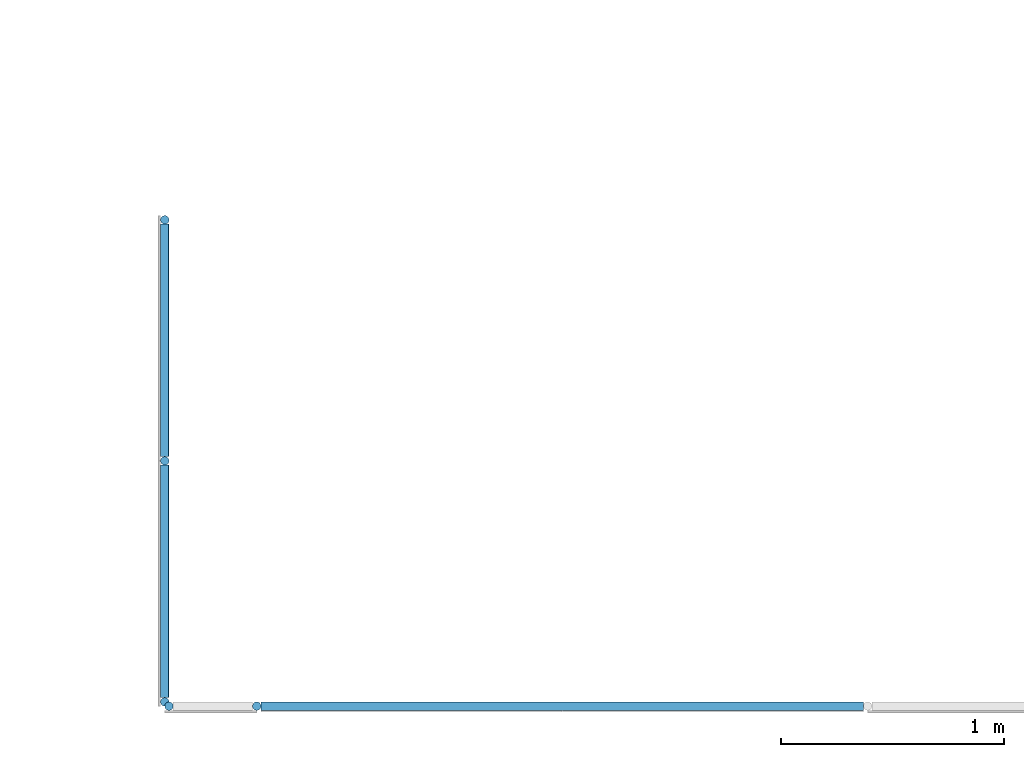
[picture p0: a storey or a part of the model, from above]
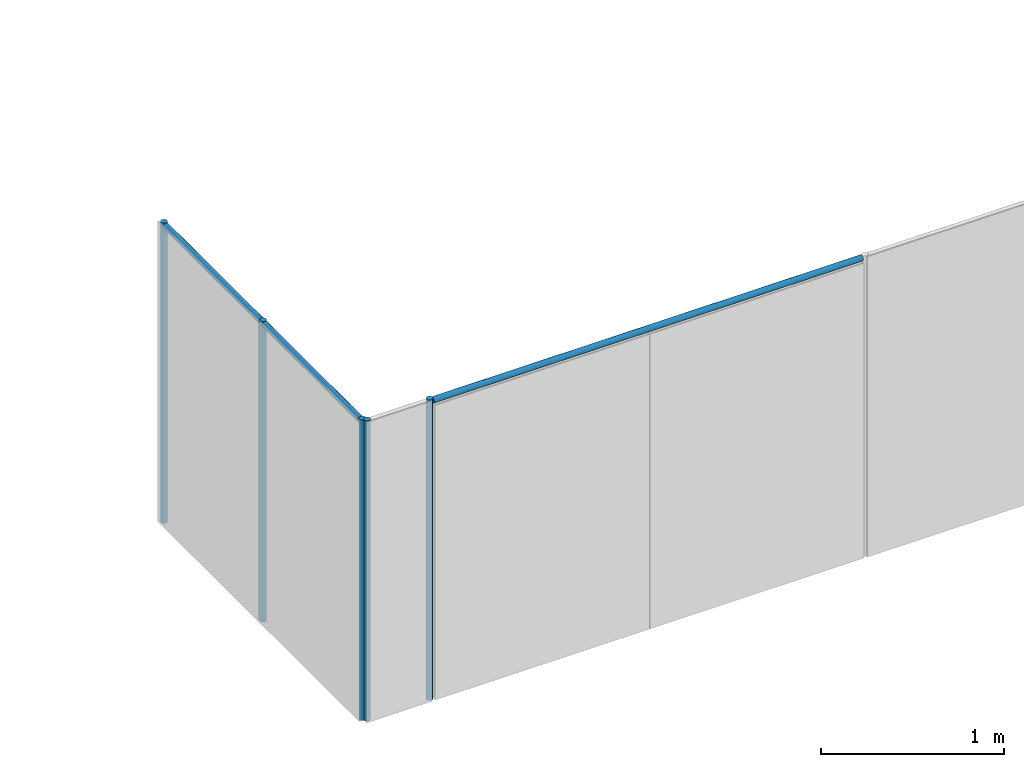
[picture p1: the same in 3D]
Properties of the parts of a building model (IFC2X3), part 1 of 11

# File
Description: ViewDefinition [CoordinationView]
File name: Project Number
Time: 2011-09-06T11:22:43
Written by: Autodesk Revit Architecture 2011 - 1.0
Made in: 20100326_1700 (Solibri IFC Optimizer)

# IfcProject, Project Number
Phase: Project Status

# IfcSite, Default
RefLatitude: 42, 21, 30, 344238; RefLongitude: -71, -3, -35, -194702; RefElevation: 0 m

# IfcBuilding
Pset_BuildingCommon - NumberOfStoreys: 4
PSet_Revit_Other - Project Issue Date: Issue Date; Project Status: Project Status; Client Name: Owner; Project Address: Enter address here; Project Name: Project Name; Project Number: Project Number; Category Description: OmniClass Table 11 Description; Category Code: OmniClass Table 11 Code

# IfcBuildingStorey (4)
PSet_Revit_Type_Dimensions - Automatic Room Computation Height: yes
PSet_Revit_Type_Graphics - Line Weight: 1; Color: 0; Line Pattern: Centre; Symbol: M_Level Head - Circle; Symbol at End 1 Default: no; Symbol at End 2 Default: yes
PSet_Revit_Type_Constraints - Elevation Base: 0
Name | Elevation (m) | Name | PSet_Revit_Constraints, Elevation (m) | Category Code
First Floor | -3.5315e-13 | First Floor | 0 | Floor
Second Floor | 4.57 | Second Floor | 4.57 | Floor
Roof - Main | 9.25 | Roof - Main | 9.25 | Roof
TOF Footing | -1 | TOF Footing | -1 | Site

# IfcSpace (269)
InteriorOrExteriorSpace: INTERNAL
PSet_Revit_Phasing - Phase: New Construction
PSet_Revit_Other - RoomTag: RoomTag
Name | In | LongName = Name | Level | Upper Limit | Limit Offset (m) | Base Offset (m) | GSA BIM Area (m2) = Area (m2) | Number | OmniClass Table 13 Category | Perimeter (m) | Unbounded Height (m) | Volume (m3) | Category Description | Category Code | CirculationZoneName | FireAlarmZoneName | HistoricPreservationZoneName | LightingZoneName | OccupancyZoneName | VentilationZoneName
1AC1 | First Floor | CENTRAL WAITING | First Floor | Second Floor | 0 | 0 | 139.755 | 1AC1 | 13-51 31 11: Waiting Room | 75.3209 | 4.57 | 625.159 | Waiting Room | 13-51 31 11 | Circulation Zone 1A | Fire Alarm Zone 1A | Historic Preservation Zone 1A | Lighting Zone 1A | Occupancy Zone 1A | Ventilation Zone 1A
1DC1 | First Floor | WAITING / ACTIVITY AREA | First Floor | Second Floor | 0 | 0 | 182.28 | 1DC1 | 13-51 31 11: Waiting Room | 80.656 | 4.57 | 814.452 | Waiting Room | 13-51 31 11 | Circulation Zone 1D | Fire Alarm Zone 1D | Historic Preservation Zone 1D | Lighting Zone 1D | Occupancy Zone 1D | Ventilation Zone 1D
2R02 | Second Floor | ROOF | Second Floor | Second Floor | 4 | 0 | 589.756 | 2R02 | 13-81 11 99: Other General Facility Service Spaces | 194.084 | 4 | 2314.97 | Other General Facility Service Spaces | 13-81 11 99 | Circulation Zone 2R | Fire Alarm Zone 2R | Historic Preservation Zone 2R | Lighting Zone 2R | Occupancy Zone 2R | Ventilation Zone 2R
3R01 | Roof - Main | ROOF | Roof - Main | Roof - Main | 4 | 0 | 1568.12 | 3R01 | 13-81 11 99: Other General Facility Service Spaces | 277.051 | 4 | 6257.34 | Other General Facility Service Spaces | 13-81 11 99 | Circulation Zone 3R | Fire Alarm Zone 3R | Historic Preservation Zone 3R | Lighting Zone 3R | Occupancy Zone 3R | Ventilation Zone 3R
1EC1 | First Floor | CORRIDOR | First Floor | First Floor | 2.8 | 0 | 54.6837 | 1EC1 | 13-85 11 11: Corridor | 63.909 | 2.8 | 142.662 | Corridor | 13-85 11 11 | Circulation Zone 1E | Fire Alarm Zone 1E | Historic Preservation Zone 1E | Lighting Zone 1E | Occupancy Zone 1E | Ventilation Zone 1E
2D05 | Second Floor | MAIN MECHANICAL ROOM | Second Floor | Second Floor | 2.8 | 0 | 231.114 | 2D05 | 13-81 21 17: Mechanical Room | 65.482 | 2.8 | 632.921 | Mechanical Room | 13-81 21 17 | Circulation Zone 2D | Fire Alarm Zone 2D | Historic Preservation Zone 2D | Lighting Zone 2D | Occupancy Zone 2D | Ventilation Zone 2D
2AC3 | Second Floor | CORRIDOR | Second Floor | Second Floor | 2.8 | 0 | 27.093 | 2AC3 | 13-85 11 11: Corridor | 33.5372 | 2.8 | 71.9794 | Corridor | 13-85 11 11 | Circulation Zone 2A | Fire Alarm Zone 2A | Historic Preservation Zone 2A | Lighting Zone 2A | Occupancy Zone 2A | Ventilation Zone 2A
2D18 | Second Floor | TECH. OFFICE | Second Floor | Second Floor | 2.8 | 0 | 84.8029 | 2D18 | 13-15 11 34 11: Office | 45.572 | 2.8 | 229.85 | Office | 13-15 11 34 11 | Circulation Zone 2D | Fire Alarm Zone 2D | Historic Preservation Zone 2D | Lighting Zone 2D | Occupancy Zone 2D | Ventilation Zone 2D
1BC2 | First Floor | CORRIDOR | First Floor | First Floor | 2.8 | 0 | 29.4368 | 1BC2 | 13-85 11 11: Corridor | 36.1589 | 2.8 | 76.4885 | Corridor | 13-85 11 11 | Circulation Zone 1B | Fire Alarm Zone 1B | Historic Preservation Zone 1B | Lighting Zone 1B | Occupancy Zone 1B | Ventilation Zone 1B
1CC1 | First Floor | CORRIDOR | First Floor | First Floor | 2.8 | 0 | 42.6545 | 1CC1 | 13-85 11 11: Corridor | 49.386 | 2.8 | 112.657 | Corridor | 13-85 11 11 | Circulation Zone 1C | Fire Alarm Zone 1C | Historic Preservation Zone 1C | Lighting Zone 1C | Occupancy Zone 1C | Ventilation Zone 1C
1A16 | First Floor | PHARM. DISP. | First Floor | First Floor | 2.8 | 0 | 67.5491 | 1A16 | 13-75 11 11: Storage Room | 42.597 | 2.8 | 182.629 | Storage Room | 13-75 11 11 | Circulation Zone 1A | Fire Alarm Zone 1A | Historic Preservation Zone 1A | Lighting Zone 1A | Occupancy Zone 1A | Ventilation Zone 1A
1B04 | First Floor | LAB | First Floor | First Floor | 2.8 | 0 | 53.5882 | 1B04 | 13-15 11 24 11: Laboratory | 36.948 | 2.8 | 143.346 | Laboratory | 13-15 11 24 11 | Circulation Zone 1B | Fire Alarm Zone 1B | Historic Preservation Zone 1B | Lighting Zone 1B | Occupancy Zone 1B | Ventilation Zone 1B
1DC3 | First Floor | CORRIDOR | First Floor | First Floor | 2.8 | 0 | 31.8109 | 1DC3 | 13-85 11 11: Corridor | 38.1194 | 2.8 | 83.0333 | Corridor | 13-85 11 11 | Circulation Zone 1D | Fire Alarm Zone 1D | Historic Preservation Zone 1D | Lighting Zone 1D | Occupancy Zone 1D | Ventilation Zone 1D
1C18 | First Floor | PHYSICAL EXAM | First Floor | First Floor | 2.8 | 0 | 58.0301 | 1C18 | 13-41 41 14: Physical Examination Room | 41.077 | 2.8 | 155.057 | Physical Examination Room | 13-41 41 14 | Circulation Zone 1C | Fire Alarm Zone 1C | Historic Preservation Zone 1C | Lighting Zone 1C | Occupancy Zone 1C | Ventilation Zone 1C
1BC4 | First Floor | CORRIDOR | First Floor | First Floor | 2.8 | 0 | 44.3648 | 1BC4 | 13-85 11 11: Corridor | 44.8858 | 2.8 | 116.82 | Corridor | 13-85 11 11 | Circulation Zone 1B | Fire Alarm Zone 1B | Historic Preservation Zone 1B | Lighting Zone 1B | Occupancy Zone 1B | Ventilation Zone 1B
2BC5 | Second Floor | CORRIDOR | Second Floor | Second Floor | 2.8 | 0 | 22.7376 | 2BC5 | 13-85 11 11: Corridor | 29.2148 | 2.8 | 58.6367 | Corridor | 13-85 11 11 | Circulation Zone 2B | Fire Alarm Zone 2B | Historic Preservation Zone 2B | Lighting Zone 2B | Occupancy Zone 2B | Ventilation Zone 2B
2BC3 | Second Floor | CORRIDOR | Second Floor | Second Floor | 2.8 | 0 | 26.8 | 2BC3 | 13-85 11 11: Corridor | 32.8839 | 2.8 | 69.7845 | Corridor | 13-85 11 11 | Circulation Zone 2B | Fire Alarm Zone 2B | Historic Preservation Zone 2B | Lighting Zone 2B | Occupancy Zone 2B | Ventilation Zone 2B
2AC1 | Second Floor | CORRIDOR | Second Floor | Roof - Main | 0 | 0 | 39.5583 | 2AC1 | 13-85 11 11: Corridor | 31.383 | 4.68 | 181.862 | Corridor | 13-85 11 11 | Circulation Zone 2A | Fire Alarm Zone 2A | Historic Preservation Zone 2A | Lighting Zone 2A | Occupancy Zone 2A | Ventilation Zone 2A
1E24 | First Floor | RECEIVING / STORAGE | First Floor | First Floor | 2.8 | 0 | 118.296 | 1E24 | 13-75 11 11: Storage Room | 48.0138 | 2.8 | 322.336 | Storage Room | 13-75 11 11 | Circulation Zone 1E | Fire Alarm Zone 1E | Historic Preservation Zone 1E | Lighting Zone 1E | Occupancy Zone 1E | Ventilation Zone 1E
1E16 | First Floor | BMET WORK STATION | First Floor | First Floor | 2.8 | 0 | 49.5978 | 1E16 | 13-15 11 34 11: Office | 30.9915 | 2.8 | 130.847 | Office | 13-15 11 34 11 | Circulation Zone 1E | Fire Alarm Zone 1E | Historic Preservation Zone 1E | Lighting Zone 1E | Occupancy Zone 1E | Ventilation Zone 1E
1DC7 | First Floor | CORRIDOR | First Floor | First Floor | 2.8 | 0 | 31.9069 | 1DC7 | 13-85 11 11: Corridor | 37.8435 | 2.8 | 83.5098 | Corridor | 13-85 11 11 | Circulation Zone 1D | Fire Alarm Zone 1D | Historic Preservation Zone 1D | Lighting Zone 1D | Occupancy Zone 1D | Ventilation Zone 1D
1D16 | First Floor | PROVIDER CUBICLES | First Floor | First Floor | 2.8 | 0 | 67.8336 | 1D16 | 13-15 11 34 11: Office | 36.731 | 2.8 | 182.732 | Office | 13-15 11 34 11 | Circulation Zone 1D | Fire Alarm Zone 1D | Historic Preservation Zone 1D | Lighting Zone 1D | Occupancy Zone 1D | Ventilation Zone 1D
2BC2 | Second Floor | CORRIDOR | Second Floor | Second Floor | 2.8 | 0 | 29.512 | 2BC2 | 13-85 11 11: Corridor | 32.1099 | 2.8 | 77.2557 | Corridor | 13-85 11 11 | Circulation Zone 2B | Fire Alarm Zone 2B | Historic Preservation Zone 2B | Lighting Zone 2B | Occupancy Zone 2B | Ventilation Zone 2B
1CC3 | First Floor | CORRIDOR | First Floor | First Floor | 2.8 | 0 | 11.4965 | 1CC3 | 13-85 11 11: Corridor | 15.7842 | 2.8 | 29.7028 | Corridor | 13-85 11 11 | Circulation Zone 1C | Fire Alarm Zone 1C | Historic Preservation Zone 1C | Lighting Zone 1C | Occupancy Zone 1C | Ventilation Zone 1C
2A11 | Second Floor | DENTAL WAITING | Second Floor | Second Floor | 2.8 | 0 | 33.4834 | 2A11 | 13-51 31 11: Waiting Room | 29.0513 | 2.8 | 88.9215 | Waiting Room | 13-51 31 11 | Circulation Zone 2A | Fire Alarm Zone 2A | Historic Preservation Zone 2A | Lighting Zone 2A | Occupancy Zone 2A | Ventilation Zone 2A
2CC3 | Second Floor | CORRIDOR | Second Floor | Second Floor | 2.8 | 0 | 17.2506 | 2CC3 | 13-85 11 11: Corridor | 22.3132 | 2.8 | 45.0359 | Corridor | 13-85 11 11 | Circulation Zone 2C | Fire Alarm Zone 2C | Historic Preservation Zone 2C | Lighting Zone 2C | Occupancy Zone 2C | Ventilation Zone 2C
1AC5 | First Floor | CORRIDOR | First Floor | First Floor | 2.8 | 0 | 20.3751 | 1AC5 | 13-85 11 11: Corridor | 32.975 | 2.8 | 53.8137 | Corridor | 13-85 11 11 | Circulation Zone 1A | Fire Alarm Zone 1A | Historic Preservation Zone 1A | Lighting Zone 1A | Occupancy Zone 1A | Ventilation Zone 1A
2DC2 | Second Floor | CORRIDOR | Second Floor | Second Floor | 2.8 | 0 | 30.1132 | 2DC2 | 13-85 11 11: Corridor | 36.3978 | 2.8 | 79.4525 | Corridor | 13-85 11 11 | Circulation Zone 2D | Fire Alarm Zone 2D | Historic Preservation Zone 2D | Lighting Zone 2D | Occupancy Zone 2D | Ventilation Zone 2D
1AC3 | First Floor | CORRIDOR | First Floor | First Floor | 2.8 | 0 | 16.2935 | 1AC3 | 13-85 11 11: Corridor | 21.4955 | 2.8 | 42.0234 | Corridor | 13-85 11 11 | Circulation Zone 1A | Fire Alarm Zone 1A | Historic Preservation Zone 1A | Lighting Zone 1A | Occupancy Zone 1A | Ventilation Zone 1A
2C17 | Second Floor | PROSTH. LAB | Second Floor | Second Floor | 2.8 | 0 | 30.5599 | 2C17 | 13-15 11 24 11: Laboratory | 25.496 | 2.8 | 80.0399 | Laboratory | 13-15 11 24 11 | Circulation Zone 2C | Fire Alarm Zone 2C | Historic Preservation Zone 2C | Lighting Zone 2C | Occupancy Zone 2C | Ventilation Zone 2C
1D25 | First Floor | PROVIDER CUBICLES | First Floor | First Floor | 2.8 | 0 | 67.8191 | 1D25 | 13-15 11 34 11: Office | 36.627 | 2.8 | 182.56 | Office | 13-15 11 34 11 | Circulation Zone 1D | Fire Alarm Zone 1D | Historic Preservation Zone 1D | Lighting Zone 1D | Occupancy Zone 1D | Ventilation Zone 1D
2CC2 | Second Floor | CORRIDOR | Second Floor | Second Floor | 2.8 | 0 | 13.3735 | 2CC2 | 13-85 11 11: Corridor | 18.1884 | 2.8 | 34.7761 | Corridor | 13-85 11 11 | Circulation Zone 2C | Fire Alarm Zone 2C | Historic Preservation Zone 2C | Lighting Zone 2C | Occupancy Zone 2C | Ventilation Zone 2C
1DC6 | First Floor | CORRIDOR | First Floor | First Floor | 2.8 | 0 | 15.0065 | 1DC6 | 13-85 11 11: Corridor | 20.1568 | 2.8 | 38.8805 | Corridor | 13-85 11 11 | Circulation Zone 1D | Fire Alarm Zone 1D | Historic Preservation Zone 1D | Lighting Zone 1D | Occupancy Zone 1D | Ventilation Zone 1D
2AC4 | Second Floor | CORRIDOR | Second Floor | Second Floor | 2.8 | 0 | 14.3235 | 2AC4 | 13-85 11 11: Corridor | 19.474 | 2.8 | 37.5506 | Corridor | 13-85 11 11 | Circulation Zone 2A | Fire Alarm Zone 2A | Historic Preservation Zone 2A | Lighting Zone 2A | Occupancy Zone 2A | Ventilation Zone 2A
2B3 | Second Floor | CONF. / GROUP THERAPY | Second Floor | Second Floor | 2.8 | 0 | 24.5482 | 2B3 | 13-11 21 17: Conference Room | 28.9479 | 2.8 | 63.2337 | Conference Room | 13-11 21 17 | Circulation Zone 2B | Fire Alarm Zone 2B | Historic Preservation Zone 2B | Lighting Zone 2B | Occupancy Zone 2B | Ventilation Zone 2B
2C07 | Second Floor | M. STAFF TOILET | Second Floor | Second Floor | 2.8 | 0 | 18.2427 | 2C07 | 13-41 11 14 21: Restroom | 27.3188 | 2.8 | 46.0968 | Restroom | 13-41 11 14 21 | Circulation Zone 2C | Fire Alarm Zone 2C | Historic Preservation Zone 2C | Lighting Zone 2C | Occupancy Zone 2C | Ventilation Zone 2C
2CC1 | Second Floor | CORRIDOR | Second Floor | Second Floor | 2.8 | 0 | 18.813 | 2CC1 | 13-85 11 11: Corridor | 23.5826 | 2.8 | 48.7709 | Corridor | 13-85 11 11 | Circulation Zone 2C | Fire Alarm Zone 2C | Historic Preservation Zone 2C | Lighting Zone 2C | Occupancy Zone 2C | Ventilation Zone 2C
1DC4 | First Floor | CORRIDOR | First Floor | First Floor | 2.8 | 0 | 15.0608 | 1DC4 | 13-85 11 11: Corridor | 20.1242 | 2.8 | 39.4804 | Corridor | 13-85 11 11 | Circulation Zone 1D | Fire Alarm Zone 1D | Historic Preservation Zone 1D | Lighting Zone 1D | Occupancy Zone 1D | Ventilation Zone 1D
2AC1-A | Second Floor | OPEN TO BELOW | Second Floor | Second Floor | 2.8 | 0 | 67.4123 | 2AC1-A | 13-85 31 99: Other Transitional Circulation Spaces | 37.7705 | 2.8 | 183.363 | Other Transitional Circulation Spaces | 13-85 31 99 | Circulation Zone 2A | Fire Alarm Zone 2A | Historic Preservation Zone 2A | Lighting Zone 2A | Occupancy Zone 2A | Ventilation Zone 2A
2C08 | Second Floor | W. STAFF TOILET | Second Floor | Second Floor | 2.8 | 0 | 15.7322 | 2C08 | 13-41 11 14 21: Restroom | 21.984 | 2.8 | 39.9607 | Restroom | 13-41 11 14 21 | Circulation Zone 2C | Fire Alarm Zone 2C | Historic Preservation Zone 2C | Lighting Zone 2C | Occupancy Zone 2C | Ventilation Zone 2C
1E06 | First Floor | TECH. WORK STATION | First Floor | First Floor | 2.8 | 0 | 37.3792 | 1E06 | 13-15 11 34 11: Office | 24.978 | 2.8 | 100.456 | Office | 13-15 11 34 11 | Circulation Zone 1E | Fire Alarm Zone 1E | Historic Preservation Zone 1E | Lighting Zone 1E | Occupancy Zone 1E | Ventilation Zone 1E
2AC1-B | Second Floor | OPEN TO BELOW | Second Floor | Roof - Main | 0 | 0 | 75.807 | 2AC1-B | 13-85 31 99: Other Transitional Circulation Spaces | 35.407 | 4.68 | 348.032 | Other Transitional Circulation Spaces | 13-85 31 99 | Circulation Zone 2A | Fire Alarm Zone 2A | Historic Preservation Zone 2A | Lighting Zone 2A | Occupancy Zone 2A | Ventilation Zone 2A
2CC4 | Second Floor | CORRIDOR | Second Floor | Second Floor | 2.8 | 0 | 10.846 | 2CC4 | 13-85 11 11: Corridor | 14.568 | 2.8 | 28.1375 | Corridor | 13-85 11 11 | Circulation Zone 2C | Fire Alarm Zone 2C | Historic Preservation Zone 2C | Lighting Zone 2C | Occupancy Zone 2C | Ventilation Zone 2C
1D22 | First Floor | TEAM INTERACTION | First Floor | First Floor | 2.8 | 0 | 24.237 | 1D22 | 13-15 11 34 11: Office | 20.765 | 2.8 | 63.1427 | Office | 13-15 11 34 11 | Circulation Zone 1D | Fire Alarm Zone 1D | Historic Preservation Zone 1D | Lighting Zone 1D | Occupancy Zone 1D | Ventilation Zone 1D
2BC4 | Second Floor | CORRIDOR | Second Floor | Second Floor | 2.8 | 0 | 12.4825 | 2BC4 | 13-85 11 11: Corridor | 16.6806 | 2.8 | 32.3314 | Corridor | 13-85 11 11 | Circulation Zone 2B | Fire Alarm Zone 2B | Historic Preservation Zone 2B | Lighting Zone 2B | Occupancy Zone 2B | Ventilation Zone 2B
1B13 | First Floor | RECEPTION | First Floor | First Floor | 2.8 | 0 | 22.5898 | 1B13 | 13-11 11 31: Reception Space | 21.5613 | 2.8 | 60.089 | Reception Space | 13-11 11 31 | Circulation Zone 1B | Fire Alarm Zone 1B | Historic Preservation Zone 1B | Lighting Zone 1B | Occupancy Zone 1B | Ventilation Zone 1B
1B01 | First Floor | RECEPTION | First Floor | First Floor | 2.8 | 0 | 9.47555 | 1B01 | 13-11 11 31: Reception Space | 12.664 | 2.8 | 24.6632 | Reception Space | 13-11 11 31 | Circulation Zone 1B | Fire Alarm Zone 1B | Historic Preservation Zone 1B | Lighting Zone 1B | Occupancy Zone 1B | Ventilation Zone 1B
2D04 | Second Floor | SYS. ANALYST | Second Floor | Second Floor | 2.8 | 0 | 20.7007 | 2D04 | 13-15 11 34 11: Office | 19.9515 | 2.8 | 54.4353 | Office | 13-15 11 34 11 | Circulation Zone 2D | Fire Alarm Zone 2D | Historic Preservation Zone 2D | Lighting Zone 2D | Occupancy Zone 2D | Ventilation Zone 2D
2C03 | Second Floor | CONSULT. | Second Floor | Second Floor | 2.8 | 0 | 33.4926 | 2C03 | 13-41 41 99: Other Healing Spaces | 28.4362 | 2.8 | 89.4233 | Other Healing Spaces | 13-41 41 99 | Circulation Zone 2C | Fire Alarm Zone 2C | Historic Preservation Zone 2C | Lighting Zone 2C | Occupancy Zone 2C | Ventilation Zone 2C
1A02 | First Floor | RMO ANALYST | First Floor | First Floor | 2.8 | 0 | 27.6932 | 1A02 | 13-15 11 34 11: Office | 26.5002 | 2.8 | 74.6419 | Office | 13-15 11 34 11 | Circulation Zone 1A | Fire Alarm Zone 1A | Historic Preservation Zone 1A | Lighting Zone 1A | Occupancy Zone 1A | Ventilation Zone 1A
1C07 | First Floor | OPT. EXAM / OFF. | First Floor | First Floor | 2.8 | 0 | 17.5712 | 1C07 | 13-15 11 34 11: Office | 20.7032 | 2.8 | 45.6483 | Office | 13-15 11 34 11 | Circulation Zone 1C | Fire Alarm Zone 1C | Historic Preservation Zone 1C | Lighting Zone 1C | Occupancy Zone 1C | Ventilation Zone 1C
1AC2 | First Floor | CORRIDOR | First Floor | First Floor | 2.8 | 0 | 19.605 | 1AC2 | 13-85 11 11: Corridor | 24.0652 | 2.8 | 53.4757 | Corridor | 13-85 11 11 | Circulation Zone 1A | Fire Alarm Zone 1A | Historic Preservation Zone 1A | Lighting Zone 1A | Occupancy Zone 1A | Ventilation Zone 1A
1CS3 | First Floor | STAIR | First Floor | First Floor | 2.8 | 0 | 13.9094 | 1CS3 | 13-85 21 11: Stairway | 18.996 | 2.8 | 35.7133 | Stairway | 13-85 21 11 | Circulation Zone 1C | Fire Alarm Zone 1C | Historic Preservation Zone 1C | Lighting Zone 1C | Occupancy Zone 1C | Ventilation Zone 1C
2DC1 | Second Floor | CORRIDOR | Second Floor | Second Floor | 2.8 | 0 | 21.5518 | 2DC1 | 13-85 11 11: Corridor | 26.2857 | 2.8 | 56.4026 | Corridor | 13-85 11 11 | Circulation Zone 2D | Fire Alarm Zone 2D | Historic Preservation Zone 2D | Lighting Zone 2D | Occupancy Zone 2D | Ventilation Zone 2D
2AC2 | Second Floor | CORRIDOR | Second Floor | Second Floor | 2.8 | 0 | 15.0174 | 2AC2 | 13-85 11 11: Corridor | 21.167 | 2.8 | 38.9924 | Corridor | 13-85 11 11 | Circulation Zone 2A | Fire Alarm Zone 2A | Historic Preservation Zone 2A | Lighting Zone 2A | Occupancy Zone 2A | Ventilation Zone 2A
2A01 | Second Floor | LIBRARY / CONF. ROOM | Second Floor | Second Floor | 2.8 | 0 | 26.331 | 2A01 | 13-11 21 17: Conference Room | 21.7164 | 2.8 | 69.7917 | Conference Room | 13-11 21 17 | Circulation Zone 2A | Fire Alarm Zone 2A | Historic Preservation Zone 2A | Lighting Zone 2A | Occupancy Zone 2A | Ventilation Zone 2A
2CC5 | Second Floor | CORRIDOR | Second Floor | Second Floor | 4 | 0 | 8.1288 | 2CC5 | 13-85 11 11: Corridor | 12.632 | 4 | 29.6709 | Corridor | 13-85 11 11 | Circulation Zone 2C | Fire Alarm Zone 2C | Historic Preservation Zone 2C | Lighting Zone 2C | Occupancy Zone 2C | Ventilation Zone 2C
3D01 | Roof - Main | MECH. PENTHOUSE | Roof - Main | Roof - Main | 3.4 | 0 | 64.8322 | 3D01 | 13-81 21 17: Mechanical Room | 35.3365 | 3.4 | 206.555 | Mechanical Room | 13-81 21 17 | Circulation Zone 2D | Fire Alarm Zone 2D | Historic Preservation Zone 2D | Lighting Zone 2D | Occupancy Zone 2D | Ventilation Zone 2D
3AC1 | Roof - Main | OPEN TO BELOW | Roof - Main | Roof - Main | 3.4 | 0 | 99.1595 | 3AC1 | 13-85 31 99: Other Transitional Circulation Spaces | 40.4838 | 3.4 | 324.616 | Other Transitional Circulation Spaces | 13-85 31 99 | Circulation Zone 2D | Fire Alarm Zone 2D | Historic Preservation Zone 2D | Lighting Zone 2D | Occupancy Zone 2D | Ventilation Zone 2D
1A10 | First Floor | LOUNGE | First Floor | First Floor | 2.8 | 0 | 10.2725 | 1A10 | 13-51 11 21: Break Room | 14.38 | 2.8 | 26.6537 | Break Room | 13-51 11 21 | Circulation Zone 1A | Fire Alarm Zone 1A | Historic Preservation Zone 1A | Lighting Zone 1A | Occupancy Zone 1A | Ventilation Zone 1A
2C12 | Second Floor | DIPC CLEAN | Second Floor | Second Floor | 2.8 | 0 | 14.3677 | 2C12 | 13-41 41 99: Other Healing Spaces | 18.173 | 2.8 | 37.1189 | Other Healing Spaces | 13-41 41 99 | Circulation Zone 2C | Fire Alarm Zone 2C | Historic Preservation Zone 2C | Lighting Zone 2C | Occupancy Zone 2C | Ventilation Zone 2C
2A14 | Second Floor | ADMIN | Second Floor | Second Floor | 2.8 | 0 | 32.8384 | 2A14 | 13-15 11 34 11: Office | 24.7893 | 2.8 | 88.1956 | Office | 13-15 11 34 11 | Circulation Zone 2A | Fire Alarm Zone 2A | Historic Preservation Zone 2A | Lighting Zone 2A | Occupancy Zone 2A | Ventilation Zone 2A
1D40 | First Floor | IMMUNIZ'N ROOM | First Floor | First Floor | 2.8 | 0 | 16.5524 | 1D40 | 13-41 41 99: Other Healing Spaces | 19.222 | 2.8 | 43.1197 | Other Healing Spaces | 13-41 41 99 | Circulation Zone 1D | Fire Alarm Zone 1D | Historic Preservation Zone 1D | Lighting Zone 1D | Occupancy Zone 1D | Ventilation Zone 1D
2A05 | Second Floor | OH DTR #1 | Second Floor | Second Floor | 2.8 | 0 | 11.3331 | 2A05 | 13-41 41 99: Other Healing Spaces | 13.8601 | 2.8 | 29.4101 | Other Healing Spaces | 13-41 41 99 | Circulation Zone 2A | Fire Alarm Zone 2A | Historic Preservation Zone 2A | Lighting Zone 2A | Occupancy Zone 2A | Ventilation Zone 2A
1AC4 | First Floor | CORRIDOR | First Floor | First Floor | 2.8 | 0 | 9.55147 | 1AC4 | 13-85 11 11: Corridor | 13.7932 | 2.8 | 24.639 | Corridor | 13-85 11 11 | Circulation Zone 1A | Fire Alarm Zone 1A | Historic Preservation Zone 1A | Lighting Zone 1A | Occupancy Zone 1A | Ventilation Zone 1A
2A13 | Second Floor | DEVELOPING | Second Floor | Second Floor | 2.8 | 0 | 7.5623 | 2A13 | 13-41 41 31: Scanning/Imaging Room | 11.778 | 2.8 | 19.2781 | Scanning/Imaging Room | 13-41 41 31 | Circulation Zone 2A | Fire Alarm Zone 2A | Historic Preservation Zone 2A | Lighting Zone 2A | Occupancy Zone 2A | Ventilation Zone 2A
2A12 | Second Floor | X-RAY | Second Floor | Second Floor | 2.8 | 0 | 11.2172 | 2A12 | 13-41 41 31: Scanning/Imaging Room | 14.3622 | 2.8 | 28.9599 | Scanning/Imaging Room | 13-41 41 31 | Circulation Zone 2A | Fire Alarm Zone 2A | Historic Preservation Zone 2A | Lighting Zone 2A | Occupancy Zone 2A | Ventilation Zone 2A
1D11 | First Floor | INTERACTION STATION | First Floor | First Floor | 2.8 | 0 | 12.698 | 1D11 | 13-41 41 99: Other Healing Spaces | 14.779 | 2.8 | 33.249 | Other Healing Spaces | 13-41 41 99 | Circulation Zone 1D | Fire Alarm Zone 1D | Historic Preservation Zone 1D | Lighting Zone 1D | Occupancy Zone 1D | Ventilation Zone 1D
2D11 | Second Floor | CMDR OFFICE | Second Floor | Second Floor | 2.8 | 0 | 15.8554 | 2D11 | 13-15 11 34 11: Office | 16.0179 | 2.8 | 40.5592 | Office | 13-15 11 34 11 | Circulation Zone 2D | Fire Alarm Zone 2D | Historic Preservation Zone 2D | Lighting Zone 2D | Occupancy Zone 2D | Ventilation Zone 2D
2C22 | Second Floor | LOUNGE | Second Floor | Second Floor | 2.8 | 0 | 11.1646 | 2C22 | 13-51 11 21: Break Room | 13.8043 | 2.8 | 28.9074 | Break Room | 13-51 11 21 | Circulation Zone 2C | Fire Alarm Zone 2C | Historic Preservation Zone 2C | Lighting Zone 2C | Occupancy Zone 2C | Ventilation Zone 2C
1E15 | First Floor | CENTRAL MECH. RM. | First Floor | First Floor | 2.8 | 0 | 28.9142 | 1E15 | 13-81 21 17: Mechanical Room | 24.1165 | 2.8 | 76.0404 | Mechanical Room | 13-81 21 17 | Circulation Zone 1E | Fire Alarm Zone 1E | Historic Preservation Zone 1E | Lighting Zone 1E | Occupancy Zone 1E | Ventilation Zone 1E
1B10 | First Floor | STAFF LOUNGE | First Floor | First Floor | 2.8 | 0 | 10.2834 | 1B10 | 13-51 11 21: Break Room | 13.649 | 2.8 | 26.3383 | Break Room | 13-51 11 21 | Circulation Zone 1B | Fire Alarm Zone 1B | Historic Preservation Zone 1B | Lighting Zone 1B | Occupancy Zone 1B | Ventilation Zone 1B
1C09 | First Floor | FUNDUS CAMERA ROOM | First Floor | First Floor | 2.8 | 0 | 14.9278 | 1C09 | 13-41 41 31: Scanning/Imaging Room | 16.234 | 2.8 | 38.5611 | Scanning/Imaging Room | 13-41 41 31 | Circulation Zone 1C | Fire Alarm Zone 1C | Historic Preservation Zone 1C | Lighting Zone 1C | Occupancy Zone 1C | Ventilation Zone 1C
2B25 | Second Floor | SOIL. UTL. / TRASH | Second Floor | Second Floor | 2.8 | 0 | 7.46369 | 2B25 | 13-75 41 14: Soiled Storage Room Space | 13.21 | 2.8 | 18.8314 | Soiled Storage Room Space | 13-75 41 14 | Circulation Zone 2B | Fire Alarm Zone 2B | Historic Preservation Zone 2B | Lighting Zone 2B | Occupancy Zone 2B | Ventilation Zone 2B
1EC4 | First Floor | CORRIDOR | First Floor | First Floor | 2.8 | 0 | 9.30567 | 1EC4 | 13-85 11 11: Corridor | 12.6514 | 2.8 | 23.6975 | Corridor | 13-85 11 11 | Circulation Zone 1E | Fire Alarm Zone 1E | Historic Preservation Zone 1E | Lighting Zone 1E | Occupancy Zone 1E | Ventilation Zone 1E
1E19 | First Floor | ELEC. ROOM | First Floor | First Floor | 2.8 | 0 | 9.6262 | 1E19 | 13-81 21 21: Electrical Room | 12.686 | 2.8 | 24.8866 | Electrical Room | 13-81 21 21 | Circulation Zone 1E | Fire Alarm Zone 1E | Historic Preservation Zone 1E | Lighting Zone 1E | Occupancy Zone 1E | Ventilation Zone 1E
1E23 | First Floor | BEE EQUIP. STORAGE | First Floor | First Floor | 2.8 | 0 | 8.77894 | 1E23 | 13-81 21 11: Equipment Room | 12.981 | 2.8 | 22.5535 | Equipment Room | 13-81 21 11 | Circulation Zone 1E | Fire Alarm Zone 1E | Historic Preservation Zone 1E | Lighting Zone 1E | Occupancy Zone 1E | Ventilation Zone 1E
1B19 | First Floor | RADIOGRAPHIC ROOM | First Floor | First Floor | 2.8 | 0 | 29.9132 | 1B19 | 13-41 41 99: Other Healing Spaces | 28.5508 | 2.8 | 79.0515 | Other Healing Spaces | 13-41 41 99 | Circulation Zone 1B | Fire Alarm Zone 1B | Historic Preservation Zone 1B | Lighting Zone 1B | Occupancy Zone 1B | Ventilation Zone 1B
1DC8 | First Floor | CORRIDOR | First Floor | First Floor | 2.8 | 0 | 6.29243 | 1DC8 | 13-85 11 11: Corridor | 10.6091 | 2.8 | 16.4607 | Corridor | 13-85 11 11 | Circulation Zone 1D | Fire Alarm Zone 1D | Historic Preservation Zone 1D | Lighting Zone 1D | Occupancy Zone 1D | Ventilation Zone 1D
1BC1 | First Floor | CORRIDOR | First Floor | First Floor | 2.8 | 0 | 5.69274 | 1BC1 | 13-85 11 11: Corridor | 9.876 | 2.8 | 14.2682 | Corridor | 13-85 11 11 | Circulation Zone 1B | Fire Alarm Zone 1B | Historic Preservation Zone 1B | Lighting Zone 1B | Occupancy Zone 1B | Ventilation Zone 1B
1E11 | First Floor | STAFF LOUNGE | First Floor | First Floor | 2.8 | 0 | 14.5917 | 1E11 | 13-51 11 21: Break Room | 15.28 | 2.8 | 38.2473 | Break Room | 13-51 11 21 | Circulation Zone 1E | Fire Alarm Zone 1E | Historic Preservation Zone 1E | Lighting Zone 1E | Occupancy Zone 1E | Ventilation Zone 1E
2D10 | Second Floor | SEC. WAIT | Second Floor | Second Floor | 2.8 | 0 | 16.632 | 2D10 | 13-51 31 11: Waiting Room | 17.017 | 2.8 | 43.8585 | Waiting Room | 13-51 31 11 | Circulation Zone 2D | Fire Alarm Zone 2D | Historic Preservation Zone 2D | Lighting Zone 2D | Occupancy Zone 2D | Ventilation Zone 2D
1DC2 | First Floor | CORRIDOR | First Floor | First Floor | 2.8 | 0 | 6.34736 | 1DC2 | 13-85 11 11: Corridor | 10.67 | 2.8 | 16.6144 | Corridor | 13-85 11 11 | Circulation Zone 1D | Fire Alarm Zone 1D | Historic Preservation Zone 1D | Lighting Zone 1D | Occupancy Zone 1D | Ventilation Zone 1D
2B01 | Second Floor | OFFICE | Second Floor | Second Floor | 2.8 | 0 | 9.36297 | 2B01 | 13-15 11 34 11: Office | 12.861 | 2.8 | 24.0738 | Office | 13-15 11 34 11 | Circulation Zone 2B | Fire Alarm Zone 2B | Historic Preservation Zone 2B | Lighting Zone 2B | Occupancy Zone 2B | Ventilation Zone 2B
1A07 | First Floor | TRICARE OFFICE | First Floor | First Floor | 2.8 | 0 | 8.73012 | 1A07 | 13-15 11 34 11: Office | 12.5275 | 2.8 | 22.3143 | Office | 13-15 11 34 11 | Circulation Zone 1A | Fire Alarm Zone 1A | Historic Preservation Zone 1A | Lighting Zone 1A | Occupancy Zone 1A | Ventilation Zone 1A
2D16 | Second Floor | RMO DIR. | Second Floor | Second Floor | 2.8 | 0 | 9.75054 | 2D16 | 13-15 11 34 11: Office | 13.1899 | 2.8 | 25.1084 | Office | 13-15 11 34 11 | Circulation Zone 2D | Fire Alarm Zone 2D | Historic Preservation Zone 2D | Lighting Zone 2D | Occupancy Zone 2D | Ventilation Zone 2D
1D18 | First Floor | TOILET | First Floor | First Floor | 2.8 | 0 | 8.26027 | 1D18 | 13-41 11 14 21: Restroom | 12.8768 | 2.8 | 20.6846 | Restroom | 13-41 11 14 21 | Circulation Zone 1D | Fire Alarm Zone 1D | Historic Preservation Zone 1D | Lighting Zone 1D | Occupancy Zone 1D | Ventilation Zone 1D
2B18 | Second Floor | PH TECH | Second Floor | Second Floor | 2.8 | 0 | 9.52429 | 2B18 | 13-15 11 34 11: Office | 13.8569 | 2.8 | 24.248 | Office | 13-15 11 34 11 | Circulation Zone 2B | Fire Alarm Zone 2B | Historic Preservation Zone 2B | Lighting Zone 2B | Occupancy Zone 2B | Ventilation Zone 2B
1B02 | First Floor | SPECIMEN TOILET | First Floor | First Floor | 2.8 | 0 | 5.54853 | 1B02 | 13-41 11 14 21: Restroom | 10.2769 | 2.8 | 13.7311 | Restroom | 13-41 11 14 21 | Circulation Zone 1B | Fire Alarm Zone 1B | Historic Preservation Zone 1B | Lighting Zone 1B | Occupancy Zone 1B | Ventilation Zone 1B
2B11 | Second Floor | WAITING | Second Floor | Second Floor | 2.8 | 0 | 10.1069 | 2B11 | 13-51 31 11: Waiting Room | 12.908 | 2.8 | 26.6698 | Waiting Room | 13-51 31 11 | Circulation Zone 2B | Fire Alarm Zone 2B | Historic Preservation Zone 2B | Lighting Zone 2B | Occupancy Zone 2B | Ventilation Zone 2B
1D32 | First Floor | INTERACTION STATION | First Floor | First Floor | 2.8 | 0 | 12.7483 | 1D32 | 13-41 41 99: Other Healing Spaces | 14.814 | 2.8 | 33.249 | Other Healing Spaces | 13-41 41 99 | Circulation Zone 1D | Fire Alarm Zone 1D | Historic Preservation Zone 1D | Lighting Zone 1D | Occupancy Zone 1D | Ventilation Zone 1D
1D07 | First Floor | INTERACTION STATION | First Floor | First Floor | 2.8 | 0 | 12.5663 | 1D07 | 13-41 41 99: Other Healing Spaces | 14.397 | 2.8 | 32.8761 | Other Healing Spaces | 13-41 41 99 | Circulation Zone 1D | Fire Alarm Zone 1D | Historic Preservation Zone 1D | Lighting Zone 1D | Occupancy Zone 1D | Ventilation Zone 1D
2R01 | Second Floor | ROOF | Second Floor | Second Floor | 4 | 0 | 52.8728 | 2R01 | 13-81 11 99: Other General Facility Service Spaces | 29.706 | 4 | 203.631 | Other General Facility Service Spaces | 13-81 11 99 | Circulation Zone 2R | Fire Alarm Zone 2R | Historic Preservation Zone 2R | Lighting Zone 2R | Occupancy Zone 2R | Ventilation Zone 2R
2C15 | Second Floor | COMM. ROOM | Second Floor | Second Floor | 2.8 | 0 | 9.58001 | 2C15 | 13-15 11 34 11: Office | 12.53 | 2.8 | 24.7051 | Office | 13-15 11 34 11 | Circulation Zone 2C | Fire Alarm Zone 2C | Historic Preservation Zone 2C | Lighting Zone 2C | Occupancy Zone 2C | Ventilation Zone 2C
2D13 | Second Floor | TOILET | Second Floor | Second Floor | 2.8 | 0 | 4.74366 | 2D13 | 13-41 11 14 21: Restroom | 9.012 | 2.8 | 11.7127 | Restroom | 13-41 11 14 21 | Circulation Zone 2D | Fire Alarm Zone 2D | Historic Preservation Zone 2D | Lighting Zone 2D | Occupancy Zone 2D | Ventilation Zone 2D
2C14 | Second Floor | GEN. DENT. DTR #10 | Second Floor | Second Floor | 2.8 | 0 | 12.0102 | 2C14 | 13-41 41 99: Other Healing Spaces | 13.997 | 2.8 | 30.9231 | Other Healing Spaces | 13-41 41 99 | Circulation Zone 2C | Fire Alarm Zone 2C | Historic Preservation Zone 2C | Lighting Zone 2C | Occupancy Zone 2C | Ventilation Zone 2C
1C10 | First Floor | OPT. EXAM / OFF. | First Floor | First Floor | 2.8 | 0 | 18.2545 | 1C10 | 13-15 11 34 11: Office | 20.8688 | 2.8 | 47.5479 | Office | 13-15 11 34 11 | Circulation Zone 1C | Fire Alarm Zone 1C | Historic Preservation Zone 1C | Lighting Zone 1C | Occupancy Zone 1C | Ventilation Zone 1C
1D31 | First Floor | PEDIATRIC WTS & MSRS | First Floor | First Floor | 2.8 | 0 | 11.0208 | 1D31 | 13-41 41 14: Physical Examination Room | 13.719 | 2.8 | 28.612 | Physical Examination Room | 13-41 41 14 | Circulation Zone 1D | Fire Alarm Zone 1D | Historic Preservation Zone 1D | Lighting Zone 1D | Occupancy Zone 1D | Ventilation Zone 1D
1A12 | First Floor | M. TOILET | First Floor | First Floor | 2.8 | 0 | 9.91049 | 1A12 | 13-41 11 14 21: Restroom | 13.184 | 2.8 | 25.6114 | Restroom | 13-41 11 14 21 | Circulation Zone 1A | Fire Alarm Zone 1A | Historic Preservation Zone 1A | Lighting Zone 1A | Occupancy Zone 1A | Ventilation Zone 1A
1E08 | First Floor | SUPER | First Floor | First Floor | 2.8 | 0 | 9.86423 | 1E08 | 13-15 11 34 11: Office | 13.058 | 2.8 | 25.4832 | Office | 13-15 11 34 11 | Circulation Zone 1E | Fire Alarm Zone 1E | Historic Preservation Zone 1E | Lighting Zone 1E | Occupancy Zone 1E | Ventilation Zone 1E
1C02 | First Floor | RECEPTION | First Floor | First Floor | 2.8 | 0 | 9.31934 | 1C02 | 13-11 11 31: Reception Space | 12.2052 | 2.8 | 24.6922 | Reception Space | 13-11 11 31 | Circulation Zone 1C | Fire Alarm Zone 1C | Historic Preservation Zone 1C | Lighting Zone 1C | Occupancy Zone 1C | Ventilation Zone 1C
1D38 | First Floor | TRMT ROOM | First Floor | First Floor | 2.8 | 0 | 23.2605 | 1D38 | 13-41 41 11: Treatment Room | 19.59 | 2.8 | 62.1559 | Treatment Room | 13-41 41 11 | Circulation Zone 1D | Fire Alarm Zone 1D | Historic Preservation Zone 1D | Lighting Zone 1D | Occupancy Zone 1D | Ventilation Zone 1D
2C16 | Second Floor | CERAMIC LAB | Second Floor | Second Floor | 2.8 | 0 | 11.155 | 2C16 | 13-15 11 24 11: Laboratory | 14.018 | 2.8 | 28.386 | Laboratory | 13-15 11 24 11 | Circulation Zone 2C | Fire Alarm Zone 2C | Historic Preservation Zone 2C | Lighting Zone 2C | Occupancy Zone 2C | Ventilation Zone 2C
2D21 | Second Floor | LIBRARY / CLASSROOM | Second Floor | Second Floor | 4 | 0 | 27.3034 | 2D21 | 13-11 11 17: Classroom | 21.2805 | 4 | 105.77 | Classroom | 13-11 11 17 | Circulation Zone 2D | Fire Alarm Zone 2D | Historic Preservation Zone 2D | Lighting Zone 2D | Occupancy Zone 2D | Ventilation Zone 2D
1A15 | First Floor | COUNSELING | First Floor | First Floor | 2.8 | 0 | 6.39843 | 1A15 | 13-41 41 99: Other Healing Spaces | 10.157 | 2.8 | 16.4305 | Other Healing Spaces | 13-41 41 99 | Circulation Zone 1A | Fire Alarm Zone 1A | Historic Preservation Zone 1A | Lighting Zone 1A | Occupancy Zone 1A | Ventilation Zone 1A
1D02 | First Floor | INTERACTION STATION | First Floor | First Floor | 2.8 | 0 | 11.5298 | 1D02 | 13-41 41 99: Other Healing Spaces | 13.802 | 2.8 | 30.0181 | Other Healing Spaces | 13-41 41 99 | Circulation Zone 1D | Fire Alarm Zone 1D | Historic Preservation Zone 1D | Lighting Zone 1D | Occupancy Zone 1D | Ventilation Zone 1D
1D23 | First Floor | GROUP IS | First Floor | First Floor | 2.8 | 0 | 19.1868 | 1D23 | 13-41 41 99: Other Healing Spaces | 18.161 | 2.8 | 50.1702 | Other Healing Spaces | 13-41 41 99 | Circulation Zone 1D | Fire Alarm Zone 1D | Historic Preservation Zone 1D | Lighting Zone 1D | Occupancy Zone 1D | Ventilation Zone 1D
1D21 | First Floor | GROUP IS | First Floor | First Floor | 2.8 | 0 | 19.1917 | 1D21 | 13-41 41 99: Other Healing Spaces | 18.161 | 2.8 | 50.1831 | Other Healing Spaces | 13-41 41 99 | Circulation Zone 1D | Fire Alarm Zone 1D | Historic Preservation Zone 1D | Lighting Zone 1D | Occupancy Zone 1D | Ventilation Zone 1D
2D20 | Second Floor | CONF. ROOM | Second Floor | Second Floor | 2.8 | 0 | 30.712 | 2D20 | 13-11 21 17: Conference Room | 22.3024 | 2.8 | 82.195 | Conference Room | 13-11 21 17 | Circulation Zone 2D | Fire Alarm Zone 2D | Historic Preservation Zone 2D | Lighting Zone 2D | Occupancy Zone 2D | Ventilation Zone 2D
1E26 | First Floor | WORK ROOM | First Floor | First Floor | 2.8 | 0 | 19.7143 | 1E26 | 13-15 11 34 11: Office | 18.857 | 2.8 | 51.3677 | Office | 13-15 11 34 11 | Circulation Zone 1E | Fire Alarm Zone 1E | Historic Preservation Zone 1E | Lighting Zone 1E | Occupancy Zone 1E | Ventilation Zone 1E
1A09 | First Floor | W. TOILET | First Floor | First Floor | 2.8 | 0 | 10.8536 | 1A09 | 13-41 11 14 21: Restroom | 13.3715 | 2.8 | 27.4898 | Restroom | 13-41 11 14 21 | Circulation Zone 1A | Fire Alarm Zone 1A | Historic Preservation Zone 1A | Lighting Zone 1A | Occupancy Zone 1A | Ventilation Zone 1A
1D05 | First Floor | TRMT RM. DIRTY PROC. | First Floor | First Floor | 2.8 | 0 | 14.1331 | 1D05 | 13-41 41 11: Treatment Room | 15.0667 | 2.8 | 37.6077 | Treatment Room | 13-41 41 11 | Circulation Zone 1D | Fire Alarm Zone 1D | Historic Preservation Zone 1D | Lighting Zone 1D | Occupancy Zone 1D | Ventilation Zone 1D
1CC2 | First Floor | CORRIDOR | First Floor | First Floor | 2.8 | 0 | 8.23209 | 1CC2 | 13-85 11 11: Corridor | 12.0636 | 2.8 | 21.1946 | Corridor | 13-85 11 11 | Circulation Zone 1C | Fire Alarm Zone 1C | Historic Preservation Zone 1C | Lighting Zone 1C | Occupancy Zone 1C | Ventilation Zone 1C
1E33 | First Floor | ISOLATION INTERACTION STATION | First Floor | First Floor | 2.8 | 0 | 13.354 | 1E33 | 13-41 41 99: Other Healing Spaces | 15.028 | 2.8 | 34.8761 | Other Healing Spaces | 13-41 41 99 | Circulation Zone 1E | Fire Alarm Zone 1E | Historic Preservation Zone 1E | Lighting Zone 1E | Occupancy Zone 1E | Ventilation Zone 1E
1B03 | First Floor | BLOOD DRAW | First Floor | First Floor | 2.8 | 0 | 9.68098 | 1B03 | 13-41 41 99: Other Healing Spaces | 12.732 | 2.8 | 24.9395 | Other Healing Spaces | 13-41 41 99 | Circulation Zone 1B | Fire Alarm Zone 1B | Historic Preservation Zone 1B | Lighting Zone 1B | Occupancy Zone 1B | Ventilation Zone 1B
1E18 | First Floor | BIOMED MAINT. ADMIN. | First Floor | First Floor | 2.8 | 0 | 15.5543 | 1E18 | 13-15 11 34 11: Office | 15.9435 | 2.8 | 40.2173 | Office | 13-15 11 34 11 | Circulation Zone 1E | Fire Alarm Zone 1E | Historic Preservation Zone 1E | Lighting Zone 1E | Occupancy Zone 1E | Ventilation Zone 1E
1BC3 | First Floor | CORRIDOR | First Floor | First Floor | 2.8 | 0 | 13.4396 | 1BC3 | 13-85 11 11: Corridor | 18.0333 | 2.8 | 34.7897 | Corridor | 13-85 11 11 | Circulation Zone 1B | Fire Alarm Zone 1B | Historic Preservation Zone 1B | Lighting Zone 1B | Occupancy Zone 1B | Ventilation Zone 1B
2C23 | Second Floor | M. TOILET | Second Floor | Second Floor | 2.8 | 0 | 8.65877 | 2C23 | 13-41 11 14 21: Restroom | 13.2267 | 2.8 | 21.4593 | Restroom | 13-41 11 14 21 | Circulation Zone 2C | Fire Alarm Zone 2C | Historic Preservation Zone 2C | Lighting Zone 2C | Occupancy Zone 2C | Ventilation Zone 2C
2A06 | Second Floor | OH DTR #2 | Second Floor | Second Floor | 2.8 | 0 | 12.0879 | 2A06 | 13-41 41 99: Other Healing Spaces | 13.9081 | 2.8 | 30.9712 | Other Healing Spaces | 13-41 41 99 | Circulation Zone 2A | Fire Alarm Zone 2A | Historic Preservation Zone 2A | Lighting Zone 2A | Occupancy Zone 2A | Ventilation Zone 2A
2A08 | Second Floor | GEN. DENT. DTR #4 | Second Floor | Second Floor | 2.8 | 0 | 11.7457 | 2A08 | 13-41 41 99: Other Healing Spaces | 13.5693 | 2.8 | 30.2529 | Other Healing Spaces | 13-41 41 99 | Circulation Zone 2A | Fire Alarm Zone 2A | Historic Preservation Zone 2A | Lighting Zone 2A | Occupancy Zone 2A | Ventilation Zone 2A
1D13 | First Floor | INTERACTION STATION | First Floor | First Floor | 2.8 | 0 | 12.8258 | 1D13 | 13-41 41 99: Other Healing Spaces | 14.432 | 2.8 | 33.45 | Other Healing Spaces | 13-41 41 99 | Circulation Zone 1D | Fire Alarm Zone 1D | Historic Preservation Zone 1D | Lighting Zone 1D | Occupancy Zone 1D | Ventilation Zone 1D
2C04 | Second Floor | GEN. DENT. DTR #7 | Second Floor | Second Floor | 2.8 | 0 | 11.1795 | 2C04 | 13-41 41 99: Other Healing Spaces | 13.8601 | 2.8 | 28.9039 | Other Healing Spaces | 13-41 41 99 | Circulation Zone 2C | Fire Alarm Zone 2C | Historic Preservation Zone 2C | Lighting Zone 2C | Occupancy Zone 2C | Ventilation Zone 2C
1E25 | First Floor | ADP EQUIP SPACE | First Floor | First Floor | 2.8 | 0 | 11.3734 | 1E25 | 13-75 11 11: Storage Room | 13.9988 | 2.8 | 29.5705 | Storage Room | 13-75 11 11 | Circulation Zone 1E | Fire Alarm Zone 1E | Historic Preservation Zone 1E | Lighting Zone 1E | Occupancy Zone 1E | Ventilation Zone 1E
2A09 | Second Floor | GEN. DENT. DTR #5 | Second Floor | Second Floor | 2.8 | 0 | 11.3064 | 2A09 | 13-41 41 99: Other Healing Spaces | 13.5013 | 2.8 | 29.2712 | Other Healing Spaces | 13-41 41 99 | Circulation Zone 2A | Fire Alarm Zone 2A | Historic Preservation Zone 2A | Lighting Zone 2A | Occupancy Zone 2A | Ventilation Zone 2A
1D36 | First Floor | INTERACTION STATION | First Floor | First Floor | 2.8 | 0 | 12.7053 | 1D36 | 13-41 41 99: Other Healing Spaces | 14.432 | 2.8 | 33.1896 | Other Healing Spaces | 13-41 41 99 | Circulation Zone 1D | Fire Alarm Zone 1D | Historic Preservation Zone 1D | Lighting Zone 1D | Occupancy Zone 1D | Ventilation Zone 1D
1E20 | First Floor | TRASH | First Floor | First Floor | 2.8 | 0 | 8.95436 | 1E20 | 13-75 41 14: Soiled Storage Room Space | 12.6045 | 2.8 | 22.0557 | Soiled Storage Room Space | 13-75 41 14 | Circulation Zone 1E | Fire Alarm Zone 1E | Historic Preservation Zone 1E | Lighting Zone 1E | Occupancy Zone 1E | Ventilation Zone 1E
1D06 | First Floor | SCOPE WASH / DECON. | First Floor | First Floor | 2.8 | 0 | 8.99752 | 1D06 | 13-41 11 99: Other Grooming Spaces | 12.507 | 2.8 | 23.2834 | Other Grooming Spaces | 13-41 11 99 | Circulation Zone 1D | Fire Alarm Zone 1D | Historic Preservation Zone 1D | Lighting Zone 1D | Occupancy Zone 1D | Ventilation Zone 1D
1C08 | First Floor | SCREEN EYE TEST | First Floor | First Floor | 2.8 | 0 | 9.81776 | 1C08 | 13-41 41 14: Physical Examination Room | 13.352 | 2.8 | 25.4762 | Physical Examination Room | 13-41 41 14 | Circulation Zone 1C | Fire Alarm Zone 1C | Historic Preservation Zone 1C | Lighting Zone 1C | Occupancy Zone 1C | Ventilation Zone 1C
1E29 | First Floor | HK. SUPV. OFFICE | First Floor | First Floor | 2.8 | 0 | 11.0301 | 1E29 | 13-15 11 34 11: Office | 13.469 | 2.8 | 27.8587 | Office | 13-15 11 34 11 | Circulation Zone 1E | Fire Alarm Zone 1E | Historic Preservation Zone 1E | Lighting Zone 1E | Occupancy Zone 1E | Ventilation Zone 1E
2C02 | Second Floor | GEN. DENT. DTR #6 | Second Floor | Second Floor | 2.8 | 0 | 12.0034 | 2C02 | 13-41 41 99: Other Healing Spaces | 13.8601 | 2.8 | 30.7475 | Other Healing Spaces | 13-41 41 99 | Circulation Zone 2C | Fire Alarm Zone 2C | Historic Preservation Zone 2C | Lighting Zone 2C | Occupancy Zone 2C | Ventilation Zone 2C
1C16 | First Floor | ECG TEST | First Floor | First Floor | 2.8 | 0 | 10.0079 | 1C16 | 13-41 41 31: Scanning/Imaging Room | 13.668 | 2.8 | 25.3019 | Scanning/Imaging Room | 13-41 41 31 | Circulation Zone 1C | Fire Alarm Zone 1C | Historic Preservation Zone 1C | Lighting Zone 1C | Occupancy Zone 1C | Ventilation Zone 1C
1D33 | First Floor | PEDIATRIC WAITING | First Floor | First Floor | 2.8 | 0 | 12.7423 | 1D33 | 13-51 31 11: Waiting Room | 14.432 | 2.8 | 33.2712 | Waiting Room | 13-51 31 11 | Circulation Zone 1D | Fire Alarm Zone 1D | Historic Preservation Zone 1D | Lighting Zone 1D | Occupancy Zone 1D | Ventilation Zone 1D
1D01 | First Floor | SL. LIN. / TRASH | First Floor | First Floor | 2.8 | 0 | 2.00168 | 1D01 | 13-75 41 14: Soiled Storage Room Space | 6.1929 | 2.8 | 4.65454 | Soiled Storage Room Space | 13-75 41 14 | Circulation Zone 1D | Fire Alarm Zone 1D | Historic Preservation Zone 1D | Lighting Zone 1D | Occupancy Zone 1D | Ventilation Zone 1D
3R04 | Roof - Main | ROOF | Roof - Main | Roof - Main | 4 | -1.2 | 15.1622 | 3R04 | 13-81 11 99: Other General Facility Service Spaces | 32.1454 | 5.2 | 77.0318 | Other General Facility Service Spaces | 13-81 11 99 | Circulation Zone 3R | Fire Alarm Zone 3R | Historic Preservation Zone 3R | Lighting Zone 3R | Occupancy Zone 3R | Ventilation Zone 3R
1D19 | First Floor | MDIS VIEW | First Floor | First Floor | 2.8 | 0 | 5.63662 | 1D19 | 13-15 11 34 11: Office | 9.711 | 2.8 | 14.3243 | Office | 13-15 11 34 11 | Circulation Zone 1D | Fire Alarm Zone 1D | Historic Preservation Zone 1D | Lighting Zone 1D | Occupancy Zone 1D | Ventilation Zone 1D
1C05 | First Floor | VISUAL FIELD | First Floor | First Floor | 2.8 | 0 | 11.3446 | 1C05 | 13-41 41 14: Physical Examination Room | 14.538 | 2.8 | 28.2926 | Physical Examination Room | 13-41 41 14 | Circulation Zone 1C | Fire Alarm Zone 1C | Historic Preservation Zone 1C | Lighting Zone 1C | Occupancy Zone 1C | Ventilation Zone 1C
1D12 | First Floor | SPECIMEN COLL. LAB | First Floor | First Floor | 2.8 | 0 | 10.2108 | 1D12 | 13-15 11 24 11: Laboratory | 13.1729 | 2.8 | 26.3971 | Laboratory | 13-15 11 24 11 | Circulation Zone 1D | Fire Alarm Zone 1D | Historic Preservation Zone 1D | Lighting Zone 1D | Occupancy Zone 1D | Ventilation Zone 1D
2CS3 | Second Floor | STAIR | Second Floor | Second Floor | 2.8 | 0 | 15.2659 | 2CS3 | 13-85 21 11: Stairway | 17.368 | 2.8 | 39.7725 | Stairway | 13-85 21 11 | Circulation Zone 2C | Fire Alarm Zone 2C | Historic Preservation Zone 2C | Lighting Zone 2C | Occupancy Zone 2C | Ventilation Zone 2C
1D27 | First Floor | ADMIN WORK STATN. | First Floor | First Floor | 2.8 | 0 | 10.7499 | 1D27 | 13-15 11 34 11: Office | 13.412 | 2.8 | 27.8833 | Office | 13-15 11 34 11 | Circulation Zone 1D | Fire Alarm Zone 1D | Historic Preservation Zone 1D | Lighting Zone 1D | Occupancy Zone 1D | Ventilation Zone 1D
2D03 | Second Floor | DIR. INFO MGR | Second Floor | Second Floor | 2.8 | 0 | 9.4116 | 2D03 | 13-15 11 34 11: Office | 12.5175 | 2.8 | 24.4264 | Office | 13-15 11 34 11 | Circulation Zone 2D | Fire Alarm Zone 2D | Historic Preservation Zone 2D | Lighting Zone 2D | Occupancy Zone 2D | Ventilation Zone 2D
2BC1 | Second Floor | CORRIDOR | Second Floor | Second Floor | 2.8 | 0 | 12.8241 | 2BC1 | 13-85 11 11: Corridor | 15.4512 | 2.8 | 34.0216 | Corridor | 13-85 11 11 | Circulation Zone 2B | Fire Alarm Zone 2B | Historic Preservation Zone 2B | Lighting Zone 2B | Occupancy Zone 2B | Ventilation Zone 2B
3R02 | Roof - Main | ROOF | Roof - Main | Roof - Main | 4 | -1.2 | 15.1699 | 3R02 | 13-81 11 99: Other General Facility Service Spaces | 32.1464 | 5.2 | 77.0714 | Other General Facility Service Spaces | 13-81 11 99 | Circulation Zone 3R | Fire Alarm Zone 3R | Historic Preservation Zone 3R | Lighting Zone 3R | Occupancy Zone 3R | Ventilation Zone 3R
1D39 | First Floor | JAN. CL. | First Floor | First Floor | 2.8 | 0 | 2.00067 | 1D39 | 13-75 11 11: Storage Room | 6.192 | 2.8 | 4.65202 | Storage Room | 13-75 11 11 | Circulation Zone 1D | Fire Alarm Zone 1D | Historic Preservation Zone 1D | Lighting Zone 1D | Occupancy Zone 1D | Ventilation Zone 1D
2D04A | Second Floor | COMPUTER ROOM | Second Floor | Second Floor | 2.8 | 0 | 33.5478 | 2D04A | 13-15 11 34 11: Office | 23.6075 | 2.8 | 89.8254 | Office | 13-15 11 34 11 | Circulation Zone 2D | Fire Alarm Zone 2D | Historic Preservation Zone 2D | Lighting Zone 2D | Occupancy Zone 2D | Ventilation Zone 2D
1B17 | First Floor | TECH. WORK ROOM | First Floor | First Floor | 2.8 | 0 | 24.0437 | 1B17 | 13-15 11 34 11: Office | 20.0581 | 2.8 | 64.5027 | Office | 13-15 11 34 11 | Circulation Zone 1B | Fire Alarm Zone 1B | Historic Preservation Zone 1B | Lighting Zone 1B | Occupancy Zone 1B | Ventilation Zone 1B
2BC6 | Second Floor | CORRIDOR | Second Floor | Second Floor | 2.8 | 0 | 8.57508 | 2BC6 | 13-85 11 11: Corridor | 12.7244 | 2.8 | 22.3116 | Corridor | 13-85 11 11 | Circulation Zone 2B | Fire Alarm Zone 2B | Historic Preservation Zone 2B | Lighting Zone 2B | Occupancy Zone 2B | Ventilation Zone 2B
2A02 | Second Floor | SUPER OFFICE | Second Floor | Second Floor | 2.8 | 0 | 10.8708 | 2A02 | 13-15 11 34 11: Office | 14.101 | 2.8 | 28.0654 | Office | 13-15 11 34 11 | Circulation Zone 2A | Fire Alarm Zone 2A | Historic Preservation Zone 2A | Lighting Zone 2A | Occupancy Zone 2A | Ventilation Zone 2A
2B13 | Second Floor | ELECTRICAL | Second Floor | Second Floor | 2.8 | 0 | 9.68587 | 2B13 | 13-81 21 21: Electrical Room | 12.977 | 2.8 | 24.9321 | Electrical Room | 13-81 21 21 | Circulation Zone 2B | Fire Alarm Zone 2B | Historic Preservation Zone 2B | Lighting Zone 2B | Occupancy Zone 2B | Ventilation Zone 2B
2B14 | Second Floor | RECS / FORMS STORAGE | Second Floor | Second Floor | 2.8 | 0 | 10.5466 | 2B14 | 13-75 11 11: Storage Room | 13.604 | 2.8 | 27.3185 | Storage Room | 13-75 11 11 | Circulation Zone 2B | Fire Alarm Zone 2B | Historic Preservation Zone 2B | Lighting Zone 2B | Occupancy Zone 2B | Ventilation Zone 2B
2B10 | Second Floor | RECEPTION | Second Floor | Second Floor | 2.8 | 0 | 15.1738 | 2B10 | 13-11 11 31: Reception Space | 16.625 | 2.8 | 39.7081 | Reception Space | 13-11 11 31 | Circulation Zone 2B | Fire Alarm Zone 2B | Historic Preservation Zone 2B | Lighting Zone 2B | Occupancy Zone 2B | Ventilation Zone 2B
1BS2 | First Floor | STAIR | First Floor | First Floor | 2.8 | 0 | 16.0319 | 1BS2 | 13-85 21 11: Stairway | 18.161 | 2.8 | 41.5241 | Stairway | 13-85 21 11 | Circulation Zone 1E | Fire Alarm Zone 1E | Historic Preservation Zone 1E | Lighting Zone 1E | Occupancy Zone 1E | Ventilation Zone 1E
2C05 | Second Floor | JAN. CL. | Second Floor | Second Floor | 2.8 | 0 | 3.69253 | 2C05 | 13-75 11 11: Storage Room | 8.264 | 2.8 | 9.06385 | Storage Room | 13-75 11 11 | Circulation Zone 2C | Fire Alarm Zone 2C | Historic Preservation Zone 2C | Lighting Zone 2C | Occupancy Zone 2C | Ventilation Zone 2C
2C13 | Second Floor | TRASH | Second Floor | Second Floor | 2.8 | 0 | 5.53953 | 2C13 | 13-75 41 14: Soiled Storage Room Space | 10.182 | 2.8 | 13.9686 | Soiled Storage Room Space | 13-75 41 14 | Circulation Zone 2C | Fire Alarm Zone 2C | Historic Preservation Zone 2C | Lighting Zone 2C | Occupancy Zone 2C | Ventilation Zone 2C
3R03 | Roof - Main | ROOF | Roof - Main | Roof - Main | 4 | -2.48688 | 58.0851 | 3R03 | 13-81 11 99: Other General Facility Service Spaces | 30.3788 | 6.48688 | 376.329 | Other General Facility Service Spaces | 13-81 11 99 | Circulation Zone 3R | Fire Alarm Zone 3R | Historic Preservation Zone 3R | Lighting Zone 3R | Occupancy Zone 3R | Ventilation Zone 3R
2D14 | Second Floor | OPS SQUAD CMDR | Second Floor | Second Floor | 2.8 | 0 | 13.6001 | 2D14 | 13-15 11 34 11: Office | 15.4428 | 2.8 | 35.602 | Office | 13-15 11 34 11 | Circulation Zone 2D | Fire Alarm Zone 2D | Historic Preservation Zone 2D | Lighting Zone 2D | Occupancy Zone 2D | Ventilation Zone 2D
2D06 | Second Floor | COPY / FILE | Second Floor | Second Floor | 2.8 | 0 | 11.9777 | 2D06 | 13-15 11 34 27: Copy Room | 14.02 | 2.8 | 31.2346 | Copy Room | 13-15 11 34 27 | Circulation Zone 2D | Fire Alarm Zone 2D | Historic Preservation Zone 2D | Lighting Zone 2D | Occupancy Zone 2D | Ventilation Zone 2D
2A03 | Second Floor | SEC. OFFICE | Second Floor | Second Floor | 2.8 | 0 | 16.0095 | 2A03 | 13-15 11 34 11: Office | 16.097 | 2.8 | 41.3804 | Office | 13-15 11 34 11 | Circulation Zone 2A | Fire Alarm Zone 2A | Historic Preservation Zone 2A | Lighting Zone 2A | Occupancy Zone 2A | Ventilation Zone 2A
1E30 | First Floor | SOIL. LIN. | First Floor | First Floor | 2.8 | 0 | 6.87827 | 1E30 | 13-75 41 14: Soiled Storage Room Space | 10.7732 | 2.8 | 17.3789 | Soiled Storage Room Space | 13-75 41 14 | Circulation Zone 1E | Fire Alarm Zone 1E | Historic Preservation Zone 1E | Lighting Zone 1E | Occupancy Zone 1E | Ventilation Zone 1E
2D15 | Second Floor | 1ST SGT | Second Floor | Second Floor | 2.8 | 0 | 10.8297 | 2D15 | 13-15 11 34 11: Office | 13.588 | 2.8 | 27.7911 | Office | 13-15 11 34 11 | Circulation Zone 2D | Fire Alarm Zone 2D | Historic Preservation Zone 2D | Lighting Zone 2D | Occupancy Zone 2D | Ventilation Zone 2D
1D30 | First Floor | WTS & MEAS. ROOM | First Floor | First Floor | 2.8 | 0 | 9.26534 | 1D30 | 13-41 41 14: Physical Examination Room | 12.672 | 2.8 | 23.7861 | Physical Examination Room | 13-41 41 14 | Circulation Zone 1D | Fire Alarm Zone 1D | Historic Preservation Zone 1D | Lighting Zone 1D | Occupancy Zone 1D | Ventilation Zone 1D
1D15 | First Floor | WTS & MEAS. ROOM | First Floor | First Floor | 2.8 | 0 | 5.06769 | 1D15 | 13-41 41 14: Physical Examination Room | 9.0729 | 2.8 | 12.8164 | Physical Examination Room | 13-41 41 14 | Circulation Zone 1D | Fire Alarm Zone 1D | Historic Preservation Zone 1D | Lighting Zone 1D | Occupancy Zone 1D | Ventilation Zone 1D
2D09 | Second Floor | ADMIN OFFICE | Second Floor | Second Floor | 2.8 | 0 | 14.3932 | 2D09 | 13-15 11 34 11: Office | 15.445 | 2.8 | 37.2826 | Office | 13-15 11 34 11 | Circulation Zone 2D | Fire Alarm Zone 2D | Historic Preservation Zone 2D | Lighting Zone 2D | Occupancy Zone 2D | Ventilation Zone 2D
2B19 | Second Floor | OFFICE | Second Floor | Second Floor | 2.8 | 0 | 8.87578 | 2B19 | 13-15 11 34 11: Office | 12.104 | 2.8 | 22.794 | Office | 13-15 11 34 11 | Circulation Zone 2B | Fire Alarm Zone 2B | Historic Preservation Zone 2B | Lighting Zone 2B | Occupancy Zone 2B | Ventilation Zone 2B
1A01 | First Floor | PATIENT ADMIN. RECEPT. | First Floor | First Floor | 2.8 | 0 | 19.7671 | 1A01 | 13-11 11 31: Reception Space | 19.072 | 2.8 | 53.2474 | Reception Space | 13-11 11 31 | Circulation Zone 1A | Fire Alarm Zone 1A | Historic Preservation Zone 1A | Lighting Zone 1A | Occupancy Zone 1A | Ventilation Zone 1A
1A05 | First Floor | TRICARE OFFICE | First Floor | First Floor | 2.8 | 0 | 8.99911 | 1A05 | 13-15 11 34 11: Office | 12.192 | 2.8 | 23.2335 | Office | 13-15 11 34 11 | Circulation Zone 1A | Fire Alarm Zone 1A | Historic Preservation Zone 1A | Lighting Zone 1A | Occupancy Zone 1A | Ventilation Zone 1A
2C24 | Second Floor | W. TOILET | Second Floor | Second Floor | 2.8 | 0 | 9.22003 | 2C24 | 13-41 11 14 21: Restroom | 12.1502 | 2.8 | 23.7895 | Restroom | 13-41 11 14 21 | Circulation Zone 2C | Fire Alarm Zone 2C | Historic Preservation Zone 2C | Lighting Zone 2C | Occupancy Zone 2C | Ventilation Zone 2C
1A03 | First Floor | TRICARE OFFICE | First Floor | First Floor | 2.8 | 0 | 8.87366 | 1A03 | 13-15 11 34 11: Office | 11.957 | 2.8 | 22.8438 | Office | 13-15 11 34 11 | Circulation Zone 1A | Fire Alarm Zone 1A | Historic Preservation Zone 1A | Lighting Zone 1A | Occupancy Zone 1A | Ventilation Zone 1A
1C01 | First Floor | WAITING | First Floor | First Floor | 2.8 | 0 | 11.8597 | 1C01 | 13-51 31 11: Waiting Room | 13.5102 | 2.8 | 32.5825 | Waiting Room | 13-51 31 11 | Circulation Zone 1C | Fire Alarm Zone 1C | Historic Preservation Zone 1C | Lighting Zone 1C | Occupancy Zone 1C | Ventilation Zone 1C
1C04 | First Floor | FITTING / DISP. | First Floor | First Floor | 2.8 | 0 | 10.1189 | 1C04 | 13-41 41 99: Other Healing Spaces | 12.623 | 2.8 | 25.7339 | Other Healing Spaces | 13-41 41 99 | Circulation Zone 1C | Fire Alarm Zone 1C | Historic Preservation Zone 1C | Lighting Zone 1C | Occupancy Zone 1C | Ventilation Zone 1C
1C12 | First Floor | TOILET | First Floor | First Floor | 2.8 | 0 | 6.14704 | 1C12 | 13-41 11 14 21: Restroom | 10.0295 | 2.8 | 15.2844 | Restroom | 13-41 11 14 21 | Circulation Zone 1C | Fire Alarm Zone 1C | Historic Preservation Zone 1C | Lighting Zone 1C | Occupancy Zone 1C | Ventilation Zone 1C
1D20 | First Floor | APPMTS | First Floor | First Floor | 2.8 | 0 | 11.7909 | 1D20 | 13-15 11 34 11: Office | 13.74 | 2.8 | 30.6724 | Office | 13-15 11 34 11 | Circulation Zone 1D | Fire Alarm Zone 1D | Historic Preservation Zone 1D | Lighting Zone 1D | Occupancy Zone 1D | Ventilation Zone 1D
2C10 | Second Floor | DIPC DECON | Second Floor | Second Floor | 2.8 | 0 | 11.0309 | 2C10 | 13-41 41 99: Other Healing Spaces | 13.492 | 2.8 | 28.6997 | Other Healing Spaces | 13-41 41 99 | Circulation Zone 2C | Fire Alarm Zone 2C | Historic Preservation Zone 2C | Lighting Zone 2C | Occupancy Zone 2C | Ventilation Zone 2C
1C13 | First Floor | COMM. ROOM | First Floor | First Floor | 2.8 | 0 | 11.8973 | 1C13 | 13-15 11 34 11: Office | 14.159 | 2.8 | 30.9818 | Office | 13-15 11 34 11 | Circulation Zone 1C | Fire Alarm Zone 1C | Historic Preservation Zone 1C | Lighting Zone 1C | Occupancy Zone 1C | Ventilation Zone 1C
1B09 | First Floor | DRESS | First Floor | First Floor | 2.8 | 0 | 4.64607 | 1B09 | 13-41 11 41 11: Dressing Room | 8.64805 | 2.8 | 11.5507 | Dressing Room | 13-41 11 41 11 | Circulation Zone 1B | Fire Alarm Zone 1B | Historic Preservation Zone 1B | Lighting Zone 1B | Occupancy Zone 1B | Ventilation Zone 1B
2A07 | Second Floor | OH DTR #3 | Second Floor | Second Floor | 2.8 | 0 | 12.0034 | 2A07 | 13-41 41 99: Other Healing Spaces | 13.5693 | 2.8 | 30.7592 | Other Healing Spaces | 13-41 41 99 | Circulation Zone 2A | Fire Alarm Zone 2A | Historic Preservation Zone 2A | Lighting Zone 2A | Occupancy Zone 2A | Ventilation Zone 2A
1A06 | First Floor | TRICARE OFFICE | First Floor | First Floor | 2.8 | 0 | 10.4921 | 1A06 | 13-15 11 34 11: Office | 13.0265 | 2.8 | 26.1176 | Office | 13-15 11 34 11 | Circulation Zone 1A | Fire Alarm Zone 1A | Historic Preservation Zone 1A | Lighting Zone 1A | Occupancy Zone 1A | Ventilation Zone 1A
2C09 | Second Floor | GEN. DENT. DTR #9 | Second Floor | Second Floor | 2.8 | 0 | 11.3638 | 2C09 | 13-41 41 99: Other Healing Spaces | 13.8601 | 2.8 | 29.2875 | Other Healing Spaces | 13-41 41 99 | Circulation Zone 2C | Fire Alarm Zone 2C | Historic Preservation Zone 2C | Lighting Zone 2C | Occupancy Zone 2C | Ventilation Zone 2C
1B11 | First Floor | STAFF TOILET | First Floor | First Floor | 2.8 | 0 | 4.99399 | 1B11 | 13-41 11 14 21: Restroom | 8.996 | 2.8 | 12.3492 | Restroom | 13-41 11 14 21 | Circulation Zone 1B | Fire Alarm Zone 1B | Historic Preservation Zone 1B | Lighting Zone 1B | Occupancy Zone 1B | Ventilation Zone 1B
1EC3 | First Floor | CORRIDOR | First Floor | First Floor | 2.8 | 0 | 8.75185 | 1EC3 | 13-85 11 11: Corridor | 12.6304 | 2.8 | 22.5515 | Corridor | 13-85 11 11 | Circulation Zone 1E | Fire Alarm Zone 1E | Historic Preservation Zone 1E | Lighting Zone 1E | Occupancy Zone 1E | Ventilation Zone 1E
1D10 | First Floor | INTERACTION STATION | First Floor | First Floor | 2.8 | 0 | 12.7437 | 1D10 | 13-41 41 99: Other Healing Spaces | 14.4329 | 2.8 | 33.2748 | Other Healing Spaces | 13-41 41 99 | Circulation Zone 1D | Fire Alarm Zone 1D | Historic Preservation Zone 1D | Lighting Zone 1D | Occupancy Zone 1D | Ventilation Zone 1D
2B22 | Second Floor | M. TOILET | Second Floor | Second Floor | 2.8 | 0 | 5.16718 | 2B22 | 13-41 11 14 21: Restroom | 9.11944 | 2.8 | 12.433 | Restroom | 13-41 11 14 21 | Circulation Zone 2B | Fire Alarm Zone 2B | Historic Preservation Zone 2B | Lighting Zone 2B | Occupancy Zone 2B | Ventilation Zone 2B
1A13 | First Floor | STAFF TOILET | First Floor | First Floor | 2.8 | 0 | 4.4685 | 1A13 | 13-41 11 14 21: Restroom | 8.506 | 2.8 | 11.0247 | Restroom | 13-41 11 14 21 | Circulation Zone 1A | Fire Alarm Zone 1A | Historic Preservation Zone 1A | Lighting Zone 1A | Occupancy Zone 1A | Ventilation Zone 1A
2B17 | Second Floor | CL. UTL. / KITCHENET | Second Floor | Second Floor | 2.8 | 0 | 8.99668 | 2B17 | 13-11 19 11 11: Kitchen | 12.172 | 2.8 | 23.1207 | Kitchen | 13-11 19 11 11 | Circulation Zone 2B | Fire Alarm Zone 2B | Historic Preservation Zone 2B | Lighting Zone 2B | Occupancy Zone 2B | Ventilation Zone 2B
E1 | First Floor | ELEVATOR | First Floor | Roof - Main | 0 | 0 | 4.35577 | E1 | 13-81 21 31: Elevator Shaft | 8.4154 | 9.25 | 36.1313 | Elevator Shaft | 13-81 21 31 | Circulation Zone 1B | Fire Alarm Zone 1B | Historic Preservation Zone 1B | Lighting Zone 1B | Occupancy Zone 1B | Ventilation Zone 1B
2B5 | Second Floor | W. TOILET | Second Floor | Second Floor | 2.8 | 0 | 4.73083 | 2B5 | 13-41 11 14 21: Restroom | 8.976 | 2.8 | 11.5666 | Restroom | 13-41 11 14 21 | Circulation Zone 2B | Fire Alarm Zone 2B | Historic Preservation Zone 2B | Lighting Zone 2B | Occupancy Zone 2B | Ventilation Zone 2B
2B12 | Second Floor | COMM. ROOM | Second Floor | Second Floor | 2.8 | 0 | 9.92484 | 2B12 | 13-15 11 34 11: Office | 13.085 | 2.8 | 25.5702 | Office | 13-15 11 34 11 | Circulation Zone 2B | Fire Alarm Zone 2B | Historic Preservation Zone 2B | Lighting Zone 2B | Occupancy Zone 2B | Ventilation Zone 2B
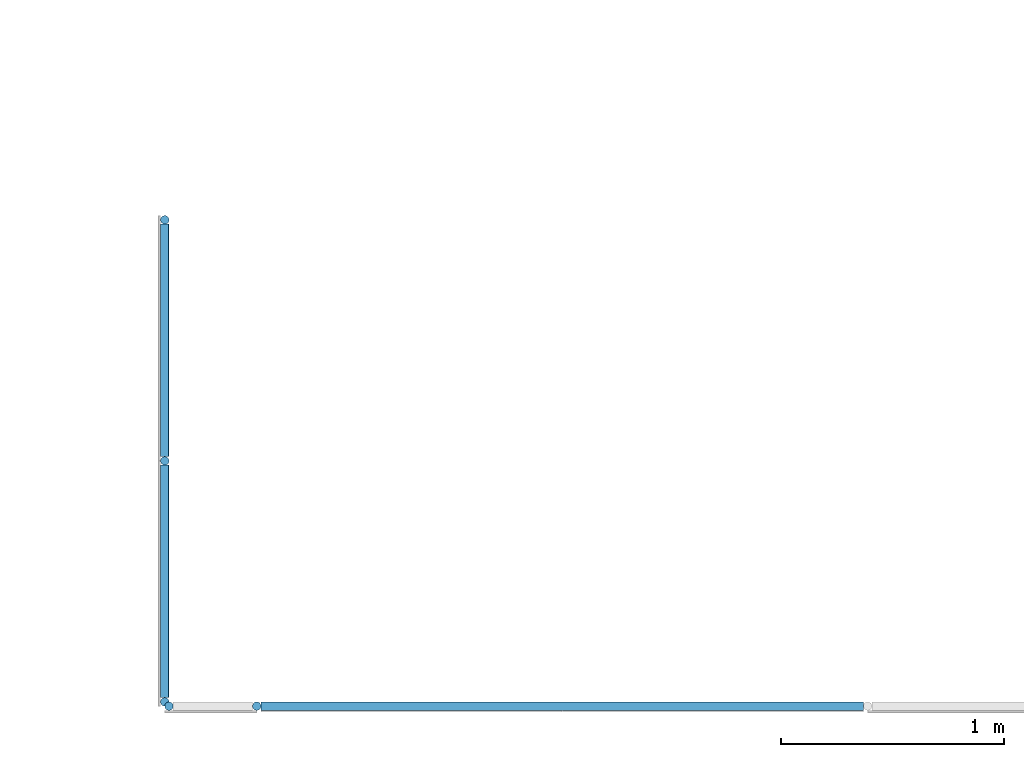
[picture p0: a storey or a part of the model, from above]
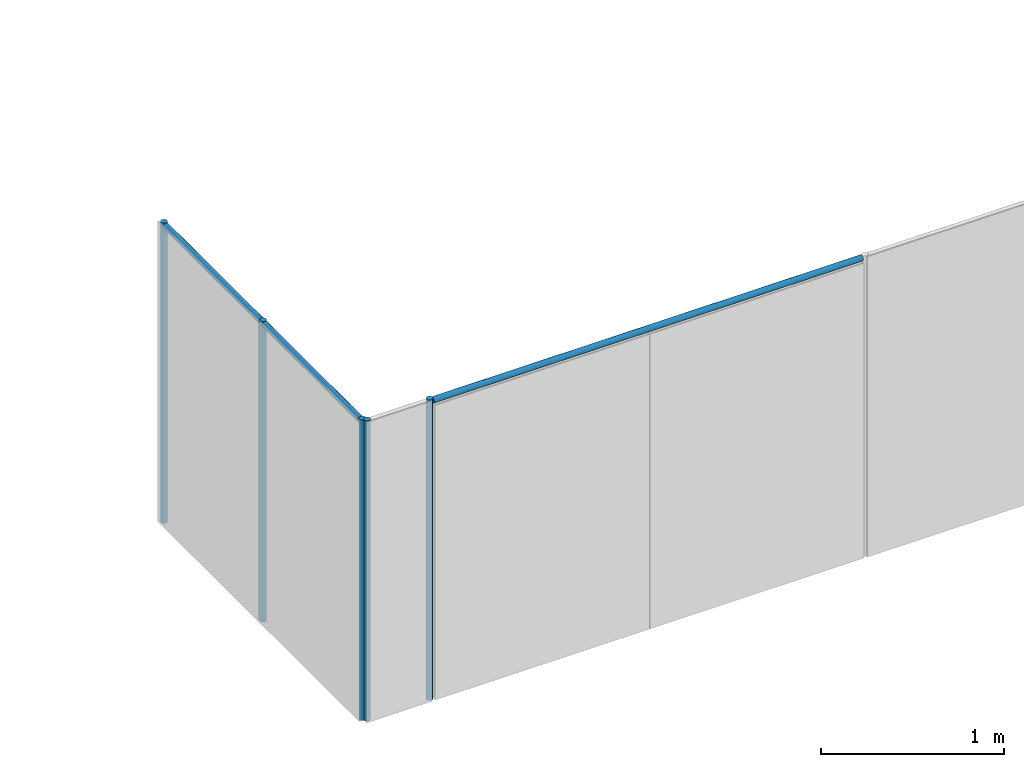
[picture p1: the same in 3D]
Properties of the parts of a building model (IFC2X3), part 2 of 11

# IfcSpace (269)
Name | In | LongName = Name | Level | Upper Limit | Limit Offset (m) | Base Offset (m) | GSA BIM Area (m2) = Area (m2) | Number | OmniClass Table 13 Category | Perimeter (m) | Unbounded Height (m) | Volume (m3) | Category Description | Category Code | CirculationZoneName | FireAlarmZoneName | HistoricPreservationZoneName | LightingZoneName | OccupancyZoneName | VentilationZoneName
1F01 | First Floor | MECH. YARD | First Floor | Second Floor | 0 | -1 | 80.0652 | 1F01 | 13-81 21 11: Equipment Room | 35.8195 | 5.57 | 439.567 | Equipment Room | 13-81 21 11 | Circulation Zone 1F | Fire Alarm Zone 1F | Historic Preservation Zone 1F | Lighting Zone 1F | Occupancy Zone 1F | Ventilation Zone 1F
2B8 | Second Floor | OFFICE / EXAM | Second Floor | Second Floor | 2.8 | 0 | 12.6405 | 2B8 | 13-15 11 34 11: Office | 14.84 | 2.8 | 32.8602 | Office | 13-15 11 34 11 | Circulation Zone 2B | Fire Alarm Zone 2B | Historic Preservation Zone 2B | Lighting Zone 2B | Occupancy Zone 2B | Ventilation Zone 2B
1C17 | First Floor | CHIEF AERO MED. | First Floor | First Floor | 2.8 | 0 | 9.94224 | 1C17 | 13-15 11 34 11: Office | 12.691 | 2.8 | 25.1968 | Office | 13-15 11 34 11 | Circulation Zone 1C | Fire Alarm Zone 1C | Historic Preservation Zone 1C | Lighting Zone 1C | Occupancy Zone 1C | Ventilation Zone 1C
1DC5 | First Floor | CORRIDOR | First Floor | First Floor | 2.8 | 0 | 6.61219 | 1DC5 | 13-85 11 11: Corridor | 10.2786 | 2.8 | 17.0051 | Corridor | 13-85 11 11 | Circulation Zone 1D | Fire Alarm Zone 1D | Historic Preservation Zone 1D | Lighting Zone 1D | Occupancy Zone 1D | Ventilation Zone 1D
1E01 | First Floor | HK EQUIP. STORAGE | First Floor | First Floor | 2.8 | 0 | 9.72524 | 1E01 | 13-75 11 11: Storage Room | 12.492 | 2.8 | 25.1051 | Storage Room | 13-75 11 11 | Circulation Zone 1E | Fire Alarm Zone 1E | Historic Preservation Zone 1E | Lighting Zone 1E | Occupancy Zone 1E | Ventilation Zone 1E
1E17 | First Floor | HAZ. STOR. | First Floor | First Floor | 2.8 | 0 | 9.78713 | 1E17 | 13-75 41 24: Hazardous Material Storage Space | 12.724 | 2.8 | 24.2384 | Hazardous Material Storage Space | 13-75 41 24 | Circulation Zone 1E | Fire Alarm Zone 1E | Historic Preservation Zone 1E | Lighting Zone 1E | Occupancy Zone 1E | Ventilation Zone 1E
2B21 | Second Floor | PH SUPER | Second Floor | Second Floor | 2.8 | 0 | 9.25086 | 2B21 | 13-15 11 34 11: Office | 12.5366 | 2.8 | 23.6268 | Office | 13-15 11 34 11 | Circulation Zone 2B | Fire Alarm Zone 2B | Historic Preservation Zone 2B | Lighting Zone 2B | Occupancy Zone 2B | Ventilation Zone 2B
1E12 | First Floor | ISOLATION TOILET | First Floor | First Floor | 2.8 | 0 | 5.25186 | 1E12 | 13-41 11 14 21: Restroom | 9.282 | 2.8 | 13.0241 | Restroom | 13-41 11 14 21 | Circulation Zone 1E | Fire Alarm Zone 1E | Historic Preservation Zone 1E | Lighting Zone 1E | Occupancy Zone 1E | Ventilation Zone 1E
2D12 | Second Floor | VEST. | Second Floor | Second Floor | 2.8 | 0 | 2.79678 | 2D12 | 13-85 31 11: Entry Vestibule | 6.5021 | 2.8 | 6.51539 | Entry Vestibule | 13-85 31 11 | Circulation Zone 2D | Fire Alarm Zone 2D | Historic Preservation Zone 2D | Lighting Zone 2D | Occupancy Zone 2D | Ventilation Zone 2D
1C19 | First Floor | AUDIO | First Floor | First Floor | 2.8 | 0 | 11.6268 | 1C19 | 13-81 21 11: Equipment Room | 13.798 | 2.8 | 29.1218 | Equipment Room | 13-81 21 11 | Circulation Zone 1C | Fire Alarm Zone 1C | Historic Preservation Zone 1C | Lighting Zone 1C | Occupancy Zone 1C | Ventilation Zone 1C
1E28 | First Floor | FAC. MGR. OFFICE | First Floor | First Floor | 2.8 | 0 | 9.73829 | 1E28 | 13-15 11 34 11: Office | 12.614 | 2.8 | 24.1581 | Office | 13-15 11 34 11 | Circulation Zone 1E | Fire Alarm Zone 1E | Historic Preservation Zone 1E | Lighting Zone 1E | Occupancy Zone 1E | Ventilation Zone 1E
1D09 | First Floor | INTERACTION STATION | First Floor | First Floor | 2.8 | 0 | 12.7792 | 1D09 | 13-41 41 99: Other Healing Spaces | 14.3048 | 2.8 | 33.45 | Other Healing Spaces | 13-41 41 99 | Circulation Zone 1D | Fire Alarm Zone 1D | Historic Preservation Zone 1D | Lighting Zone 1D | Occupancy Zone 1D | Ventilation Zone 1D
1C11 | First Floor | ELEC. CL. | First Floor | First Floor | 2.8 | 0 | 0.777824 | 1C11 | 13-81 21 21: Electrical Room | 4.44 | 2.8 | 1.51133 | Electrical Room | 13-81 21 21 | Circulation Zone 1C | Fire Alarm Zone 1C | Historic Preservation Zone 1C | Lighting Zone 1C | Occupancy Zone 1C | Ventilation Zone 1C
1D35 | First Floor | INTERACTION STATION | First Floor | First Floor | 2.8 | 0 | 12.8258 | 1D35 | 13-41 41 99: Other Healing Spaces | 14.432 | 2.8 | 33.45 | Other Healing Spaces | 13-41 41 99 | Circulation Zone 1D | Fire Alarm Zone 1D | Historic Preservation Zone 1D | Lighting Zone 1D | Occupancy Zone 1D | Ventilation Zone 1D
2D08 | Second Floor | QA / HRD DIRECTOR | Second Floor | Second Floor | 2.8 | 0 | 8.98396 | 2D08 | 13-15 11 34 11: Office | 12.282 | 2.8 | 23.1926 | Office | 13-15 11 34 11 | Circulation Zone 2D | Fire Alarm Zone 2D | Historic Preservation Zone 2D | Lighting Zone 2D | Occupancy Zone 2D | Ventilation Zone 2D
1B07 | First Floor | DRESS | First Floor | First Floor | 2.8 | 0 | 4.42138 | 1B07 | 13-41 11 41 11: Dressing Room | 8.704 | 2.8 | 10.9119 | Dressing Room | 13-41 11 41 11 | Circulation Zone 1B | Fire Alarm Zone 1B | Historic Preservation Zone 1B | Lighting Zone 1B | Occupancy Zone 1B | Ventilation Zone 1B
1E07 | First Floor | CONF. LIBRARY | First Floor | First Floor | 2.8 | 0 | 11.6309 | 1E07 | 13-11 21 17: Conference Room | 13.652 | 2.8 | 30.2395 | Conference Room | 13-11 21 17 | Circulation Zone 1E | Fire Alarm Zone 1E | Historic Preservation Zone 1E | Lighting Zone 1E | Occupancy Zone 1E | Ventilation Zone 1E
2D17 | Second Floor | CREDENTIALS MGR | Second Floor | Second Floor | 2.8 | 0 | 9.64538 | 2D17 | 13-15 11 34 11: Office | 12.7579 | 2.8 | 24.3537 | Office | 13-15 11 34 11 | Circulation Zone 2D | Fire Alarm Zone 2D | Historic Preservation Zone 2D | Lighting Zone 2D | Occupancy Zone 2D | Ventilation Zone 2D
1D08 | First Floor | INTERACTION STATION | First Floor | First Floor | 2.8 | 0 | 12.8273 | 1D08 | 13-41 41 99: Other Healing Spaces | 14.4329 | 2.8 | 33.4538 | Other Healing Spaces | 13-41 41 99 | Circulation Zone 1D | Fire Alarm Zone 1D | Historic Preservation Zone 1D | Lighting Zone 1D | Occupancy Zone 1D | Ventilation Zone 1D
1E03 | First Floor | JAN. CL. | First Floor | First Floor | 2.8 | 0 | 3.96995 | 1E03 | 13-75 11 11: Storage Room | 8.652 | 2.8 | 9.71094 | Storage Room | 13-75 11 11 | Circulation Zone 1E | Fire Alarm Zone 1E | Historic Preservation Zone 1E | Lighting Zone 1E | Occupancy Zone 1E | Ventilation Zone 1E
1E14 | First Floor | DISASTER STOR. | First Floor | First Floor | 2.8 | 0 | 22.3553 | 1E14 | 13-75 11 11: Storage Room | 19.889 | 2.8 | 59.1954 | Storage Room | 13-75 11 11 | Circulation Zone 1E | Fire Alarm Zone 1E | Historic Preservation Zone 1E | Lighting Zone 1E | Occupancy Zone 1E | Ventilation Zone 1E
1D28 | First Floor | INTERACTION STATION | First Floor | First Floor | 2.8 | 0 | 12.6883 | 1D28 | 13-41 41 99: Other Healing Spaces | 14.364 | 2.8 | 33.0766 | Other Healing Spaces | 13-41 41 99 | Circulation Zone 1D | Fire Alarm Zone 1D | Historic Preservation Zone 1D | Lighting Zone 1D | Occupancy Zone 1D | Ventilation Zone 1D
1E10 | First Floor | M. TOILET | First Floor | First Floor | 2.8 | 0 | 5.06216 | 1E10 | 13-41 11 14 21: Restroom | 9.206 | 2.8 | 12.455 | Restroom | 13-41 11 14 21 | Circulation Zone 1E | Fire Alarm Zone 1E | Historic Preservation Zone 1E | Lighting Zone 1E | Occupancy Zone 1E | Ventilation Zone 1E
2D19 | Second Floor | READINESS NCOIC OFFICE | Second Floor | Second Floor | 2.8 | 0 | 10.9078 | 2D19 | 13-15 11 34 11: Office | 13.5279 | 2.8 | 27.9061 | Office | 13-15 11 34 11 | Circulation Zone 2D | Fire Alarm Zone 2D | Historic Preservation Zone 2D | Lighting Zone 2D | Occupancy Zone 2D | Ventilation Zone 2D
2C11 | Second Floor | HK | Second Floor | Second Floor | 2.8 | 0 | 5.0922 | 2C11 | 13-41 41 99: Other Healing Spaces | 9.49 | 2.8 | 12.8023 | Other Healing Spaces | 13-41 41 99 | Circulation Zone 2C | Fire Alarm Zone 2C | Historic Preservation Zone 2C | Lighting Zone 2C | Occupancy Zone 2C | Ventilation Zone 2C
2A12-A | Second Floor | X-RAY ALCOVE | Second Floor | Second Floor | 2.8 | 0 | 2.28699 | 2A12-A | 13-41 41 31: Scanning/Imaging Room | 5.62774 | 2.8 | 5.58762 | Scanning/Imaging Room | 13-41 41 31 | Circulation Zone 2A | Fire Alarm Zone 2A | Historic Preservation Zone 2A | Lighting Zone 2A | Occupancy Zone 2A | Ventilation Zone 2A
2A10 | Second Floor | DENTAL WAITING | Second Floor | Second Floor | 2.8 | 0 | 7.85686 | 2A10 | 13-51 31 11: Waiting Room | 10.8741 | 2.8 | 20.4537 | Waiting Room | 13-51 31 11 | Circulation Zone 2A | Fire Alarm Zone 2A | Historic Preservation Zone 2A | Lighting Zone 2A | Occupancy Zone 2A | Ventilation Zone 2A
1E05 | First Floor | CHIEF LOG OFFICE | First Floor | First Floor | 2.8 | 0 | 9.93876 | 1E05 | 13-15 11 34 11: Office | 12.628 | 2.8 | 25.6794 | Office | 13-15 11 34 11 | Circulation Zone 1E | Fire Alarm Zone 1E | Historic Preservation Zone 1E | Lighting Zone 1E | Occupancy Zone 1E | Ventilation Zone 1E
1D34 | First Floor | INTERACTION STATION | First Floor | First Floor | 2.8 | 0 | 12.8258 | 1D34 | 13-41 41 99: Other Healing Spaces | 14.432 | 2.8 | 33.45 | Other Healing Spaces | 13-41 41 99 | Circulation Zone 1D | Fire Alarm Zone 1D | Historic Preservation Zone 1D | Lighting Zone 1D | Occupancy Zone 1D | Ventilation Zone 1D
1B21 | First Floor | COMM. ROOM | First Floor | First Floor | 2.8 | 0 | 9.80232 | 1B21 | 13-15 11 34 11: Office | 13.012 | 2.8 | 25.2307 | Office | 13-15 11 34 11 | Circulation Zone 1B | Fire Alarm Zone 1B | Historic Preservation Zone 1B | Lighting Zone 1B | Occupancy Zone 1B | Ventilation Zone 1B
1B14 | First Floor | SOIL. UTL. | First Floor | First Floor | 2.8 | 0 | 4.03581 | 1B14 | 13-75 41 14: Soiled Storage Room Space | 8.609 | 2.8 | 9.59735 | Soiled Storage Room Space | 13-75 41 14 | Circulation Zone 1B | Fire Alarm Zone 1B | Historic Preservation Zone 1B | Lighting Zone 1B | Occupancy Zone 1B | Ventilation Zone 1B
1AS1 | First Floor | STAIR | First Floor | First Floor | 2.8 | 0 | 14.0577 | 1AS1 | 13-85 21 11: Stairway | 15.646 | 2.8 | 38.0143 | Stairway | 13-85 21 11 | Circulation Zone 1A | Fire Alarm Zone 1A | Historic Preservation Zone 1A | Lighting Zone 1A | Occupancy Zone 1A | Ventilation Zone 1A
1B23 | First Floor | ELEC. ROOM | First Floor | First Floor | 2.8 | 0 | 9.88297 | 1B23 | 13-81 21 21: Electrical Room | 13.0801 | 2.8 | 25.4447 | Electrical Room | 13-81 21 21 | Circulation Zone 1B | Fire Alarm Zone 1B | Historic Preservation Zone 1B | Lighting Zone 1B | Occupancy Zone 1B | Ventilation Zone 1B
1E04 | First Floor | HK BREAK ROOM | First Floor | First Floor | 2.8 | 0 | 9.73544 | 1E04 | 13-51 11 21: Break Room | 12.492 | 2.8 | 25.1337 | Break Room | 13-51 11 21 | Circulation Zone 1E | Fire Alarm Zone 1E | Historic Preservation Zone 1E | Lighting Zone 1E | Occupancy Zone 1E | Ventilation Zone 1E
2B23 | Second Floor | BEE TECH | Second Floor | Second Floor | 2.8 | 0 | 10.7975 | 2B23 | 13-15 11 34 11: Office | 13.226 | 2.8 | 27.7575 | Office | 13-15 11 34 11 | Circulation Zone 2B | Fire Alarm Zone 2B | Historic Preservation Zone 2B | Lighting Zone 2B | Occupancy Zone 2B | Ventilation Zone 2B
2B16 | Second Floor | PH TECH | Second Floor | Second Floor | 2.8 | 0 | 9.51632 | 2B16 | 13-15 11 34 11: Office | 12.357 | 2.8 | 23.917 | Office | 13-15 11 34 11 | Circulation Zone 2B | Fire Alarm Zone 2B | Historic Preservation Zone 2B | Lighting Zone 2B | Occupancy Zone 2B | Ventilation Zone 2B
2BS2 | Second Floor | STAIR | Second Floor | Second Floor | 2.8 | 0 | 15.4516 | 2BS2 | 13-85 21 11: Stairway | 17.332 | 2.8 | 40.2986 | Stairway | 13-85 21 11 | Circulation Zone 2B | Fire Alarm Zone 2B | Historic Preservation Zone 2B | Lighting Zone 2B | Occupancy Zone 2B | Ventilation Zone 2B
1B05 | First Floor | PAT. / STAFF TOILET | First Floor | First Floor | 2.8 | 0 | 4.78883 | 1B05 | 13-41 11 14 21: Restroom | 8.832 | 2.8 | 11.8083 | Restroom | 13-41 11 14 21 | Circulation Zone 1B | Fire Alarm Zone 1B | Historic Preservation Zone 1B | Lighting Zone 1B | Occupancy Zone 1B | Ventilation Zone 1B
2B7 | Second Floor | TECH OFFICE | Second Floor | Second Floor | 2.8 | 0 | 9.9308 | 2B7 | 13-15 11 34 11: Office | 12.685 | 2.8 | 25.8629 | Office | 13-15 11 34 11 | Circulation Zone 2B | Fire Alarm Zone 2B | Historic Preservation Zone 2B | Lighting Zone 2B | Occupancy Zone 2B | Ventilation Zone 2B
1C14 | First Floor | HIST. / INTV. | First Floor | First Floor | 2.8 | 0 | 8.18416 | 1C14 | 13-41 41 99: Other Healing Spaces | 11.509 | 2.8 | 20.4711 | Other Healing Spaces | 13-41 41 99 | Circulation Zone 1C | Fire Alarm Zone 1C | Historic Preservation Zone 1C | Lighting Zone 1C | Occupancy Zone 1C | Ventilation Zone 1C
2C06 | Second Floor | GEN. DENT. DTR #8 | Second Floor | Second Floor | 2.8 | 0 | 12.0034 | 2C06 | 13-41 41 99: Other Healing Spaces | 13.8601 | 2.8 | 30.5886 | Other Healing Spaces | 13-41 41 99 | Circulation Zone 2C | Fire Alarm Zone 2C | Historic Preservation Zone 2C | Lighting Zone 2C | Occupancy Zone 2C | Ventilation Zone 2C
2B24 | Second Floor | BEE TECH | Second Floor | Second Floor | 2.8 | 0 | 9.77601 | 2B24 | 13-15 11 34 11: Office | 12.67 | 2.8 | 24.7086 | Office | 13-15 11 34 11 | Circulation Zone 2B | Fire Alarm Zone 2B | Historic Preservation Zone 2B | Lighting Zone 2B | Occupancy Zone 2B | Ventilation Zone 2B
1D14 | First Floor | SPECIMEN TOILET | First Floor | First Floor | 2.8 | 0 | 4.75347 | 1D14 | 13-41 11 14 21: Restroom | 8.736 | 2.8 | 11.7172 | Restroom | 13-41 11 14 21 | Circulation Zone 1D | Fire Alarm Zone 1D | Historic Preservation Zone 1D | Lighting Zone 1D | Occupancy Zone 1D | Ventilation Zone 1D
1B16 | First Floor | JAN. CL. | First Floor | First Floor | 2.8 | 0 | 4.03581 | 1B16 | 13-75 11 11: Storage Room | 8.609 | 2.8 | 9.59735 | Storage Room | 13-75 11 11 | Circulation Zone 1B | Fire Alarm Zone 1B | Historic Preservation Zone 1B | Lighting Zone 1B | Occupancy Zone 1B | Ventilation Zone 1B
1E09 | First Floor | W. TOILET | First Floor | First Floor | 2.8 | 0 | 5.06216 | 1E09 | 13-41 11 14 21: Restroom | 9.206 | 2.8 | 12.455 | Restroom | 13-41 11 14 21 | Circulation Zone 1E | Fire Alarm Zone 1E | Historic Preservation Zone 1E | Lighting Zone 1E | Occupancy Zone 1E | Ventilation Zone 1E
1A04 | First Floor | TRICARE OFFICE | First Floor | First Floor | 2.8 | 0 | 9.54452 | 1A04 | 13-15 11 34 11: Office | 12.369 | 2.8 | 24.0527 | Office | 13-15 11 34 11 | Circulation Zone 1A | Fire Alarm Zone 1A | Historic Preservation Zone 1A | Lighting Zone 1A | Occupancy Zone 1A | Ventilation Zone 1A
2B15 | Second Floor | WAIT / ERGOM | Second Floor | Second Floor | 2.8 | 0 | 9.11758 | 2B15 | 13-51 31 11: Waiting Room | 12.24 | 2.8 | 23.4474 | Waiting Room | 13-51 31 11 | Circulation Zone 2B | Fire Alarm Zone 2B | Historic Preservation Zone 2B | Lighting Zone 2B | Occupancy Zone 2B | Ventilation Zone 2B
2C19 | Second Floor | CENTRAL ISSUE | Second Floor | Second Floor | 2.8 | 0 | 21.0386 | 2C19 | 13-75 11 11: Storage Room | 19.886 | 2.8 | 55.4459 | Storage Room | 13-75 11 11 | Circulation Zone 2C | Fire Alarm Zone 2C | Historic Preservation Zone 2C | Lighting Zone 2C | Occupancy Zone 2C | Ventilation Zone 2C
1A08 | First Floor | PHARM. OFFICE | First Floor | First Floor | 2.8 | 0 | 10.4499 | 1A08 | 13-15 11 34 11: Office | 12.989 | 2.8 | 26.63 | Office | 13-15 11 34 11 | Circulation Zone 1A | Fire Alarm Zone 1A | Historic Preservation Zone 1A | Lighting Zone 1A | Occupancy Zone 1A | Ventilation Zone 1A
2C18 | Second Floor | ELECTRICAL | Second Floor | Second Floor | 2.8 | 0 | 9.84 | 2C18 | 13-81 21 21: Electrical Room | 12.56 | 2.8 | 25.4146 | Electrical Room | 13-81 21 21 | Circulation Zone 2C | Fire Alarm Zone 2C | Historic Preservation Zone 2C | Lighting Zone 2C | Occupancy Zone 2C | Ventilation Zone 2C
2D07 | Second Floor | SUPER | Second Floor | Second Floor | 2.8 | 0 | 9.21541 | 2D07 | 13-15 11 34 11: Office | 12.135 | 2.8 | 23.7885 | Office | 13-15 11 34 11 | Circulation Zone 2D | Fire Alarm Zone 2D | Historic Preservation Zone 2D | Lighting Zone 2D | Occupancy Zone 2D | Ventilation Zone 2D
1C06 | First Floor | SOIL. UTL. / TRASH | First Floor | First Floor | 2.8 | 0 | 5.40043 | 1C06 | 13-75 41 14: Soiled Storage Room Space | 9.3758 | 2.8 | 13.0309 | Soiled Storage Room Space | 13-75 41 14 | Circulation Zone 1C | Fire Alarm Zone 1C | Historic Preservation Zone 1C | Lighting Zone 1C | Occupancy Zone 1C | Ventilation Zone 1C
2B6 | Second Floor | STAFF TOILET | Second Floor | Second Floor | 2.8 | 0 | 5.65351 | 2B6 | 13-41 11 14 21: Restroom | 9.636 | 2.8 | 14.0355 | Restroom | 13-41 11 14 21 | Circulation Zone 2B | Fire Alarm Zone 2B | Historic Preservation Zone 2B | Lighting Zone 2B | Occupancy Zone 2B | Ventilation Zone 2B
2AC5 | Second Floor | CORRIDOR | Second Floor | Second Floor | 2.8 | 0 | 9.10214 | 2AC5 | 13-85 11 11: Corridor | 13.0124 | 2.8 | 23.466 | Corridor | 13-85 11 11 | Circulation Zone 2A | Fire Alarm Zone 2A | Historic Preservation Zone 2A | Lighting Zone 2A | Occupancy Zone 2A | Ventilation Zone 2A
1B15 | First Floor | FILM VIEW | First Floor | First Floor | 2.8 | 0 | 5.83705 | 1B15 | 13-41 41 31: Scanning/Imaging Room | 9.664 | 2.8 | 14.7091 | Scanning/Imaging Room | 13-41 41 31 | Circulation Zone 1B | Fire Alarm Zone 1B | Historic Preservation Zone 1B | Lighting Zone 1B | Occupancy Zone 1B | Ventilation Zone 1B
1EC2 | First Floor | CORRIDOR | First Floor | First Floor | 2.8 | 0 | 7.91371 | 1EC2 | 13-85 11 11: Corridor | 11.7164 | 2.8 | 20.3634 | Corridor | 13-85 11 11 | Circulation Zone 1E | Fire Alarm Zone 1E | Historic Preservation Zone 1E | Lighting Zone 1E | Occupancy Zone 1E | Ventilation Zone 1E
1B12 | First Floor | CLEAN SUP. & EQUIP. | First Floor | First Floor | 2.8 | 0 | 3.90136 | 1B12 | 13-75 11 11: Storage Room | 8.51705 | 2.8 | 9.24604 | Storage Room | 13-75 11 11 | Circulation Zone 1B | Fire Alarm Zone 1B | Historic Preservation Zone 1B | Lighting Zone 1B | Occupancy Zone 1B | Ventilation Zone 1B
1D24 | First Floor | RECORDS | First Floor | First Floor | 2.8 | 0 | 11.7777 | 1D24 | 13-75 11 11: Storage Room | 13.705 | 2.8 | 30.6724 | Storage Room | 13-75 11 11 | Circulation Zone 1D | Fire Alarm Zone 1D | Historic Preservation Zone 1D | Lighting Zone 1D | Occupancy Zone 1D | Ventilation Zone 1D
2A04 | Second Floor | DENTAL SURGEON OFFICE | Second Floor | Second Floor | 2.8 | 0 | 16.0139 | 2A04 | 13-15 11 34 11: Office | 16.099 | 2.8 | 41.8098 | Office | 13-15 11 34 11 | Circulation Zone 2A | Fire Alarm Zone 2A | Historic Preservation Zone 2A | Lighting Zone 2A | Occupancy Zone 2A | Ventilation Zone 2A
1D26 | First Floor | TOILET | First Floor | First Floor | 2.8 | 0 | 5.04348 | 1D26 | 13-41 11 14 21: Restroom | 9.172 | 2.8 | 12.3514 | Restroom | 13-41 11 14 21 | Circulation Zone 1D | Fire Alarm Zone 1D | Historic Preservation Zone 1D | Lighting Zone 1D | Occupancy Zone 1D | Ventilation Zone 1D
1D17 | First Floor | JAN. CL. | First Floor | First Floor | 2.8 | 0 | 2.05671 | 1D17 | 13-75 11 11: Storage Room | 5.8058 | 2.8 | 4.67952 | Storage Room | 13-75 11 11 | Circulation Zone 1D | Fire Alarm Zone 1D | Historic Preservation Zone 1D | Lighting Zone 1D | Occupancy Zone 1D | Ventilation Zone 1D
1E27 | First Floor | BENCHSTOCK STORAGE | First Floor | First Floor | 2.8 | 0 | 9.51258 | 1E27 | 13-75 11 11: Storage Room | 12.337 | 2.8 | 23.9448 | Storage Room | 13-75 11 11 | Circulation Zone 1E | Fire Alarm Zone 1E | Historic Preservation Zone 1E | Lighting Zone 1E | Occupancy Zone 1E | Ventilation Zone 1E
1A11 | First Floor | JAN. | First Floor | First Floor | 2.8 | 0 | 2.03661 | 1A11 | 13-75 11 11: Storage Room | 6.022 | 2.8 | 4.70014 | Storage Room | 13-75 11 11 | Circulation Zone 1A | Fire Alarm Zone 1A | Historic Preservation Zone 1A | Lighting Zone 1A | Occupancy Zone 1A | Ventilation Zone 1A
1D04 | First Floor | TOILET | First Floor | First Floor | 2.8 | 0 | 5.10462 | 1D04 | 13-41 11 14 21: Restroom | 9.078 | 2.8 | 12.8262 | Restroom | 13-41 11 14 21 | Circulation Zone 1D | Fire Alarm Zone 1D | Historic Preservation Zone 1D | Lighting Zone 1D | Occupancy Zone 1D | Ventilation Zone 1D
1B06 | First Floor | LAB OFFICE | First Floor | First Floor | 2.8 | 0 | 10.4755 | 1B06 | 13-15 11 34 11: Office | 13.1609 | 2.8 | 26.1831 | Office | 13-15 11 34 11 | Circulation Zone 1B | Fire Alarm Zone 1B | Historic Preservation Zone 1B | Lighting Zone 1B | Occupancy Zone 1B | Ventilation Zone 1B
1A14 | First Floor | SUPER / NCOIC | First Floor | First Floor | 2.8 | 0 | 7.22988 | 1A14 | 13-15 11 34 11: Office | 10.1474 | 2.8 | 18.8948 | Office | 13-15 11 34 11 | Circulation Zone 1A | Fire Alarm Zone 1A | Historic Preservation Zone 1A | Lighting Zone 1A | Occupancy Zone 1A | Ventilation Zone 1A
2C01 | Second Floor | DTR SUPPORT | Second Floor | Second Floor | 2.8 | 0 | 8.72505 | 2C01 | 13-15 11 34 11: Office | 11.958 | 2.8 | 22.7232 | Office | 13-15 11 34 11 | Circulation Zone 2C | Fire Alarm Zone 2C | Historic Preservation Zone 2C | Lighting Zone 2C | Occupancy Zone 2C | Ventilation Zone 2C
1B08 | First Floor | CENT. STO. | First Floor | First Floor | 2.8 | 0 | 9.76711 | 1B08 | 13-75 11 11: Storage Room | 12.796 | 2.8 | 25.0222 | Storage Room | 13-75 11 11 | Circulation Zone 1B | Fire Alarm Zone 1B | Historic Preservation Zone 1B | Lighting Zone 1B | Occupancy Zone 1B | Ventilation Zone 1B
1C03 | First Floor | JAN. CL. | First Floor | First Floor | 2.8 | 0 | 4.1106 | 1C03 | 13-75 11 11: Storage Room | 8.924 | 2.8 | 9.93108 | Storage Room | 13-75 11 11 | Circulation Zone 1C | Fire Alarm Zone 1C | Historic Preservation Zone 1C | Lighting Zone 1C | Occupancy Zone 1C | Ventilation Zone 1C
1E15-A | First Floor | GAS STORAGE | First Floor | First Floor | 2.8 | 0 | 2.28945 | 1E15-A | 13-75 41 24: Hazardous Material Storage Space | 7.3006 | 2.8 | 4.64121 | Hazardous Material Storage Space | 13-75 41 24 | Circulation Zone 1E | Fire Alarm Zone 1E | Historic Preservation Zone 1E | Lighting Zone 1E | Occupancy Zone 1E | Ventilation Zone 1E
1E22 | First Floor | SEC. STORAGE | First Floor | First Floor | 2.8 | 0 | 6.27284 | 1E22 | 13-75 11 11: Storage Room | 10.424 | 2.8 | 15.7974 | Storage Room | 13-75 11 11 | Circulation Zone 1E | Fire Alarm Zone 1E | Historic Preservation Zone 1E | Lighting Zone 1E | Occupancy Zone 1E | Ventilation Zone 1E
2B20 | Second Floor | JAN. CL. | Second Floor | Second Floor | 2.8 | 0 | 3.23618 | 2B20 | 13-75 11 11: Storage Room | 7.53312 | 2.8 | 7.91441 | Storage Room | 13-75 11 11 | Circulation Zone 2B | Fire Alarm Zone 2B | Historic Preservation Zone 2B | Lighting Zone 2B | Occupancy Zone 2B | Ventilation Zone 2B
1E21 | First Floor | FLAMABLE STORAGE | First Floor | First Floor | 2.8 | 0 | 5.66451 | 1E21 | 13-75 41 24: Hazardous Material Storage Space | 9.75218 | 2.8 | 13.5165 | Hazardous Material Storage Space | 13-75 41 24 | Circulation Zone 1E | Fire Alarm Zone 1E | Historic Preservation Zone 1E | Lighting Zone 1E | Occupancy Zone 1E | Ventilation Zone 1E
2B2 | Second Floor | JAN. CL. | Second Floor | Second Floor | 2.8 | 0 | 2.20008 | 2B2 | 13-75 11 11: Storage Room | 5.938 | 2.8 | 5.29984 | Storage Room | 13-75 11 11 | Circulation Zone 2B | Fire Alarm Zone 2B | Historic Preservation Zone 2B | Lighting Zone 2B | Occupancy Zone 2B | Ventilation Zone 2B
1E02 | First Floor | ELEV. EQUIP. | First Floor | First Floor | 2.8 | 0 | 5.67552 | 1E02 | 13-81 21 11: Equipment Room | 9.752 | 2.8 | 14.2416 | Equipment Room | 13-81 21 11 | Circulation Zone 1E | Fire Alarm Zone 1E | Historic Preservation Zone 1E | Lighting Zone 1E | Occupancy Zone 1E | Ventilation Zone 1E
1C15 | First Floor | PES ADMIN. OFFICE | First Floor | First Floor | 2.8 | 0 | 15.3931 | 1C15 | 13-15 11 34 11: Office | 15.77 | 2.8 | 40.8184 | Office | 13-15 11 34 11 | Circulation Zone 1C | Fire Alarm Zone 1C | Historic Preservation Zone 1C | Lighting Zone 1C | Occupancy Zone 1C | Ventilation Zone 1C
2D02 | Second Floor | DATA / ARCHIVE STORAGE | Second Floor | Second Floor | 2.8 | 0 | 9.92268 | 2D02 | 13-75 11 11: Storage Room | 12.868 | 2.8 | 25.8318 | Storage Room | 13-75 11 11 | Circulation Zone 2D | Fire Alarm Zone 2D | Historic Preservation Zone 2D | Lighting Zone 2D | Occupancy Zone 2D | Ventilation Zone 2D
2B9 | Second Floor | TECH OFFICE | Second Floor | Second Floor | 2.8 | 0 | 9.94 | 2B9 | 13-15 11 34 11: Office | 12.68 | 2.8 | 25.6738 | Office | 13-15 11 34 11 | Circulation Zone 2B | Fire Alarm Zone 2B | Historic Preservation Zone 2B | Lighting Zone 2B | Occupancy Zone 2B | Ventilation Zone 2B
2B4 | Second Floor | PSYCH TEST | Second Floor | Second Floor | 2.8 | 0 | 9.8406 | 2B4 | 13-15 11 34 11: Office | 12.61 | 2.8 | 25.6738 | Office | 13-15 11 34 11 | Circulation Zone 2B | Fire Alarm Zone 2B | Historic Preservation Zone 2B | Lighting Zone 2B | Occupancy Zone 2B | Ventilation Zone 2B
2D01 | Second Floor | PARTS STORAGE | Second Floor | Second Floor | 2.8 | 0 | 8.92422 | 2D01 | 13-75 11 11: Storage Room | 12.352 | 2.8 | 23.1004 | Storage Room | 13-75 11 11 | Circulation Zone 2D | Fire Alarm Zone 2D | Historic Preservation Zone 2D | Lighting Zone 2D | Occupancy Zone 2D | Ventilation Zone 2D
2AS1 | Second Floor | STAIR | Second Floor | Second Floor | 2.8 | 0 | 14.4483 | 2AS1 | 13-85 21 11: Stairway | 15.3236 | 2.8 | 38.2032 | Stairway | 13-85 21 11 | Circulation Zone 2A | Fire Alarm Zone 2A | Historic Preservation Zone 2A | Lighting Zone 2A | Occupancy Zone 2A | Ventilation Zone 2A
1D37 | First Floor | CLEAN U. | First Floor | First Floor | 2.8 | 0 | 2.35008 | 1D37 | 13-15 21 11 21: Clean Room | 6.09322 | 2.8 | 5.84763 | Clean Room | 13-15 21 11 21 | Circulation Zone 1D | Fire Alarm Zone 1D | Historic Preservation Zone 1D | Lighting Zone 1D | Occupancy Zone 1D | Ventilation Zone 1D
1D03 | First Floor | CLEAN U. | First Floor | First Floor | 2.8 | 0 | 2.35008 | 1D03 | 13-15 21 11 21: Clean Room | 6.09322 | 2.8 | 5.84763 | Clean Room | 13-15 21 11 21 | Circulation Zone 1D | Fire Alarm Zone 1D | Historic Preservation Zone 1D | Lighting Zone 1D | Occupancy Zone 1D | Ventilation Zone 1D

# IfcCovering: Compound Ceiling:ACT 600 x 600mm Grid (220)
PredefinedType: CEILING; Material: Default 0.036 m, Ceiling Tile 600 x 600 0.016 m
PSet_Revit_Phasing - Phase Created: New Construction
PSet_Revit_Other - InstallationDate: InstallationDate; SerialNumber: SerialNumber; WarrantyStartDate: WarrantyStartDate; BarCode: BarCode; AssetIdentifier: AssetIdentifier; TagNumber: TagNumber
Pset_CoveringCommon - Reference: Compound Ceiling:ACT 600 x 600mm Grid; TotalThickness: 0.052 m
PSet_Revit_Constraints - Height Offset From Level: 2.68 m; Room Bounding: no
PSet_Revit_Type_Identity Data - Manufacturer: Manufacturer
PSet_Revit_Type_Graphics - Coarse Scale Fill Color: 0
PSet_Revit_Type_Other - AccessibilityPerformance: AccessibilityPerformance; CodePerformance: CodePerformance; Color: Color; Constituents: Constituents; Features: Features; Finish: Finish; Grade: Grade; Material: Material; ModelReference: ModelReference; NominalHeight: NominalHeight; NominalLength: NominalLength; NominalWidth: NominalWidth; ProductionYear: ProductionYear; Reference: Reference; Shape: Shape; Size: Size; SustainabilityPerformance: SustainabilityPerformance; WarrantyDescription: WarrantyDescription; WarrantyDurationLabor: WarrantyDurationLabor; WarrantyDurationParts: WarrantyDurationParts; WarrantyGuarantorLabor: WarrantyGuarantorLabor; WarrantyGuarantorParts: WarrantyGuarantorParts; ExpectedLife: ExpectedLife; ReplacementCost: ReplacementCost; AssetAccountingType: FIXED; Classification Code: 23-35 70 24; Classification Description: Ceilings; ModelLabel: ModelLabel
PSet_Revit_Type_Construction - Thickness: 0.052 m
Name (Compound Ceiling:ACT 600 x 600mm Grid:...) | In | Perimeter (m) | Area (m2) | Volume (m3) | Level
272284 | First Floor | 12.776 | 8.22531 | 0.427716 | First Floor
269760 | First Floor | 12.29 | 9.19069 | 0.477916 | First Floor
271806 | First Floor | 48.0894 | 51.8156 | 2.69441 | First Floor
278769 | Second Floor | 22.5804 | 16.2993 | 0.847564 | Second Floor
278695 | Second Floor | 28.7188 | 20.9417 | 1.08897 | Second Floor
278707 | Second Floor | 5.512 | 1.8928 | 0.0984256 | Second Floor
278731 | Second Floor | 12.184 | 9.16922 | 0.476799 | Second Floor
278789 | Second Floor | 11.926 | 8.25014 | 0.429007 | Second Floor
276499 | Second Floor | 18.3859 | 19.8431 | 1.03184 | Second Floor
274378 | Second Floor | 9.064 | 4.57226 | 0.237757 | Second Floor
276513 | Second Floor | 50.3363 | 63.2829 | 3.29071 | Second Floor
278747 | Second Floor | 12.184 | 9.16922 | 0.476799 | Second Floor
276406 | Second Floor | 13.2211 | 10.9245 | 0.568074 | Second Floor
278841 | Second Floor | 8.57488 | 4.43177 | 0.230452 | Second Floor
278797 | Second Floor | 12.442 | 9.22564 | 0.479733 | Second Floor
271854 | First Floor | 72.996 | 59.0049 | 3.06826 | First Floor
276544 | Second Floor | 71.452 | 57.8614 | 3.00879 | Second Floor
276582 | Second Floor | 13.8449 | 10.3428 | 0.537826 | Second Floor
273128 | First Floor | 8.742 | 4.65145 | 0.241875 | First Floor
276487 | Second Floor | 13.462 | 10.0234 | 0.521216 | Second Floor
281666 | Second Floor | 15.3938 | 9.95542 | 0.517682 | Second Floor
268673 | First Floor | 42.03 | 55.3775 | 2.87963 | First Floor
277165 | Second Floor | 21.7421 | 12.4663 | 0.648249 | Second Floor
278755 | Second Floor | 18.9241 | 17.4934 | 0.909655 | Second Floor
269795 | First Floor | 8.592 | 4.58078 | 0.238201 | First Floor
278687 | Second Floor | 8.436 | 4.13091 | 0.214807 | Second Floor
346744 | First Floor | 18.352 | 18.7757 | 0.976335 | First Floor
278805 | Second Floor | 12.48 | 8.83451 | 0.459394 | Second Floor
278829 | Second Floor | 23.63 | 32.8779 | 1.70965 | Second Floor
277127 | Second Floor | 11.9442 | 8.91626 | 0.463645 | Second Floor
269085 | First Floor | 47.2508 | 115.12 | 5.98624 | First Floor
273149 | First Floor | 14.532 | 12.4557 | 0.647699 | First Floor
268719 | First Floor | 36.219 | 65.7954 | 3.42136 | First Floor
276457 | Second Floor | 13.2211 | 10.4478 | 0.543285 | Second Floor
268761 | First Floor | 12.3368 | 7.38736 | 0.384143 | First Floor
269314 | First Floor | 13.188 | 10.2186 | 0.531365 | First Floor
268465 | First Floor | 20.2071 | 16.303 | 0.847755 | First Floor
269257 | First Floor | 13.936 | 11.9464 | 0.621213 | First Floor
345544 | First Floor | 19.5421 | 12.7946 | 0.665321 | First Floor
271832 | First Floor | 70.159 | 57.4393 | 2.98684 | First Floor
269077 | First Floor | 11.698 | 8.55171 | 0.444689 | First Floor
274187 | First Floor | 56.56 | 80.2459 | 4.17279 | First Floor
278715 | Second Floor | 14.6881 | 12.5931 | 0.654841 | Second Floor
269265 | First Floor | 13.936 | 11.8534 | 0.616379 | First Floor
269245 | First Floor | 14.248 | 11.8747 | 0.617482 | First Floor
269161 | First Floor | 13.156 | 10.7998 | 0.561591 | First Floor
276687 | Second Floor | 11.358 | 6.88203 | 0.357866 | Second Floor
274394 | Second Floor | 13.2211 | 10.3228 | 0.536786 | Second Floor
277210 | Second Floor | 17.7373 | 11.7039 | 0.608604 | Second Floor
269069 | First Floor | 11.832 | 8.74554 | 0.454768 | First Floor
276438 | Second Floor | 13.2211 | 10.9245 | 0.568074 | Second Floor
274386 | Second Floor | 13.2211 | 10.9245 | 0.568074 | Second Floor
278739 | Second Floor | 12.224 | 9.23674 | 0.48031 | Second Floor
269016 | First Floor | 13.5028 | 10.5609 | 0.549166 | First Floor
278563 | Second Floor | 12.222 | 8.59695 | 0.447042 | Second Floor
269275 | First Floor | 19.164 | 22.1985 | 1.15432 | First Floor
268809 | First Floor | 13.244 | 10.9544 | 0.569631 | First Floor
268695 | First Floor | 15.344 | 14.578 | 0.758056 | First Floor
274368 | Second Floor | 13.2211 | 10.4598 | 0.54391 | Second Floor
269732 | First Floor | 12.856 | 9.09866 | 0.47313 | First Floor
268903 | First Floor | 12.19 | 8.88809 | 0.462181 | First Floor
274246 | First Floor | 5.526 | 1.67862 | 0.0872883 | First Floor
273430 | First Floor | 12.168 | 8.73296 | 0.454114 | First Floor
268753 | First Floor | 13.244 | 10.9544 | 0.569631 | First Floor
277135 | Second Floor | 11.532 | 8.11544 | 0.422003 | Second Floor
273777 | First Floor | 12.052 | 8.99885 | 0.46794 | First Floor
273116 | First Floor | 11.678 | 7.06059 | 0.367151 | First Floor
269125 | First Floor | 14.784 | 13.6597 | 0.710306 | First Floor
277079 | Second Floor | 5.182 | 1.50651 | 0.0783385 | Second Floor
277115 | Second Floor | 14.2971 | 9.15778 | 0.476204 | Second Floor
268930 | First Floor | 11.942 | 8.84742 | 0.460066 | First Floor
269133 | First Floor | 12.492 | 9.10116 | 0.47326 | First Floor
377445 | First Floor | 23.592 | 18.4704 | 0.960462 | First Floor
268415 | First Floor | 11.496 | 8.15852 | 0.424243 | First Floor
273791 | First Floor | 13.698 | 11.0649 | 0.575376 | First Floor
269750 | First Floor | 13.756 | 10.2221 | 0.531551 | First Floor
269710 | First Floor | 8.196 | 4.18471 | 0.217605 | First Floor
276479 | Second Floor | 15.458 | 14.7787 | 0.768494 | Second Floor
274352 | Second Floor | 53.6242 | 43.5515 | 2.26468 | Second Floor
268797 | First Floor | 17.522 | 17.9225 | 0.931972 | First Floor
274286 | First Floor | 5.2848 | 1.67126 | 0.0869055 | First Floor
269051 | First Floor | 13.136 | 9.94955 | 0.517377 | First Floor
269718 | First Floor | 15.688 | 13.7732 | 0.716206 | First Floor
269678 | First Floor | 13.9369 | 11.9478 | 0.621285 | First Floor
277157 | Second Floor | 7.768 | 3.51126 | 0.182586 | Second Floor
269742 | First Floor | 8.7368 | 4.6539 | 0.242003 | First Floor
268552 | First Floor | 20.4078 | 16.9814 | 0.883032 | First Floor
268981 | First Floor | 10.2972 | 5.95577 | 0.3097 | First Floor
273488 | First Floor | 12.6769 | 9.42752 | 0.490231 | First Floor
279431 | Second Floor | 19.8578 | 16.9372 | 0.880736 | Second Floor
268817 | First Floor | 12.916 | 10.07 | 0.523642 | First Floor
268425 | First Floor | 13.886 | 9.47323 | 0.492608 | First Floor
269417 | First Floor | 9.168 | 5.25326 | 0.27317 | First Floor
274234 | First Floor | 12.71 | 9.88238 | 0.513884 | First Floor
278507 | Second Floor | 7.10712 | 2.82658 | 0.146982 | Second Floor
268833 | First Floor | 35.918 | 65.1999 | 3.39039 | First Floor
278817 | Second Floor | 20.15 | 19.4927 | 1.01362 | Second Floor
279106 | Second Floor | 12.106 | 8.42956 | 0.438337 | Second Floor
269304 | First Floor | 13.936 | 11.8826 | 0.617894 | First Floor
268825 | First Floor | 8.616 | 4.41123 | 0.229384 | First Floor
268971 | First Floor | 11.5152 | 7.87915 | 0.409716 | First Floor
268544 | First Floor | 8.384 | 3.54682 | 0.184434 | First Floor
269197 | First Floor | 11.996 | 8.96611 | 0.466238 | First Floor
269153 | First Floor | 8.666 | 4.4482 | 0.231307 | First Floor
276471 | Second Floor | 15.53 | 14.9321 | 0.776467 | Second Floor
268917 | First Floor | 15.376 | 14.3633 | 0.746893 | First Floor
269145 | First Floor | 8.666 | 4.4482 | 0.231307 | First Floor
268886 | First Floor | 30.405 | 47.6375 | 2.47715 | First Floor
276447 | Second Floor | 13.2691 | 11.0043 | 0.572223 | Second Floor
268741 | First Floor | 17.522 | 17.9225 | 0.931972 | First Floor
272729 | First Floor | 11.9532 | 7.87029 | 0.409255 | First Floor
278427 | Second Floor | 12.949 | 9.9254 | 0.516121 | Second Floor
278328 | Second Floor | 13.524 | 11.1552 | 0.58007 | Second Floor
268373 | First Floor | 12.316 | 9.44535 | 0.491158 | First Floor | Pset_CoveringCommon - Finish: Ceiling Tile 600 x 600;
277266 | Second Floor | 24.644 | 28.5857 | 1.48645 | Second Floor
269293 | First Floor | 13.936 | 11.8624 | 0.616843 | First Floor
268437 | First Floor | 12.42 | 9.5107 | 0.494557 | First Floor
278467 | Second Floor | 8.516 | 4.18311 | 0.217522 | Second Floor
269324 | First Floor | 12.176 | 8.49505 | 0.441743 | First Floor
276611 | Second Floor | 5.3818 | 1.87393 | 0.0974446 | Second Floor
278644 | Second Floor | 11.304 | 7.0337 | 0.365752 | Second Floor
268938 | First Floor | 15.086 | 10.2462 | 0.532801 | First Floor
274342 | Second Floor | 9.756 | 4.98879 | 0.259417 | Second Floor
278547 | Second Floor | 12.657 | 9.91341 | 0.515497 | Second Floor
269613 | First Floor | 12.644 | 9.09798 | 0.473095 | First Floor
278576 | Second Floor | 45.9281 | 36.47 | 1.89644 | Second Floor
273459 | First Floor | 13.3288 | 7.12941 | 0.370729 | First Floor
277222 | Second Floor | 12.996 | 10.2499 | 0.532995 | Second Floor
269332 | First Floor | 5.696 | 1.81801 | 0.0945366 | First Floor
277185 | Second Floor | 7.95066 | 3.77244 | 0.196167 | Second Floor
269365 | First Floor | 12.516 | 9.01095 | 0.46857 | First Floor
269061 | First Floor | 18.218 | 18.3456 | 0.953972 | First Floor
269447 | First Floor | 7.97 | 3.42762 | 0.178236 | First Floor
268997 | First Floor | 9.4192 | 4.82734 | 0.251021 | First Floor
274311 | Second Floor | 13.236 | 10.1378 | 0.527168 | Second Floor
276416 | Second Floor | 13.1531 | 10.3931 | 0.540439 | Second Floor
268477 | First Floor | 142.979 | 133.191 | 6.92595 | First Floor
268773 | First Floor | 9.25 | 5.23442 | 0.27219 | First Floor
278555 | Second Floor | 12.031 | 8.82448 | 0.458873 | Second Floor
278477 | Second Floor | 16.836 | 14.3924 | 0.748402 | Second Floor
269585 | First Floor | 46.643 | 64.9592 | 3.37788 | First Floor
269686 | First Floor | 13.9369 | 11.8839 | 0.617961 | First Floor
269463 | First Floor | 7.87805 | 3.30216 | 0.171712 | First Floor
277143 | Second Floor | 28.6413 | 32.3544 | 1.68243 | Second Floor
278300 | Second Floor | 14.806 | 13.3152 | 0.692391 | Second Floor
268663 | First Floor | 13.016 | 10.4006 | 0.540833 | First Floor
269425 | First Floor | 50.639 | 39.8113 | 2.07019 | First Floor
269636 | First Floor | 21.748 | 15.1396 | 0.787259 | First Floor
277099 | Second Floor | 26.1102 | 25.7128 | 1.33707 | Second Floor
268384 | First Floor | 11.73 | 8.59024 | 0.446693 | First Floor
269189 | First Floor | 11.996 | 8.97631 | 0.466768 | First Floor
268402 | First Floor | 11.782 | 7.96938 | 0.414408 | First Floor
278447 | Second Floor | 12.8889 | 9.96802 | 0.518337 | Second Floor
278320 | Second Floor | 11.674 | 8.49589 | 0.441786 | Second Floor
269373 | First Floor | 12.5841 | 9.08738 | 0.472544 | First Floor
268562 | First Floor | 13.936 | 11.7415 | 0.610557 | First Floor
268607 | First Floor | 12.116 | 8.31551 | 0.432407 | First Floor
269381 | First Floor | 27.8608 | 28.2327 | 1.4681 | First Floor
268989 | First Floor | 9.928 | 5.64193 | 0.29338 | First Floor
269669 | First Floor | 13.332 | 10.7208 | 0.55748 | First Floor
277962 | Second Floor | 10.6509 | 7.08958 | 0.368658 | Second Floor
268574 | First Floor | 13.936 | 11.9464 | 0.621213 | First Floor
278405 | Second Floor | 12.5509 | 8.96728 | 0.466299 | Second Floor
268864 | First Floor | 19.428 | 21.1412 | 1.09934 | First Floor
269283 | First Floor | 18.752 | 15.3999 | 0.800794 | First Floor
269471 | First Floor | 13.01 | 9.40654 | 0.48914 | First Floor
278636 | Second Floor | 11.608 | 8.1407 | 0.423317 | Second Floor
269181 | First Floor | 12.132 | 9.1712 | 0.476902 | First Floor
269547 | First Floor | 8.292 | 4.21724 | 0.219296 | First Floor
274323 | Second Floor | 23.912 | 18.4617 | 0.960008 | Second Floor
269205 | First Floor | 9.256 | 5.08627 | 0.264486 | First Floor
277202 | Second Floor | 13.4453 | 10.3485 | 0.53812 | Second Floor
268851 | First Floor | 23.298 | 27.1573 | 1.41218 | First Floor
278338 | Second Floor | 73.8269 | 63.6784 | 3.31128 | Second Floor
278437 | Second Floor | 12.1189 | 8.69774 | 0.452283 | Second Floor
269483 | First Floor | 12.256 | 8.93651 | 0.464699 | First Floor
269660 | First Floor | 9.696 | 5.86803 | 0.305138 | First Floor
277194 | Second Floor | 6.22266 | 2.42 | 0.12584 | Second Floor
276427 | Second Floor | 13.2211 | 10.7437 | 0.558672 | Second Floor
278417 | Second Floor | 14.8388 | 12.7022 | 0.660512 | Second Floor
278660 | Second Floor | 16.164 | 14.1815 | 0.737436 | Second Floor
278493 | Second Floor | 13.0049 | 8.66001 | 0.45032 | Second Floor
278592 | Second Floor | 5.24088 | 1.52813 | 0.0794627 | Second Floor
278620 | Second Floor | 11.744 | 8.37408 | 0.435452 | Second Floor
277320 | Second Floor | 12.064 | 9.07666 | 0.471986 | Second Floor
269237 | First Floor | 13.868 | 11.8131 | 0.614279 | First Floor
268615 | First Floor | 14.6785 | 13.4313 | 0.698429 | First Floor
277254 | Second Floor | 12.064 | 8.86034 | 0.460737 | Second Floor
269573 | First Floor | 9.57795 | 4.90397 | 0.255006 | First Floor
268634 | First Floor | 9.418 | 5.4587 | 0.283852 | First Floor
268651 | First Floor | 12.816 | 9.03638 | 0.469892 | First Floor
268781 | First Floor | 20.463 | 23.2185 | 1.20736 | First Floor
269651 | First Floor | 7.988 | 3.93739 | 0.204744 | First Floor
278389 | Second Floor | 45.466 | 82.1665 | 4.27266 | Second Floor
269499 | First Floor | 36.491 | 51.2575 | 2.66539 | First Floor
278310 | Second Floor | 11.786 | 8.28308 | 0.43072 | Second Floor
269455 | First Floor | 7.97 | 3.42762 | 0.178236 | First Floor
278679 | Second Floor | 9.096 | 5.01267 | 0.260659 | Second Floor
277340 | Second Floor | 17.668 | 13.2534 | 0.689176 | Second Floor
278610 | Second Floor | 13.108 | 9.75662 | 0.507344 | Second Floor
277088 | Second Floor | 20.636 | 13.9259 | 0.724144 | Second Floor
268392 | First Floor | 11.696 | 8.29768 | 0.431479 | First Floor
277328 | Second Floor | 19.696 | 19.8021 | 1.02971 | Second Floor
278457 | Second Floor | 30.7589 | 55.9301 | 2.90837 | Second Floor
269565 | First Floor | 9.38 | 5.0958 | 0.264982 | First Floor
278485 | Second Floor | 11.718 | 8.54177 | 0.444172 | Second Floor
278356 | Second Floor | 16.378 | 15.6638 | 0.814516 | Second Floor
268599 | First Floor | 13.936 | 11.9464 | 0.621213 | First Floor
269555 | First Floor | 12.236 | 8.90697 | 0.463163 | First Floor
278628 | Second Floor | 11.676 | 8.25739 | 0.429384 | Second Floor
278600 | Second Floor | 12.516 | 8.90434 | 0.463025 | Second Floor
269169 | First Floor | 24.412 | 35.8771 | 1.86561 | First Floor
269491 | First Floor | 12.4779 | 9.35111 | 0.486258 | First Floor
269213 | First Floor | 50.8248 | 45.3219 | 2.35674 | First Floor
278652 | Second Floor | 14.344 | 11.7358 | 0.610261 | Second Floor
269523 | First Floor | 8.456 | 4.41043 | 0.229342 | First Floor
278671 | Second Floor | 12.624 | 9.1322 | 0.474874 | Second Floor
268643 | First Floor | 10.87 | 7.31109 | 0.380177 | First Floor
269539 | First Floor | 8.208 | 3.8971 | 0.202649 | First Floor
269531 | First Floor | 8.15205 | 4.12527 | 0.214514 | First Floor

# IfcCovering: Compound Ceiling:Gypsum Board (30)
PredefinedType: CEILING; Material: Metal - Stud Layer 0.045 m, Plasterboard 0.012 m
PSet_Revit_Phasing - Phase Created: New Construction
PSet_Revit_Constraints - Room Bounding: no
PSet_Revit_Other - InstallationDate: InstallationDate; SerialNumber: SerialNumber; WarrantyStartDate: WarrantyStartDate; BarCode: BarCode; AssetIdentifier: AssetIdentifier; TagNumber: TagNumber
Pset_CoveringCommon - Reference: Compound Ceiling:Gypsum Board; TotalThickness: 0.057 m
PSet_Revit_Type_Construction - Thickness: 0.057 m
PSet_Revit_Type_Identity Data - Manufacturer: Manufacturer
PSet_Revit_Type_Graphics - Coarse Scale Fill Color: 0
PSet_Revit_Type_Other - AccessibilityPerformance: AccessibilityPerformance; CodePerformance: CodePerformance; Color: Color; Constituents: Constituents; Features: Features; Finish: Finish; Grade: Grade; Material: Material; ModelReference: ModelReference; NominalHeight: NominalHeight; NominalLength: NominalLength; NominalWidth: NominalWidth; ProductionYear: ProductionYear; Reference: Reference; Shape: Shape; Size: Size; SustainabilityPerformance: SustainabilityPerformance; WarrantyDescription: WarrantyDescription; WarrantyDurationLabor: WarrantyDurationLabor; WarrantyDurationParts: WarrantyDurationParts; WarrantyGuarantorLabor: WarrantyGuarantorLabor; WarrantyGuarantorParts: WarrantyGuarantorParts; ExpectedLife: ExpectedLife; ReplacementCost: ReplacementCost; AssetAccountingType: FIXED; Classification Code: 23-35 70 24; Classification Description: Ceilings; ModelLabel: ModelLabel
Name (Compound Ceiling:Gypsum Board:...) | In | Perimeter (m) | Area (m2) | Volume (m3) | Level | Height Offset From Level (m)
371283 | First Floor | 9.092 | 2.14858 | 0.122469 | First Floor | 2.5
317328 | First Floor | 65.1971 | 67.5822 | 3.85219 | First Floor | 2.8
314477 | First Floor | 2.264 | 0.19504 | 0.0111173 | First Floor | 3.8
378229 | First Floor | 3.5295 | 0.551652 | 0.0314441 | First Floor | 2.5
273443 | First Floor | 4.739 | 1.12775 | 0.0642815 | First Floor | 2.8
371223 | First Floor | 10.8561 | 3.34178 | 0.190481 | First Floor | 2.5
371391 | First Floor | 4.232 | 0.69426 | 0.0395728 | First Floor | 2.5
371172 | First Floor | 5.384 | 1.67922 | 0.0957154 | First Floor | 2.5
312926 | First Floor | 23.8199 | 21.1034 | 1.20287 | First Floor | 3.8
318692 | First Floor | 4.324 | 0.77292 | 0.0440564 | First Floor | 3.8
378193 | First Floor | 3.5295 | 0.551652 | 0.0314441 | First Floor | 2.5
378055 | First Floor | 5.384 | 1.67922 | 0.0957154 | First Floor | 2.5
377269 | Roof - Main | 85.693 | 51.8055 | 2.95291 | Roof - Main | -0.05
396768 | Second Floor | 10.293 | 4.82132 | 0.274815 | Second Floor | 1.55
378079 | First Floor | 10.8561 | 3.34178 | 0.190481 | First Floor | 2.5
378212 | First Floor | 4.232 | 0.69426 | 0.0395728 | First Floor | 2.5
315041 | First Floor | 43.1249 | 28.9689 | 1.65123 | First Floor | 3.8
273451 | First Floor | 5.104 | 1.43982 | 0.0820697 | First Floor | 2.8
318636 | First Floor | 4.3249 | 0.773693 | 0.0441005 | First Floor | 3.8
378107 | First Floor | 4.232 | 0.69426 | 0.0395728 | First Floor | 2.5
420313 | First Floor | 10.966 | 2.06127 | 0.117493 | First Floor | 2.943
420122 | First Floor | 4.956 | 0.841228 | 0.04795 | First Floor | 2.943
396318 | Second Floor | 11.049 | 5.02992 | 0.286706 | Second Floor | 1.55
314485 | First Floor | 2.264 | 0.19504 | 0.0111173 | First Floor | 3.8
420246 | First Floor | 4.876 | 0.824992 | 0.0470245 | First Floor | 2.943
420115 | First Floor | 4.95509 | 0.840292 | 0.0478966 | First Floor | 2.943
420180 | First Floor | 8.0235 | 1.46393 | 0.0834442 | First Floor | 2.943
420253 | First Floor | 8.3885 | 1.77601 | 0.101232 | First Floor | 2.943
420169 | First Floor | 7.916 | 1.44211 | 0.0822004 | First Floor | 2.943
420320 | First Floor | 10.966 | 2.06126 | 0.117492 | First Floor | 2.943

# IfcCurtainWall: Curtain Wall:Chain Link Fence:137002 (2)
In: First Floor
PSet_Revit_Constraints - Base Constraint: First Floor; Base Offset: -1 m; Base is Attached: no; Top Constraint: Up to level: First Floor; Unconnected Height: 2 m; Top Offset: 1 m; Top is Attached: no; Room Bounding: yes; Related to Mass: no
PSet_Revit_Horizontal Grid Pattern - Justification: 1; Angle: 0 deg; Offset: 0 m
PSet_Revit_Other - InstallationDate: InstallationDate; SerialNumber: SerialNumber; WarrantyStartDate: WarrantyStartDate; BarCode: BarCode; AssetIdentifier: AssetIdentifier; TagNumber: TagNumber
Pset_CurtainWallCommon - Reference: Curtain Wall:Chain Link Fence; IsExternal: yes
PSet_Revit_Phasing - Phase Created: New Construction
PSet_Revit_Structural - Structural Usage: 0
PSet_Revit_Vertical Grid Pattern - Number: 1; Justification: 4; Angle: 0 deg; Offset: 0 m
PSet_Revit_Type_Horizontal Mullions - Interior Type: Circular Mullion : 19mm Radius; Border 2 Type: Circular Mullion : 19mm Radius
PSet_Revit_Type_Other - AccessibilityPerformance: AccessibilityPerformance; CodePerformance: CodePerformance; Color: Color; Constituents: Constituents; Features: Features; Finish: Finish; Grade: Grade; Material: Material; ModelReference: ModelReference; NominalHeight: NominalHeight; NominalLength: NominalLength; NominalWidth: NominalWidth; ProductionYear: ProductionYear; Reference: Reference; Shape: Shape; Size: Size; SustainabilityPerformance: SustainabilityPerformance; WarrantyDescription: WarrantyDescription; WarrantyDurationLabor: WarrantyDurationLabor; WarrantyDurationParts: WarrantyDurationParts; WarrantyGuarantorLabor: WarrantyGuarantorLabor; WarrantyGuarantorParts: WarrantyGuarantorParts; ExpectedLife: ExpectedLife; ReplacementCost: ReplacementCost; AssetAccountingType: FIXED; Classification Code: 23-25 40 21 17 11; Classification Description: Chain Link Fences; ModelLabel: ModelLabel
PSet_Revit_Type_Horizontal Grid Pattern - Layout: 0; Spacing: 2.4 m; Adjust for Mullion Size: no
PSet_Revit_Type_Vertical Mullions - Interior Type: Circular Mullion : 19mm Radius; Border 1 Type: Circular Mullion : 19mm Radius; Border 2 Type: Circular Mullion : 19mm Radius
PSet_Revit_Type_Construction - Function: 1; Automatically Embed: no; Curtain Panel: System Panel : Chain Link Fence Panel; Join Condition: 0
PSet_Revit_Type_Vertical Grid Pattern - Layout: 2; Spacing: 1.5 m; Adjust for Mullion Size: no
PSet_Revit_Type_Identity Data - Manufacturer: Manufacturer
Name (Curtain Wall:Chain Link Fence:...) | Number | Length (m) | Area (m2)
347580 | 4 | 2.2 | 4.4
346963 | 2 | 8.60208 | 17.2042

# IfcCurtainWall: Curtain Wall:Storefront - Interior:421061 (8)
In: First Floor
PSet_Revit_Horizontal Grid Pattern - Justification: 1; Angle: 0 deg; Offset: 0 m
PSet_Revit_Constraints - Base Constraint: First Floor; Base is Attached: no; Top Constraint: Up to level: First Floor; Top is Attached: no; Related to Mass: no
Pset_CurtainWallCommon - Reference: Curtain Wall:Storefront - Interior; IsExternal: no
PSet_Revit_Structural - Structural Usage: 0
PSet_Revit_Other - InstallationDate: InstallationDate; SerialNumber: SerialNumber; WarrantyStartDate: WarrantyStartDate; BarCode: BarCode; AssetIdentifier: AssetIdentifier; TagNumber: TagNumber
PSet_Revit_Phasing - Phase Created: New Construction
PSet_Revit_Vertical Grid Pattern - Justification: 4; Angle: 0 deg; Offset: 0 m
PSet_Revit_Type_Vertical Mullions - Interior Type: Rectangular Mullion : 50 x 150mm; Border 1 Type: Rectangular Mullion : 50 x 150mm; Border 2 Type: Rectangular Mullion : 50 x 150mm; sets with these values: 2
PSet_Revit_Type_Construction - Function: 0; Automatically Embed: yes; Curtain Panel: System Panel : Glazed; Join Condition: 1
PSet_Revit_Type_Horizontal Grid Pattern - Layout: 1; Spacing: 2.4 m; Adjust for Mullion Size: no
PSet_Revit_Type_Identity Data - Manufacturer: Manufacturer
PSet_Revit_Type_Other - AccessibilityPerformance: AccessibilityPerformance; CodePerformance: CodePerformance; Color: Color; Constituents: Constituents; Features: Features; Finish: Finish; Grade: Grade; Material: Material; ModelReference: ModelReference; NominalHeight: NominalHeight; NominalLength: NominalLength; NominalWidth: NominalWidth; ProductionYear: ProductionYear; Reference: Reference; Shape: Shape; Size: Size; SustainabilityPerformance: SustainabilityPerformance; WarrantyDescription: WarrantyDescription; WarrantyDurationLabor: WarrantyDurationLabor; WarrantyDurationParts: WarrantyDurationParts; WarrantyGuarantorLabor: WarrantyGuarantorLabor; WarrantyGuarantorParts: WarrantyGuarantorParts; ExpectedLife: ExpectedLife; ReplacementCost: ReplacementCost; AssetAccountingType: FIXED; Classification Code: 23-25 20 14 11; Classification Description: Curtain Walls; ModelLabel: ModelLabel
PSet_Revit_Type_Vertical Grid Pattern - Layout: 3; Spacing: 1.524 m; Adjust for Mullion Size: no
Name (Curtain Wall:Storefront - Interior:...) | PSet_Revit_Horizontal Grid Pattern, Number | Base Offset (m) | Unconnected Height (m) | Top Offset (m) | Room Bounding | PSet_Revit_Vertical Grid Pattern, Number | Length (m) | Area (m2)
283067 | 1 | 0 | 2.8 | 2.8 | no | 4 | 1.532 | 4.116
283882 | 1 | 0 | 2.8 | 2.8 | no | 4 | 1.53155 | 4.11473
284567 | 1 | 1 | 1 | 2 | yes | 1 | 1.534 | 1.534
283767 | 1 | 0 | 2.8 | 2.8 | no | 4 | 0.915 | 2.562
284081 | 1 | 0 | 2.8 | 2.8 | no | 2 | 3.23 | 9.044
283422 | 1 | 0 | 2.8 | 2.8 | no | 4 | 0.915 | 2.562
356367 | 4 | 1 | 1 | 2 | yes | 4 | 0.915 | 0.915
283650 | 1 | 0 | 2.8 | 2.8 | no | 2 | 3.23 | 9.044

# IfcCurtainWall: Curtain Wall:Storefront:29097 (21)
PSet_Revit_Constraints - Base is Attached: no; Top is Attached: no; Room Bounding: yes; Related to Mass: no
PSet_Revit_Vertical Grid Pattern - Justification: 4; Angle: 0 deg; Offset: 0 m
Pset_CurtainWallCommon - Reference: Curtain Wall:Storefront; IsExternal: yes
PSet_Revit_Horizontal Grid Pattern - Justification: 1; Angle: 0 deg; Offset: 0 m
PSet_Revit_Other - InstallationDate: InstallationDate; SerialNumber: SerialNumber; WarrantyStartDate: WarrantyStartDate; BarCode: BarCode; AssetIdentifier: AssetIdentifier; TagNumber: TagNumber
PSet_Revit_Phasing - Phase Created: New Construction
PSet_Revit_Structural - Structural Usage: 0
PSet_Revit_Type_Vertical Mullions - Interior Type: Rectangular Mullion : 50 x 150mm; Border 1 Type: Rectangular Mullion : 50 x 150mm; Border 2 Type: Rectangular Mullion : 50 x 150mm; sets with these values: 2
PSet_Revit_Type_Construction - Function: 1; Automatically Embed: yes; Curtain Panel: System Panel : Glazed; Join Condition: 1
PSet_Revit_Type_Horizontal Grid Pattern - Layout: 1; Spacing: 2.4 m; Adjust for Mullion Size: no
PSet_Revit_Type_Identity Data - Manufacturer: Manufacturer
PSet_Revit_Type_Vertical Grid Pattern - Layout: 3; Spacing: 1.524 m; Adjust for Mullion Size: no
PSet_Revit_Type_Other - AccessibilityPerformance: AccessibilityPerformance; CodePerformance: CodePerformance; Color: Color; Constituents: Constituents; Features: Features; Finish: Finish; Grade: Grade; Material: Material; ModelReference: ModelReference; NominalHeight: NominalHeight; NominalLength: NominalLength; NominalWidth: NominalWidth; ProductionYear: ProductionYear; Reference: Reference; Shape: Shape; Size: Size; SustainabilityPerformance: SustainabilityPerformance; WarrantyDescription: WarrantyDescription; WarrantyDurationLabor: WarrantyDurationLabor; WarrantyDurationParts: WarrantyDurationParts; WarrantyGuarantorLabor: WarrantyGuarantorLabor; WarrantyGuarantorParts: WarrantyGuarantorParts; ExpectedLife: ExpectedLife; ReplacementCost: ReplacementCost; AssetAccountingType: FIXED; Classification Code: 23-25 20 14 11; Classification Description: Curtain Walls; ModelLabel: ModelLabel
Name (Curtain Wall:Storefront:...) | In | Base Constraint | Base Offset (m) | Top Constraint | Unconnected Height (m) | Top Offset (m) | PSet_Revit_Vertical Grid Pattern, Number | PSet_Revit_Horizontal Grid Pattern, Number | Length (m) | Area (m2)
258775 | First Floor | First Floor | 0.905 | Up to level: First Floor | 1.635 | 2.54 | 2 | 4 | 4 | 6.54
258059 | First Floor | First Floor | 0.905 | Up to level: First Floor | 1.635 | 2.54 | 3 | 4 | 5 | 8.175
256998 | First Floor | First Floor | 0.905 | Up to level: First Floor | 1.635 | 2.54 | 3 | 4 | 5.00051 | 8.17584
200372 | Second Floor | Second Floor | 0 | Up to level: Second Floor | 2.4 | 2.4 | 3 | 1 | 6.10616 | 14.506
296057 | Second Floor | Second Floor | 3.07 | Up to level: Roof - Main | 1.508 | -0.102 | 3 | 1 | 5.86 | 9.15689
300135 | Roof - Main | Roof - Main | 0 |  | 4.578 | -0.102 | 5 | 1 | 8.31148 | 12.5546
303219 | Roof - Main | Roof - Main | 1.067 |  | 1.8 | -0.102 | 3 | 1 | 5.18 | 9.324
381859 | Roof - Main | Roof - Main | 1.067 |  | 1.8 | -0.102 | 3 | 1 | 5.18 | 9.324
285990 | Second Floor | Second Floor | 0 | Up to level: Second Floor | 2.4 | 2.4 | 3 | 1 | 4.95277 | 11.7379
301675 | Roof - Main | Roof - Main | 1.067 |  | 4.458 | -0.102 | 5 | 1 | 7.91637 | 22.9198
295590 | Second Floor | Second Floor | 0 | Up to level: Roof - Main | 4.578 | -0.102 | 2 | 1 | 4.137 | 8.91992
263355 | First Floor | First Floor | 0 | Up to level: Second Floor | 4.57 | 0 | 2 | 2 | 3.87 | 20.0381
381965 | Roof - Main | Roof - Main | 1.067 |  | 1.8 | -0.102 | 2 | 1 | 3.89 | 7.002
381976 | Roof - Main | Roof - Main | 1.067 |  | 1.8 | -0.102 | 4 | 1 | 6.905 | 12.429
379197 | Second Floor | Second Floor | 0 | Up to level: Second Floor | 2.4 | 2.4 | 7 | 1 | 11.018 | 26.3784
379239 | Second Floor | Second Floor | 0 | Up to level: Second Floor | 2.4 | 2.4 | 3 | 1 | 4.95277 | 11.7379
375176 | Roof - Main | Roof - Main | 1.067 |  | 1.8 | -0.102 | 4 | 1 | 6.905 | 12.429
374952 | Roof - Main | Roof - Main | 1.067 |  | 1.8 | -0.102 | 2 | 1 | 3.89 | 7.002
220417 | Second Floor | Second Floor | 0 | Up to level: Second Floor | 2.4 | 2.4 | 7 | 1 | 11.261 | 26.8776
298261 | Roof - Main | Roof - Main | 0 |  | 4.578 | -0.102 | 5 | 1 | 7.87031 | 12.3016
381804 | Roof - Main | Roof - Main | 0 |  | 4.578 | -0.102 | 5 | 1 | 7.87031 | 12.3016

# IfcDoor: 0865 x 1500mm (6)
Type - OperationType: SINGLE_SWING_LEFT; ParameterTakesPrecedence: no; Sizeable: no
OverallHeight: 1.5 m; OverallWidth: 0.865 m
PSet_Revit_Other - InstallationDate: InstallationDate; SerialNumber: SerialNumber; WarrantyStartDate: WarrantyStartDate; BarCode: BarCode; AssetIdentifier: AssetIdentifier
PSet_Revit_Phasing - Phase Created: New Construction
Pset_DoorCommon - Reference: M_Toilet Partition:0865 x 1500mm; IsExternal: no; FireRating: Fire Rating
PSet_Revit_Type_Identity Data - Manufacturer: Manufacturer; Type Mark: 56; Fire Rating: Fire Rating; OmniClass Number: 23.30.10.00; OmniClass Title: Doors
PSet_Revit_Type_Other - AccessibilityPerformance: AccessibilityPerformance; CodePerformance: CodePerformance; IsFireExit: IsFireExit; GlazingAreaFraction: GlazingAreaFraction; OperationType: OperationType; Area: Area; Color: Color; Constituents: Constituents; Features: Features; Finish: Finish; Grade: Grade; Material: Material; ModelReference: ModelReference; NominalHeight: NominalHeight; NominalLength: NominalLength; NominalWidth: NominalWidth; ProductionYear: ProductionYear; Reference: Reference; Shape: Shape; Size: Size; SustainabilityPerformance: SustainabilityPerformance; WarrantyDescription: WarrantyDescription; WarrantyDurationLabor: WarrantyDurationLabor; WarrantyDurationParts: WarrantyDurationParts; WarrantyGuarantorLabor: WarrantyGuarantorLabor; WarrantyGuarantorParts: WarrantyGuarantorParts; ExpectedLife: ExpectedLife; ReplacementCost: ReplacementCost; AssetAccountingType: FIXED; ModelLabel: ModelLabel
PSet_Revit_Type_Construction - Function: 0; Wall Closure: 0; Construction Type: Construction Type
PSet_Revit_Type_Dimensions - Thickness: 0.025 m; Height: 1.5 m; Width: 0.865 m
PSet_Revit_Type_Materials and Finishes - Door Material: Laminate - Ivory, Matte
Name (M_Toilet Partition:0865 x 1500mm:0865 x 1500mm:...) | In | Head Height (m) | TagNumber = Mark | Level | Sill Height (m)
413234 | Second Floor | 1.75 | 2C24tp1 | Second Floor | 0.25
412670 | First Floor | 1.75 | 1A09tp2 | First Floor | 0.25
411832 | First Floor | 1.75 | 1A09tp1 | First Floor | 0.25
408825 | Second Floor | 1.5 | 2C07tp1 | Second Floor | 0
237666 | Second Floor | 1.5 | 2C08tp1 | Second Floor | 0
413317 | Second Floor | 1.75 | 2C24tp2 | Second Floor | 0.25

# IfcDoor: 0865 x 1500mm (2)
Type - OperationType: SINGLE_SWING_RIGHT; ParameterTakesPrecedence: no; Sizeable: no
OverallHeight: 1.5 m; OverallWidth: 0.865 m
Pset_DoorCommon - Reference: M_Toilet Partition:0865 x 1500mm; IsExternal: no; FireRating: Fire Rating
PSet_Revit_Phasing - Phase Created: New Construction
PSet_Revit_Constraints - Sill Height: 0.25 m
PSet_Revit_Other - Head Height: 1.75 m; InstallationDate: InstallationDate; SerialNumber: SerialNumber; WarrantyStartDate: WarrantyStartDate; BarCode: BarCode; AssetIdentifier: AssetIdentifier
PSet_Revit_Type_Identity Data - Manufacturer: Manufacturer; Type Mark: 56; Fire Rating: Fire Rating; OmniClass Number: 23.30.10.00; OmniClass Title: Doors
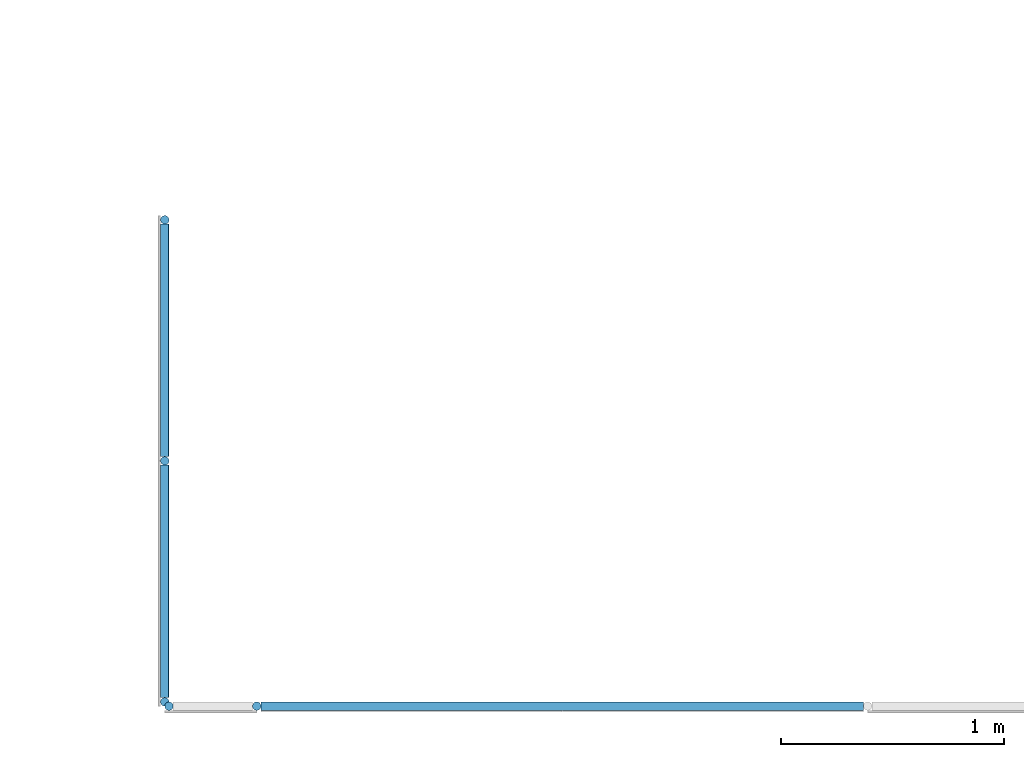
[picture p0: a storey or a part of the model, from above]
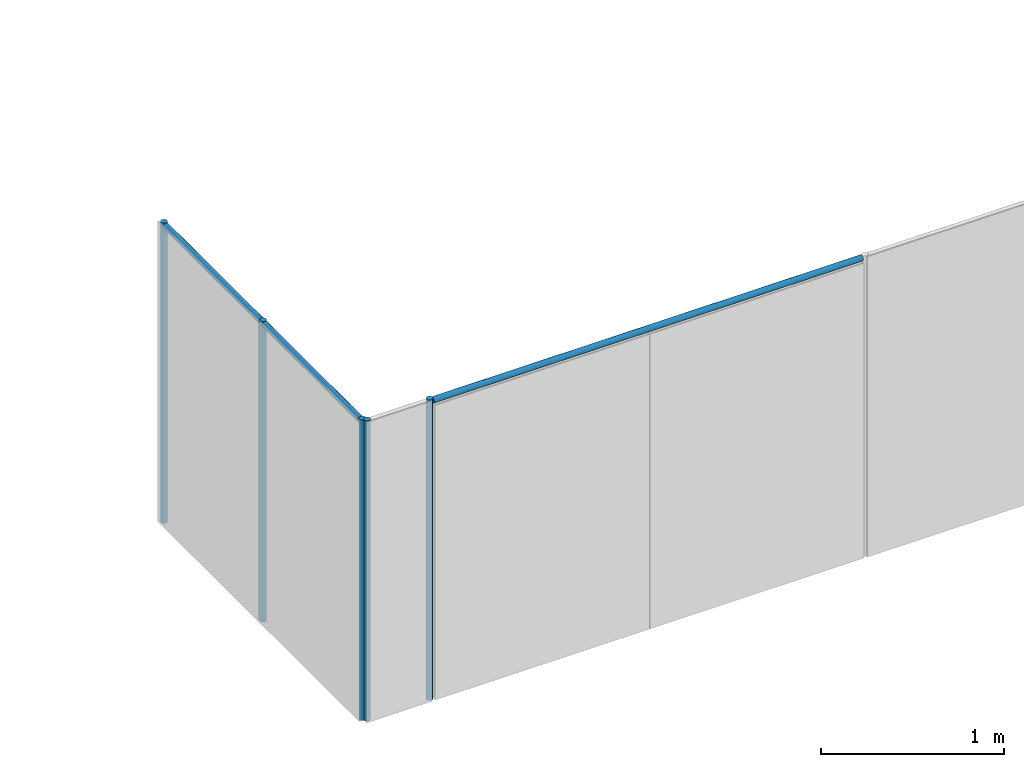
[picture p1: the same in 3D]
Properties of the parts of a building model (IFC2X3), part 3 of 11

# IfcDoor: 0865 x 1500mm (2)
PSet_Revit_Type_Other - AccessibilityPerformance: AccessibilityPerformance; CodePerformance: CodePerformance; IsFireExit: IsFireExit; GlazingAreaFraction: GlazingAreaFraction; OperationType: OperationType; Area: Area; Color: Color; Constituents: Constituents; Features: Features; Finish: Finish; Grade: Grade; Material: Material; ModelReference: ModelReference; NominalHeight: NominalHeight; NominalLength: NominalLength; NominalWidth: NominalWidth; ProductionYear: ProductionYear; Reference: Reference; Shape: Shape; Size: Size; SustainabilityPerformance: SustainabilityPerformance; WarrantyDescription: WarrantyDescription; WarrantyDurationLabor: WarrantyDurationLabor; WarrantyDurationParts: WarrantyDurationParts; WarrantyGuarantorLabor: WarrantyGuarantorLabor; WarrantyGuarantorParts: WarrantyGuarantorParts; ExpectedLife: ExpectedLife; ReplacementCost: ReplacementCost; AssetAccountingType: FIXED; ModelLabel: ModelLabel
PSet_Revit_Type_Construction - Function: 0; Wall Closure: 0; Construction Type: Construction Type
PSet_Revit_Type_Dimensions - Thickness: 0.025 m; Height: 1.5 m; Width: 0.865 m
PSet_Revit_Type_Materials and Finishes - Door Material: Laminate - Ivory, Matte
Name (M_Toilet Partition:0865 x 1500mm:0865 x 1500mm:...) | In | Level | TagNumber = Mark
412955 | Second Floor | Second Floor | 2C23tp1
412771 | First Floor | First Floor | 1A12tp1

# IfcDoor: 0915 x 2134mm (102)
Type - OperationType: SINGLE_SWING_LEFT; ParameterTakesPrecedence: no; Sizeable: no
OverallHeight: 2.134 m; OverallWidth: 0.915 m
PSet_Revit_Phasing - Phase Created: New Construction
Pset_DoorCommon - Reference: M_Single-Flush:0915 x 2134mm; IsExternal: no; FireRating: Fire Rating
PSet_Revit_Other - Head Height: 2.134 m; InstallationDate: InstallationDate; SerialNumber: SerialNumber; WarrantyStartDate: WarrantyStartDate; BarCode: BarCode; AssetIdentifier: AssetIdentifier
PSet_Revit_Constraints - Sill Height: 0 m
PSet_Revit_Type_Other - AccessibilityPerformance: AccessibilityPerformance; CodePerformance: CodePerformance; IsFireExit: IsFireExit; GlazingAreaFraction: GlazingAreaFraction; OperationType: OperationType; Area: Area; Color: Color; Constituents: Constituents; Features: Features; Finish: Finish; Grade: Grade; Material: Material; ModelReference: ModelReference; NominalHeight: NominalHeight; NominalLength: NominalLength; NominalWidth: NominalWidth; ProductionYear: ProductionYear; Reference: Reference; Shape: Shape; Size: Size; SustainabilityPerformance: SustainabilityPerformance; WarrantyDescription: WarrantyDescription; WarrantyDurationLabor: WarrantyDurationLabor; WarrantyDurationParts: WarrantyDurationParts; WarrantyGuarantorLabor: WarrantyGuarantorLabor; WarrantyGuarantorParts: WarrantyGuarantorParts; ExpectedLife: ExpectedLife; ReplacementCost: ReplacementCost; AssetAccountingType: FIXED; ModelLabel: ModelLabel
PSet_Revit_Type_Identity Data - Manufacturer: Manufacturer; Type Mark: 20; Fire Rating: Fire Rating; OmniClass Number: 23.30.10.00; OmniClass Title: Doors
PSet_Revit_Type_Construction - Function: 0; Wall Closure: 0; Construction Type: Construction Type
PSet_Revit_Type_Materials and Finishes - Door Material: Door - Panel; Frame Material: Door - Frame
PSet_Revit_Type_Dimensions - Thickness: 0.051 m; Height: 2.134 m; Trim Projection Ext: 0.025 m; Trim Projection Int: 0.025 m; Trim Width: 0.076 m; Width: 0.915 m
Name (M_Single-Flush:0915 x 2134mm:0915 x 2134mm:...) | In | TagNumber = Mark | Level
229736 | First Floor | 1B14 | First Floor
237881 | Second Floor | 2C12 | Second Floor
224424 | First Floor | 1A15 | First Floor
229319 | First Floor | 1B09 | First Floor
241681 | Second Floor | 2D13 | Second Floor
222929 | First Floor | 1C08 | First Floor
350102 | First Floor | 1E03 | First Floor
250602 | Second Floor | 2D20A | Second Floor
222050 | First Floor | 1C14 | First Floor
222117 | First Floor | 1C12 | First Floor
229539 | First Floor | 1B10 | First Floor
236858 | Second Floor | 2A13 | Second Floor
221992 | First Floor | 1C16 | First Floor
228575 | First Floor | 1B01 | First Floor
240928 | Second Floor | 2B17 | Second Floor
237452 | Second Floor | 2C22 | Second Floor
225305 | First Floor | 1D07 | First Floor
235529 | Second Floor | 2C01 | Second Floor
235194 | Second Floor | 2C07 | Second Floor
230814 | First Floor | 1E02 | First Floor
241049 | Second Floor | 2B15 | Second Floor
238011 | Second Floor | 2C18 | Second Floor
236916 | Second Floor | 2A12 | Second Floor
241351 | Second Floor | 2D21 | Second Floor
241616 | Second Floor | 2D11 | Second Floor
229578 | First Floor | 1B04a | First Floor
228297 | First Floor | 1B13 | First Floor
232154 | First Floor | 1E12 | First Floor
241869 | Second Floor | 2D17 | Second Floor
224600 | First Floor | 1AC2 | First Floor
224980 | First Floor | 1D05 | First Floor
226135 | First Floor | 1D19 | First Floor
236942 | Second Floor | 2A11A | Second Floor
225574 | First Floor | 1D11 | First Floor
225128 | First Floor | 1D06A | First Floor
238096 | Second Floor | 2CC1 | Second Floor
231990 | First Floor | 1E10 | First Floor
225761 | First Floor | 1D12 | First Floor
232339 | First Floor | 1E08 | First Floor
234926 | Second Floor | 2C15 | Second Floor
238316 | Second Floor | 2D08 | Second Floor
224146 | First Floor | 1A05 | First Floor
231377 | First Floor | 1E27 | First Floor
239694 | Second Floor | 2B5 | Second Floor
250444 | Second Floor | 2A11 | Second Floor
241822 | Second Floor | 2D15 | Second Floor
233072 | First Floor | 1E16 | First Floor
224561 | First Floor | 1AC4 | First Floor
235450 | Second Floor | 2C03 | Second Floor
229819 | First Floor | 1B16 | First Floor
223301 | First Floor | 1C02 | First Floor
237743 | Second Floor | 2C10 | Second Floor
223773 | First Floor | 1A08 | First Floor
226850 | First Floor | 1D22A | First Floor
227769 | First Floor | 1D34 | First Floor
242262 | Second Floor | 2B16 | Second Floor
238815 | Second Floor | 2D01 | Second Floor
237063 | Second Floor | 2A01 | Second Floor
230949 | First Floor | 1E01 | First Floor
223504 | First Floor | 1A09 | First Floor
237102 | Second Floor | 2A14 | Second Floor
222740 | First Floor | 1C09 | First Floor
226297 | First Floor | 1D18 | First Floor
224207 | First Floor | 1A03 | First Floor
225828 | First Floor | 1D10 | First Floor
238499 | Second Floor | 2DC2 | Second Floor
402047 | First Floor | 1D01 | First Floor
224653 | First Floor | 1D02 | First Floor
224873 | First Floor | 1DC2 | First Floor
233264 | First Floor | 1E18 | First Floor
234428 | Second Floor | 2C13 | Second Floor
236673 | Second Floor | 2A04 | Second Floor
231213 | First Floor | 1E26 | First Floor
238538 | Second Floor | 2D06A | Second Floor
240003 | Second Floor | 2B3 | Second Floor
239383 | Second Floor | 2B9 | Second Floor
355218 | First Floor | 1D40A | First Floor
238438 | Second Floor | 2D06 | Second Floor
226564 | First Floor | 1C17 | First Floor
231041 | First Floor | 1E29 | First Floor
225637 | First Floor | 1D16 | First Floor
239639 | Second Floor | 2B4 | Second Floor
227305 | First Floor | 1D33A | First Floor
223957 | First Floor | 1A07 | First Floor
232828 | First Floor | 1E14 | First Floor
239888 | Second Floor | 2B01 | Second Floor
364769 | First Floor | 1C03 | First Floor
231726 | First Floor | 1E30 | First Floor
227026 | First Floor | 1D24 | First Floor
223212 | First Floor | 1C06 | First Floor
242080 | Second Floor | 2BC3 | Second Floor
239799 | Second Floor | 2BC4 | Second Floor
237121 | Second Floor | 2C24 | Second Floor
230556 | First Floor | 1B17 | First Floor
227536 | First Floor | 1D28 | First Floor
227366 | First Floor | 1D26 | First Floor
239241 | Second Floor | 2BC6 | Second Floor
239326 | Second Floor | 2B10 | Second Floor
232576 | First Floor | 1E06 | First Floor
239432 | Second Floor | 2B8 | Second Floor
223378 | First Floor | 1C10 | First Floor
226967 | First Floor | 1D23 | First Floor

# IfcDoor: 0915 x 2134mm (113)
Type - OperationType: SINGLE_SWING_RIGHT; ParameterTakesPrecedence: no; Sizeable: no
OverallHeight: 2.134 m; OverallWidth: 0.915 m
Pset_DoorCommon - Reference: M_Single-Flush:0915 x 2134mm; IsExternal: no; FireRating: Fire Rating
PSet_Revit_Phasing - Phase Created: New Construction
PSet_Revit_Other - Head Height: 2.134 m; InstallationDate: InstallationDate; SerialNumber: SerialNumber; WarrantyStartDate: WarrantyStartDate; BarCode: BarCode; AssetIdentifier: AssetIdentifier
PSet_Revit_Constraints - Sill Height: 0 m
PSet_Revit_Type_Other - AccessibilityPerformance: AccessibilityPerformance; CodePerformance: CodePerformance; IsFireExit: IsFireExit; GlazingAreaFraction: GlazingAreaFraction; OperationType: OperationType; Area: Area; Color: Color; Constituents: Constituents; Features: Features; Finish: Finish; Grade: Grade; Material: Material; ModelReference: ModelReference; NominalHeight: NominalHeight; NominalLength: NominalLength; NominalWidth: NominalWidth; ProductionYear: ProductionYear; Reference: Reference; Shape: Shape; Size: Size; SustainabilityPerformance: SustainabilityPerformance; WarrantyDescription: WarrantyDescription; WarrantyDurationLabor: WarrantyDurationLabor; WarrantyDurationParts: WarrantyDurationParts; WarrantyGuarantorLabor: WarrantyGuarantorLabor; WarrantyGuarantorParts: WarrantyGuarantorParts; ExpectedLife: ExpectedLife; ReplacementCost: ReplacementCost; AssetAccountingType: FIXED; ModelLabel: ModelLabel
PSet_Revit_Type_Identity Data - Manufacturer: Manufacturer; Type Mark: 20; Fire Rating: Fire Rating; OmniClass Number: 23.30.10.00; OmniClass Title: Doors
PSet_Revit_Type_Construction - Function: 0; Wall Closure: 0; Construction Type: Construction Type
PSet_Revit_Type_Materials and Finishes - Door Material: Door - Panel; Frame Material: Door - Frame
PSet_Revit_Type_Dimensions - Thickness: 0.051 m; Height: 2.134 m; Trim Projection Ext: 0.025 m; Trim Projection Int: 0.025 m; Trim Width: 0.076 m; Width: 0.915 m
Name (M_Single-Flush:0915 x 2134mm:0915 x 2134mm:...) | In | Mark | TagNumber | Level
223704 | First Floor | 1A10 | 1A10 | First Floor
224302 | First Floor | 1AC5 | 1AC5 | First Floor
229157 | First Floor | 1B07 | 1B07 | First Floor
221919 | First Floor | 1C19 | 1C19 | First Floor
229354 | First Floor | 1B11 | 1B11 | First Floor
242319 | Second Floor | 2B18 | 2B18 | Second Floor
241266 | Second Floor | 2B12 | 2B13 | Second Floor
238171 | Second Floor | 2D09 | 2D09 | Second Floor
241124 | Second Floor | 2B14 | 2B14 | Second Floor
229120 | First Floor | 1B05 | 1B05 | First Floor
241191 | Second Floor | 2B13 | 2B13 | Second Floor
250515 | Second Floor | 2AC2A | 2AC2A | Second Floor
235604 | Second Floor | 2AC2 | 2AC2 | Second Floor
240845 | Second Floor | 2B20 | 2B20 | Second Floor
225517 | First Floor | 1D13 | 1D13 | First Floor
228981 | First Floor | 1B04 | 1B04 | First Floor
235326 | Second Floor | 2CC3 | 2CC3 | Second Floor
241789 | Second Floor | 2D14 | 2D14 | Second Floor
224469 | First Floor | 1A13 | 1A13 | First Floor
228650 | First Floor | 1B03 | 1B03 | First Floor
229427 | First Floor | 1B06 | 1B06 | First Floor
235137 | Second Floor | 2C05 | 2C05 | Second Floor
240501 | Second Floor | 2B23 | 2B23 | Second Floor
237365 | Second Floor | 2C23 | 2C23 | Second Floor
237928 | Second Floor | 2C19 | 2C19 | Second Floor
240436 | Second Floor | 2B25 | 2B25 | Second Floor
240676 | Second Floor | 2B22 | 2B22 | Second Floor
222344 | First Floor | 1C18 | 1C18 | First Floor
224077 | First Floor | 1A04 | 1A04 | First Floor
231274 | First Floor | 1E25 | 1E25 | First Floor
227926 | First Floor | 1D40 | 1D40 | First Floor
241581 | Second Floor | 2D10 | 2D10 | Second Floor
236819 | Second Floor | 2A02 | 2A02 | Second Floor
236780 | Second Floor | 2A03 | 2A03 | Second Floor
229478 | First Floor | 1B08 | 1B08 | First Floor
228354 | First Floor | 1B15 | 1B15 | First Floor
231180 | First Floor | 1EC1 | 1EC1 | First Floor
225472 | First Floor | 1D09 | 1D09 | First Floor
231755 | First Floor | 1E23 | 1E23 | First Floor
235051 | Second Floor | 2C06 | 2C06 | Second Floor
241448 | Second Floor | 2D21A | 2D21A | Second Floor
362567 | First Floor | 1D17 | 1D17 | First Floor
227830 | First Floor | 1D36 | 1D36 | First Floor
226204 | First Floor | 1D20 | 1D20 | First Floor
228516 | First Floor | 1BC2 | 1BC2 | First Floor
228938 | First Floor | 1B02 | 1B02 | First Floor
224343 | First Floor | 1A15a | 1A15a | First Floor
231452 | First Floor | 1E28 | 1E28 | First Floor
241748 | Second Floor | 2D16 | 2D16 | Second Floor
226625 | First Floor | 1C15 | 1C15 | First Floor
226666 | First Floor | 1C13 | 1C13 | First Floor
232789 | First Floor | 1EC3 | 1EC3 | First Floor
230994 | First Floor | 1E04 | 1E04 | First Floor
240588 | Second Floor | 2B19 | 2B19 | Second Floor
228897 | First Floor | 1BC1 | 1BC1 | First Floor
225051 | First Floor | 1D06 | 1D06 | First Floor
223840 | First Floor | 1A11 | 1A11 | First Floor
240742 | Second Floor | 2B21 | 2B21 | Second Floor
230781 | First Floor | 1BC4 | 1BC4 | First Floor
403890 | First Floor | 1DC5 | 1DC5 | First Floor
223137 | First Floor | 1C04 | 1C04 | First Floor
225680 | First Floor | 1D14 | 1D14 | First Floor
234745 | Second Floor | 2C11 | 2C11 | Second Floor
227879 | First Floor | 1D38 | 1D38 | First Floor
229671 | First Floor | 1B12 | 1B12 | First Floor
234202 | First Floor | 1DC8 | 1DC8 | First Floor
225922 | First Floor | 1DC4 | 1DC4 | First Floor
226737 | First Floor | 1D22 | 1D22 | First Floor
232087 | First Floor | 1E09 | 1E09 | First Floor
227615 | First Floor | 1D32 | 1D32 | First Floor
231651 | First Floor | 1E22 | 1E22 | First Floor
223667 | First Floor | 1A12 | 1A12 | First Floor
223030 | First Floor | 1C05 | 1C05 | First Floor
235096 | Second Floor | 2C04 | 2C04 | Second Floor
232239 | First Floor | 1E11 | 1E11 | First Floor
238379 | Second Floor | 2D07 | 2D07 | Second Floor
227199 | First Floor | 1D33 | 1D33 | First Floor
234995 | Second Floor | 2C09 | 2C09 | Second Floor
227455 | First Floor | 1D25 | 1D25 | First Floor
235395 | Second Floor | 2C08 | 2C08 | Second Floor
239511 | Second Floor | 2B6 | 2B6 | Second Floor
224018 | First Floor | 1A06 | 1A06 | First Floor
227652 | First Floor | 1D35 | 1D35 | First Floor
240310 | Second Floor | 2B2 | 2B2 | Second Floor
242003 | Second Floor | 2D20 | 2D20 | Second Floor
226489 | First Floor | 1C18A | 1C18A | First Floor
230607 | First Floor | 1B23 | 1B23 | First Floor
226378 | First Floor | 1D21 | 1D21 | First Floor
234077 | First Floor | 1D39 | 1D39 | First Floor
238748 | Second Floor | 2D04 | 2D04 | Second Floor
240347 | Second Floor | 2B24 | 2B24 | Second Floor
225883 | First Floor | 1D08 | 1D08 | First Floor
239186 | Second Floor | 2BC1 | 2BC1 | Second Floor
238617 | Second Floor | 2D04A | 2D04A | Second Floor
223457 | First Floor | 1CC1 | 1CC1 | First Floor
232467 | First Floor | 1E07 | 1E07 | First Floor
236966 | Second Floor | 2AC5 | 2AC5 | Second Floor
234389 | Second Floor | 2C16 | 2C16 | Second Floor
233169 | First Floor | 1E19 | 1E19 | First Floor
239590 | Second Floor | 2B7 | 2B7 | Second Floor
234843 | Second Floor | 2C17 | 2C17 | Second Floor
232292 | First Floor | 1E33 | 1E33 | First Floor
223429 | First Floor | 1C07 | 1C07 | First Floor
241966 | Second Floor | 2D19 | 2D19 | Second Floor
230738 | First Floor | 1B21 | 1B21 | First Floor
234796 | Second Floor | 2CC3A | 2CC3A | Second Floor
227228 | First Floor | 1D31 | 1D31 | First Floor
227136 | First Floor | 1D30 | 1D30 | First Floor
239113 | Second Floor | 2BC2 | 2BC2 | Second Floor
232388 | First Floor | 1E07A | 1E07A | First Floor
238886 | Second Floor | 2D02 | 2D02 | Second Floor
227089 | First Floor | 1D27 | 1D27 | First Floor
238921 | Second Floor | 2D03 | 2D03 | Second Floor

# IfcDoor: 0915 x 2134mm Exterior (2)
In: First Floor
Type - OperationType: SINGLE_SWING_LEFT; ParameterTakesPrecedence: no; Sizeable: no
OverallHeight: 2.134 m; OverallWidth: 0.915 m
PSet_Revit_Other - Head Height: 2.134 m; InstallationDate: InstallationDate; SerialNumber: SerialNumber; WarrantyStartDate: WarrantyStartDate; BarCode: BarCode; AssetIdentifier: AssetIdentifier
PSet_Revit_Phasing - Phase Created: New Construction
Pset_DoorCommon - Reference: M_Single-Flush:0915 x 2134mm Exterior; IsExternal: yes; FireRating: Fire Rating
PSet_Revit_Constraints - Level: First Floor; Sill Height: 0 m
PSet_Revit_Type_Materials and Finishes - Door Material: Door - Panel; Frame Material: Door - Frame
PSet_Revit_Type_Dimensions - Thickness: 0.051 m; Height: 2.134 m; Trim Projection Ext: 0.025 m; Trim Projection Int: 0.025 m; Trim Width: 0.076 m; Width: 0.915 m
PSet_Revit_Type_Other - AccessibilityPerformance: AccessibilityPerformance; CodePerformance: CodePerformance; IsFireExit: IsFireExit; GlazingAreaFraction: GlazingAreaFraction; OperationType: OperationType; Area: Area; Color: Color; Constituents: Constituents; Features: Features; Finish: Finish; Grade: Grade; Material: Material; ModelReference: ModelReference; NominalHeight: NominalHeight; NominalLength: NominalLength; NominalWidth: NominalWidth; ProductionYear: ProductionYear; Reference: Reference; Shape: Shape; Size: Size; SustainabilityPerformance: SustainabilityPerformance; WarrantyDescription: WarrantyDescription; WarrantyDurationLabor: WarrantyDurationLabor; WarrantyDurationParts: WarrantyDurationParts; WarrantyGuarantorLabor: WarrantyGuarantorLabor; WarrantyGuarantorParts: WarrantyGuarantorParts; ExpectedLife: ExpectedLife; ReplacementCost: ReplacementCost; AssetAccountingType: FIXED; ModelLabel: ModelLabel
PSet_Revit_Type_Identity Data - Manufacturer: Manufacturer; Type Mark: 59; Fire Rating: Fire Rating; OmniClass Number: 23.30.10.00; OmniClass Title: Doors
PSet_Revit_Type_Construction - Function: 1; Wall Closure: 0; Construction Type: Construction Type
Name (M_Single-Flush:0915 x 2134mm Exterior:0915 x 2134mm Exterior:...) | Mark = TagNumber
231495 | 1E20
233711 | 1E17

# IfcDoor: 0915 x 2134mm Exterior (5)
In: First Floor
Type - OperationType: SINGLE_SWING_RIGHT; ParameterTakesPrecedence: no; Sizeable: no
OverallHeight: 2.134 m; OverallWidth: 0.915 m
PSet_Revit_Phasing - Phase Created: New Construction
PSet_Revit_Constraints - Level: First Floor; Sill Height: 0 m
Pset_DoorCommon - Reference: M_Single-Flush:0915 x 2134mm Exterior; IsExternal: yes; FireRating: Fire Rating
PSet_Revit_Other - Head Height: 2.134 m; InstallationDate: InstallationDate; SerialNumber: SerialNumber; WarrantyStartDate: WarrantyStartDate; BarCode: BarCode; AssetIdentifier: AssetIdentifier
PSet_Revit_Type_Materials and Finishes - Door Material: Door - Panel; Frame Material: Door - Frame
PSet_Revit_Type_Dimensions - Thickness: 0.051 m; Height: 2.134 m; Trim Projection Ext: 0.025 m; Trim Projection Int: 0.025 m; Trim Width: 0.076 m; Width: 0.915 m
PSet_Revit_Type_Other - AccessibilityPerformance: AccessibilityPerformance; CodePerformance: CodePerformance; IsFireExit: IsFireExit; GlazingAreaFraction: GlazingAreaFraction; OperationType: OperationType; Area: Area; Color: Color; Constituents: Constituents; Features: Features; Finish: Finish; Grade: Grade; Material: Material; ModelReference: ModelReference; NominalHeight: NominalHeight; NominalLength: NominalLength; NominalWidth: NominalWidth; ProductionYear: ProductionYear; Reference: Reference; Shape: Shape; Size: Size; SustainabilityPerformance: SustainabilityPerformance; WarrantyDescription: WarrantyDescription; WarrantyDurationLabor: WarrantyDurationLabor; WarrantyDurationParts: WarrantyDurationParts; WarrantyGuarantorLabor: WarrantyGuarantorLabor; WarrantyGuarantorParts: WarrantyGuarantorParts; ExpectedLife: ExpectedLife; ReplacementCost: ReplacementCost; AssetAccountingType: FIXED; ModelLabel: ModelLabel
PSet_Revit_Type_Identity Data - Manufacturer: Manufacturer; Type Mark: 59; Fire Rating: Fire Rating; OmniClass Number: 23.30.10.00; OmniClass Title: Doors
PSet_Revit_Type_Construction - Function: 1; Wall Closure: 0; Construction Type: Construction Type
Name (M_Single-Flush:0915 x 2134mm Exterior:0915 x 2134mm Exterior:...) | TagNumber = Mark
222415 | 1CC3
231622 | 1E21
252490 | 1AC5a
232975 | 1EC1A
252441 | 1AC3

# IfcDoor: 0915 x 2134mm Rated (3)
Type - OperationType: SINGLE_SWING_LEFT; ParameterTakesPrecedence: no; Sizeable: no
OverallHeight: 2.134 m; OverallWidth: 0.915 m
PSet_Revit_Constraints - Sill Height: 0 m
Pset_DoorCommon - Reference: M_Single-Flush:0915 x 2134mm Rated; IsExternal: no; FireRating: Fire Rating
PSet_Revit_Other - Head Height: 2.134 m; InstallationDate: InstallationDate; SerialNumber: SerialNumber; WarrantyStartDate: WarrantyStartDate; BarCode: BarCode; AssetIdentifier: AssetIdentifier
PSet_Revit_Phasing - Phase Created: New Construction
PSet_Revit_Type_Construction - Function: 0; Wall Closure: 0; Construction Type: Construction Type
PSet_Revit_Type_Materials and Finishes - Door Material: Door - Panel; Frame Material: Door - Frame
PSet_Revit_Type_Identity Data - Manufacturer: Manufacturer; Type Mark: 61; Fire Rating: Fire Rating; OmniClass Number: 23.30.10.00; OmniClass Title: Doors
PSet_Revit_Type_Dimensions - Thickness: 0.051 m; Height: 2.134 m; Trim Projection Ext: 0.025 m; Trim Projection Int: 0.025 m; Trim Width: 0.076 m; Width: 0.915 m
PSet_Revit_Type_Other - AccessibilityPerformance: AccessibilityPerformance; CodePerformance: CodePerformance; IsFireExit: IsFireExit; GlazingAreaFraction: GlazingAreaFraction; OperationType: OperationType; Area: Area; Color: Color; Constituents: Constituents; Features: Features; Finish: Finish; Grade: Grade; Material: Material; ModelReference: ModelReference; NominalHeight: NominalHeight; NominalLength: NominalLength; NominalWidth: NominalWidth; ProductionYear: ProductionYear; Reference: Reference; Shape: Shape; Size: Size; SustainabilityPerformance: SustainabilityPerformance; WarrantyDescription: WarrantyDescription; WarrantyDurationLabor: WarrantyDurationLabor; WarrantyDurationParts: WarrantyDurationParts; WarrantyGuarantorLabor: WarrantyGuarantorLabor; WarrantyGuarantorParts: WarrantyGuarantorParts; ExpectedLife: ExpectedLife; ReplacementCost: ReplacementCost; AssetAccountingType: FIXED; ModelLabel: ModelLabel
Name (M_Single-Flush:0915 x 2134mm Rated:0915 x 2134mm Rated:...) | In | Level | Mark = TagNumber
222571 | First Floor | First Floor | 1CS3
230209 | First Floor | First Floor | 1BS2
234664 | Second Floor | Second Floor | 2CS3

# IfcDoor: 0915 x 2134mm Rated (2)
Type - OperationType: SINGLE_SWING_RIGHT; ParameterTakesPrecedence: no; Sizeable: no
OverallHeight: 2.134 m; OverallWidth: 0.915 m
PSet_Revit_Other - InstallationDate: InstallationDate; SerialNumber: SerialNumber; WarrantyStartDate: WarrantyStartDate; BarCode: BarCode; AssetIdentifier: AssetIdentifier
Pset_DoorCommon - Reference: M_Single-Flush:0915 x 2134mm Rated; IsExternal: no; FireRating: Fire Rating
PSet_Revit_Phasing - Phase Created: New Construction
PSet_Revit_Type_Construction - Function: 0; Wall Closure: 0; Construction Type: Construction Type
PSet_Revit_Type_Materials and Finishes - Door Material: Door - Panel; Frame Material: Door - Frame
PSet_Revit_Type_Identity Data - Manufacturer: Manufacturer; Type Mark: 61; Fire Rating: Fire Rating; OmniClass Number: 23.30.10.00; OmniClass Title: Doors
PSet_Revit_Type_Dimensions - Thickness: 0.051 m; Height: 2.134 m; Trim Projection Ext: 0.025 m; Trim Projection Int: 0.025 m; Trim Width: 0.076 m; Width: 0.915 m
PSet_Revit_Type_Other - AccessibilityPerformance: AccessibilityPerformance; CodePerformance: CodePerformance; IsFireExit: IsFireExit; GlazingAreaFraction: GlazingAreaFraction; OperationType: OperationType; Area: Area; Color: Color; Constituents: Constituents; Features: Features; Finish: Finish; Grade: Grade; Material: Material; ModelReference: ModelReference; NominalHeight: NominalHeight; NominalLength: NominalLength; NominalWidth: NominalWidth; ProductionYear: ProductionYear; Reference: Reference; Shape: Shape; Size: Size; SustainabilityPerformance: SustainabilityPerformance; WarrantyDescription: WarrantyDescription; WarrantyDurationLabor: WarrantyDurationLabor; WarrantyDurationParts: WarrantyDurationParts; WarrantyGuarantorLabor: WarrantyGuarantorLabor; WarrantyGuarantorParts: WarrantyGuarantorParts; ExpectedLife: ExpectedLife; ReplacementCost: ReplacementCost; AssetAccountingType: FIXED; ModelLabel: ModelLabel
Name (M_Single-Flush:0915 x 2134mm Rated:0915 x 2134mm Rated:...) | In | Mark = TagNumber | Head Height (m) | Level | Sill Height (m)
471867 | First Floor | 1E05 | 2.384 | First Floor | 0.25
242185 | Second Floor | 2BS2 | 2.134 | Second Floor | 0

# IfcDoor: 1.220 x 2134mm, M_Single-Flush:1.220 x 2134mm:1.220 x 2134mm:230394
In: First Floor
Type - OperationType: SINGLE_SWING_RIGHT; ParameterTakesPrecedence: no; Sizeable: no
OverallHeight: 2.134 m; OverallWidth: 1.22 m
PSet_Revit_Type_Dimensions - Thickness: 0.051 m; Height: 2.134 m; Trim Projection Ext: 0.025 m; Trim Projection Int: 0.025 m; Trim Width: 0.076 m; Width: 1.22 m
Pset_DoorCommon - Reference: M_Single-Flush:1.220 x 2134mm; IsExternal: no; FireRating: Fire Rating
PSet_Revit_Type_Identity Data - Manufacturer: Manufacturer; Type Mark: 60; Fire Rating: Fire Rating; OmniClass Number: 23.30.10.00; OmniClass Title: Doors
PSet_Revit_Type_Construction - Function: 0; Wall Closure: 0; Construction Type: Construction Type
PSet_Revit_Identity Data - Mark: 1B19
PSet_Revit_Other - Head Height: 2.134 m; InstallationDate: InstallationDate; SerialNumber: SerialNumber; WarrantyStartDate: WarrantyStartDate; BarCode: BarCode; AssetIdentifier: AssetIdentifier; TagNumber: 1B19
PSet_Revit_Constraints - Level: First Floor; Sill Height: 0 m
PSet_Revit_Type_Materials and Finishes - Door Material: Door - Panel; Frame Material: Door - Frame
PSet_Revit_Phasing - Phase Created: New Construction
PSet_Revit_Type_Other - AccessibilityPerformance: AccessibilityPerformance; CodePerformance: CodePerformance; IsFireExit: IsFireExit; GlazingAreaFraction: GlazingAreaFraction; OperationType: OperationType; Area: Area; Color: Color; Constituents: Constituents; Features: Features; Finish: Finish; Grade: Grade; Material: Material; ModelReference: ModelReference; NominalHeight: NominalHeight; NominalLength: NominalLength; NominalWidth: NominalWidth; ProductionYear: ProductionYear; Reference: Reference; Shape: Shape; Size: Size; SustainabilityPerformance: SustainabilityPerformance; WarrantyDescription: WarrantyDescription; WarrantyDurationLabor: WarrantyDurationLabor; WarrantyDurationParts: WarrantyDurationParts; WarrantyGuarantorLabor: WarrantyGuarantorLabor; WarrantyGuarantorParts: WarrantyGuarantorParts; ExpectedLife: ExpectedLife; ReplacementCost: ReplacementCost; AssetAccountingType: FIXED; ModelLabel: ModelLabel

# IfcDoor: 1.220 x 2134mm Exterior, M_Single-Flush:1.220 x 2134mm Exterior:1.220 x 2134mm Exterior:233580
In: First Floor
Type - OperationType: SINGLE_SWING_RIGHT; ParameterTakesPrecedence: no; Sizeable: no
OverallHeight: 2.134 m; OverallWidth: 1.22 m
Pset_DoorCommon - Reference: M_Single-Flush:1.220 x 2134mm Exterior; IsExternal: yes; FireRating: Fire Rating
PSet_Revit_Phasing - Phase Created: New Construction
PSet_Revit_Type_Dimensions - Thickness: 0.051 m; Height: 2.134 m; Trim Projection Ext: 0.025 m; Trim Projection Int: 0.025 m; Trim Width: 0.076 m; Width: 1.22 m
PSet_Revit_Type_Other - AccessibilityPerformance: AccessibilityPerformance; CodePerformance: CodePerformance; IsFireExit: IsFireExit; GlazingAreaFraction: GlazingAreaFraction; OperationType: OperationType; Area: Area; Color: Color; Constituents: Constituents; Features: Features; Finish: Finish; Grade: Grade; Material: Material; ModelReference: ModelReference; NominalHeight: NominalHeight; NominalLength: NominalLength; NominalWidth: NominalWidth; ProductionYear: ProductionYear; Reference: Reference; Shape: Shape; Size: Size; SustainabilityPerformance: SustainabilityPerformance; WarrantyDescription: WarrantyDescription; WarrantyDurationLabor: WarrantyDurationLabor; WarrantyDurationParts: WarrantyDurationParts; WarrantyGuarantorLabor: WarrantyGuarantorLabor; WarrantyGuarantorParts: WarrantyGuarantorParts; ExpectedLife: ExpectedLife; ReplacementCost: ReplacementCost; AssetAccountingType: FIXED; ModelLabel: ModelLabel
PSet_Revit_Type_Identity Data - Manufacturer: Manufacturer; Type Mark: 34; Fire Rating: Fire Rating; OmniClass Number: 23.30.10.00; OmniClass Title: Doors
PSet_Revit_Constraints - Level: First Floor; Sill Height: 0 m
PSet_Revit_Type_Construction - Function: 1; Wall Closure: 0; Construction Type: Construction Type
PSet_Revit_Type_Materials and Finishes - Door Material: Door - Panel; Frame Material: Door - Frame
PSet_Revit_Identity Data - Mark: 1EC4
PSet_Revit_Other - Head Height: 2.134 m; InstallationDate: InstallationDate; SerialNumber: SerialNumber; WarrantyStartDate: WarrantyStartDate; BarCode: BarCode; AssetIdentifier: AssetIdentifier; TagNumber: 1EC4

# IfcDoor: 1000 x 2134mm, M_Single-Flush:1000 x 2134mm:1000 x 2134mm:230127
In: First Floor
Type - OperationType: SINGLE_SWING_RIGHT; ParameterTakesPrecedence: no; Sizeable: no
OverallHeight: 2.134 m; OverallWidth: 1 m
PSet_Revit_Identity Data - Mark: 1BC3
Pset_DoorCommon - Reference: M_Single-Flush:1000 x 2134mm; IsExternal: no; FireRating: Fire Rating
PSet_Revit_Constraints - Level: First Floor; Sill Height: 0 m
PSet_Revit_Type_Materials and Finishes - Door Material: Door - Panel; Frame Material: Door - Frame
PSet_Revit_Type_Dimensions - Thickness: 0.051 m; Height: 2.134 m; Trim Projection Ext: 0.025 m; Trim Projection Int: 0.025 m; Trim Width: 0.076 m; Width: 1 m
PSet_Revit_Other - Head Height: 2.134 m; InstallationDate: InstallationDate; SerialNumber: SerialNumber; WarrantyStartDate: WarrantyStartDate; BarCode: BarCode; AssetIdentifier: AssetIdentifier; TagNumber: 1BC3
PSet_Revit_Phasing - Phase Created: New Construction
PSet_Revit_Type_Construction - Function: 0; Wall Closure: 0; Construction Type: Construction Type
PSet_Revit_Type_Identity Data - Manufacturer: Manufacturer; Type Mark: 33; Fire Rating: Fire Rating; OmniClass Number: 23.30.10.00; OmniClass Title: Doors
PSet_Revit_Type_Other - AccessibilityPerformance: AccessibilityPerformance; CodePerformance: CodePerformance; IsFireExit: IsFireExit; GlazingAreaFraction: GlazingAreaFraction; OperationType: OperationType; Area: Area; Color: Color; Constituents: Constituents; Features: Features; Finish: Finish; Grade: Grade; Material: Material; ModelReference: ModelReference; NominalHeight: NominalHeight; NominalLength: NominalLength; NominalWidth: NominalWidth; ProductionYear: ProductionYear; Reference: Reference; Shape: Shape; Size: Size; SustainabilityPerformance: SustainabilityPerformance; WarrantyDescription: WarrantyDescription; WarrantyDurationLabor: WarrantyDurationLabor; WarrantyDurationParts: WarrantyDurationParts; WarrantyGuarantorLabor: WarrantyGuarantorLabor; WarrantyGuarantorParts: WarrantyGuarantorParts; ExpectedLife: ExpectedLife; ReplacementCost: ReplacementCost; AssetAccountingType: FIXED; ModelLabel: ModelLabel

# IfcDoor: 1730 x 2134mm, M_Double-Flush:1730 x 2134mm:1730 x 2134mm:367888
In: First Floor
Type - OperationType: DOUBLE_DOOR_SINGLE_SWING; ParameterTakesPrecedence: no; Sizeable: no
OverallHeight: 2.134 m; OverallWidth: 1.73 m
PSet_Revit_Type_Materials and Finishes - Door Material: Door - Panel; Frame Material: Door - Frame
PSet_Revit_Type_Dimensions - Thickness: 0.051 m; Height: 2.134 m; Trim Projection Ext: 0.025 m; Trim Projection Int: 0.025 m; Trim Width: 0.076 m; Width: 1.73 m
PSet_Revit_Type_Other - AccessibilityPerformance: AccessibilityPerformance; CodePerformance: CodePerformance; IsFireExit: IsFireExit; GlazingAreaFraction: GlazingAreaFraction; OperationType: OperationType; Area: Area; Color: Color; Constituents: Constituents; Features: Features; Finish: Finish; Grade: Grade; Material: Material; ModelReference: ModelReference; NominalHeight: NominalHeight; NominalLength: NominalLength; NominalWidth: NominalWidth; ProductionYear: ProductionYear; Reference: Reference; Shape: Shape; Size: Size; SustainabilityPerformance: SustainabilityPerformance; WarrantyDescription: WarrantyDescription; WarrantyDurationLabor: WarrantyDurationLabor; WarrantyDurationParts: WarrantyDurationParts; WarrantyGuarantorLabor: WarrantyGuarantorLabor; WarrantyGuarantorParts: WarrantyGuarantorParts; ExpectedLife: ExpectedLife; ReplacementCost: ReplacementCost; AssetAccountingType: FIXED; ModelLabel: ModelLabel
PSet_Revit_Type_Construction - Function: 0; Wall Closure: 0; Construction Type: Construction Type
Pset_DoorCommon - Reference: M_Double-Flush:1730 x 2134mm; IsExternal: no; FireRating: Fire Rating
PSet_Revit_Type_Identity Data - Manufacturer: Manufacturer; Type Mark: 40; Fire Rating: Fire Rating; OmniClass Number: 23.30.10.00; OmniClass Title: Doors
PSet_Revit_Phasing - Phase Created: New Construction
PSet_Revit_Other - Head Height: 2.134 m; InstallationDate: InstallationDate; SerialNumber: SerialNumber; WarrantyStartDate: WarrantyStartDate; BarCode: BarCode; AssetIdentifier: AssetIdentifier; TagNumber: 1C11
PSet_Revit_Identity Data - Mark: 1C11
PSet_Revit_Constraints - Level: First Floor; Sill Height: 0 m

# IfcDoor: 1830 x 2134mm, M_Double-Flush:1830 x 2134mm:1830 x 2134mm:250360
In: Second Floor
Type - OperationType: DOUBLE_DOOR_SINGLE_SWING; ParameterTakesPrecedence: no; Sizeable: no
OverallHeight: 2.134 m; OverallWidth: 1.83 m
PSet_Revit_Phasing - Phase Created: New Construction
PSet_Revit_Type_Identity Data - Manufacturer: Manufacturer; Type Mark: 42; Fire Rating: Fire Rating; OmniClass Number: 23.30.10.00; OmniClass Title: Doors
Pset_DoorCommon - Reference: M_Double-Flush:1830 x 2134mm; IsExternal: no; FireRating: Fire Rating
PSet_Revit_Type_Other - AccessibilityPerformance: AccessibilityPerformance; CodePerformance: CodePerformance; IsFireExit: IsFireExit; GlazingAreaFraction: GlazingAreaFraction; OperationType: OperationType; Area: Area; Color: Color; Constituents: Constituents; Features: Features; Finish: Finish; Grade: Grade; Material: Material; ModelReference: ModelReference; NominalHeight: NominalHeight; NominalLength: NominalLength; NominalWidth: NominalWidth; ProductionYear: ProductionYear; Reference: Reference; Shape: Shape; Size: Size; SustainabilityPerformance: SustainabilityPerformance; WarrantyDescription: WarrantyDescription; WarrantyDurationLabor: WarrantyDurationLabor; WarrantyDurationParts: WarrantyDurationParts; WarrantyGuarantorLabor: WarrantyGuarantorLabor; WarrantyGuarantorParts: WarrantyGuarantorParts; ExpectedLife: ExpectedLife; ReplacementCost: ReplacementCost; AssetAccountingType: FIXED; ModelLabel: ModelLabel
PSet_Revit_Type_Construction - Function: 0; Wall Closure: 0; Construction Type: Construction Type
PSet_Revit_Identity Data - Mark: 2D05
PSet_Revit_Type_Dimensions - Thickness: 0.051 m; Height: 2.134 m; Trim Projection Ext: 0.025 m; Trim Projection Int: 0.025 m; Trim Width: 0.076 m; Width: 1.83 m
PSet_Revit_Type_Materials and Finishes - Door Material: Door - Panel; Frame Material: Door - Frame
PSet_Revit_Constraints - Level: Second Floor; Sill Height: 0 m
PSet_Revit_Other - Head Height: 2.134 m; InstallationDate: InstallationDate; SerialNumber: SerialNumber; WarrantyStartDate: WarrantyStartDate; BarCode: BarCode; AssetIdentifier: AssetIdentifier; TagNumber: 2D05

# IfcDoor: 1830 x 2134mm Exterior (4)
Type - OperationType: DOUBLE_DOOR_SINGLE_SWING; ParameterTakesPrecedence: no; Sizeable: no
OverallHeight: 2.134 m; OverallWidth: 1.83 m
PSet_Revit_Phasing - Phase Created: New Construction
PSet_Revit_Constraints - Sill Height: 0 m
Pset_DoorCommon - Reference: M_Double-Flush:1830 x 2134mm Exterior; IsExternal: yes; FireRating: Fire Rating
PSet_Revit_Other - Head Height: 2.134 m; InstallationDate: InstallationDate; SerialNumber: SerialNumber; WarrantyStartDate: WarrantyStartDate; BarCode: BarCode; AssetIdentifier: AssetIdentifier
PSet_Revit_Type_Materials and Finishes - Door Material: Door - Panel; Frame Material: Door - Frame
PSet_Revit_Type_Dimensions - Thickness: 0.051 m; Height: 2.134 m; Trim Projection Ext: 0.025 m; Trim Projection Int: 0.025 m; Trim Width: 0.076 m; Width: 1.83 m
PSet_Revit_Type_Identity Data - Manufacturer: Manufacturer; Type Mark: 58; Fire Rating: Fire Rating; OmniClass Number: 23.30.10.00; OmniClass Title: Doors
PSet_Revit_Type_Construction - Function: 1; Wall Closure: 0; Construction Type: Construction Type
PSet_Revit_Type_Other - AccessibilityPerformance: AccessibilityPerformance; CodePerformance: CodePerformance; IsFireExit: IsFireExit; GlazingAreaFraction: GlazingAreaFraction; OperationType: OperationType; Area: Area; Color: Color; Constituents: Constituents; Features: Features; Finish: Finish; Grade: Grade; Material: Material; ModelReference: ModelReference; NominalHeight: NominalHeight; NominalLength: NominalLength; NominalWidth: NominalWidth; ProductionYear: ProductionYear; Reference: Reference; Shape: Shape; Size: Size; SustainabilityPerformance: SustainabilityPerformance; WarrantyDescription: WarrantyDescription; WarrantyDurationLabor: WarrantyDurationLabor; WarrantyDurationParts: WarrantyDurationParts; WarrantyGuarantorLabor: WarrantyGuarantorLabor; WarrantyGuarantorParts: WarrantyGuarantorParts; ExpectedLife: ExpectedLife; ReplacementCost: ReplacementCost; AssetAccountingType: FIXED; ModelLabel: ModelLabel
Name (M_Double-Flush:1830 x 2134mm Exterior:1830 x 2134mm Exterior:...) | In | Level | TagNumber = Mark
252860 | First Floor | First Floor | 1E24
411107 | Second Floor | Second Floor | 2D05A
252102 | First Floor | First Floor | 1E15A
252224 | First Floor | First Floor | 1E15

# IfcDoor: M_Curtain Wall Dbl Chain Link (4)
Type - ParameterTakesPrecedence: no; Sizeable: no
OverallHeight: 1.96386 m; OverallWidth: 2.702 m
PSet_Revit_Dimensions - Width: 2.702 m; Height: 1.962 m
PSet_Revit_Other - InstallationDate: InstallationDate; SerialNumber: SerialNumber; WarrantyStartDate: WarrantyStartDate; BarCode: BarCode; AssetIdentifier: AssetIdentifier
Pset_DoorCommon - Reference: M_Curtain Wall Dbl Chain Link:M_Curtain Wall Dbl Chain Link; IsExternal: yes; FireRating: Fire Rating
PSet_Revit_Phasing - Phase Created: New Construction
PSet_Revit_Type_Construction - Function: 1; Construction Type: Construction Type
PSet_Revit_Type_Dimensions - Pipe Radius: 0.019 m
PSet_Revit_Type_Materials and Finishes - Glazing Material: Metal - Chain Link; Frame Material: Metal - Aluminum
PSet_Revit_Type_Other - AccessibilityPerformance: AccessibilityPerformance; CodePerformance: CodePerformance; IsFireExit: IsFireExit; GlazingAreaFraction: GlazingAreaFraction; OperationType: OperationType; Area: Area; Color: Color; Constituents: Constituents; Features: Features; Finish: Finish; Grade: Grade; Material: Material; ModelReference: ModelReference; NominalHeight: NominalHeight; NominalLength: NominalLength; NominalWidth: NominalWidth; ProductionYear: ProductionYear; Reference: Reference; Shape: Shape; Size: Size; SustainabilityPerformance: SustainabilityPerformance; WarrantyDescription: WarrantyDescription; WarrantyDurationLabor: WarrantyDurationLabor; WarrantyDurationParts: WarrantyDurationParts; WarrantyGuarantorLabor: WarrantyGuarantorLabor; WarrantyGuarantorParts: WarrantyGuarantorParts; ExpectedLife: ExpectedLife; ReplacementCost: ReplacementCost; AssetAccountingType: FIXED; ModelLabel: ModelLabel
PSet_Revit_Type_Identity Data - Manufacturer: Manufacturer; Type Mark: 35; Fire Rating: Fire Rating; OmniClass Number: 23.30.10.00; OmniClass Title: Doors
Name (M_Curtain Wall Dbl Chain Link:M_Curtain Wall Dbl Chain Link:M_Curtain Wall Dbl Chain Link:...) | In | TagNumber = Mark
346973 | TOF Footing | 1F01b
346969 | TOF Footing | 1F01a
346973 | First Floor | 1F01b
346969 | First Floor | 1F01a

# IfcDoor: M_Curtain Wall Dbl Glass (2)
In: First Floor
Type - OperationType: DOUBLE_DOOR_SINGLE_SWING; ParameterTakesPrecedence: no; Sizeable: no
OverallHeight: 2.32686 m; OverallWidth: 1.8 m
PSet_Revit_Phasing - Phase Created: New Construction
PSet_Revit_Dimensions - Width: 1.8 m; Height: 2.325 m
PSet_Revit_Identity Data - Mark: 1CA1
Pset_DoorCommon - Reference: M_Curtain Wall Dbl Glass:M_Curtain Wall Dbl Glass; IsExternal: yes; FireRating: Fire Rating
PSet_Revit_Other - InstallationDate: InstallationDate; SerialNumber: SerialNumber; WarrantyStartDate: WarrantyStartDate; BarCode: BarCode; AssetIdentifier: AssetIdentifier; TagNumber: 1CA1
PSet_Revit_Type_Materials and Finishes - Glazing Material: Glass
PSet_Revit_Type_Construction - Function: 1; Construction Type: Construction Type
PSet_Revit_Type_Dimensions - Offset: 0.05 m
PSet_Revit_Type_Identity Data - Manufacturer: Manufacturer; Type Mark: 36; Fire Rating: Fire Rating; OmniClass Number: 23.30.10.00; OmniClass Title: Doors
PSet_Revit_Type_Other - AccessibilityPerformance: AccessibilityPerformance; CodePerformance: CodePerformance; IsFireExit: IsFireExit; GlazingAreaFraction: GlazingAreaFraction; OperationType: OperationType; Area: Area; Color: Color; Constituents: Constituents; Features: Features; Finish: Finish; Grade: Grade; Material: Material; ModelReference: ModelReference; NominalHeight: NominalHeight; NominalLength: NominalLength; NominalWidth: NominalWidth; ProductionYear: ProductionYear; Reference: Reference; Shape: Shape; Size: Size; SustainabilityPerformance: SustainabilityPerformance; WarrantyDescription: WarrantyDescription; WarrantyDurationLabor: WarrantyDurationLabor; WarrantyDurationParts: WarrantyDurationParts; WarrantyGuarantorLabor: WarrantyGuarantorLabor; WarrantyGuarantorParts: WarrantyGuarantorParts; ExpectedLife: ExpectedLife; ReplacementCost: ReplacementCost; AssetAccountingType: FIXED; ModelLabel: ModelLabel

# IfcDoor: M_Curtain Wall Sgl Glass (2)
In: First Floor
Type - OperationType: SINGLE_SWING_LEFT; ParameterTakesPrecedence: no; Sizeable: no
OverallHeight: 2.325 m; OverallWidth: 0.901001 m
PSet_Revit_Dimensions - Width: 0.901001 m; Height: 2.325 m
Pset_DoorCommon - Reference: M_Curtain Wall Sgl Glass:M_Curtain Wall Sgl Glass; IsExternal: no; FireRating: Fire Rating
PSet_Revit_Other - InstallationDate: InstallationDate; SerialNumber: SerialNumber; WarrantyStartDate: WarrantyStartDate; BarCode: BarCode; AssetIdentifier: AssetIdentifier; TagNumber: 1DC5a
PSet_Revit_Phasing - Phase Created: New Construction
PSet_Revit_Identity Data - Mark: 1DC5a
PSet_Revit_Type_Materials and Finishes - Glazing Material: Glass
PSet_Revit_Type_Identity Data - Manufacturer: Manufacturer; Type Mark: 37; Fire Rating: Fire Rating; OmniClass Number: 23.30.10.00; OmniClass Title: Doors
PSet_Revit_Type_Dimensions - Offset: 0.051 m
PSet_Revit_Type_Other - AccessibilityPerformance: AccessibilityPerformance; CodePerformance: CodePerformance; IsFireExit: IsFireExit; GlazingAreaFraction: GlazingAreaFraction; OperationType: OperationType; Area: Area; Color: Color; Constituents: Constituents; Features: Features; Finish: Finish; Grade: Grade; Material: Material; ModelReference: ModelReference; NominalHeight: NominalHeight; NominalLength: NominalLength; NominalWidth: NominalWidth; ProductionYear: ProductionYear; Reference: Reference; Shape: Shape; Size: Size; SustainabilityPerformance: SustainabilityPerformance; WarrantyDescription: WarrantyDescription; WarrantyDurationLabor: WarrantyDurationLabor; WarrantyDurationParts: WarrantyDurationParts; WarrantyGuarantorLabor: WarrantyGuarantorLabor; WarrantyGuarantorParts: WarrantyGuarantorParts; ExpectedLife: ExpectedLife; ReplacementCost: ReplacementCost; AssetAccountingType: FIXED; ModelLabel: ModelLabel
PSet_Revit_Type_Construction - Function: 0; Construction Type: Construction Type

# IfcDoor: M_Curtain Wall Sgl Glass (2)
In: First Floor
Type - OperationType: SINGLE_SWING_RIGHT; ParameterTakesPrecedence: no; Sizeable: no
OverallHeight: 2.325 m; OverallWidth: 0.899549 m
PSet_Revit_Dimensions - Width: 0.899549 m; Height: 2.325 m
PSet_Revit_Identity Data - Mark: 1DC5b
Pset_DoorCommon - Reference: M_Curtain Wall Sgl Glass:M_Curtain Wall Sgl Glass; IsExternal: no; FireRating: Fire Rating
PSet_Revit_Other - InstallationDate: InstallationDate; SerialNumber: SerialNumber; WarrantyStartDate: WarrantyStartDate; BarCode: BarCode; AssetIdentifier: AssetIdentifier; TagNumber: 1DC5b
PSet_Revit_Phasing - Phase Created: New Construction
PSet_Revit_Type_Materials and Finishes - Glazing Material: Glass
PSet_Revit_Type_Identity Data - Manufacturer: Manufacturer; Type Mark: 37; Fire Rating: Fire Rating; OmniClass Number: 23.30.10.00; OmniClass Title: Doors
PSet_Revit_Type_Dimensions - Offset: 0.051 m
PSet_Revit_Type_Other - AccessibilityPerformance: AccessibilityPerformance; CodePerformance: CodePerformance; IsFireExit: IsFireExit; GlazingAreaFraction: GlazingAreaFraction; OperationType: OperationType; Area: Area; Color: Color; Constituents: Constituents; Features: Features; Finish: Finish; Grade: Grade; Material: Material; ModelReference: ModelReference; NominalHeight: NominalHeight; NominalLength: NominalLength; NominalWidth: NominalWidth; ProductionYear: ProductionYear; Reference: Reference; Shape: Shape; Size: Size; SustainabilityPerformance: SustainabilityPerformance; WarrantyDescription: WarrantyDescription; WarrantyDurationLabor: WarrantyDurationLabor; WarrantyDurationParts: WarrantyDurationParts; WarrantyGuarantorLabor: WarrantyGuarantorLabor; WarrantyGuarantorParts: WarrantyGuarantorParts; ExpectedLife: ExpectedLife; ReplacementCost: ReplacementCost; AssetAccountingType: FIXED; ModelLabel: ModelLabel
PSet_Revit_Type_Construction - Function: 0; Construction Type: Construction Type

# IfcFlowTerminal: 17" Depth x 18 1/2" Width (3)
Type - ElementType: 17" Depth x 18 1/2" Width
PSet_Revit_Other - InstallationDate: InstallationDate; SerialNumber: SerialNumber; WarrantyStartDate: WarrantyStartDate; BarCode: BarCode; AssetIdentifier: AssetIdentifier; TagNumber: TagNumber
PSet_Revit_Constraints - Elevation: 0.915 m
PSet_Revit_Phasing - Phase Created: New Construction
PSet_Revit_Type_Identity Data - URL: www.inprocorp.com; Type Comments: 18 1/2 in.; Series: Folding Seat; Revit Family Created by: CADdetails, LTD.; Revisions Date: 07/14/2010; OmniClass Title: Shower/Bath Seats; OmniClass Number: 23.45.05.14.11.17; Model: DSGBFSTADA-WHT; MasterFormat Title: Bath Accessories; MasterFormat Number: 10 28 16; Manufacturer: InPro Corporation; Description: Folding Seat White 17in.; Assembly Code: E1020810; Architectural Design Manual: www.inprocorp.com/Products/Details.aspx?ProductId=460#info; Assembly Description: Medical Furniture & Equipment
PSet_Revit_Type_Green Building Properties - LEED: www.inprocorp.com/Products/Files.aspx?FileId=8357
PSet_Revit_Type_Other - AccessibilityPerformance: AccessibilityPerformance; CodePerformance: CodePerformance; Color: Color; Constituents: Constituents; Features: Features; Finish: Finish; Grade: Grade; Material: Material; ModelReference: ModelReference; NominalHeight: NominalHeight; NominalLength: NominalLength; NominalWidth: NominalWidth; ProductionYear: ProductionYear; Reference: Reference; Shape: Shape; Size: Size; SustainabilityPerformance: SustainabilityPerformance; WarrantyDescription: WarrantyDescription; WarrantyDurationLabor: WarrantyDurationLabor; WarrantyDurationParts: WarrantyDurationParts; WarrantyGuarantorLabor: WarrantyGuarantorLabor; WarrantyGuarantorParts: WarrantyGuarantorParts; ExpectedLife: ExpectedLife; ReplacementCost: ReplacementCost; AssetAccountingType: AssetAccountingType; ModelLabel: ModelLabel
PSet_Revit_Type_Dimensions - Width: 0.569913 m; Radius Seat: 0.01905 m; Radius Frame: 0.0166687 m; Height: 0.193675 m; Elevation: 0.955675 m; Diameter: 0.0333375 m; Depth: 0.430212 m
PSet_Revit_Type_Materials and Finishes - Special Color: no; White: yes; Triton Color Palette: www.inprocorp.com/Products/Files.aspx?FileId=3054; Ivory: no; Finish: PVC-InPro-White
Name (M_ADA shower Seat:17" Depth x 18 1/2" Width:17" Depth x 18 1/2" Width:...) | In | Level | Mark
443686 | 1D18 | First Floor | 79
443641 | 2C08 | Second Floor | 78
443560 | 2C07 | Second Floor | 77

# IfcFlowTerminal: 2000 lbs, M_Elevator-Hydraulic:2000 lbs:2000 lbs:306114
In: E1
Type - ElementType: 2000 lbs
PSet_Revit_Type_Identity Data - Manufacturer: Manufacturer; OmniClass Number: 23.50.05.11; OmniClass Title: Elevators
PSet_Revit_Type_Other - Cab Location: 3.6576 m; Width: 2.2352 m; Pit Depth: 1.2192 m; Door Opening: 0.9144 m; Depth: 1.7526 m; Cab Width: 1.8288 m; Cab Height: 2.286 m; Cab Depth: 1.524 m; AccessibilityPerformance: AccessibilityPerformance; CodePerformance: CodePerformance; Color: Color; Constituents: Constituents; Features: Features; Finish: Finish; Grade: Grade; Material: Material; ModelReference: ModelReference; NominalHeight: NominalHeight; NominalLength: NominalLength; NominalWidth: NominalWidth; ProductionYear: ProductionYear; Reference: Reference; Shape: Shape; Size: Size; SustainabilityPerformance: SustainabilityPerformance; WarrantyDescription: WarrantyDescription; WarrantyDurationLabor: WarrantyDurationLabor; WarrantyDurationParts: WarrantyDurationParts; WarrantyGuarantorLabor: WarrantyGuarantorLabor; WarrantyGuarantorParts: WarrantyGuarantorParts; ExpectedLife: ExpectedLife; ReplacementCost: ReplacementCost; AssetAccountingType: FIXED; ModelLabel: ModelLabel
PSet_Revit_Identity Data - Mark: 2
PSet_Revit_Constraints - Level: First Floor; Host: Level : First Floor; Offset: 0 m; Moves With Nearby Elements: no
PSet_Revit_Other - Height: 8.23 m; InstallationDate: InstallationDate; SerialNumber: SerialNumber; WarrantyStartDate: WarrantyStartDate; BarCode: BarCode; AssetIdentifier: AssetIdentifier; TagNumber: TagNumber
PSet_Revit_Phasing - Phase Created: New Construction

# IfcFlowTerminal: 305 x 215 x 813mm (10)
Type - ElementType: 305 x 215 x 813mm
PSet_Revit_Constraints - Elevation: 0.915 m
PSet_Revit_Phasing - Phase Created: New Construction
PSet_Revit_Other - InstallationDate: InstallationDate; SerialNumber: SerialNumber; WarrantyStartDate: WarrantyStartDate; BarCode: BarCode; AssetIdentifier: AssetIdentifier; TagNumber: TagNumber
PSet_Revit_Type_Dimensions - Depth: 0.215 m; Height: 0.813 m; Mounting Height: 0.915 m; Width: 0.305 m
PSet_Revit_Type_Other - AccessibilityPerformance: AccessibilityPerformance; CodePerformance: CodePerformance; Color: Color; Constituents: Constituents; Features: Features; Finish: Finish; Grade: Grade; Material: Material; ModelReference: ModelReference; NominalHeight: NominalHeight; NominalLength: NominalLength; NominalWidth: NominalWidth; ProductionYear: ProductionYear; Reference: Reference; Shape: Shape; Size: Size; SustainabilityPerformance: SustainabilityPerformance; WarrantyDescription: WarrantyDescription; WarrantyDurationLabor: WarrantyDurationLabor; WarrantyDurationParts: WarrantyDurationParts; WarrantyGuarantorLabor: WarrantyGuarantorLabor; WarrantyGuarantorParts: WarrantyGuarantorParts; ExpectedLife: ExpectedLife; ReplacementCost: ReplacementCost; AssetAccountingType: FIXED; ModelLabel: ModelLabel
PSet_Revit_Type_Materials and Finishes - Cabinet Material: Metal - Paint Finish - Indian Red, Matte; Glass Pane Material: Glass
PSet_Revit_Type_Identity Data - Manufacturer: Manufacturer; OmniClass Number: 23.65.70.17.11; OmniClass Title: Fire Fighting Terminal Components
Name (M_Fire Extinguisher Cabinet:305 x 215 x 813mm:305 x 215 x 813mm:...) | In | Level | Mark
350693 | 1BC2 | First Floor | 1
363794 | 1AC4 | First Floor | 7
350968 | 1AC1 | First Floor | 2
351256 | 1AC5 | First Floor | 5
387916 | 2DC1 | Second Floor | 8
351533 | 1B04 | First Floor | 6
351171 | 1AC3 | First Floor | 3
390697 | 2D05 | Second Floor | 9
427576 | 1CC1 | First Floor | 11
425968 | 2D18 | Second Floor | 10

# IfcFlowTerminal: 8370-001300 (22)
Type - ElementType: 8370-001300
PSet_Revit_Constraints - Elevation: 0.915 m
PSet_Revit_Other - InstallationDate: InstallationDate; SerialNumber: SerialNumber; WarrantyStartDate: WarrantyStartDate; BarCode: BarCode; AssetIdentifier: AssetIdentifier; TagNumber: TagNumber
PSet_Revit_Phasing - Phase Created: New Construction
PSet_Revit_Type_Green Building Properties - Percentage of Recycled Content: 51.61; Complies to NAFTA: Yes; Complies To Buy American Act: Yes
PSet_Revit_Type_Dimensions - Overall Length: 0.841375 m; Length: 0.762 m; Diameter: 0.03175 m
PSet_Revit_Type_Materials and Finishes - Material and Finish: Bradley Corp Stainless Steel - Satin
PSet_Revit_Type_Other - AccessibilityPerformance: AccessibilityPerformance; CodePerformance: CodePerformance; Color: Color; Constituents: Constituents; Features: Features; Finish: Finish; Grade: Grade; Material: Material; ModelReference: ModelReference; NominalHeight: NominalHeight; NominalLength: NominalLength; NominalWidth: NominalWidth; ProductionYear: ProductionYear; Reference: Reference; Shape: Shape; Size: Size; SustainabilityPerformance: SustainabilityPerformance; WarrantyDescription: WarrantyDescription; WarrantyDurationLabor: WarrantyDurationLabor; WarrantyDurationParts: WarrantyDurationParts; WarrantyGuarantorLabor: WarrantyGuarantorLabor; WarrantyGuarantorParts: WarrantyGuarantorParts; ExpectedLife: ExpectedLife; ReplacementCost: ReplacementCost; AssetAccountingType: AssetAccountingType; ModelLabel: ModelLabel
PSet_Revit_Type_Constraints - Instructions: This is a face mounted fixture.; Default Elevation: 0.8382 m
PSet_Revit_Type_Identity Data - Warranty Information: Complete unit, one (1) year; Version: 1.0; Technical Data: http://www.bradleycorp.com/products/techdata/8825.pdf; URL: www.bradleycorp.com; Type Comments: All grab bar configurations are specified using centerline to centerline dimensions.; OmniClass Number: 0; Model: 8370-001300; Material Note: FLANGES - 11 GA., TUBING - 18 GA.; Manufacturer: Bradley Corporation; Industry Standards: ANSI Standard A117.1, ADA, ABA, ADAAG, UFAS; Description: Grab Bars; Copyright: This Model Data is Property of Bradley Corporation; Assembly Code: C1030200; ADA Compliant: Yes; Assembly Description: Bath & Toilet Accessories; OmniClass Title: Bath Grab Bars
Name (M_Grab Bars:8370-001300:8370-001300:...) | In | Host | Schedule Level | Mark
432957 | 1B05 | Basic Wall : Interior - Furring (152 mm Stud) | First Floor | 35
433925 | 2B22 | Basic Wall : Interior - Furring (152 mm Stud) | Second Floor | 41
436616 | 2C24 | Basic Wall : Interior - Plumbing (152mm Stud) | Second Floor | 54
433960 | 2B5 | Basic Wall : Interior - Furring (152 mm Stud) | Second Floor | 42
430827 | 1D14 | Basic Wall : Interior - Furring (152 mm Stud) | First Floor | 23
434939 | 2D13 | Basic Wall : Interior - Furring (152 mm Stud) | Second Floor | 47
430358 | 1A12 | Basic Wall : Interior - Furring (152 mm Stud) | First Floor | 15
430800 | 1D18 | Basic Wall : Interior - Furring (152 mm Stud) | First Floor | 22
436634 | 2C23 | Basic Wall : Interior - Plumbing (152mm Stud) | Second Floor | 55
432784 | 1E10 | Basic Wall : Interior - Furring (152 mm Stud) | First Floor | 32
431907 | 1E12 | Basic Wall : Interior - Furring (152 mm Stud) | First Floor | 28
435555 | 2C07 | Basic Wall : Interior - Plumbing (152mm Stud) | Second Floor | 49
431006 | 1C12 | Basic Wall : Interior - Furring (152 mm Stud) | First Floor | 24
434154 | 2B6 | Basic Wall : Interior - Furring (152 mm Stud) | Second Floor | 43
430296 | 1A09 | Basic Wall : Interior - Furring (152 mm Stud) | First Floor | 13
432918 | 1B11 | Basic Wall : Interior - Furring (152 mm Stud) | First Floor | 34
433165 | 1B02 | Basic Wall : Interior - Plumbing (152mm Stud) | First Floor | 36
434977 | 2C08 | Basic Wall : Interior - Plumbing (152mm Stud) | Second Floor | 48
431863 | 1D26 | Basic Wall : Interior - Plumbing (152mm Stud) | First Floor | 27
430518 | 1D04 | Basic Wall : Interior - Plumbing (152mm Stud) | First Floor | 18
432803 | 1E09 | Basic Wall : Interior - Furring (152 mm Stud) | First Floor | 33
430429 | 1A13 | Basic Wall : Interior - Furring (152 mm Stud) | First Floor | 17

# IfcFlowTerminal: 8370-001420 (22)
Type - ElementType: 8370-001420
PSet_Revit_Constraints - Elevation: 0.915 m
PSet_Revit_Phasing - Phase Created: New Construction
PSet_Revit_Other - InstallationDate: InstallationDate; SerialNumber: SerialNumber; WarrantyStartDate: WarrantyStartDate; BarCode: BarCode; AssetIdentifier: AssetIdentifier; TagNumber: TagNumber
PSet_Revit_Type_Identity Data - Warranty Information: Complete unit, one (1) year; Version: 1.0; Technical Data: http://www.bradleycorp.com/products/techdata/8825.pdf; URL: www.bradleycorp.com; Type Comments: All grab bar configurations are specified using centerline to centerline dimensions.; OmniClass Number: 0; Model: 8370-001420; Material Note: FLANGES - 11 GA., TUBING - 18 GA.; Manufacturer: Bradley Corporation; Industry Standards: ANSI Standard A117.1, ADA, ABA, ADAAG, UFAS; Description: Grab Bars; Copyright: This Model Data is Property of Bradley Corporation; Assembly Code: C1030200; ADA Compliant: Yes; Assembly Description: Bath & Toilet Accessories; OmniClass Title: Bath Grab Bars
PSet_Revit_Type_Constraints - Instructions: This is a face mounted fixture.; Default Elevation: 0.8382 m
PSet_Revit_Type_Other - AccessibilityPerformance: AccessibilityPerformance; CodePerformance: CodePerformance; Color: Color; Constituents: Constituents; Features: Features; Finish: Finish; Grade: Grade; Material: Material; ModelReference: ModelReference; NominalHeight: NominalHeight; NominalLength: NominalLength; NominalWidth: NominalHeight; ProductionYear: ProductionYear; Reference: Reference; Shape: Shape; Size: Size; SustainabilityPerformance: SustainabilityPerformance; WarrantyDescription: WarrantyDescription; WarrantyDurationLabor: WarrantyDurationLabor; WarrantyDurationParts: WarrantyDurationParts; WarrantyGuarantorLabor: WarrantyGuarantorLabor; WarrantyGuarantorParts: WarrantyGuarantorParts; ExpectedLife: ExpectedLife; ReplacementCost: ReplacementCost; AssetAccountingType: AssetAccountingType; ModelLabel: ModelLabel
PSet_Revit_Type_Green Building Properties - Percentage of Recycled Content: 54.99; Complies to NAFTA: Yes; Complies To Buy American Act: Yes
PSet_Revit_Type_Materials and Finishes - Material and Finish: Bradley Corp Stainless Steel - Satin
PSet_Revit_Type_Dimensions - Overall Length: 1.14617 m; Length: 1.0668 m; Diameter: 0.03175 m
Name (M_Grab Bars:8370-001420:8370-001420:...) | In | Host | Mark | Schedule Level
432601 | 1E09 | Basic Wall : Interior - Partition (92mm Stud) | 31 | First Floor
433622 | 1B11 | Basic Wall : Interior - Partition (92mm Stud) | 39 | First Floor
435940 | 2C23 | Basic Wall : Interior - Partition (92mm Stud) | 52 | Second Floor
432255 | 1E10 | Basic Wall : Interior - Partition (92mm Stud) | 30 | First Floor
435755 | 2C08 | Basic Wall : Interior - Partition (92mm Stud) | 50 | Second Floor
435792 | 2C07 | Basic Wall : Interior - Partition (92mm Stud) | 51 | Second Floor
434392 | 2B5 | Basic Wall : Interior - Partition (92mm Stud) | 45 | Second Floor
430356 | 1A12 | Basic Wall : Interior - Toilet Partition (25mm) | 14 | First Floor
430186 | 1A09 | Basic Wall : Interior - Toilet Partition (25mm) | 12 | First Floor
432204 | 1E12 | Basic Wall : Interior - Partition (92mm Stud) | 29 | First Floor
434582 | 2D13 | Basic Wall : Interior - Partition (92mm Stud) | 46 | Second Floor
433844 | 2B22 | Basic Wall : Exterior - Insul Panel on Mtl. Stud | 40 | Second Floor
436370 | 2C24 | Basic Wall : Interior - Partition (92mm Stud) | 53 | Second Floor
431453 | 1C12 | Basic Wall : Interior - Partition (92mm Stud) | 25 | First Floor
430428 | 1A13 | Basic Wall : Interior - Partition (92mm Stud) | 16 | First Floor
431750 | 1D26 | Basic Wall : Interior - Partition (92mm Stud) | 26 | First Floor
430573 | 1D04 | Basic Wall : Interior - Furring (38 mm Stud) | 19 | First Floor
430635 | 1D14 | Basic Wall : Interior - Partition (92mm Stud) | 21 | First Floor
434363 | 2B6 | Basic Wall : Interior - Partition (92mm Stud) | 44 | Second Floor
433434 | 1B05 | Basic Wall : Interior - Partition (92mm Stud) | 38 | First Floor
433384 | 1B02 | Basic Wall : Interior - Partition (92mm Stud) | 37 | First Floor
430606 | 1D18 | Basic Wall : Interior - Partition (92mm Stud) | 20 | First Floor

# IfcFlowTerminal: Mirror 600mm x 900mm (22)
Type - ElementType: Mirror 600mm x 900mm
PSet_Revit_Phasing - Phase Created: New Construction
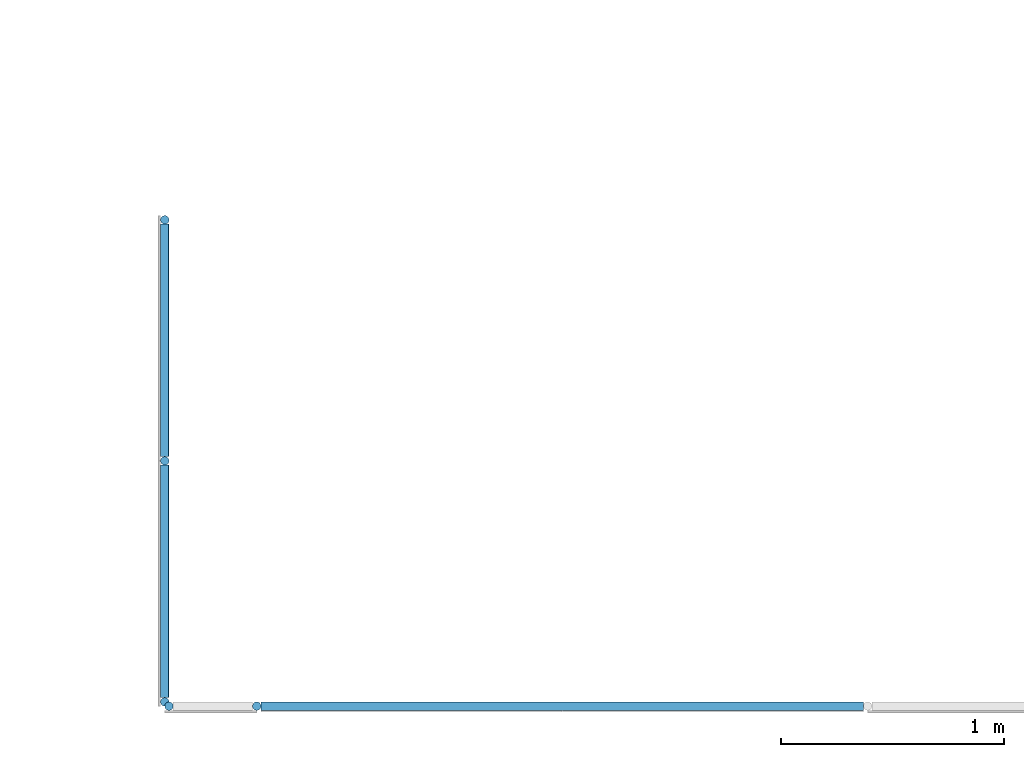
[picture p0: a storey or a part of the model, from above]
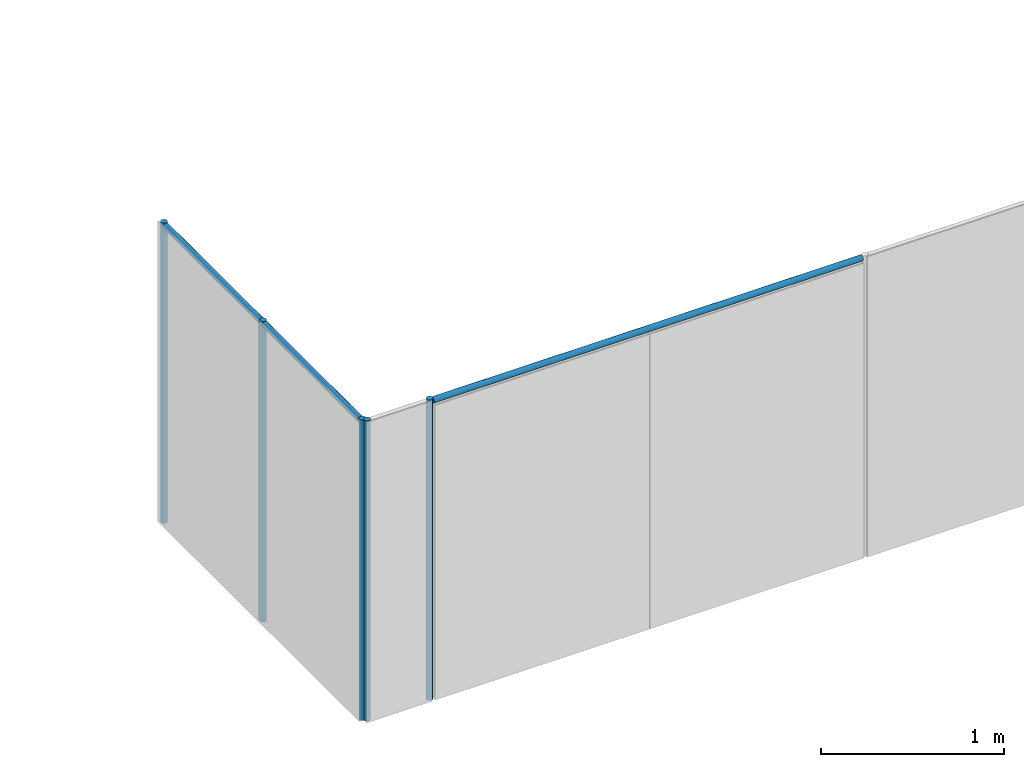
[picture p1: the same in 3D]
Properties of the parts of a building model (IFC2X3), part 5 of 11

# IfcMember: 50 x 150mm (506)
Name (Rectangular Mullion:50 x 150mm:50 x 150mm:...) | In | Length (m)
298309 | Roof - Main | 1.51
284097 | First Floor | 1.00167
303261 | Roof - Main | 1.245
381923 | Roof - Main | 0.986894
283432 | First Floor | 0.4
299075 | Roof - Main | 1.3516
283896 | First Floor | 0.419999
375164 | Roof - Main | 1.22
301709 | Roof - Main | 1.2444
314111 | Second Floor | 1.64443
301711 | Roof - Main | 1.37115
284109 | First Floor | 1.00167
298310 | Roof - Main | 1.53359
307738 | Roof - Main | 1.2694
285051 | First Floor | 0.926001
379219 | Second Floor | 1.32388
309276 | Roof - Main | 1.28626
285054 | First Floor | 2.425
283079 | First Floor | 0.4
283434 | First Floor | 2.4
286015 | Second Floor | 1.14769
283667 | First Floor | 1.00167
307732 | Roof - Main | 0.757291
283778 | First Floor | 0.4
374707 | Roof - Main | 0.813106
284105 | First Floor | 0.4
283669 | First Floor | 1.00167
286008 | Second Floor | 1.14769
298307 | Roof - Main | 1.6143
381969 | Roof - Main | 0.813106
286009 | Second Floor | 1.14769
374708 | Roof - Main | 0.813106
283433 | First Floor | 0.4
381927 | Roof - Main | 0.986894
307730 | Roof - Main | 0.410079
308983 | Roof - Main | 0.109513
303296 | Roof - Main | 0.986894
303285 | Roof - Main | 1.245
299073 | Roof - Main | 1.42948
374710 | Roof - Main | 0.813106
286011 | Second Floor | 1.17269
283892 | First Floor | 2.4
303286 | Roof - Main | 1.245
284579 | First Floor | 0.692
286014 | Second Floor | 1.17269
284583 | First Floor | 1
314115 | Second Floor | 1.24
286016 | Second Floor | 2.4
283081 | First Floor | 2.4
283893 | First Floor | 0.4
283779 | First Floor | 2.4
303269 | Roof - Main | 1.22
283890 | First Floor | 0.924549
303295 | Roof - Main | 0.986894
283894 | First Floor | 0.4
303297 | Roof - Main | 0.986894
283674 | First Floor | 1.00167
284581 | First Floor | 0.692
283670 | First Floor | 2.4
283891 | First Floor | 0.419999
286013 | Second Floor | 1.17269
307737 | Roof - Main | 1.2694
283435 | First Floor | 0.815
303287 | Roof - Main | 1.22
284098 | First Floor | 1.00167
283671 | First Floor | 0.4
307735 | Roof - Main | 1.19324
283668 | First Floor | 1.02667
285053 | First Floor | 0.418999
283895 | First Floor | 2.4
283679 | First Floor | 0.4
314116 | Second Floor | 1.215
283672 | First Floor | 0.4
303270 | Roof - Main | 1.245
283678 | First Floor | 2.4
283673 | First Floor | 2.4
307736 | Roof - Main | 1.2694
283677 | First Floor | 2.4
283680 | First Floor | 0.4
283676 | First Floor | 1.00167
283675 | First Floor | 1.02667

# IfcOpeningElement: Opening (403)
Name | In
6 x  | Roof - Main | PSet_Revit_Dimensions - Length: 18.4025 m; Area: 31.9269 m2; Volume: 8.52447 m3; PSet_Revit_Phasing - Phase Created: New Construction; PSet_Revit_Other - InstallationDate: InstallationDate; SerialNumber: SerialNumber; WarrantyStartDate: WarrantyStartDate; BarCode: BarCode; AssetIdentifier: AssetIdentifier; TagNumber: TagNumber; PSet_Revit_Constraints - Location Line: 2; Base Constraint: Roof - Main; Base Offset: 0 m; Base is Attached: no; Base Extension Distance: 0 m; Top Constraint: Up to level: Roof - Main; Unconnected Height: 3.4 m; Top Offset: 3.4 m; Top is Attached: no; Top Extension Distance: 0 m; Room Bounding: yes; Related to Mass: no; Pset_WallCommon - Reference: Basic Wall:Exterior - Insul Panel on Mtl. Stud; LoadBearing: no; ExtendToStructure: no; IsExternal: yes; PSet_Revit_Structural - Structural Usage: 0; PSet_Revit_Type_Other - AccessibilityPerformance: AccessibilityPerformance; CodePerformance: CodePerformance; Color: Color; Constituents: Constituents; Features: Features; Finish: Finish; Grade: Grade; Material: Material; ModelReference: ModelReference; NominalHeight: NominalHeight; NominalLength: NominalLength; NominalWidth: NominalWidth; ProductionYear: ProductionYear; Reference: Reference; Shape: Shape; Size: Size; SustainabilityPerformance: SustainabilityPerformance; WarrantyDescription: WarrantyDescription; WarrantyDurationLabor: WarrantyDurationLabor; WarrantyDurationParts: WarrantyDurationParts; WarrantyGuarantorLabor: WarrantyGuarantorLabor; WarrantyGuarantorParts: WarrantyGuarantorParts; ExpectedLife: ExpectedLife; ReplacementCost: ReplacementCost; AssetAccountingType: FIXED; Classification Code: 23-25 30 24 21; Classification Description: Metal Framed Structural Walls; ModelLabel: ModelLabel; PSet_Revit_Type_Construction - Wrapping at Inserts: 0; Wrapping at Ends: 1; Width: 0.267 m; Function: 1; PSet_Revit_Type_Graphics - Coarse Scale Fill Color: 0; PSet_Revit_Type_Identity Data - Manufacturer: Manufacturer
 | First Floor | PSet_Revit_Dimensions - Length: 13.338 m; Area: 56.4301 m2; Volume: 15.0307 m3; PSet_Revit_Phasing - Phase Created: New Construction; PSet_Revit_Other - InstallationDate: InstallationDate; SerialNumber: SerialNumber; WarrantyStartDate: WarrantyStartDate; BarCode: BarCode; AssetIdentifier: AssetIdentifier; TagNumber: TagNumber; PSet_Revit_Constraints - Location Line: 2; Base Constraint: First Floor; Base Offset: 0 m; Base is Attached: no; Base Extension Distance: 0 m; Top Constraint: Up to level: Second Floor; Unconnected Height: 4.57 m; Top Offset: 0 m; Top is Attached: no; Top Extension Distance: 0 m; Room Bounding: yes; Related to Mass: no; Pset_WallCommon - Reference: Basic Wall:Exterior - Insul Panel on Mtl. Stud; LoadBearing: no; ExtendToStructure: no; IsExternal: yes; PSet_Revit_Structural - Structural Usage: 0; PSet_Revit_Type_Other - AccessibilityPerformance: AccessibilityPerformance; CodePerformance: CodePerformance; Color: Color; Constituents: Constituents; Features: Features; Finish: Finish; Grade: Grade; Material: Material; ModelReference: ModelReference; NominalHeight: NominalHeight; NominalLength: NominalLength; NominalWidth: NominalWidth; ProductionYear: ProductionYear; Reference: Reference; Shape: Shape; Size: Size; SustainabilityPerformance: SustainabilityPerformance; WarrantyDescription: WarrantyDescription; WarrantyDurationLabor: WarrantyDurationLabor; WarrantyDurationParts: WarrantyDurationParts; WarrantyGuarantorLabor: WarrantyGuarantorLabor; WarrantyGuarantorParts: WarrantyGuarantorParts; ExpectedLife: ExpectedLife; ReplacementCost: ReplacementCost; AssetAccountingType: FIXED; Classification Code: 23-25 30 24 21; Classification Description: Metal Framed Structural Walls; ModelLabel: ModelLabel; PSet_Revit_Type_Construction - Wrapping at Inserts: 0; Wrapping at Ends: 1; Width: 0.267 m; Function: 1; PSet_Revit_Type_Graphics - Coarse Scale Fill Color: 0; PSet_Revit_Type_Identity Data - Manufacturer: Manufacturer
Basic Wall:Exterior - Insul Panel on Mtl. Stud:309999:2 | Roof - Main | PSet_Revit_Dimensions - Length: 18.4025 m; Area: 31.9269 m2; Volume: 8.52447 m3; PSet_Revit_Phasing - Phase Created: New Construction; PSet_Revit_Other - InstallationDate: InstallationDate; SerialNumber: SerialNumber; WarrantyStartDate: WarrantyStartDate; BarCode: BarCode; AssetIdentifier: AssetIdentifier; TagNumber: TagNumber; PSet_Revit_Constraints - Location Line: 2; Base Constraint: Roof - Main; Base Offset: 0 m; Base is Attached: no; Base Extension Distance: 0 m; Top Constraint: Up to level: Roof - Main; Unconnected Height: 3.4 m; Top Offset: 3.4 m; Top is Attached: no; Top Extension Distance: 0 m; Room Bounding: yes; Related to Mass: no; Pset_WallCommon - Reference: Basic Wall:Exterior - Insul Panel on Mtl. Stud; LoadBearing: no; ExtendToStructure: no; IsExternal: yes; PSet_Revit_Structural - Structural Usage: 0; PSet_Revit_Type_Other - AccessibilityPerformance: AccessibilityPerformance; CodePerformance: CodePerformance; Color: Color; Constituents: Constituents; Features: Features; Finish: Finish; Grade: Grade; Material: Material; ModelReference: ModelReference; NominalHeight: NominalHeight; NominalLength: NominalLength; NominalWidth: NominalWidth; ProductionYear: ProductionYear; Reference: Reference; Shape: Shape; Size: Size; SustainabilityPerformance: SustainabilityPerformance; WarrantyDescription: WarrantyDescription; WarrantyDurationLabor: WarrantyDurationLabor; WarrantyDurationParts: WarrantyDurationParts; WarrantyGuarantorLabor: WarrantyGuarantorLabor; WarrantyGuarantorParts: WarrantyGuarantorParts; ExpectedLife: ExpectedLife; ReplacementCost: ReplacementCost; AssetAccountingType: FIXED; Classification Code: 23-25 30 24 21; Classification Description: Metal Framed Structural Walls; ModelLabel: ModelLabel; PSet_Revit_Type_Construction - Wrapping at Inserts: 0; Wrapping at Ends: 1; Width: 0.267 m; Function: 1; PSet_Revit_Type_Graphics - Coarse Scale Fill Color: 0; PSet_Revit_Type_Identity Data - Manufacturer: Manufacturer
Basic Wall:Exterior - Insul Panel on Mtl. Stud:141152:2 | First Floor | PSet_Revit_Dimensions - Length: 32.333 m; Area: 153.657 m2; Volume: 41.0265 m3; PSet_Revit_Phasing - Phase Created: New Construction; PSet_Revit_Other - InstallationDate: InstallationDate; SerialNumber: SerialNumber; WarrantyStartDate: WarrantyStartDate; BarCode: BarCode; AssetIdentifier: AssetIdentifier; TagNumber: TagNumber; PSet_Revit_Constraints - Location Line: 2; Base Constraint: First Floor; Base Offset: 0 m; Base is Attached: no; Base Extension Distance: 0 m; Top Constraint: Up to level: Second Floor; Unconnected Height: 5.027 m; Top Offset: 0.457 m; Top is Attached: no; Top Extension Distance: 0 m; Room Bounding: yes; Related to Mass: no; Pset_WallCommon - Reference: Basic Wall:Exterior - Insul Panel on Mtl. Stud; LoadBearing: no; ExtendToStructure: no; IsExternal: yes; PSet_Revit_Structural - Structural Usage: 0; PSet_Revit_Type_Other - AccessibilityPerformance: AccessibilityPerformance; CodePerformance: CodePerformance; Color: Color; Constituents: Constituents; Features: Features; Finish: Finish; Grade: Grade; Material: Material; ModelReference: ModelReference; NominalHeight: NominalHeight; NominalLength: NominalLength; NominalWidth: NominalWidth; ProductionYear: ProductionYear; Reference: Reference; Shape: Shape; Size: Size; SustainabilityPerformance: SustainabilityPerformance; WarrantyDescription: WarrantyDescription; WarrantyDurationLabor: WarrantyDurationLabor; WarrantyDurationParts: WarrantyDurationParts; WarrantyGuarantorLabor: WarrantyGuarantorLabor; WarrantyGuarantorParts: WarrantyGuarantorParts; ExpectedLife: ExpectedLife; ReplacementCost: ReplacementCost; AssetAccountingType: FIXED; Classification Code: 23-25 30 24 21; Classification Description: Metal Framed Structural Walls; ModelLabel: ModelLabel; PSet_Revit_Type_Construction - Wrapping at Inserts: 0; Wrapping at Ends: 1; Width: 0.267 m; Function: 1; PSet_Revit_Type_Graphics - Coarse Scale Fill Color: 0; PSet_Revit_Type_Identity Data - Manufacturer: Manufacturer
 | First Floor | PSet_Revit_Dimensions - Length: 2.924 m; Area: 10.5578 m2; Volume: 1.27303 m3; PSet_Revit_Phasing - Phase Created: New Construction; PSet_Revit_Other - InstallationDate: InstallationDate; SerialNumber: SerialNumber; WarrantyStartDate: WarrantyStartDate; BarCode: BarCode; AssetIdentifier: AssetIdentifier; TagNumber: TagNumber; PSet_Revit_Constraints - Location Line: 2; Base Constraint: First Floor; Base Offset: 0 m; Base is Attached: no; Base Extension Distance: 0 m; Top Constraint: Up to level: Second Floor; Unconnected Height: 4.468 m; Top Offset: -0.102 m; Top is Attached: no; Top Extension Distance: 0 m; Room Bounding: yes; Related to Mass: no; Pset_WallCommon - Reference: Basic Wall:Interior - Partition (92mm Stud); LoadBearing: no; ExtendToStructure: no; IsExternal: no; PSet_Revit_Structural - Structural Usage: 0; PSet_Revit_Type_Other - AccessibilityPerformance: AccessibilityPerformance; CodePerformance: CodePerformance; Color: Color; Constituents: Constituents; Features: Features; Finish: Finish; Grade: Grade; Material: Material; ModelReference: ModelReference; NominalHeight: NominalHeight; NominalLength: NominalLength; NominalWidth: NominalWidth; ProductionYear: ProductionYear; Reference: Reference; Shape: Shape; Size: Size; SustainabilityPerformance: SustainabilityPerformance; WarrantyDescription: WarrantyDescription; WarrantyDurationLabor: WarrantyDurationLabor; WarrantyDurationParts: WarrantyDurationParts; WarrantyGuarantorLabor: WarrantyGuarantorLabor; WarrantyGuarantorParts: WarrantyGuarantorParts; ExpectedLife: ExpectedLife; ReplacementCost: ReplacementCost; AssetAccountingType: FIXED; Classification Code: 23-25 40 11 11 11; Classification Description: Metal-Framed Gypsum Board Fixed Partitions; ModelLabel: ModelLabel; PSet_Revit_Type_Construction - Wrapping at Inserts: 0; Wrapping at Ends: 2; Width: 0.124 m; Function: 0; PSet_Revit_Type_Graphics - Coarse Scale Fill Color: 0; PSet_Revit_Type_Identity Data - Manufacturer: Manufacturer
Basic Wall:Interior - Furring (38 mm Stud):392344:2 | Second Floor | PSet_Revit_Dimensions - Length: 1.47394 m; Area: 2.95641 m2; Volume: 0.159646 m3; PSet_Revit_Phasing - Phase Created: New Construction; PSet_Revit_Other - InstallationDate: InstallationDate; SerialNumber: SerialNumber; WarrantyStartDate: WarrantyStartDate; BarCode: BarCode; AssetIdentifier: AssetIdentifier; TagNumber: TagNumber; PSet_Revit_Constraints - Location Line: 3; Base Constraint: Second Floor; Base Offset: 0 m; Base is Attached: no; Base Extension Distance: 0 m; Top Constraint: Up to level: Second Floor; Unconnected Height: 2.8 m; Top Offset: 2.8 m; Top is Attached: no; Top Extension Distance: 0 m; Room Bounding: yes; Related to Mass: no; Pset_WallCommon - Reference: Basic Wall:Interior - Furring (38 mm Stud); LoadBearing: no; ExtendToStructure: no; IsExternal: no; PSet_Revit_Structural - Structural Usage: 0; PSet_Revit_Type_Other - AccessibilityPerformance: AccessibilityPerformance; CodePerformance: CodePerformance; Color: Color; Constituents: Constituents; Features: Features; Finish: Finish; Grade: Grade; Material: Material; ModelReference: ModelReference; NominalHeight: NominalHeight; NominalLength: NominalLength; NominalWidth: NominalWidth; ProductionYear: ProductionYear; Reference: Reference; Shape: Shape; Size: Size; SustainabilityPerformance: SustainabilityPerformance; WarrantyDescription: WarrantyDescription; WarrantyDurationLabor: WarrantyDurationLabor; WarrantyDurationParts: WarrantyDurationParts; WarrantyGuarantorLabor: WarrantyGuarantorLabor; WarrantyGuarantorParts: WarrantyGuarantorParts; ExpectedLife: ExpectedLife; ReplacementCost: ReplacementCost; AssetAccountingType: FIXED; Classification Code: 23-25 40 11 11 11; Classification Description: Metal-Framed Gypsum Board Fixed Partitions; ModelLabel: ModelLabel; PSet_Revit_Type_Construction - Wrapping at Inserts: 0; Wrapping at Ends: 0; Width: 0.054 m; Function: 0; PSet_Revit_Type_Graphics - Coarse Scale Fill Color: 0; PSet_Revit_Type_Identity Data - Manufacturer: Manufacturer
Basic Wall:Exterior - Insul Panel on Mtl. Stud:293670:2 | Second Floor | PSet_Revit_Dimensions - Length: 2.7445 m; Area: 7.41764 m2; Volume: 1.98051 m3; PSet_Revit_Phasing - Phase Created: New Construction; PSet_Revit_Other - InstallationDate: InstallationDate; SerialNumber: SerialNumber; WarrantyStartDate: WarrantyStartDate; BarCode: BarCode; AssetIdentifier: AssetIdentifier; TagNumber: TagNumber; PSet_Revit_Constraints - Location Line: 2; Base Constraint: Second Floor; Base Offset: 0 m; Base is Attached: no; Base Extension Distance: 0 m; Top Constraint: Up to level: Second Floor; Unconnected Height: 2.64 m; Top Offset: 2.64 m; Top is Attached: no; Top Extension Distance: 0 m; Room Bounding: yes; Related to Mass: no; Pset_WallCommon - Reference: Basic Wall:Exterior - Insul Panel on Mtl. Stud; LoadBearing: no; ExtendToStructure: no; IsExternal: yes; PSet_Revit_Structural - Structural Usage: 0; PSet_Revit_Type_Other - AccessibilityPerformance: AccessibilityPerformance; CodePerformance: CodePerformance; Color: Color; Constituents: Constituents; Features: Features; Finish: Finish; Grade: Grade; Material: Material; ModelReference: ModelReference; NominalHeight: NominalHeight; NominalLength: NominalLength; NominalWidth: NominalWidth; ProductionYear: ProductionYear; Reference: Reference; Shape: Shape; Size: Size; SustainabilityPerformance: SustainabilityPerformance; WarrantyDescription: WarrantyDescription; WarrantyDurationLabor: WarrantyDurationLabor; WarrantyDurationParts: WarrantyDurationParts; WarrantyGuarantorLabor: WarrantyGuarantorLabor; WarrantyGuarantorParts: WarrantyGuarantorParts; ExpectedLife: ExpectedLife; ReplacementCost: ReplacementCost; AssetAccountingType: FIXED; Classification Code: 23-25 30 24 21; Classification Description: Metal Framed Structural Walls; ModelLabel: ModelLabel; PSet_Revit_Type_Construction - Wrapping at Inserts: 0; Wrapping at Ends: 1; Width: 0.267 m; Function: 1; PSet_Revit_Type_Graphics - Coarse Scale Fill Color: 0; PSet_Revit_Type_Identity Data - Manufacturer: Manufacturer
 | Second Floor | PSet_Revit_Dimensions - Length: 3.98706 m; Area: 16.0163 m2; Volume: 1.94988 m3; PSet_Revit_Phasing - Phase Created: New Construction; PSet_Revit_Other - InstallationDate: InstallationDate; SerialNumber: SerialNumber; WarrantyStartDate: WarrantyStartDate; BarCode: BarCode; AssetIdentifier: AssetIdentifier; TagNumber: TagNumber; PSet_Revit_Constraints - Location Line: 2; Base Constraint: Second Floor; Base Offset: 0 m; Base is Attached: no; Base Extension Distance: 0 m; Top Constraint: Up to level: Roof - Main; Unconnected Height: 4.578 m; Top Offset: -0.102 m; Top is Attached: no; Top Extension Distance: 0 m; Room Bounding: yes; Related to Mass: no; Pset_WallCommon - Reference: Basic Wall:Interior - Partition (92mm Stud); LoadBearing: no; ExtendToStructure: no; IsExternal: no; PSet_Revit_Structural - Structural Usage: 0; PSet_Revit_Type_Other - AccessibilityPerformance: AccessibilityPerformance; CodePerformance: CodePerformance; Color: Color; Constituents: Constituents; Features: Features; Finish: Finish; Grade: Grade; Material: Material; ModelReference: ModelReference; NominalHeight: NominalHeight; NominalLength: NominalLength; NominalWidth: NominalWidth; ProductionYear: ProductionYear; Reference: Reference; Shape: Shape; Size: Size; SustainabilityPerformance: SustainabilityPerformance; WarrantyDescription: WarrantyDescription; WarrantyDurationLabor: WarrantyDurationLabor; WarrantyDurationParts: WarrantyDurationParts; WarrantyGuarantorLabor: WarrantyGuarantorLabor; WarrantyGuarantorParts: WarrantyGuarantorParts; ExpectedLife: ExpectedLife; ReplacementCost: ReplacementCost; AssetAccountingType: FIXED; Classification Code: 23-25 40 11 11 11; Classification Description: Metal-Framed Gypsum Board Fixed Partitions; ModelLabel: ModelLabel; PSet_Revit_Type_Construction - Wrapping at Inserts: 0; Wrapping at Ends: 2; Width: 0.124 m; Function: 0; PSet_Revit_Type_Graphics - Coarse Scale Fill Color: 0; PSet_Revit_Type_Identity Data - Manufacturer: Manufacturer
 | First Floor | PSet_Revit_Dimensions - Length: 18.766 m; Area: 71.7699 m2; Volume: 8.89946 m3; PSet_Revit_Phasing - Phase Created: New Construction; PSet_Revit_Other - InstallationDate: InstallationDate; SerialNumber: SerialNumber; WarrantyStartDate: WarrantyStartDate; BarCode: BarCode; AssetIdentifier: AssetIdentifier; TagNumber: TagNumber; PSet_Revit_Constraints - Location Line: 2; Base Constraint: First Floor; Base Offset: 0 m; Base is Attached: no; Base Extension Distance: 0 m; Top Constraint: Up to level: Second Floor; Unconnected Height: 4.468 m; Top Offset: -0.102 m; Top is Attached: no; Top Extension Distance: 0 m; Room Bounding: yes; Related to Mass: no; Pset_WallCommon - Reference: Basic Wall:Interior - Partition (92mm Stud); LoadBearing: no; ExtendToStructure: no; IsExternal: no; PSet_Revit_Structural - Structural Usage: 0; PSet_Revit_Type_Other - AccessibilityPerformance: AccessibilityPerformance; CodePerformance: CodePerformance; Color: Color; Constituents: Constituents; Features: Features; Finish: Finish; Grade: Grade; Material: Material; ModelReference: ModelReference; NominalHeight: NominalHeight; NominalLength: NominalLength; NominalWidth: NominalWidth; ProductionYear: ProductionYear; Reference: Reference; Shape: Shape; Size: Size; SustainabilityPerformance: SustainabilityPerformance; WarrantyDescription: WarrantyDescription; WarrantyDurationLabor: WarrantyDurationLabor; WarrantyDurationParts: WarrantyDurationParts; WarrantyGuarantorLabor: WarrantyGuarantorLabor; WarrantyGuarantorParts: WarrantyGuarantorParts; ExpectedLife: ExpectedLife; ReplacementCost: ReplacementCost; AssetAccountingType: FIXED; Classification Code: 23-25 40 11 11 11; Classification Description: Metal-Framed Gypsum Board Fixed Partitions; ModelLabel: ModelLabel; PSet_Revit_Type_Construction - Wrapping at Inserts: 0; Wrapping at Ends: 2; Width: 0.124 m; Function: 0; PSet_Revit_Type_Graphics - Coarse Scale Fill Color: 0; PSet_Revit_Type_Identity Data - Manufacturer: Manufacturer
 | Second Floor | PSet_Revit_Dimensions - Length: 1.834 m; Area: 6.43624 m2; Volume: 0.798094 m3; PSet_Revit_Phasing - Phase Created: New Construction; PSet_Revit_Other - InstallationDate: InstallationDate; SerialNumber: SerialNumber; WarrantyStartDate: WarrantyStartDate; BarCode: BarCode; AssetIdentifier: AssetIdentifier; TagNumber: TagNumber; PSet_Revit_Constraints - Location Line: 2; Base Constraint: Second Floor; Base Offset: 0 m; Base is Attached: no; Base Extension Distance: 0 m; Top Constraint: Up to level: Roof - Main; Unconnected Height: 4.578 m; Top Offset: -0.102 m; Top is Attached: no; Top Extension Distance: 0 m; Room Bounding: yes; Related to Mass: no; Pset_WallCommon - Reference: Basic Wall:Interior - Partition (92mm Stud); LoadBearing: no; ExtendToStructure: no; IsExternal: no; PSet_Revit_Structural - Structural Usage: 0; PSet_Revit_Type_Other - AccessibilityPerformance: AccessibilityPerformance; CodePerformance: CodePerformance; Color: Color; Constituents: Constituents; Features: Features; Finish: Finish; Grade: Grade; Material: Material; ModelReference: ModelReference; NominalHeight: NominalHeight; NominalLength: NominalLength; NominalWidth: NominalWidth; ProductionYear: ProductionYear; Reference: Reference; Shape: Shape; Size: Size; SustainabilityPerformance: SustainabilityPerformance; WarrantyDescription: WarrantyDescription; WarrantyDurationLabor: WarrantyDurationLabor; WarrantyDurationParts: WarrantyDurationParts; WarrantyGuarantorLabor: WarrantyGuarantorLabor; WarrantyGuarantorParts: WarrantyGuarantorParts; ExpectedLife: ExpectedLife; ReplacementCost: ReplacementCost; AssetAccountingType: FIXED; Classification Code: 23-25 40 11 11 11; Classification Description: Metal-Framed Gypsum Board Fixed Partitions; ModelLabel: ModelLabel; PSet_Revit_Type_Construction - Wrapping at Inserts: 0; Wrapping at Ends: 2; Width: 0.124 m; Function: 0; PSet_Revit_Type_Graphics - Coarse Scale Fill Color: 0; PSet_Revit_Type_Identity Data - Manufacturer: Manufacturer
Basic Wall:Interior - Partition (92mm Stud):235927:7 | Second Floor | PSet_Revit_Dimensions - Length: 32.32 m; Area: 127.04 m2; Volume: 15.7529 m3; PSet_Revit_Phasing - Phase Created: New Construction; PSet_Revit_Other - InstallationDate: InstallationDate; SerialNumber: SerialNumber; WarrantyStartDate: WarrantyStartDate; BarCode: BarCode; AssetIdentifier: AssetIdentifier; TagNumber: TagNumber; PSet_Revit_Constraints - Location Line: 2; Base Constraint: Second Floor; Base Offset: 0 m; Base is Attached: no; Base Extension Distance: 0 m; Top Constraint: Up to level: Roof - Main; Unconnected Height: 4.578 m; Top Offset: -0.102 m; Top is Attached: no; Top Extension Distance: 0 m; Room Bounding: yes; Related to Mass: no; Pset_WallCommon - Reference: Basic Wall:Interior - Partition (92mm Stud); LoadBearing: no; ExtendToStructure: no; IsExternal: no; PSet_Revit_Structural - Structural Usage: 0; PSet_Revit_Type_Other - AccessibilityPerformance: AccessibilityPerformance; CodePerformance: CodePerformance; Color: Color; Constituents: Constituents; Features: Features; Finish: Finish; Grade: Grade; Material: Material; ModelReference: ModelReference; NominalHeight: NominalHeight; NominalLength: NominalLength; NominalWidth: NominalWidth; ProductionYear: ProductionYear; Reference: Reference; Shape: Shape; Size: Size; SustainabilityPerformance: SustainabilityPerformance; WarrantyDescription: WarrantyDescription; WarrantyDurationLabor: WarrantyDurationLabor; WarrantyDurationParts: WarrantyDurationParts; WarrantyGuarantorLabor: WarrantyGuarantorLabor; WarrantyGuarantorParts: WarrantyGuarantorParts; ExpectedLife: ExpectedLife; ReplacementCost: ReplacementCost; AssetAccountingType: FIXED; Classification Code: 23-25 40 11 11 11; Classification Description: Metal-Framed Gypsum Board Fixed Partitions; ModelLabel: ModelLabel; PSet_Revit_Type_Construction - Wrapping at Inserts: 0; Wrapping at Ends: 2; Width: 0.124 m; Function: 0; PSet_Revit_Type_Graphics - Coarse Scale Fill Color: 0; PSet_Revit_Type_Identity Data - Manufacturer: Manufacturer
 | Second Floor | PSet_Revit_Dimensions - Length: 6.16325 m; Area: 16.1127 m2; Volume: 1.99797 m3; PSet_Revit_Phasing - Phase Created: New Construction; PSet_Revit_Other - InstallationDate: InstallationDate; SerialNumber: SerialNumber; WarrantyStartDate: WarrantyStartDate; BarCode: BarCode; AssetIdentifier: AssetIdentifier; TagNumber: TagNumber; PSet_Revit_Constraints - Location Line: 0; Base Constraint: Second Floor; Base Offset: 0 m; Base is Attached: no; Base Extension Distance: 0 m; Top Constraint: Up to level: Roof - Main; Unconnected Height: 4.578 m; Top Offset: -0.102 m; Top is Attached: no; Top Extension Distance: 0 m; Room Bounding: yes; Related to Mass: no; Pset_WallCommon - Reference: Basic Wall:Interior - Partition (92mm Stud); LoadBearing: no; ExtendToStructure: no; IsExternal: no; PSet_Revit_Structural - Structural Usage: 0; PSet_Revit_Type_Other - AccessibilityPerformance: AccessibilityPerformance; CodePerformance: CodePerformance; Color: Color; Constituents: Constituents; Features: Features; Finish: Finish; Grade: Grade; Material: Material; ModelReference: ModelReference; NominalHeight: NominalHeight; NominalLength: NominalLength; NominalWidth: NominalWidth; ProductionYear: ProductionYear; Reference: Reference; Shape: Shape; Size: Size; SustainabilityPerformance: SustainabilityPerformance; WarrantyDescription: WarrantyDescription; WarrantyDurationLabor: WarrantyDurationLabor; WarrantyDurationParts: WarrantyDurationParts; WarrantyGuarantorLabor: WarrantyGuarantorLabor; WarrantyGuarantorParts: WarrantyGuarantorParts; ExpectedLife: ExpectedLife; ReplacementCost: ReplacementCost; AssetAccountingType: FIXED; Classification Code: 23-25 40 11 11 11; Classification Description: Metal-Framed Gypsum Board Fixed Partitions; ModelLabel: ModelLabel; PSet_Revit_Type_Construction - Wrapping at Inserts: 0; Wrapping at Ends: 2; Width: 0.124 m; Function: 0; PSet_Revit_Type_Graphics - Coarse Scale Fill Color: 0; PSet_Revit_Type_Identity Data - Manufacturer: Manufacturer
 | First Floor | PSet_Revit_Dimensions - Length: 4.446 m; Area: 19.4582 m2; Volume: 1.05074 m3; PSet_Revit_Phasing - Phase Created: New Construction; PSet_Revit_Other - InstallationDate: InstallationDate; SerialNumber: SerialNumber; WarrantyStartDate: WarrantyStartDate; BarCode: BarCode; AssetIdentifier: AssetIdentifier; TagNumber: TagNumber; PSet_Revit_Constraints - Location Line: 0; Base Constraint: First Floor; Base Offset: 0 m; Base is Attached: no; Base Extension Distance: 0 m; Top Constraint: Up to level: Second Floor; Unconnected Height: 4.468 m; Top Offset: -0.102 m; Top is Attached: no; Top Extension Distance: 0 m; Room Bounding: yes; Related to Mass: no; Pset_WallCommon - Reference: Basic Wall:Interior - Furring (38 mm Stud); LoadBearing: no; ExtendToStructure: no; IsExternal: no; PSet_Revit_Structural - Structural Usage: 0; PSet_Revit_Type_Other - AccessibilityPerformance: AccessibilityPerformance; CodePerformance: CodePerformance; Color: Color; Constituents: Constituents; Features: Features; Finish: Finish; Grade: Grade; Material: Material; ModelReference: ModelReference; NominalHeight: NominalHeight; NominalLength: NominalLength; NominalWidth: NominalWidth; ProductionYear: ProductionYear; Reference: Reference; Shape: Shape; Size: Size; SustainabilityPerformance: SustainabilityPerformance; WarrantyDescription: WarrantyDescription; WarrantyDurationLabor: WarrantyDurationLabor; WarrantyDurationParts: WarrantyDurationParts; WarrantyGuarantorLabor: WarrantyGuarantorLabor; WarrantyGuarantorParts: WarrantyGuarantorParts; ExpectedLife: ExpectedLife; ReplacementCost: ReplacementCost; AssetAccountingType: FIXED; Classification Code: 23-25 40 11 11 11; Classification Description: Metal-Framed Gypsum Board Fixed Partitions; ModelLabel: ModelLabel; PSet_Revit_Type_Construction - Wrapping at Inserts: 0; Wrapping at Ends: 0; Width: 0.054 m; Function: 0; PSet_Revit_Type_Graphics - Coarse Scale Fill Color: 0; PSet_Revit_Type_Identity Data - Manufacturer: Manufacturer
Basic Wall:Exterior - Insul Panel on Mtl. Stud:290066:2 | Second Floor | PSet_Revit_Dimensions - Length: 15.343 m; Area: 26.423 m2; Volume: 7.05495 m3; PSet_Revit_Phasing - Phase Created: New Construction; PSet_Revit_Other - InstallationDate: InstallationDate; SerialNumber: SerialNumber; WarrantyStartDate: WarrantyStartDate; BarCode: BarCode; AssetIdentifier: AssetIdentifier; TagNumber: TagNumber; PSet_Revit_Constraints - Location Line: 2; Base Constraint: Second Floor; Base Offset: 3.4865 m; Base is Attached: no; Base Extension Distance: 0 m; Top Constraint: Up to level: Roof - Main; Unconnected Height: 1.6505 m; Top Offset: 0.457 m; Top is Attached: no; Top Extension Distance: 0 m; Room Bounding: yes; Related to Mass: no; Pset_WallCommon - Reference: Basic Wall:Exterior - Insul Panel on Mtl. Stud; LoadBearing: no; ExtendToStructure: no; IsExternal: yes; PSet_Revit_Structural - Structural Usage: 0; PSet_Revit_Type_Other - AccessibilityPerformance: AccessibilityPerformance; CodePerformance: CodePerformance; Color: Color; Constituents: Constituents; Features: Features; Finish: Finish; Grade: Grade; Material: Material; ModelReference: ModelReference; NominalHeight: NominalHeight; NominalLength: NominalLength; NominalWidth: NominalWidth; ProductionYear: ProductionYear; Reference: Reference; Shape: Shape; Size: Size; SustainabilityPerformance: SustainabilityPerformance; WarrantyDescription: WarrantyDescription; WarrantyDurationLabor: WarrantyDurationLabor; WarrantyDurationParts: WarrantyDurationParts; WarrantyGuarantorLabor: WarrantyGuarantorLabor; WarrantyGuarantorParts: WarrantyGuarantorParts; ExpectedLife: ExpectedLife; ReplacementCost: ReplacementCost; AssetAccountingType: FIXED; Classification Code: 23-25 30 24 21; Classification Description: Metal Framed Structural Walls; ModelLabel: ModelLabel; PSet_Revit_Type_Construction - Wrapping at Inserts: 0; Wrapping at Ends: 1; Width: 0.267 m; Function: 1; PSet_Revit_Type_Graphics - Coarse Scale Fill Color: 0; PSet_Revit_Type_Identity Data - Manufacturer: Manufacturer
 | First Floor | PSet_Revit_Dimensions - Length: 3.174 m; Area: 12.0934 m2; Volume: 1.49958 m3; PSet_Revit_Phasing - Phase Created: New Construction; PSet_Revit_Other - InstallationDate: InstallationDate; SerialNumber: SerialNumber; WarrantyStartDate: WarrantyStartDate; BarCode: BarCode; AssetIdentifier: AssetIdentifier; TagNumber: TagNumber; PSet_Revit_Constraints - Location Line: 2; Base Constraint: First Floor; Base Offset: 0 m; Base is Attached: no; Base Extension Distance: 0 m; Top Constraint: Up to level: Second Floor; Unconnected Height: 4.468 m; Top Offset: -0.102 m; Top is Attached: no; Top Extension Distance: 0 m; Room Bounding: yes; Related to Mass: no; Pset_WallCommon - Reference: Basic Wall:Interior - Partition (92mm Stud); LoadBearing: no; ExtendToStructure: no; IsExternal: no; PSet_Revit_Structural - Structural Usage: 0; PSet_Revit_Type_Other - AccessibilityPerformance: AccessibilityPerformance; CodePerformance: CodePerformance; Color: Color; Constituents: Constituents; Features: Features; Finish: Finish; Grade: Grade; Material: Material; ModelReference: ModelReference; NominalHeight: NominalHeight; NominalLength: NominalLength; NominalWidth: NominalWidth; ProductionYear: ProductionYear; Reference: Reference; Shape: Shape; Size: Size; SustainabilityPerformance: SustainabilityPerformance; WarrantyDescription: WarrantyDescription; WarrantyDurationLabor: WarrantyDurationLabor; WarrantyDurationParts: WarrantyDurationParts; WarrantyGuarantorLabor: WarrantyGuarantorLabor; WarrantyGuarantorParts: WarrantyGuarantorParts; ExpectedLife: ExpectedLife; ReplacementCost: ReplacementCost; AssetAccountingType: FIXED; Classification Code: 23-25 40 11 11 11; Classification Description: Metal-Framed Gypsum Board Fixed Partitions; ModelLabel: ModelLabel; PSet_Revit_Type_Construction - Wrapping at Inserts: 0; Wrapping at Ends: 2; Width: 0.124 m; Function: 0; PSet_Revit_Type_Graphics - Coarse Scale Fill Color: 0; PSet_Revit_Type_Identity Data - Manufacturer: Manufacturer
 | Second Floor | PSet_Revit_Dimensions - Length: 5.69064 m; Area: 26.1753 m2; Volume: 3.2096 m3; PSet_Revit_Phasing - Phase Created: New Construction; PSet_Revit_Other - InstallationDate: InstallationDate; SerialNumber: SerialNumber; WarrantyStartDate: WarrantyStartDate; BarCode: BarCode; AssetIdentifier: AssetIdentifier; TagNumber: TagNumber; PSet_Revit_Constraints - Location Line: 2; Base Constraint: Second Floor; Base Offset: 0 m; Base is Attached: no; Base Extension Distance: 0 m; Top Constraint: Up to level: Roof - Main; Unconnected Height: 4.578 m; Top Offset: -0.102 m; Top is Attached: no; Top Extension Distance: 0 m; Room Bounding: yes; Related to Mass: no; Pset_WallCommon - Reference: Basic Wall:Interior - Partition (92mm Stud); LoadBearing: no; ExtendToStructure: no; IsExternal: no; PSet_Revit_Structural - Structural Usage: 0; PSet_Revit_Type_Other - AccessibilityPerformance: AccessibilityPerformance; CodePerformance: CodePerformance; Color: Color; Constituents: Constituents; Features: Features; Finish: Finish; Grade: Grade; Material: Material; ModelReference: ModelReference; NominalHeight: NominalHeight; NominalLength: NominalLength; NominalWidth: NominalWidth; ProductionYear: ProductionYear; Reference: Reference; Shape: Shape; Size: Size; SustainabilityPerformance: SustainabilityPerformance; WarrantyDescription: WarrantyDescription; WarrantyDurationLabor: WarrantyDurationLabor; WarrantyDurationParts: WarrantyDurationParts; WarrantyGuarantorLabor: WarrantyGuarantorLabor; WarrantyGuarantorParts: WarrantyGuarantorParts; ExpectedLife: ExpectedLife; ReplacementCost: ReplacementCost; AssetAccountingType: FIXED; Classification Code: 23-25 40 11 11 11; Classification Description: Metal-Framed Gypsum Board Fixed Partitions; ModelLabel: ModelLabel; PSet_Revit_Type_Construction - Wrapping at Inserts: 0; Wrapping at Ends: 2; Width: 0.124 m; Function: 0; PSet_Revit_Type_Graphics - Coarse Scale Fill Color: 0; PSet_Revit_Type_Identity Data - Manufacturer: Manufacturer
 | First Floor | PSet_Revit_Dimensions - Length: 7.326 m; Area: 30.78 m2; Volume: 3.78058 m3; PSet_Revit_Phasing - Phase Created: New Construction; PSet_Revit_Other - InstallationDate: InstallationDate; SerialNumber: SerialNumber; WarrantyStartDate: WarrantyStartDate; BarCode: BarCode; AssetIdentifier: AssetIdentifier; TagNumber: TagNumber; PSet_Revit_Constraints - Location Line: 2; Base Constraint: First Floor; Base Offset: 0 m; Base is Attached: no; Base Extension Distance: 0 m; Top Constraint: Up to level: Second Floor; Unconnected Height: 4.468 m; Top Offset: -0.102 m; Top is Attached: no; Top Extension Distance: 0 m; Room Bounding: yes; Related to Mass: no; Pset_WallCommon - Reference: Basic Wall:Interior - Partition (92mm Stud); LoadBearing: no; ExtendToStructure: no; IsExternal: no; PSet_Revit_Structural - Structural Usage: 0; PSet_Revit_Type_Other - AccessibilityPerformance: AccessibilityPerformance; CodePerformance: CodePerformance; Color: Color; Constituents: Constituents; Features: Features; Finish: Finish; Grade: Grade; Material: Material; ModelReference: ModelReference; NominalHeight: NominalHeight; NominalLength: NominalLength; NominalWidth: NominalWidth; ProductionYear: ProductionYear; Reference: Reference; Shape: Shape; Size: Size; SustainabilityPerformance: SustainabilityPerformance; WarrantyDescription: WarrantyDescription; WarrantyDurationLabor: WarrantyDurationLabor; WarrantyDurationParts: WarrantyDurationParts; WarrantyGuarantorLabor: WarrantyGuarantorLabor; WarrantyGuarantorParts: WarrantyGuarantorParts; ExpectedLife: ExpectedLife; ReplacementCost: ReplacementCost; AssetAccountingType: FIXED; Classification Code: 23-25 40 11 11 11; Classification Description: Metal-Framed Gypsum Board Fixed Partitions; ModelLabel: ModelLabel; PSet_Revit_Type_Construction - Wrapping at Inserts: 0; Wrapping at Ends: 2; Width: 0.124 m; Function: 0; PSet_Revit_Type_Graphics - Coarse Scale Fill Color: 0; PSet_Revit_Type_Identity Data - Manufacturer: Manufacturer
Basic Wall:Interior - Furring (38 mm Stud):358657:2 | First Floor | PSet_Revit_Dimensions - Length: 12.505 m; Area: 40.6016 m2; Volume: 2.19249 m3; PSet_Revit_Phasing - Phase Created: New Construction; PSet_Revit_Other - InstallationDate: InstallationDate; SerialNumber: SerialNumber; WarrantyStartDate: WarrantyStartDate; BarCode: BarCode; AssetIdentifier: AssetIdentifier; TagNumber: TagNumber; PSet_Revit_Constraints - Location Line: 3; Base Constraint: First Floor; Base Offset: 0 m; Base is Attached: no; Base Extension Distance: 0 m; Top Constraint: Up to level: Second Floor; Unconnected Height: 4.468 m; Top Offset: -0.102 m; Top is Attached: no; Top Extension Distance: 0 m; Room Bounding: yes; Related to Mass: no; Pset_WallCommon - Reference: Basic Wall:Interior - Furring (38 mm Stud); LoadBearing: no; ExtendToStructure: no; IsExternal: no; PSet_Revit_Structural - Structural Usage: 0; PSet_Revit_Type_Other - AccessibilityPerformance: AccessibilityPerformance; CodePerformance: CodePerformance; Color: Color; Constituents: Constituents; Features: Features; Finish: Finish; Grade: Grade; Material: Material; ModelReference: ModelReference; NominalHeight: NominalHeight; NominalLength: NominalLength; NominalWidth: NominalWidth; ProductionYear: ProductionYear; Reference: Reference; Shape: Shape; Size: Size; SustainabilityPerformance: SustainabilityPerformance; WarrantyDescription: WarrantyDescription; WarrantyDurationLabor: WarrantyDurationLabor; WarrantyDurationParts: WarrantyDurationParts; WarrantyGuarantorLabor: WarrantyGuarantorLabor; WarrantyGuarantorParts: WarrantyGuarantorParts; ExpectedLife: ExpectedLife; ReplacementCost: ReplacementCost; AssetAccountingType: FIXED; Classification Code: 23-25 40 11 11 11; Classification Description: Metal-Framed Gypsum Board Fixed Partitions; ModelLabel: ModelLabel; PSet_Revit_Type_Construction - Wrapping at Inserts: 0; Wrapping at Ends: 0; Width: 0.054 m; Function: 0; PSet_Revit_Type_Graphics - Coarse Scale Fill Color: 0; PSet_Revit_Type_Identity Data - Manufacturer: Manufacturer
 | First Floor | PSet_Revit_Dimensions - Length: 14.2555 m; Area: 56.2786 m2; Volume: 6.9424 m3; PSet_Revit_Phasing - Phase Created: New Construction; PSet_Revit_Other - InstallationDate: InstallationDate; SerialNumber: SerialNumber; WarrantyStartDate: WarrantyStartDate; BarCode: BarCode; AssetIdentifier: AssetIdentifier; TagNumber: TagNumber; PSet_Revit_Constraints - Location Line: 2; Base Constraint: First Floor; Base Offset: 0 m; Base is Attached: no; Base Extension Distance: 0 m; Top Constraint: Up to level: Second Floor; Unconnected Height: 4.468 m; Top Offset: -0.102 m; Top is Attached: no; Top Extension Distance: 0 m; Room Bounding: yes; Related to Mass: no; Pset_WallCommon - Reference: Basic Wall:Interior - Partition (92mm Stud); LoadBearing: no; ExtendToStructure: no; IsExternal: no; PSet_Revit_Structural - Structural Usage: 0; PSet_Revit_Type_Other - AccessibilityPerformance: AccessibilityPerformance; CodePerformance: CodePerformance; Color: Color; Constituents: Constituents; Features: Features; Finish: Finish; Grade: Grade; Material: Material; ModelReference: ModelReference; NominalHeight: NominalHeight; NominalLength: NominalLength; NominalWidth: NominalWidth; ProductionYear: ProductionYear; Reference: Reference; Shape: Shape; Size: Size; SustainabilityPerformance: SustainabilityPerformance; WarrantyDescription: WarrantyDescription; WarrantyDurationLabor: WarrantyDurationLabor; WarrantyDurationParts: WarrantyDurationParts; WarrantyGuarantorLabor: WarrantyGuarantorLabor; WarrantyGuarantorParts: WarrantyGuarantorParts; ExpectedLife: ExpectedLife; ReplacementCost: ReplacementCost; AssetAccountingType: FIXED; Classification Code: 23-25 40 11 11 11; Classification Description: Metal-Framed Gypsum Board Fixed Partitions; ModelLabel: ModelLabel; PSet_Revit_Type_Construction - Wrapping at Inserts: 0; Wrapping at Ends: 2; Width: 0.124 m; Function: 0; PSet_Revit_Type_Graphics - Coarse Scale Fill Color: 0; PSet_Revit_Type_Identity Data - Manufacturer: Manufacturer
Basic Wall:Exterior - Insul Panel on Mtl. Stud:384376:2 | Second Floor | PSet_Revit_Dimensions - Length: 2.7445 m; Area: 7.39046 m2; Volume: 1.97325 m3; PSet_Revit_Phasing - Phase Created: New Construction; PSet_Revit_Other - InstallationDate: InstallationDate; SerialNumber: SerialNumber; WarrantyStartDate: WarrantyStartDate; BarCode: BarCode; AssetIdentifier: AssetIdentifier; TagNumber: TagNumber; PSet_Revit_Constraints - Location Line: 2; Base Constraint: Second Floor; Base Offset: 0 m; Base is Attached: no; Base Extension Distance: 0 m; Top Constraint: Up to level: Second Floor; Unconnected Height: 2.64 m; Top Offset: 2.64 m; Top is Attached: no; Top Extension Distance: 0 m; Room Bounding: yes; Related to Mass: no; Pset_WallCommon - Reference: Basic Wall:Exterior - Insul Panel on Mtl. Stud; LoadBearing: no; ExtendToStructure: no; IsExternal: yes; PSet_Revit_Structural - Structural Usage: 0; PSet_Revit_Type_Other - AccessibilityPerformance: AccessibilityPerformance; CodePerformance: CodePerformance; Color: Color; Constituents: Constituents; Features: Features; Finish: Finish; Grade: Grade; Material: Material; ModelReference: ModelReference; NominalHeight: NominalHeight; NominalLength: NominalLength; NominalWidth: NominalWidth; ProductionYear: ProductionYear; Reference: Reference; Shape: Shape; Size: Size; SustainabilityPerformance: SustainabilityPerformance; WarrantyDescription: WarrantyDescription; WarrantyDurationLabor: WarrantyDurationLabor; WarrantyDurationParts: WarrantyDurationParts; WarrantyGuarantorLabor: WarrantyGuarantorLabor; WarrantyGuarantorParts: WarrantyGuarantorParts; ExpectedLife: ExpectedLife; ReplacementCost: ReplacementCost; AssetAccountingType: FIXED; Classification Code: 23-25 30 24 21; Classification Description: Metal Framed Structural Walls; ModelLabel: ModelLabel; PSet_Revit_Type_Construction - Wrapping at Inserts: 0; Wrapping at Ends: 1; Width: 0.267 m; Function: 1; PSet_Revit_Type_Graphics - Coarse Scale Fill Color: 0; PSet_Revit_Type_Identity Data - Manufacturer: Manufacturer
Basic Wall:Interior - Partition (92mm Stud):235927:4 | Second Floor | PSet_Revit_Dimensions - Length: 32.32 m; Area: 127.04 m2; Volume: 15.7529 m3; PSet_Revit_Phasing - Phase Created: New Construction; PSet_Revit_Other - InstallationDate: InstallationDate; SerialNumber: SerialNumber; WarrantyStartDate: WarrantyStartDate; BarCode: BarCode; AssetIdentifier: AssetIdentifier; TagNumber: TagNumber; PSet_Revit_Constraints - Location Line: 2; Base Constraint: Second Floor; Base Offset: 0 m; Base is Attached: no; Base Extension Distance: 0 m; Top Constraint: Up to level: Roof - Main; Unconnected Height: 4.578 m; Top Offset: -0.102 m; Top is Attached: no; Top Extension Distance: 0 m; Room Bounding: yes; Related to Mass: no; Pset_WallCommon - Reference: Basic Wall:Interior - Partition (92mm Stud); LoadBearing: no; ExtendToStructure: no; IsExternal: no; PSet_Revit_Structural - Structural Usage: 0; PSet_Revit_Type_Other - AccessibilityPerformance: AccessibilityPerformance; CodePerformance: CodePerformance; Color: Color; Constituents: Constituents; Features: Features; Finish: Finish; Grade: Grade; Material: Material; ModelReference: ModelReference; NominalHeight: NominalHeight; NominalLength: NominalLength; NominalWidth: NominalWidth; ProductionYear: ProductionYear; Reference: Reference; Shape: Shape; Size: Size; SustainabilityPerformance: SustainabilityPerformance; WarrantyDescription: WarrantyDescription; WarrantyDurationLabor: WarrantyDurationLabor; WarrantyDurationParts: WarrantyDurationParts; WarrantyGuarantorLabor: WarrantyGuarantorLabor; WarrantyGuarantorParts: WarrantyGuarantorParts; ExpectedLife: ExpectedLife; ReplacementCost: ReplacementCost; AssetAccountingType: FIXED; Classification Code: 23-25 40 11 11 11; Classification Description: Metal-Framed Gypsum Board Fixed Partitions; ModelLabel: ModelLabel; PSet_Revit_Type_Construction - Wrapping at Inserts: 0; Wrapping at Ends: 2; Width: 0.124 m; Function: 0; PSet_Revit_Type_Graphics - Coarse Scale Fill Color: 0; PSet_Revit_Type_Identity Data - Manufacturer: Manufacturer
 | Second Floor | PSet_Revit_Dimensions - Length: 2.548 m; Area: 11.3809 m2; Volume: 1.37509 m3; PSet_Revit_Phasing - Phase Created: New Construction; PSet_Revit_Other - InstallationDate: InstallationDate; SerialNumber: SerialNumber; WarrantyStartDate: WarrantyStartDate; BarCode: BarCode; AssetIdentifier: AssetIdentifier; TagNumber: TagNumber; PSet_Revit_Constraints - Location Line: 2; Base Constraint: Second Floor; Base Offset: 0 m; Base is Attached: no; Base Extension Distance: 0 m; Top Constraint: Up to level: Roof - Main; Unconnected Height: 4.578 m; Top Offset: -0.102 m; Top is Attached: no; Top Extension Distance: 0 m; Room Bounding: yes; Related to Mass: no; Pset_WallCommon - Reference: Basic Wall:Interior - Partition (92mm Stud); LoadBearing: no; ExtendToStructure: no; IsExternal: no; PSet_Revit_Structural - Structural Usage: 0; PSet_Revit_Type_Other - AccessibilityPerformance: AccessibilityPerformance; CodePerformance: CodePerformance; Color: Color; Constituents: Constituents; Features: Features; Finish: Finish; Grade: Grade; Material: Material; ModelReference: ModelReference; NominalHeight: NominalHeight; NominalLength: NominalLength; NominalWidth: NominalWidth; ProductionYear: ProductionYear; Reference: Reference; Shape: Shape; Size: Size; SustainabilityPerformance: SustainabilityPerformance; WarrantyDescription: WarrantyDescription; WarrantyDurationLabor: WarrantyDurationLabor; WarrantyDurationParts: WarrantyDurationParts; WarrantyGuarantorLabor: WarrantyGuarantorLabor; WarrantyGuarantorParts: WarrantyGuarantorParts; ExpectedLife: ExpectedLife; ReplacementCost: ReplacementCost; AssetAccountingType: FIXED; Classification Code: 23-25 40 11 11 11; Classification Description: Metal-Framed Gypsum Board Fixed Partitions; ModelLabel: ModelLabel; PSet_Revit_Type_Construction - Wrapping at Inserts: 0; Wrapping at Ends: 2; Width: 0.124 m; Function: 0; PSet_Revit_Type_Graphics - Coarse Scale Fill Color: 0; PSet_Revit_Type_Identity Data - Manufacturer: Manufacturer
 | Second Floor | PSet_Revit_Dimensions - Length: 6.12825 m; Area: 15.8474 m2; Volume: 1.96508 m3; PSet_Revit_Phasing - Phase Created: New Construction; PSet_Revit_Other - InstallationDate: InstallationDate; SerialNumber: SerialNumber; WarrantyStartDate: WarrantyStartDate; BarCode: BarCode; AssetIdentifier: AssetIdentifier; TagNumber: TagNumber; PSet_Revit_Constraints - Location Line: 0; Base Constraint: Second Floor; Base Offset: 0 m; Base is Attached: no; Base Extension Distance: 0 m; Top Constraint: Up to level: Roof - Main; Unconnected Height: 4.578 m; Top Offset: -0.102 m; Top is Attached: no; Top Extension Distance: 0 m; Room Bounding: yes; Related to Mass: no; Pset_WallCommon - Reference: Basic Wall:Interior - Partition (92mm Stud); LoadBearing: no; ExtendToStructure: no; IsExternal: no; PSet_Revit_Structural - Structural Usage: 0; PSet_Revit_Type_Other - AccessibilityPerformance: AccessibilityPerformance; CodePerformance: CodePerformance; Color: Color; Constituents: Constituents; Features: Features; Finish: Finish; Grade: Grade; Material: Material; ModelReference: ModelReference; NominalHeight: NominalHeight; NominalLength: NominalLength; NominalWidth: NominalWidth; ProductionYear: ProductionYear; Reference: Reference; Shape: Shape; Size: Size; SustainabilityPerformance: SustainabilityPerformance; WarrantyDescription: WarrantyDescription; WarrantyDurationLabor: WarrantyDurationLabor; WarrantyDurationParts: WarrantyDurationParts; WarrantyGuarantorLabor: WarrantyGuarantorLabor; WarrantyGuarantorParts: WarrantyGuarantorParts; ExpectedLife: ExpectedLife; ReplacementCost: ReplacementCost; AssetAccountingType: FIXED; Classification Code: 23-25 40 11 11 11; Classification Description: Metal-Framed Gypsum Board Fixed Partitions; ModelLabel: ModelLabel; PSet_Revit_Type_Construction - Wrapping at Inserts: 0; Wrapping at Ends: 2; Width: 0.124 m; Function: 0; PSet_Revit_Type_Graphics - Coarse Scale Fill Color: 0; PSet_Revit_Type_Identity Data - Manufacturer: Manufacturer
2 x  | First Floor | PSet_Revit_Dimensions - Length: 2.786 m; Area: 11.8938 m2; Volume: 1.96202 m3; PSet_Revit_Phasing - Phase Created: New Construction; PSet_Revit_Other - InstallationDate: InstallationDate; SerialNumber: SerialNumber; WarrantyStartDate: WarrantyStartDate; BarCode: BarCode; AssetIdentifier: AssetIdentifier; TagNumber: TagNumber; PSet_Revit_Constraints - Location Line: 0; Base Constraint: First Floor; Base Offset: 0 m; Base is Attached: no; Base Extension Distance: 0 m; Top Constraint: Up to level: Second Floor; Unconnected Height: 4.468 m; Top Offset: -0.102 m; Top is Attached: no; Top Extension Distance: 0 m; Room Bounding: yes; Related to Mass: no; Pset_WallCommon - Reference: Basic Wall:Interior - Furring (152 mm Stud); LoadBearing: no; ExtendToStructure: no; IsExternal: no; PSet_Revit_Structural - Structural Usage: 0; PSet_Revit_Type_Other - AccessibilityPerformance: AccessibilityPerformance; CodePerformance: CodePerformance; Color: Color; Constituents: Constituents; Features: Features; Finish: Finish; Grade: Grade; Material: Material; ModelReference: ModelReference; NominalHeight: NominalHeight; NominalLength: NominalLength; NominalWidth: NominalWidth; ProductionYear: ProductionYear; Reference: Reference; Shape: Shape; Size: Size; SustainabilityPerformance: SustainabilityPerformance; WarrantyDescription: WarrantyDescription; WarrantyDurationLabor: WarrantyDurationLabor; WarrantyDurationParts: WarrantyDurationParts; WarrantyGuarantorLabor: WarrantyGuarantorLabor; WarrantyGuarantorParts: WarrantyGuarantorParts; ExpectedLife: ExpectedLife; ReplacementCost: ReplacementCost; AssetAccountingType: FIXED; Classification Code: 23-25 40 11 11 11; Classification Description: Metal-Framed Gypsum Board Fixed Partitions; ModelLabel: ModelLabel; PSet_Revit_Type_Construction - Wrapping at Inserts: 0; Wrapping at Ends: 0; Width: 0.168 m; Function: 0; PSet_Revit_Type_Graphics - Coarse Scale Fill Color: 0; PSet_Revit_Type_Identity Data - Manufacturer: Manufacturer
Basic Wall:Interior - Furring (152 mm Stud):184583:2 | First Floor | PSet_Revit_Dimensions - Length: 9.15715 m; Area: 25.9775 m2; Volume: 4.36421 m3; PSet_Revit_Phasing - Phase Created: New Construction; PSet_Revit_Other - InstallationDate: InstallationDate; SerialNumber: SerialNumber; WarrantyStartDate: WarrantyStartDate; BarCode: BarCode; AssetIdentifier: AssetIdentifier; TagNumber: TagNumber; PSet_Revit_Constraints - Location Line: 3; Base Constraint: First Floor; Base Offset: 0 m; Base is Attached: no; Base Extension Distance: 0 m; Top Constraint: Up to level: Second Floor; Unconnected Height: 4.468 m; Top Offset: -0.102 m; Top is Attached: no; Top Extension Distance: 0 m; Room Bounding: yes; Related to Mass: no; Pset_WallCommon - Reference: Basic Wall:Interior - Furring (152 mm Stud); LoadBearing: no; ExtendToStructure: no; IsExternal: no; PSet_Revit_Structural - Structural Usage: 0; PSet_Revit_Type_Other - AccessibilityPerformance: AccessibilityPerformance; CodePerformance: CodePerformance; Color: Color; Constituents: Constituents; Features: Features; Finish: Finish; Grade: Grade; Material: Material; ModelReference: ModelReference; NominalHeight: NominalHeight; NominalLength: NominalLength; NominalWidth: NominalWidth; ProductionYear: ProductionYear; Reference: Reference; Shape: Shape; Size: Size; SustainabilityPerformance: SustainabilityPerformance; WarrantyDescription: WarrantyDescription; WarrantyDurationLabor: WarrantyDurationLabor; WarrantyDurationParts: WarrantyDurationParts; WarrantyGuarantorLabor: WarrantyGuarantorLabor; WarrantyGuarantorParts: WarrantyGuarantorParts; ExpectedLife: ExpectedLife; ReplacementCost: ReplacementCost; AssetAccountingType: FIXED; Classification Code: 23-25 40 11 11 11; Classification Description: Metal-Framed Gypsum Board Fixed Partitions; ModelLabel: ModelLabel; PSet_Revit_Type_Construction - Wrapping at Inserts: 0; Wrapping at Ends: 0; Width: 0.168 m; Function: 0; PSet_Revit_Type_Graphics - Coarse Scale Fill Color: 0; PSet_Revit_Type_Identity Data - Manufacturer: Manufacturer
 | Second Floor | PSet_Revit_Dimensions - Length: 6.44109 m; Area: 28.6733 m2; Volume: 1.53971 m3; PSet_Revit_Phasing - Phase Created: New Construction; PSet_Revit_Other - InstallationDate: InstallationDate; SerialNumber: SerialNumber; WarrantyStartDate: WarrantyStartDate; BarCode: BarCode; AssetIdentifier: AssetIdentifier; TagNumber: TagNumber; PSet_Revit_Constraints - Location Line: 2; Base Constraint: Second Floor; Base Offset: 0 m; Base is Attached: no; Base Extension Distance: 0 m; Top Constraint: Up to level: Roof - Main; Unconnected Height: 4.578 m; Top Offset: -0.102 m; Top is Attached: no; Top Extension Distance: 0 m; Room Bounding: yes; Related to Mass: no; Pset_WallCommon - Reference: Basic Wall:Interior - Furring (38 mm Stud); LoadBearing: no; ExtendToStructure: no; IsExternal: no; PSet_Revit_Structural - Structural Usage: 0; PSet_Revit_Type_Other - AccessibilityPerformance: AccessibilityPerformance; CodePerformance: CodePerformance; Color: Color; Constituents: Constituents; Features: Features; Finish: Finish; Grade: Grade; Material: Material; ModelReference: ModelReference; NominalHeight: NominalHeight; NominalLength: NominalLength; NominalWidth: NominalWidth; ProductionYear: ProductionYear; Reference: Reference; Shape: Shape; Size: Size; SustainabilityPerformance: SustainabilityPerformance; WarrantyDescription: WarrantyDescription; WarrantyDurationLabor: WarrantyDurationLabor; WarrantyDurationParts: WarrantyDurationParts; WarrantyGuarantorLabor: WarrantyGuarantorLabor; WarrantyGuarantorParts: WarrantyGuarantorParts; ExpectedLife: ExpectedLife; ReplacementCost: ReplacementCost; AssetAccountingType: FIXED; Classification Code: 23-25 40 11 11 11; Classification Description: Metal-Framed Gypsum Board Fixed Partitions; ModelLabel: ModelLabel; PSet_Revit_Type_Construction - Wrapping at Inserts: 0; Wrapping at Ends: 0; Width: 0.054 m; Function: 0; PSet_Revit_Type_Graphics - Coarse Scale Fill Color: 0; PSet_Revit_Type_Identity Data - Manufacturer: Manufacturer
 | Second Floor | PSet_Revit_Dimensions - Length: 2.36464 m; Area: 10.2576 m2; Volume: 1.23581 m3; PSet_Revit_Phasing - Phase Created: New Construction; PSet_Revit_Other - InstallationDate: InstallationDate; SerialNumber: SerialNumber; WarrantyStartDate: WarrantyStartDate; BarCode: BarCode; AssetIdentifier: AssetIdentifier; TagNumber: TagNumber; PSet_Revit_Constraints - Location Line: 2; Base Constraint: Second Floor; Base Offset: 0 m; Base is Attached: no; Base Extension Distance: 0 m; Top Constraint: Up to level: Roof - Main; Unconnected Height: 4.578 m; Top Offset: -0.102 m; Top is Attached: no; Top Extension Distance: 0 m; Room Bounding: yes; Related to Mass: no; Pset_WallCommon - Reference: Basic Wall:Interior - Partition (92mm Stud); LoadBearing: no; ExtendToStructure: no; IsExternal: no; PSet_Revit_Structural - Structural Usage: 0; PSet_Revit_Type_Other - AccessibilityPerformance: AccessibilityPerformance; CodePerformance: CodePerformance; Color: Color; Constituents: Constituents; Features: Features; Finish: Finish; Grade: Grade; Material: Material; ModelReference: ModelReference; NominalHeight: NominalHeight; NominalLength: NominalLength; NominalWidth: NominalWidth; ProductionYear: ProductionYear; Reference: Reference; Shape: Shape; Size: Size; SustainabilityPerformance: SustainabilityPerformance; WarrantyDescription: WarrantyDescription; WarrantyDurationLabor: WarrantyDurationLabor; WarrantyDurationParts: WarrantyDurationParts; WarrantyGuarantorLabor: WarrantyGuarantorLabor; WarrantyGuarantorParts: WarrantyGuarantorParts; ExpectedLife: ExpectedLife; ReplacementCost: ReplacementCost; AssetAccountingType: FIXED; Classification Code: 23-25 40 11 11 11; Classification Description: Metal-Framed Gypsum Board Fixed Partitions; ModelLabel: ModelLabel; PSet_Revit_Type_Construction - Wrapping at Inserts: 0; Wrapping at Ends: 2; Width: 0.124 m; Function: 0; PSet_Revit_Type_Graphics - Coarse Scale Fill Color: 0; PSet_Revit_Type_Identity Data - Manufacturer: Manufacturer
 | First Floor | PSet_Revit_Dimensions - Length: 2.756 m; Area: 11.7598 m2; Volume: 2.12766 m3; PSet_Revit_Phasing - Phase Created: New Construction; PSet_Revit_Other - InstallationDate: InstallationDate; SerialNumber: SerialNumber; WarrantyStartDate: WarrantyStartDate; BarCode: BarCode; AssetIdentifier: AssetIdentifier; TagNumber: TagNumber; PSet_Revit_Constraints - Location Line: 2; Base Constraint: First Floor; Base Offset: 0 m; Base is Attached: no; Base Extension Distance: 0 m; Top Constraint: Up to level: Second Floor; Unconnected Height: 4.468 m; Top Offset: -0.102 m; Top is Attached: no; Top Extension Distance: 0 m; Room Bounding: yes; Related to Mass: no; Pset_WallCommon - Reference: Basic Wall:Interior - Plumbing (152mm Stud); LoadBearing: no; ExtendToStructure: no; IsExternal: no; PSet_Revit_Structural - Structural Usage: 0; PSet_Revit_Type_Other - AccessibilityPerformance: AccessibilityPerformance; CodePerformance: CodePerformance; Color: Color; Constituents: Constituents; Features: Features; Finish: Finish; Grade: Grade; Material: Material; ModelReference: ModelReference; NominalHeight: NominalHeight; NominalLength: NominalLength; NominalWidth: NominalWidth; ProductionYear: ProductionYear; Reference: Reference; Shape: Shape; Size: Size; SustainabilityPerformance: SustainabilityPerformance; WarrantyDescription: WarrantyDescription; WarrantyDurationLabor: WarrantyDurationLabor; WarrantyDurationParts: WarrantyDurationParts; WarrantyGuarantorLabor: WarrantyGuarantorLabor; WarrantyGuarantorParts: WarrantyGuarantorParts; ExpectedLife: ExpectedLife; ReplacementCost: ReplacementCost; AssetAccountingType: FIXED; Classification Code: 23-25 40 11 11 11; Classification Description: Metal-Framed Gypsum Board Fixed Partitions; ModelLabel: ModelLabel; PSet_Revit_Type_Construction - Wrapping at Inserts: 0; Wrapping at Ends: 2; Width: 0.184 m; Function: 0; PSet_Revit_Type_Graphics - Coarse Scale Fill Color: 0; PSet_Revit_Type_Identity Data - Manufacturer: Manufacturer
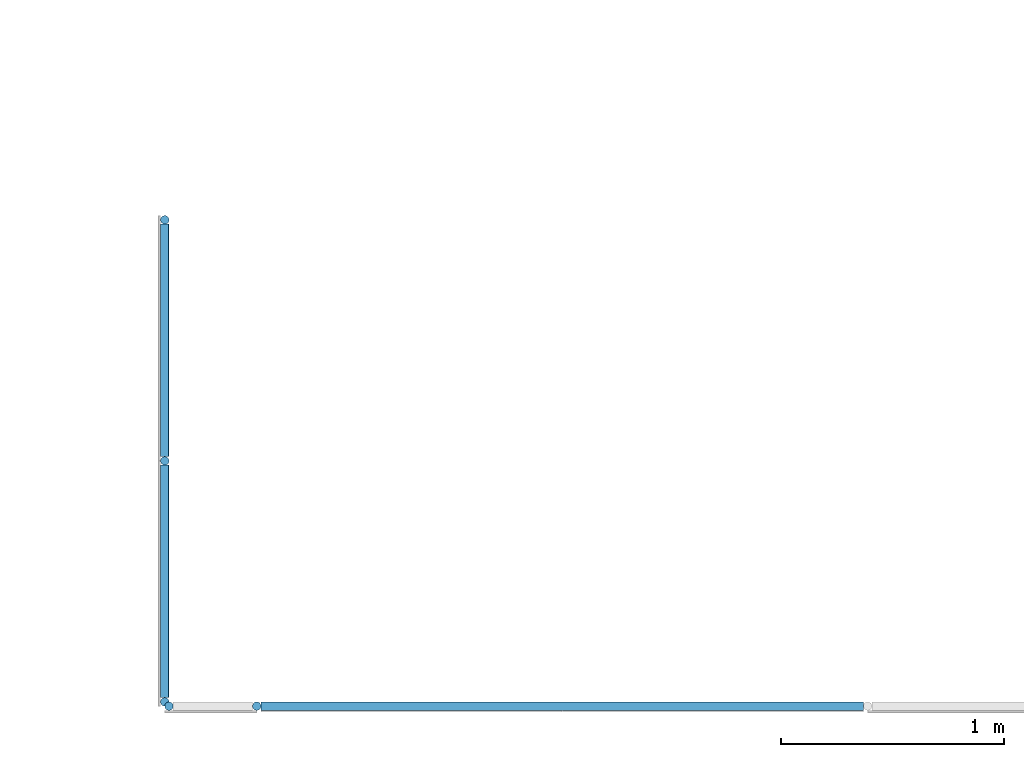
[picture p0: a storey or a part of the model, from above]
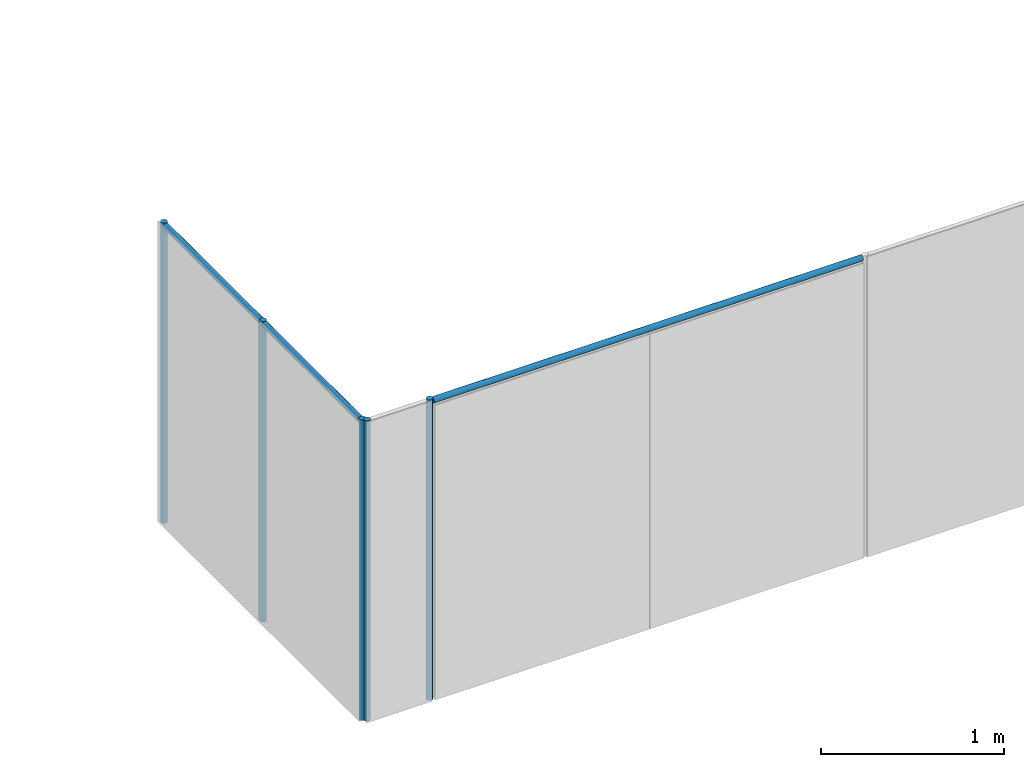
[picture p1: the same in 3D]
Properties of the parts of a building model (IFC2X3), part 6 of 11

# IfcOpeningElement: Opening (403)
Name | In
 | First Floor | PSet_Revit_Dimensions - Length: 6.945 m; Area: 27.9934 m2; Volume: 3.43504 m3; PSet_Revit_Phasing - Phase Created: New Construction; PSet_Revit_Other - InstallationDate: InstallationDate; SerialNumber: SerialNumber; WarrantyStartDate: WarrantyStartDate; BarCode: BarCode; AssetIdentifier: AssetIdentifier; TagNumber: TagNumber; PSet_Revit_Constraints - Location Line: 2; Base Constraint: First Floor; Base Offset: 0 m; Base is Attached: no; Base Extension Distance: 0 m; Top Constraint: Up to level: Second Floor; Unconnected Height: 4.57 m; Top Offset: 0 m; Top is Attached: no; Top Extension Distance: 0 m; Room Bounding: yes; Related to Mass: no; Pset_WallCommon - Reference: Basic Wall:Interior - Partition (92mm Stud); LoadBearing: no; ExtendToStructure: no; IsExternal: no; PSet_Revit_Structural - Structural Usage: 0; PSet_Revit_Type_Other - AccessibilityPerformance: AccessibilityPerformance; CodePerformance: CodePerformance; Color: Color; Constituents: Constituents; Features: Features; Finish: Finish; Grade: Grade; Material: Material; ModelReference: ModelReference; NominalHeight: NominalHeight; NominalLength: NominalLength; NominalWidth: NominalWidth; ProductionYear: ProductionYear; Reference: Reference; Shape: Shape; Size: Size; SustainabilityPerformance: SustainabilityPerformance; WarrantyDescription: WarrantyDescription; WarrantyDurationLabor: WarrantyDurationLabor; WarrantyDurationParts: WarrantyDurationParts; WarrantyGuarantorLabor: WarrantyGuarantorLabor; WarrantyGuarantorParts: WarrantyGuarantorParts; ExpectedLife: ExpectedLife; ReplacementCost: ReplacementCost; AssetAccountingType: FIXED; Classification Code: 23-25 40 11 11 11; Classification Description: Metal-Framed Gypsum Board Fixed Partitions; ModelLabel: ModelLabel; PSet_Revit_Type_Construction - Wrapping at Inserts: 0; Wrapping at Ends: 2; Width: 0.124 m; Function: 0; PSet_Revit_Type_Graphics - Coarse Scale Fill Color: 0; PSet_Revit_Type_Identity Data - Manufacturer: Manufacturer
Basic Wall:Interior - Partition (92mm Stud):196610:2 | Second Floor | PSet_Revit_Dimensions - Length: 7.96064 m; Area: 31.4877 m2; Volume: 3.90447 m3; PSet_Revit_Phasing - Phase Created: New Construction; PSet_Revit_Other - InstallationDate: InstallationDate; SerialNumber: SerialNumber; WarrantyStartDate: WarrantyStartDate; BarCode: BarCode; AssetIdentifier: AssetIdentifier; TagNumber: TagNumber; PSet_Revit_Constraints - Location Line: 2; Base Constraint: Second Floor; Base Offset: 0 m; Base is Attached: no; Base Extension Distance: 0 m; Top Constraint: Up to level: Roof - Main; Unconnected Height: 4.38 m; Top Offset: -0.3 m; Top is Attached: no; Top Extension Distance: 0 m; Room Bounding: yes; Related to Mass: no; Pset_WallCommon - Reference: Basic Wall:Interior - Partition (92mm Stud); LoadBearing: no; ExtendToStructure: no; IsExternal: no; PSet_Revit_Structural - Structural Usage: 0; PSet_Revit_Type_Other - AccessibilityPerformance: AccessibilityPerformance; CodePerformance: CodePerformance; Color: Color; Constituents: Constituents; Features: Features; Finish: Finish; Grade: Grade; Material: Material; ModelReference: ModelReference; NominalHeight: NominalHeight; NominalLength: NominalLength; NominalWidth: NominalWidth; ProductionYear: ProductionYear; Reference: Reference; Shape: Shape; Size: Size; SustainabilityPerformance: SustainabilityPerformance; WarrantyDescription: WarrantyDescription; WarrantyDurationLabor: WarrantyDurationLabor; WarrantyDurationParts: WarrantyDurationParts; WarrantyGuarantorLabor: WarrantyGuarantorLabor; WarrantyGuarantorParts: WarrantyGuarantorParts; ExpectedLife: ExpectedLife; ReplacementCost: ReplacementCost; AssetAccountingType: FIXED; Classification Code: 23-25 40 11 11 11; Classification Description: Metal-Framed Gypsum Board Fixed Partitions; ModelLabel: ModelLabel; PSet_Revit_Type_Construction - Wrapping at Inserts: 0; Wrapping at Ends: 2; Width: 0.124 m; Function: 0; PSet_Revit_Type_Graphics - Coarse Scale Fill Color: 0; PSet_Revit_Type_Identity Data - Manufacturer: Manufacturer
Basic Wall:Exterior - Insul Panel on Mtl. Stud:381802:2 | Second Floor | PSet_Revit_Dimensions - Length: 15.343 m; Area: 26.423 m2; Volume: 7.05495 m3; PSet_Revit_Phasing - Phase Created: New Construction; PSet_Revit_Other - InstallationDate: InstallationDate; SerialNumber: SerialNumber; WarrantyStartDate: WarrantyStartDate; BarCode: BarCode; AssetIdentifier: AssetIdentifier; TagNumber: TagNumber; PSet_Revit_Constraints - Location Line: 2; Base Constraint: Second Floor; Base Offset: 3.4865 m; Base is Attached: no; Base Extension Distance: 0 m; Top Constraint: Up to level: Roof - Main; Unconnected Height: 1.6505 m; Top Offset: 0.457 m; Top is Attached: no; Top Extension Distance: 0 m; Room Bounding: yes; Related to Mass: no; Pset_WallCommon - Reference: Basic Wall:Exterior - Insul Panel on Mtl. Stud; LoadBearing: no; ExtendToStructure: no; IsExternal: yes; PSet_Revit_Structural - Structural Usage: 0; PSet_Revit_Type_Other - AccessibilityPerformance: AccessibilityPerformance; CodePerformance: CodePerformance; Color: Color; Constituents: Constituents; Features: Features; Finish: Finish; Grade: Grade; Material: Material; ModelReference: ModelReference; NominalHeight: NominalHeight; NominalLength: NominalLength; NominalWidth: NominalWidth; ProductionYear: ProductionYear; Reference: Reference; Shape: Shape; Size: Size; SustainabilityPerformance: SustainabilityPerformance; WarrantyDescription: WarrantyDescription; WarrantyDurationLabor: WarrantyDurationLabor; WarrantyDurationParts: WarrantyDurationParts; WarrantyGuarantorLabor: WarrantyGuarantorLabor; WarrantyGuarantorParts: WarrantyGuarantorParts; ExpectedLife: ExpectedLife; ReplacementCost: ReplacementCost; AssetAccountingType: FIXED; Classification Code: 23-25 30 24 21; Classification Description: Metal Framed Structural Walls; ModelLabel: ModelLabel; PSet_Revit_Type_Construction - Wrapping at Inserts: 0; Wrapping at Ends: 1; Width: 0.267 m; Function: 1; PSet_Revit_Type_Graphics - Coarse Scale Fill Color: 0; PSet_Revit_Type_Identity Data - Manufacturer: Manufacturer
 | First Floor | PSet_Revit_Dimensions - Length: 12.344 m; Area: 49.2952 m2; Volume: 6.07646 m3; PSet_Revit_Phasing - Phase Created: New Construction; PSet_Revit_Other - InstallationDate: InstallationDate; SerialNumber: SerialNumber; WarrantyStartDate: WarrantyStartDate; BarCode: BarCode; AssetIdentifier: AssetIdentifier; TagNumber: TagNumber; PSet_Revit_Constraints - Location Line: 2; Base Constraint: First Floor; Base Offset: 0 m; Base is Attached: no; Base Extension Distance: 0 m; Top Constraint: Up to level: Second Floor; Unconnected Height: 4.468 m; Top Offset: -0.102 m; Top is Attached: no; Top Extension Distance: 0 m; Room Bounding: yes; Related to Mass: no; Pset_WallCommon - Reference: Basic Wall:Interior - Partition (92mm Stud); LoadBearing: no; ExtendToStructure: no; IsExternal: no; PSet_Revit_Structural - Structural Usage: 0; PSet_Revit_Type_Other - AccessibilityPerformance: AccessibilityPerformance; CodePerformance: CodePerformance; Color: Color; Constituents: Constituents; Features: Features; Finish: Finish; Grade: Grade; Material: Material; ModelReference: ModelReference; NominalHeight: NominalHeight; NominalLength: NominalLength; NominalWidth: NominalWidth; ProductionYear: ProductionYear; Reference: Reference; Shape: Shape; Size: Size; SustainabilityPerformance: SustainabilityPerformance; WarrantyDescription: WarrantyDescription; WarrantyDurationLabor: WarrantyDurationLabor; WarrantyDurationParts: WarrantyDurationParts; WarrantyGuarantorLabor: WarrantyGuarantorLabor; WarrantyGuarantorParts: WarrantyGuarantorParts; ExpectedLife: ExpectedLife; ReplacementCost: ReplacementCost; AssetAccountingType: FIXED; Classification Code: 23-25 40 11 11 11; Classification Description: Metal-Framed Gypsum Board Fixed Partitions; ModelLabel: ModelLabel; PSet_Revit_Type_Construction - Wrapping at Inserts: 0; Wrapping at Ends: 2; Width: 0.124 m; Function: 0; PSet_Revit_Type_Graphics - Coarse Scale Fill Color: 0; PSet_Revit_Type_Identity Data - Manufacturer: Manufacturer
Basic Wall:Interior - Partition (92mm Stud):235927:3 | Second Floor | PSet_Revit_Dimensions - Length: 32.32 m; Area: 127.04 m2; Volume: 15.7529 m3; PSet_Revit_Phasing - Phase Created: New Construction; PSet_Revit_Other - InstallationDate: InstallationDate; SerialNumber: SerialNumber; WarrantyStartDate: WarrantyStartDate; BarCode: BarCode; AssetIdentifier: AssetIdentifier; TagNumber: TagNumber; PSet_Revit_Constraints - Location Line: 2; Base Constraint: Second Floor; Base Offset: 0 m; Base is Attached: no; Base Extension Distance: 0 m; Top Constraint: Up to level: Roof - Main; Unconnected Height: 4.578 m; Top Offset: -0.102 m; Top is Attached: no; Top Extension Distance: 0 m; Room Bounding: yes; Related to Mass: no; Pset_WallCommon - Reference: Basic Wall:Interior - Partition (92mm Stud); LoadBearing: no; ExtendToStructure: no; IsExternal: no; PSet_Revit_Structural - Structural Usage: 0; PSet_Revit_Type_Other - AccessibilityPerformance: AccessibilityPerformance; CodePerformance: CodePerformance; Color: Color; Constituents: Constituents; Features: Features; Finish: Finish; Grade: Grade; Material: Material; ModelReference: ModelReference; NominalHeight: NominalHeight; NominalLength: NominalLength; NominalWidth: NominalWidth; ProductionYear: ProductionYear; Reference: Reference; Shape: Shape; Size: Size; SustainabilityPerformance: SustainabilityPerformance; WarrantyDescription: WarrantyDescription; WarrantyDurationLabor: WarrantyDurationLabor; WarrantyDurationParts: WarrantyDurationParts; WarrantyGuarantorLabor: WarrantyGuarantorLabor; WarrantyGuarantorParts: WarrantyGuarantorParts; ExpectedLife: ExpectedLife; ReplacementCost: ReplacementCost; AssetAccountingType: FIXED; Classification Code: 23-25 40 11 11 11; Classification Description: Metal-Framed Gypsum Board Fixed Partitions; ModelLabel: ModelLabel; PSet_Revit_Type_Construction - Wrapping at Inserts: 0; Wrapping at Ends: 2; Width: 0.124 m; Function: 0; PSet_Revit_Type_Graphics - Coarse Scale Fill Color: 0; PSet_Revit_Type_Identity Data - Manufacturer: Manufacturer
2 x  | Second Floor | PSet_Revit_Dimensions - Length: 2.796 m; Area: 12.2324 m2; Volume: 2.01891 m3; PSet_Revit_Phasing - Phase Created: New Construction; PSet_Revit_Other - InstallationDate: InstallationDate; SerialNumber: SerialNumber; WarrantyStartDate: WarrantyStartDate; BarCode: BarCode; AssetIdentifier: AssetIdentifier; TagNumber: TagNumber; PSet_Revit_Constraints - Location Line: 2; Base Constraint: Second Floor; Base Offset: 0 m; Base is Attached: no; Base Extension Distance: 0 m; Top Constraint: Up to level: Roof - Main; Unconnected Height: 4.578 m; Top Offset: -0.102 m; Top is Attached: no; Top Extension Distance: 0 m; Room Bounding: yes; Related to Mass: no; Pset_WallCommon - Reference: Basic Wall:Interior - Furring (152 mm Stud); LoadBearing: no; ExtendToStructure: no; IsExternal: no; PSet_Revit_Structural - Structural Usage: 0; PSet_Revit_Type_Other - AccessibilityPerformance: AccessibilityPerformance; CodePerformance: CodePerformance; Color: Color; Constituents: Constituents; Features: Features; Finish: Finish; Grade: Grade; Material: Material; ModelReference: ModelReference; NominalHeight: NominalHeight; NominalLength: NominalLength; NominalWidth: NominalWidth; ProductionYear: ProductionYear; Reference: Reference; Shape: Shape; Size: Size; SustainabilityPerformance: SustainabilityPerformance; WarrantyDescription: WarrantyDescription; WarrantyDurationLabor: WarrantyDurationLabor; WarrantyDurationParts: WarrantyDurationParts; WarrantyGuarantorLabor: WarrantyGuarantorLabor; WarrantyGuarantorParts: WarrantyGuarantorParts; ExpectedLife: ExpectedLife; ReplacementCost: ReplacementCost; AssetAccountingType: FIXED; Classification Code: 23-25 40 11 11 11; Classification Description: Metal-Framed Gypsum Board Fixed Partitions; ModelLabel: ModelLabel; PSet_Revit_Type_Construction - Wrapping at Inserts: 0; Wrapping at Ends: 0; Width: 0.168 m; Function: 0; PSet_Revit_Type_Graphics - Coarse Scale Fill Color: 0; PSet_Revit_Type_Identity Data - Manufacturer: Manufacturer
Basic Wall:Interior - Partition (92mm Stud):204593:2 | Second Floor | PSet_Revit_Dimensions - Length: 3.465 m; Area: 14.644 m2; Volume: 1.81586 m3; PSet_Revit_Phasing - Phase Created: New Construction; PSet_Revit_Other - InstallationDate: InstallationDate; SerialNumber: SerialNumber; WarrantyStartDate: WarrantyStartDate; BarCode: BarCode; AssetIdentifier: AssetIdentifier; TagNumber: TagNumber; PSet_Revit_Constraints - Location Line: 2; Base Constraint: Second Floor; Base Offset: 0 m; Base is Attached: no; Base Extension Distance: 0 m; Top Constraint: Up to level: Roof - Main; Unconnected Height: 4.578 m; Top Offset: -0.102 m; Top is Attached: no; Top Extension Distance: 0 m; Room Bounding: yes; Related to Mass: no; Pset_WallCommon - Reference: Basic Wall:Interior - Partition (92mm Stud); LoadBearing: no; ExtendToStructure: no; IsExternal: no; PSet_Revit_Structural - Structural Usage: 0; PSet_Revit_Type_Other - AccessibilityPerformance: AccessibilityPerformance; CodePerformance: CodePerformance; Color: Color; Constituents: Constituents; Features: Features; Finish: Finish; Grade: Grade; Material: Material; ModelReference: ModelReference; NominalHeight: NominalHeight; NominalLength: NominalLength; NominalWidth: NominalWidth; ProductionYear: ProductionYear; Reference: Reference; Shape: Shape; Size: Size; SustainabilityPerformance: SustainabilityPerformance; WarrantyDescription: WarrantyDescription; WarrantyDurationLabor: WarrantyDurationLabor; WarrantyDurationParts: WarrantyDurationParts; WarrantyGuarantorLabor: WarrantyGuarantorLabor; WarrantyGuarantorParts: WarrantyGuarantorParts; ExpectedLife: ExpectedLife; ReplacementCost: ReplacementCost; AssetAccountingType: FIXED; Classification Code: 23-25 40 11 11 11; Classification Description: Metal-Framed Gypsum Board Fixed Partitions; ModelLabel: ModelLabel; PSet_Revit_Type_Construction - Wrapping at Inserts: 0; Wrapping at Ends: 2; Width: 0.124 m; Function: 0; PSet_Revit_Type_Graphics - Coarse Scale Fill Color: 0; PSet_Revit_Type_Identity Data - Manufacturer: Manufacturer
Basic Wall:Exterior - Insul Panel on Mtl. Stud:144932:2 | Second Floor | PSet_Revit_Dimensions - Length: 19.9665 m; Area: 90.8333 m2; Volume: 24.2525 m3; PSet_Revit_Phasing - Phase Created: New Construction; PSet_Revit_Other - InstallationDate: InstallationDate; SerialNumber: SerialNumber; WarrantyStartDate: WarrantyStartDate; BarCode: BarCode; AssetIdentifier: AssetIdentifier; TagNumber: TagNumber; PSet_Revit_Constraints - Location Line: 2; Base Constraint: Second Floor; Base Offset: 0 m; Base is Attached: no; Base Extension Distance: 0 m; Top Constraint: Up to level: Roof - Main; Unconnected Height: 5.137 m; Top Offset: 0.457 m; Top is Attached: no; Top Extension Distance: 0 m; Room Bounding: yes; Related to Mass: no; Pset_WallCommon - Reference: Basic Wall:Exterior - Insul Panel on Mtl. Stud; LoadBearing: no; ExtendToStructure: no; IsExternal: yes; PSet_Revit_Structural - Structural Usage: 0; PSet_Revit_Type_Other - AccessibilityPerformance: AccessibilityPerformance; CodePerformance: CodePerformance; Color: Color; Constituents: Constituents; Features: Features; Finish: Finish; Grade: Grade; Material: Material; ModelReference: ModelReference; NominalHeight: NominalHeight; NominalLength: NominalLength; NominalWidth: NominalWidth; ProductionYear: ProductionYear; Reference: Reference; Shape: Shape; Size: Size; SustainabilityPerformance: SustainabilityPerformance; WarrantyDescription: WarrantyDescription; WarrantyDurationLabor: WarrantyDurationLabor; WarrantyDurationParts: WarrantyDurationParts; WarrantyGuarantorLabor: WarrantyGuarantorLabor; WarrantyGuarantorParts: WarrantyGuarantorParts; ExpectedLife: ExpectedLife; ReplacementCost: ReplacementCost; AssetAccountingType: FIXED; Classification Code: 23-25 30 24 21; Classification Description: Metal Framed Structural Walls; ModelLabel: ModelLabel; PSet_Revit_Type_Construction - Wrapping at Inserts: 0; Wrapping at Ends: 1; Width: 0.267 m; Function: 1; PSet_Revit_Type_Graphics - Coarse Scale Fill Color: 0; PSet_Revit_Type_Identity Data - Manufacturer: Manufacturer
 | Second Floor | PSet_Revit_Dimensions - Length: 11.691 m; Area: 27.9217 m2; Volume: 3.46229 m3; PSet_Revit_Phasing - Phase Created: New Construction; PSet_Revit_Other - InstallationDate: InstallationDate; SerialNumber: SerialNumber; WarrantyStartDate: WarrantyStartDate; BarCode: BarCode; AssetIdentifier: AssetIdentifier; TagNumber: TagNumber; PSet_Revit_Constraints - Location Line: 2; Base Constraint: Second Floor; Base Offset: 0 m; Base is Attached: no; Base Extension Distance: 0 m; Top Constraint: Up to level: Roof - Main; Unconnected Height: 4.68 m; Top Offset: 0 m; Top is Attached: no; Top Extension Distance: 0 m; Room Bounding: yes; Related to Mass: no; Pset_WallCommon - Reference: Basic Wall:Interior - Partition (92mm Stud); LoadBearing: no; ExtendToStructure: no; IsExternal: no; PSet_Revit_Structural - Structural Usage: 0; PSet_Revit_Type_Other - AccessibilityPerformance: AccessibilityPerformance; CodePerformance: CodePerformance; Color: Color; Constituents: Constituents; Features: Features; Finish: Finish; Grade: Grade; Material: Material; ModelReference: ModelReference; NominalHeight: NominalHeight; NominalLength: NominalLength; NominalWidth: NominalWidth; ProductionYear: ProductionYear; Reference: Reference; Shape: Shape; Size: Size; SustainabilityPerformance: SustainabilityPerformance; WarrantyDescription: WarrantyDescription; WarrantyDurationLabor: WarrantyDurationLabor; WarrantyDurationParts: WarrantyDurationParts; WarrantyGuarantorLabor: WarrantyGuarantorLabor; WarrantyGuarantorParts: WarrantyGuarantorParts; ExpectedLife: ExpectedLife; ReplacementCost: ReplacementCost; AssetAccountingType: FIXED; Classification Code: 23-25 40 11 11 11; Classification Description: Metal-Framed Gypsum Board Fixed Partitions; ModelLabel: ModelLabel; PSet_Revit_Type_Construction - Wrapping at Inserts: 0; Wrapping at Ends: 2; Width: 0.124 m; Function: 0; PSet_Revit_Type_Graphics - Coarse Scale Fill Color: 0; PSet_Revit_Type_Identity Data - Manufacturer: Manufacturer
Basic Wall:Interior - Partition (92mm Stud):287482:2 | Second Floor | PSet_Revit_Dimensions - Length: 1.0798 m; Area: 2.23771 m2; Volume: 0.277476 m3; PSet_Revit_Phasing - Phase Created: New Construction; PSet_Revit_Other - InstallationDate: InstallationDate; SerialNumber: SerialNumber; WarrantyStartDate: WarrantyStartDate; BarCode: BarCode; AssetIdentifier: AssetIdentifier; TagNumber: TagNumber; PSet_Revit_Constraints - Location Line: 2; Base Constraint: Second Floor; Base Offset: 0 m; Base is Attached: no; Base Extension Distance: 0 m; Top Constraint: Up to level: Second Floor; Unconnected Height: 3 m; Top Offset: 3 m; Top is Attached: no; Top Extension Distance: 0 m; Room Bounding: yes; Related to Mass: no; Pset_WallCommon - Reference: Basic Wall:Interior - Partition (92mm Stud); LoadBearing: no; ExtendToStructure: no; IsExternal: no; PSet_Revit_Structural - Structural Usage: 0; PSet_Revit_Type_Other - AccessibilityPerformance: AccessibilityPerformance; CodePerformance: CodePerformance; Color: Color; Constituents: Constituents; Features: Features; Finish: Finish; Grade: Grade; Material: Material; ModelReference: ModelReference; NominalHeight: NominalHeight; NominalLength: NominalLength; NominalWidth: NominalWidth; ProductionYear: ProductionYear; Reference: Reference; Shape: Shape; Size: Size; SustainabilityPerformance: SustainabilityPerformance; WarrantyDescription: WarrantyDescription; WarrantyDurationLabor: WarrantyDurationLabor; WarrantyDurationParts: WarrantyDurationParts; WarrantyGuarantorLabor: WarrantyGuarantorLabor; WarrantyGuarantorParts: WarrantyGuarantorParts; ExpectedLife: ExpectedLife; ReplacementCost: ReplacementCost; AssetAccountingType: FIXED; Classification Code: 23-25 40 11 11 11; Classification Description: Metal-Framed Gypsum Board Fixed Partitions; ModelLabel: ModelLabel; PSet_Revit_Type_Construction - Wrapping at Inserts: 0; Wrapping at Ends: 2; Width: 0.124 m; Function: 0; PSet_Revit_Type_Graphics - Coarse Scale Fill Color: 0; PSet_Revit_Type_Identity Data - Manufacturer: Manufacturer
 | Second Floor | PSet_Revit_Dimensions - Length: 1.07919 m; Area: 1.18262 m2; Volume: 0.31576 m3; PSet_Revit_Phasing - Phase Created: New Construction; PSet_Revit_Other - InstallationDate: InstallationDate; SerialNumber: SerialNumber; WarrantyStartDate: WarrantyStartDate; BarCode: BarCode; AssetIdentifier: AssetIdentifier; TagNumber: TagNumber; PSet_Revit_Constraints - Location Line: 0; Base Constraint: Second Floor; Base Offset: 3.4865 m; Base is Attached: no; Base Extension Distance: 0 m; Top Constraint: Up to level: Roof - Main; Unconnected Height: 2.5435 m; Top Offset: 1.35 m; Top is Attached: no; Top Extension Distance: 0 m; Room Bounding: yes; Related to Mass: no; Pset_WallCommon - Reference: Basic Wall:Exterior - Insul Panel on Mtl. Stud; LoadBearing: no; ExtendToStructure: no; IsExternal: yes; PSet_Revit_Structural - Structural Usage: 0; PSet_Revit_Type_Other - AccessibilityPerformance: AccessibilityPerformance; CodePerformance: CodePerformance; Color: Color; Constituents: Constituents; Features: Features; Finish: Finish; Grade: Grade; Material: Material; ModelReference: ModelReference; NominalHeight: NominalHeight; NominalLength: NominalLength; NominalWidth: NominalWidth; ProductionYear: ProductionYear; Reference: Reference; Shape: Shape; Size: Size; SustainabilityPerformance: SustainabilityPerformance; WarrantyDescription: WarrantyDescription; WarrantyDurationLabor: WarrantyDurationLabor; WarrantyDurationParts: WarrantyDurationParts; WarrantyGuarantorLabor: WarrantyGuarantorLabor; WarrantyGuarantorParts: WarrantyGuarantorParts; ExpectedLife: ExpectedLife; ReplacementCost: ReplacementCost; AssetAccountingType: FIXED; Classification Code: 23-25 30 24 21; Classification Description: Metal Framed Structural Walls; ModelLabel: ModelLabel; PSet_Revit_Type_Construction - Wrapping at Inserts: 0; Wrapping at Ends: 1; Width: 0.267 m; Function: 1; PSet_Revit_Type_Graphics - Coarse Scale Fill Color: 0; PSet_Revit_Type_Identity Data - Manufacturer: Manufacturer
Basic Wall:Interior - Partition (92mm Stud):198188:2 | Second Floor | PSet_Revit_Dimensions - Length: 3.37317 m; Area: 13.87 m2; Volume: 1.71988 m3; PSet_Revit_Phasing - Phase Created: New Construction; PSet_Revit_Other - InstallationDate: InstallationDate; SerialNumber: SerialNumber; WarrantyStartDate: WarrantyStartDate; BarCode: BarCode; AssetIdentifier: AssetIdentifier; TagNumber: TagNumber; PSet_Revit_Constraints - Location Line: 2; Base Constraint: Second Floor; Base Offset: 0 m; Base is Attached: no; Base Extension Distance: 0 m; Top Constraint: Up to level: Roof - Main; Unconnected Height: 4.578 m; Top Offset: -0.102 m; Top is Attached: no; Top Extension Distance: 0 m; Room Bounding: yes; Related to Mass: no; Pset_WallCommon - Reference: Basic Wall:Interior - Partition (92mm Stud); LoadBearing: no; ExtendToStructure: no; IsExternal: no; PSet_Revit_Structural - Structural Usage: 0; PSet_Revit_Type_Other - AccessibilityPerformance: AccessibilityPerformance; CodePerformance: CodePerformance; Color: Color; Constituents: Constituents; Features: Features; Finish: Finish; Grade: Grade; Material: Material; ModelReference: ModelReference; NominalHeight: NominalHeight; NominalLength: NominalLength; NominalWidth: NominalWidth; ProductionYear: ProductionYear; Reference: Reference; Shape: Shape; Size: Size; SustainabilityPerformance: SustainabilityPerformance; WarrantyDescription: WarrantyDescription; WarrantyDurationLabor: WarrantyDurationLabor; WarrantyDurationParts: WarrantyDurationParts; WarrantyGuarantorLabor: WarrantyGuarantorLabor; WarrantyGuarantorParts: WarrantyGuarantorParts; ExpectedLife: ExpectedLife; ReplacementCost: ReplacementCost; AssetAccountingType: FIXED; Classification Code: 23-25 40 11 11 11; Classification Description: Metal-Framed Gypsum Board Fixed Partitions; ModelLabel: ModelLabel; PSet_Revit_Type_Construction - Wrapping at Inserts: 0; Wrapping at Ends: 2; Width: 0.124 m; Function: 0; PSet_Revit_Type_Graphics - Coarse Scale Fill Color: 0; PSet_Revit_Type_Identity Data - Manufacturer: Manufacturer
Basic Wall:Interior - Rated 1-HR (92mm Stud):182976:2 | First Floor | PSet_Revit_Dimensions - Length: 2.3692 m; Area: 8.63426 m2; Volume: 1.07065 m3; PSet_Revit_Phasing - Phase Created: New Construction; PSet_Revit_Other - InstallationDate: InstallationDate; SerialNumber: SerialNumber; WarrantyStartDate: WarrantyStartDate; BarCode: BarCode; AssetIdentifier: AssetIdentifier; TagNumber: TagNumber; PSet_Revit_Constraints - Location Line: 2; Base Constraint: First Floor; Base Offset: 0 m; Base is Attached: no; Base Extension Distance: 0 m; Top Constraint: Up to level: Second Floor; Unconnected Height: 4.468 m; Top Offset: -0.102 m; Top is Attached: no; Top Extension Distance: 0 m; Room Bounding: yes; Related to Mass: no; Pset_WallCommon - Reference: Basic Wall:Interior - Rated 1-HR (92mm Stud); LoadBearing: no; ExtendToStructure: no; IsExternal: no; FireRating: 1 HR; PSet_Revit_Structural - Structural Usage: 0; PSet_Revit_Type_Other - AccessibilityPerformance: AccessibilityPerformance; CodePerformance: CodePerformance; Color: Color; Constituents: Constituents; Features: Features; Finish: Finish; Grade: Grade; Material: Material; ModelReference: ModelReference; NominalHeight: NominalHeight; NominalLength: NominalLength; NominalWidth: NominalWidth; ProductionYear: ProductionYear; Reference: Reference; Shape: Shape; Size: Size; SustainabilityPerformance: SustainabilityPerformance; WarrantyDescription: WarrantyDescription; WarrantyDurationLabor: WarrantyDurationLabor; WarrantyDurationParts: WarrantyDurationParts; WarrantyGuarantorLabor: WarrantyGuarantorLabor; WarrantyGuarantorParts: WarrantyGuarantorParts; ExpectedLife: ExpectedLife; ReplacementCost: ReplacementCost; AssetAccountingType: FIXED; Classification Code: 23-25 40 11 11 11; Classification Description: Metal-Framed Gypsum Board Fixed Partitions; ModelLabel: ModelLabel; PSet_Revit_Type_Construction - Wrapping at Inserts: 0; Wrapping at Ends: 0; Width: 0.124 m; Function: 0; PSet_Revit_Type_Graphics - Coarse Scale Fill Color: 8421504; Coarse Scale Fill Pattern: Solid fill; PSet_Revit_Type_Identity Data - Manufacturer: Manufacturer; Fire Rating: 1 HR
 | Second Floor | PSet_Revit_Dimensions - Length: 2.6485 m; Area: 11.7975 m2; Volume: 1.94584 m3; PSet_Revit_Phasing - Phase Created: New Construction; PSet_Revit_Other - InstallationDate: InstallationDate; SerialNumber: SerialNumber; WarrantyStartDate: WarrantyStartDate; BarCode: BarCode; AssetIdentifier: AssetIdentifier; TagNumber: TagNumber; PSet_Revit_Constraints - Location Line: 0; Base Constraint: Second Floor; Base Offset: 0 m; Base is Attached: no; Base Extension Distance: 0 m; Top Constraint: Up to level: Roof - Main; Unconnected Height: 4.578 m; Top Offset: -0.102 m; Top is Attached: no; Top Extension Distance: 0 m; Room Bounding: yes; Related to Mass: no; Pset_WallCommon - Reference: Basic Wall:Interior - Furring (152 mm Stud); LoadBearing: no; ExtendToStructure: no; IsExternal: no; PSet_Revit_Structural - Structural Usage: 0; PSet_Revit_Type_Other - AccessibilityPerformance: AccessibilityPerformance; CodePerformance: CodePerformance; Color: Color; Constituents: Constituents; Features: Features; Finish: Finish; Grade: Grade; Material: Material; ModelReference: ModelReference; NominalHeight: NominalHeight; NominalLength: NominalLength; NominalWidth: NominalWidth; ProductionYear: ProductionYear; Reference: Reference; Shape: Shape; Size: Size; SustainabilityPerformance: SustainabilityPerformance; WarrantyDescription: WarrantyDescription; WarrantyDurationLabor: WarrantyDurationLabor; WarrantyDurationParts: WarrantyDurationParts; WarrantyGuarantorLabor: WarrantyGuarantorLabor; WarrantyGuarantorParts: WarrantyGuarantorParts; ExpectedLife: ExpectedLife; ReplacementCost: ReplacementCost; AssetAccountingType: FIXED; Classification Code: 23-25 40 11 11 11; Classification Description: Metal-Framed Gypsum Board Fixed Partitions; ModelLabel: ModelLabel; PSet_Revit_Type_Construction - Wrapping at Inserts: 0; Wrapping at Ends: 0; Width: 0.168 m; Function: 0; PSet_Revit_Type_Graphics - Coarse Scale Fill Color: 0; PSet_Revit_Type_Identity Data - Manufacturer: Manufacturer
Basic Wall:Interior - Partition (92mm Stud):235927:6 | Second Floor | PSet_Revit_Dimensions - Length: 32.32 m; Area: 127.04 m2; Volume: 15.7529 m3; PSet_Revit_Phasing - Phase Created: New Construction; PSet_Revit_Other - InstallationDate: InstallationDate; SerialNumber: SerialNumber; WarrantyStartDate: WarrantyStartDate; BarCode: BarCode; AssetIdentifier: AssetIdentifier; TagNumber: TagNumber; PSet_Revit_Constraints - Location Line: 2; Base Constraint: Second Floor; Base Offset: 0 m; Base is Attached: no; Base Extension Distance: 0 m; Top Constraint: Up to level: Roof - Main; Unconnected Height: 4.578 m; Top Offset: -0.102 m; Top is Attached: no; Top Extension Distance: 0 m; Room Bounding: yes; Related to Mass: no; Pset_WallCommon - Reference: Basic Wall:Interior - Partition (92mm Stud); LoadBearing: no; ExtendToStructure: no; IsExternal: no; PSet_Revit_Structural - Structural Usage: 0; PSet_Revit_Type_Other - AccessibilityPerformance: AccessibilityPerformance; CodePerformance: CodePerformance; Color: Color; Constituents: Constituents; Features: Features; Finish: Finish; Grade: Grade; Material: Material; ModelReference: ModelReference; NominalHeight: NominalHeight; NominalLength: NominalLength; NominalWidth: NominalWidth; ProductionYear: ProductionYear; Reference: Reference; Shape: Shape; Size: Size; SustainabilityPerformance: SustainabilityPerformance; WarrantyDescription: WarrantyDescription; WarrantyDurationLabor: WarrantyDurationLabor; WarrantyDurationParts: WarrantyDurationParts; WarrantyGuarantorLabor: WarrantyGuarantorLabor; WarrantyGuarantorParts: WarrantyGuarantorParts; ExpectedLife: ExpectedLife; ReplacementCost: ReplacementCost; AssetAccountingType: FIXED; Classification Code: 23-25 40 11 11 11; Classification Description: Metal-Framed Gypsum Board Fixed Partitions; ModelLabel: ModelLabel; PSet_Revit_Type_Construction - Wrapping at Inserts: 0; Wrapping at Ends: 2; Width: 0.124 m; Function: 0; PSet_Revit_Type_Graphics - Coarse Scale Fill Color: 0; PSet_Revit_Type_Identity Data - Manufacturer: Manufacturer
Basic Wall:Exterior - Insul Panel on Mtl. Stud:378843:2 | Second Floor | PSet_Revit_Dimensions - Length: 9.10423 m; Area: 16.4162 m2; Volume: 4.38313 m3; PSet_Revit_Phasing - Phase Created: New Construction; PSet_Revit_Other - InstallationDate: InstallationDate; SerialNumber: SerialNumber; WarrantyStartDate: WarrantyStartDate; BarCode: BarCode; AssetIdentifier: AssetIdentifier; TagNumber: TagNumber; PSet_Revit_Constraints - Location Line: 2; Base Constraint: Second Floor; Base Offset: 2.1915 m; Base is Attached: no; Base Extension Distance: 0 m; Top Constraint: Up to level: Roof - Main; Unconnected Height: 1.697 m; Top Offset: -0.7915 m; Top is Attached: no; Top Extension Distance: 0 m; Room Bounding: yes; Related to Mass: no; Pset_WallCommon - Reference: Basic Wall:Exterior - Insul Panel on Mtl. Stud; LoadBearing: no; ExtendToStructure: no; IsExternal: yes; PSet_Revit_Structural - Structural Usage: 0; PSet_Revit_Type_Other - AccessibilityPerformance: AccessibilityPerformance; CodePerformance: CodePerformance; Color: Color; Constituents: Constituents; Features: Features; Finish: Finish; Grade: Grade; Material: Material; ModelReference: ModelReference; NominalHeight: NominalHeight; NominalLength: NominalLength; NominalWidth: NominalWidth; ProductionYear: ProductionYear; Reference: Reference; Shape: Shape; Size: Size; SustainabilityPerformance: SustainabilityPerformance; WarrantyDescription: WarrantyDescription; WarrantyDurationLabor: WarrantyDurationLabor; WarrantyDurationParts: WarrantyDurationParts; WarrantyGuarantorLabor: WarrantyGuarantorLabor; WarrantyGuarantorParts: WarrantyGuarantorParts; ExpectedLife: ExpectedLife; ReplacementCost: ReplacementCost; AssetAccountingType: FIXED; Classification Code: 23-25 30 24 21; Classification Description: Metal Framed Structural Walls; ModelLabel: ModelLabel; PSet_Revit_Type_Construction - Wrapping at Inserts: 0; Wrapping at Ends: 1; Width: 0.267 m; Function: 1; PSet_Revit_Type_Graphics - Coarse Scale Fill Color: 0; PSet_Revit_Type_Identity Data - Manufacturer: Manufacturer
 | Second Floor | PSet_Revit_Dimensions - Length: 1.08869 m; Area: 1.35432 m2; Volume: 0.361602 m3; PSet_Revit_Phasing - Phase Created: New Construction; PSet_Revit_Other - InstallationDate: InstallationDate; SerialNumber: SerialNumber; WarrantyStartDate: WarrantyStartDate; BarCode: BarCode; AssetIdentifier: AssetIdentifier; TagNumber: TagNumber; PSet_Revit_Constraints - Location Line: 0; Base Constraint: Second Floor; Base Offset: 3.4865 m; Base is Attached: no; Base Extension Distance: 0 m; Top Constraint: Up to level: Roof - Main; Unconnected Height: 2.5435 m; Top Offset: 1.35 m; Top is Attached: no; Top Extension Distance: 0 m; Room Bounding: yes; Related to Mass: no; Pset_WallCommon - Reference: Basic Wall:Exterior - Insul Panel on Mtl. Stud; LoadBearing: no; ExtendToStructure: no; IsExternal: yes; PSet_Revit_Structural - Structural Usage: 0; PSet_Revit_Type_Other - AccessibilityPerformance: AccessibilityPerformance; CodePerformance: CodePerformance; Color: Color; Constituents: Constituents; Features: Features; Finish: Finish; Grade: Grade; Material: Material; ModelReference: ModelReference; NominalHeight: NominalHeight; NominalLength: NominalLength; NominalWidth: NominalWidth; ProductionYear: ProductionYear; Reference: Reference; Shape: Shape; Size: Size; SustainabilityPerformance: SustainabilityPerformance; WarrantyDescription: WarrantyDescription; WarrantyDurationLabor: WarrantyDurationLabor; WarrantyDurationParts: WarrantyDurationParts; WarrantyGuarantorLabor: WarrantyGuarantorLabor; WarrantyGuarantorParts: WarrantyGuarantorParts; ExpectedLife: ExpectedLife; ReplacementCost: ReplacementCost; AssetAccountingType: FIXED; Classification Code: 23-25 30 24 21; Classification Description: Metal Framed Structural Walls; ModelLabel: ModelLabel; PSet_Revit_Type_Construction - Wrapping at Inserts: 0; Wrapping at Ends: 1; Width: 0.267 m; Function: 1; PSet_Revit_Type_Graphics - Coarse Scale Fill Color: 0; PSet_Revit_Type_Identity Data - Manufacturer: Manufacturer
Basic Wall:Interior - Rated 1-HR (92mm Stud):202564:2 | Second Floor | PSet_Revit_Dimensions - Length: 2.3592 m; Area: 8.28142 m2; Volume: 1.0269 m3; PSet_Revit_Phasing - Phase Created: New Construction; PSet_Revit_Other - InstallationDate: InstallationDate; SerialNumber: SerialNumber; WarrantyStartDate: WarrantyStartDate; BarCode: BarCode; AssetIdentifier: AssetIdentifier; TagNumber: TagNumber; PSet_Revit_Constraints - Location Line: 2; Base Constraint: Second Floor; Base Offset: 0 m; Base is Attached: no; Base Extension Distance: 0 m; Top Constraint: Up to level: Roof - Main; Unconnected Height: 4.578 m; Top Offset: -0.102 m; Top is Attached: no; Top Extension Distance: 0 m; Room Bounding: yes; Related to Mass: no; Pset_WallCommon - Reference: Basic Wall:Interior - Rated 1-HR (92mm Stud); LoadBearing: no; ExtendToStructure: no; IsExternal: no; FireRating: 1 HR; PSet_Revit_Structural - Structural Usage: 0; PSet_Revit_Type_Other - AccessibilityPerformance: AccessibilityPerformance; CodePerformance: CodePerformance; Color: Color; Constituents: Constituents; Features: Features; Finish: Finish; Grade: Grade; Material: Material; ModelReference: ModelReference; NominalHeight: NominalHeight; NominalLength: NominalLength; NominalWidth: NominalWidth; ProductionYear: ProductionYear; Reference: Reference; Shape: Shape; Size: Size; SustainabilityPerformance: SustainabilityPerformance; WarrantyDescription: WarrantyDescription; WarrantyDurationLabor: WarrantyDurationLabor; WarrantyDurationParts: WarrantyDurationParts; WarrantyGuarantorLabor: WarrantyGuarantorLabor; WarrantyGuarantorParts: WarrantyGuarantorParts; ExpectedLife: ExpectedLife; ReplacementCost: ReplacementCost; AssetAccountingType: FIXED; Classification Code: 23-25 40 11 11 11; Classification Description: Metal-Framed Gypsum Board Fixed Partitions; ModelLabel: ModelLabel; PSet_Revit_Type_Construction - Wrapping at Inserts: 0; Wrapping at Ends: 0; Width: 0.124 m; Function: 0; PSet_Revit_Type_Graphics - Coarse Scale Fill Color: 8421504; Coarse Scale Fill Pattern: Solid fill; PSet_Revit_Type_Identity Data - Manufacturer: Manufacturer; Fire Rating: 1 HR
Basic Wall:Interior - Partition (92mm Stud):235927:2 | Second Floor | PSet_Revit_Dimensions - Length: 32.32 m; Area: 127.04 m2; Volume: 15.7529 m3; PSet_Revit_Phasing - Phase Created: New Construction; PSet_Revit_Other - InstallationDate: InstallationDate; SerialNumber: SerialNumber; WarrantyStartDate: WarrantyStartDate; BarCode: BarCode; AssetIdentifier: AssetIdentifier; TagNumber: TagNumber; PSet_Revit_Constraints - Location Line: 2; Base Constraint: Second Floor; Base Offset: 0 m; Base is Attached: no; Base Extension Distance: 0 m; Top Constraint: Up to level: Roof - Main; Unconnected Height: 4.578 m; Top Offset: -0.102 m; Top is Attached: no; Top Extension Distance: 0 m; Room Bounding: yes; Related to Mass: no; Pset_WallCommon - Reference: Basic Wall:Interior - Partition (92mm Stud); LoadBearing: no; ExtendToStructure: no; IsExternal: no; PSet_Revit_Structural - Structural Usage: 0; PSet_Revit_Type_Other - AccessibilityPerformance: AccessibilityPerformance; CodePerformance: CodePerformance; Color: Color; Constituents: Constituents; Features: Features; Finish: Finish; Grade: Grade; Material: Material; ModelReference: ModelReference; NominalHeight: NominalHeight; NominalLength: NominalLength; NominalWidth: NominalWidth; ProductionYear: ProductionYear; Reference: Reference; Shape: Shape; Size: Size; SustainabilityPerformance: SustainabilityPerformance; WarrantyDescription: WarrantyDescription; WarrantyDurationLabor: WarrantyDurationLabor; WarrantyDurationParts: WarrantyDurationParts; WarrantyGuarantorLabor: WarrantyGuarantorLabor; WarrantyGuarantorParts: WarrantyGuarantorParts; ExpectedLife: ExpectedLife; ReplacementCost: ReplacementCost; AssetAccountingType: FIXED; Classification Code: 23-25 40 11 11 11; Classification Description: Metal-Framed Gypsum Board Fixed Partitions; ModelLabel: ModelLabel; PSet_Revit_Type_Construction - Wrapping at Inserts: 0; Wrapping at Ends: 2; Width: 0.124 m; Function: 0; PSet_Revit_Type_Graphics - Coarse Scale Fill Color: 0; PSet_Revit_Type_Identity Data - Manufacturer: Manufacturer
Basic Wall:Exterior - Insul Panel on Mtl. Stud:144524:2 | Second Floor | PSet_Revit_Dimensions - Length: 16.7065 m; Area: 75.4877 m2; Volume: 20.1552 m3; PSet_Revit_Phasing - Phase Created: New Construction; PSet_Revit_Other - InstallationDate: InstallationDate; SerialNumber: SerialNumber; WarrantyStartDate: WarrantyStartDate; BarCode: BarCode; AssetIdentifier: AssetIdentifier; TagNumber: TagNumber; PSet_Revit_Constraints - Location Line: 2; Base Constraint: Second Floor; Base Offset: 0 m; Base is Attached: no; Base Extension Distance: 0 m; Top Constraint: Up to level: Roof - Main; Unconnected Height: 5.137 m; Top Offset: 0.457 m; Top is Attached: no; Top Extension Distance: 0 m; Room Bounding: yes; Related to Mass: no; Pset_WallCommon - Reference: Basic Wall:Exterior - Insul Panel on Mtl. Stud; LoadBearing: no; ExtendToStructure: no; IsExternal: yes; PSet_Revit_Structural - Structural Usage: 0; PSet_Revit_Type_Other - AccessibilityPerformance: AccessibilityPerformance; CodePerformance: CodePerformance; Color: Color; Constituents: Constituents; Features: Features; Finish: Finish; Grade: Grade; Material: Material; ModelReference: ModelReference; NominalHeight: NominalHeight; NominalLength: NominalLength; NominalWidth: NominalWidth; ProductionYear: ProductionYear; Reference: Reference; Shape: Shape; Size: Size; SustainabilityPerformance: SustainabilityPerformance; WarrantyDescription: WarrantyDescription; WarrantyDurationLabor: WarrantyDurationLabor; WarrantyDurationParts: WarrantyDurationParts; WarrantyGuarantorLabor: WarrantyGuarantorLabor; WarrantyGuarantorParts: WarrantyGuarantorParts; ExpectedLife: ExpectedLife; ReplacementCost: ReplacementCost; AssetAccountingType: FIXED; Classification Code: 23-25 30 24 21; Classification Description: Metal Framed Structural Walls; ModelLabel: ModelLabel; PSet_Revit_Type_Construction - Wrapping at Inserts: 0; Wrapping at Ends: 1; Width: 0.267 m; Function: 1; PSet_Revit_Type_Graphics - Coarse Scale Fill Color: 0; PSet_Revit_Type_Identity Data - Manufacturer: Manufacturer
 | First Floor | PSet_Revit_Dimensions - Length: 2.714 m; Area: 10.2718 m2; Volume: 1.23757 m3; PSet_Revit_Phasing - Phase Created: New Construction; PSet_Revit_Other - InstallationDate: InstallationDate; SerialNumber: SerialNumber; WarrantyStartDate: WarrantyStartDate; BarCode: BarCode; AssetIdentifier: AssetIdentifier; TagNumber: TagNumber; PSet_Revit_Constraints - Location Line: 2; Base Constraint: First Floor; Base Offset: 0 m; Base is Attached: no; Base Extension Distance: 0 m; Top Constraint: Up to level: Second Floor; Unconnected Height: 4.468 m; Top Offset: -0.102 m; Top is Attached: no; Top Extension Distance: 0 m; Room Bounding: yes; Related to Mass: no; Pset_WallCommon - Reference: Basic Wall:Interior - Partition (92mm Stud); LoadBearing: no; ExtendToStructure: no; IsExternal: no; PSet_Revit_Structural - Structural Usage: 0; PSet_Revit_Type_Other - AccessibilityPerformance: AccessibilityPerformance; CodePerformance: CodePerformance; Color: Color; Constituents: Constituents; Features: Features; Finish: Finish; Grade: Grade; Material: Material; ModelReference: ModelReference; NominalHeight: NominalHeight; NominalLength: NominalLength; NominalWidth: NominalWidth; ProductionYear: ProductionYear; Reference: Reference; Shape: Shape; Size: Size; SustainabilityPerformance: SustainabilityPerformance; WarrantyDescription: WarrantyDescription; WarrantyDurationLabor: WarrantyDurationLabor; WarrantyDurationParts: WarrantyDurationParts; WarrantyGuarantorLabor: WarrantyGuarantorLabor; WarrantyGuarantorParts: WarrantyGuarantorParts; ExpectedLife: ExpectedLife; ReplacementCost: ReplacementCost; AssetAccountingType: FIXED; Classification Code: 23-25 40 11 11 11; Classification Description: Metal-Framed Gypsum Board Fixed Partitions; ModelLabel: ModelLabel; PSet_Revit_Type_Construction - Wrapping at Inserts: 0; Wrapping at Ends: 2; Width: 0.124 m; Function: 0; PSet_Revit_Type_Graphics - Coarse Scale Fill Color: 0; PSet_Revit_Type_Identity Data - Manufacturer: Manufacturer
 | Second Floor | PSet_Revit_Dimensions - Length: 11.691 m; Area: 27.4777 m2; Volume: 3.40724 m3; PSet_Revit_Phasing - Phase Created: New Construction; PSet_Revit_Other - InstallationDate: InstallationDate; SerialNumber: SerialNumber; WarrantyStartDate: WarrantyStartDate; BarCode: BarCode; AssetIdentifier: AssetIdentifier; TagNumber: TagNumber; PSet_Revit_Constraints - Location Line: 2; Base Constraint: Second Floor; Base Offset: 0 m; Base is Attached: no; Base Extension Distance: 0 m; Top Constraint: Up to level: Roof - Main; Unconnected Height: 4.68 m; Top Offset: 0 m; Top is Attached: no; Top Extension Distance: 0 m; Room Bounding: yes; Related to Mass: no; Pset_WallCommon - Reference: Basic Wall:Interior - Partition (92mm Stud); LoadBearing: no; ExtendToStructure: no; IsExternal: no; PSet_Revit_Structural - Structural Usage: 0; PSet_Revit_Type_Other - AccessibilityPerformance: AccessibilityPerformance; CodePerformance: CodePerformance; Color: Color; Constituents: Constituents; Features: Features; Finish: Finish; Grade: Grade; Material: Material; ModelReference: ModelReference; NominalHeight: NominalHeight; NominalLength: NominalLength; NominalWidth: NominalWidth; ProductionYear: ProductionYear; Reference: Reference; Shape: Shape; Size: Size; SustainabilityPerformance: SustainabilityPerformance; WarrantyDescription: WarrantyDescription; WarrantyDurationLabor: WarrantyDurationLabor; WarrantyDurationParts: WarrantyDurationParts; WarrantyGuarantorLabor: WarrantyGuarantorLabor; WarrantyGuarantorParts: WarrantyGuarantorParts; ExpectedLife: ExpectedLife; ReplacementCost: ReplacementCost; AssetAccountingType: FIXED; Classification Code: 23-25 40 11 11 11; Classification Description: Metal-Framed Gypsum Board Fixed Partitions; ModelLabel: ModelLabel; PSet_Revit_Type_Construction - Wrapping at Inserts: 0; Wrapping at Ends: 2; Width: 0.124 m; Function: 0; PSet_Revit_Type_Graphics - Coarse Scale Fill Color: 0; PSet_Revit_Type_Identity Data - Manufacturer: Manufacturer
Basic Wall:Interior - Partition (92mm Stud):198335:2 | Second Floor | PSet_Revit_Dimensions - Length: 1.889 m; Area: 6.10074 m2; Volume: 0.756492 m3; PSet_Revit_Phasing - Phase Created: New Construction; PSet_Revit_Other - InstallationDate: InstallationDate; SerialNumber: SerialNumber; WarrantyStartDate: WarrantyStartDate; BarCode: BarCode; AssetIdentifier: AssetIdentifier; TagNumber: TagNumber; PSet_Revit_Constraints - Location Line: 2; Base Constraint: Second Floor; Base Offset: 0 m; Base is Attached: no; Base Extension Distance: 0 m; Top Constraint: Up to level: Roof - Main; Unconnected Height: 4.578 m; Top Offset: -0.102 m; Top is Attached: no; Top Extension Distance: 0 m; Room Bounding: yes; Related to Mass: no; Pset_WallCommon - Reference: Basic Wall:Interior - Partition (92mm Stud); LoadBearing: no; ExtendToStructure: no; IsExternal: no; PSet_Revit_Structural - Structural Usage: 0; PSet_Revit_Type_Other - AccessibilityPerformance: AccessibilityPerformance; CodePerformance: CodePerformance; Color: Color; Constituents: Constituents; Features: Features; Finish: Finish; Grade: Grade; Material: Material; ModelReference: ModelReference; NominalHeight: NominalHeight; NominalLength: NominalLength; NominalWidth: NominalWidth; ProductionYear: ProductionYear; Reference: Reference; Shape: Shape; Size: Size; SustainabilityPerformance: SustainabilityPerformance; WarrantyDescription: WarrantyDescription; WarrantyDurationLabor: WarrantyDurationLabor; WarrantyDurationParts: WarrantyDurationParts; WarrantyGuarantorLabor: WarrantyGuarantorLabor; WarrantyGuarantorParts: WarrantyGuarantorParts; ExpectedLife: ExpectedLife; ReplacementCost: ReplacementCost; AssetAccountingType: FIXED; Classification Code: 23-25 40 11 11 11; Classification Description: Metal-Framed Gypsum Board Fixed Partitions; ModelLabel: ModelLabel; PSet_Revit_Type_Construction - Wrapping at Inserts: 0; Wrapping at Ends: 2; Width: 0.124 m; Function: 0; PSet_Revit_Type_Graphics - Coarse Scale Fill Color: 0; PSet_Revit_Type_Identity Data - Manufacturer: Manufacturer
 | First Floor | PSet_Revit_Dimensions - Length: 2.745 m; Area: 11.5542 m2; Volume: 1.39659 m3; PSet_Revit_Phasing - Phase Created: New Construction; PSet_Revit_Other - InstallationDate: InstallationDate; SerialNumber: SerialNumber; WarrantyStartDate: WarrantyStartDate; BarCode: BarCode; AssetIdentifier: AssetIdentifier; TagNumber: TagNumber; PSet_Revit_Constraints - Location Line: 2; Base Constraint: First Floor; Base Offset: 0 m; Base is Attached: no; Base Extension Distance: 0 m; Top Constraint: Up to level: Second Floor; Unconnected Height: 4.468 m; Top Offset: -0.102 m; Top is Attached: no; Top Extension Distance: 0 m; Room Bounding: yes; Related to Mass: no; Pset_WallCommon - Reference: Basic Wall:Interior - Partition (92mm Stud); LoadBearing: no; ExtendToStructure: no; IsExternal: no; PSet_Revit_Structural - Structural Usage: 0; PSet_Revit_Type_Other - AccessibilityPerformance: AccessibilityPerformance; CodePerformance: CodePerformance; Color: Color; Constituents: Constituents; Features: Features; Finish: Finish; Grade: Grade; Material: Material; ModelReference: ModelReference; NominalHeight: NominalHeight; NominalLength: NominalLength; NominalWidth: NominalWidth; ProductionYear: ProductionYear; Reference: Reference; Shape: Shape; Size: Size; SustainabilityPerformance: SustainabilityPerformance; WarrantyDescription: WarrantyDescription; WarrantyDurationLabor: WarrantyDurationLabor; WarrantyDurationParts: WarrantyDurationParts; WarrantyGuarantorLabor: WarrantyGuarantorLabor; WarrantyGuarantorParts: WarrantyGuarantorParts; ExpectedLife: ExpectedLife; ReplacementCost: ReplacementCost; AssetAccountingType: FIXED; Classification Code: 23-25 40 11 11 11; Classification Description: Metal-Framed Gypsum Board Fixed Partitions; ModelLabel: ModelLabel; PSet_Revit_Type_Construction - Wrapping at Inserts: 0; Wrapping at Ends: 2; Width: 0.124 m; Function: 0; PSet_Revit_Type_Graphics - Coarse Scale Fill Color: 0; PSet_Revit_Type_Identity Data - Manufacturer: Manufacturer
Basic Wall:Interior - Partition (92mm Stud):204658:2 | Second Floor | PSet_Revit_Dimensions - Length: 3.5 m; Area: 14.6178 m2; Volume: 1.8126 m3; PSet_Revit_Phasing - Phase Created: New Construction; PSet_Revit_Other - InstallationDate: InstallationDate; SerialNumber: SerialNumber; WarrantyStartDate: WarrantyStartDate; BarCode: BarCode; AssetIdentifier: AssetIdentifier; TagNumber: TagNumber; PSet_Revit_Constraints - Location Line: 2; Base Constraint: Second Floor; Base Offset: 0 m; Base is Attached: no; Base Extension Distance: 0 m; Top Constraint: Up to level: Roof - Main; Unconnected Height: 4.578 m; Top Offset: -0.102 m; Top is Attached: no; Top Extension Distance: 0 m; Room Bounding: yes; Related to Mass: no; Pset_WallCommon - Reference: Basic Wall:Interior - Partition (92mm Stud); LoadBearing: no; ExtendToStructure: no; IsExternal: no; PSet_Revit_Structural - Structural Usage: 0; PSet_Revit_Type_Other - AccessibilityPerformance: AccessibilityPerformance; CodePerformance: CodePerformance; Color: Color; Constituents: Constituents; Features: Features; Finish: Finish; Grade: Grade; Material: Material; ModelReference: ModelReference; NominalHeight: NominalHeight; NominalLength: NominalLength; NominalWidth: NominalWidth; ProductionYear: ProductionYear; Reference: Reference; Shape: Shape; Size: Size; SustainabilityPerformance: SustainabilityPerformance; WarrantyDescription: WarrantyDescription; WarrantyDurationLabor: WarrantyDurationLabor; WarrantyDurationParts: WarrantyDurationParts; WarrantyGuarantorLabor: WarrantyGuarantorLabor; WarrantyGuarantorParts: WarrantyGuarantorParts; ExpectedLife: ExpectedLife; ReplacementCost: ReplacementCost; AssetAccountingType: FIXED; Classification Code: 23-25 40 11 11 11; Classification Description: Metal-Framed Gypsum Board Fixed Partitions; ModelLabel: ModelLabel; PSet_Revit_Type_Construction - Wrapping at Inserts: 0; Wrapping at Ends: 2; Width: 0.124 m; Function: 0; PSet_Revit_Type_Graphics - Coarse Scale Fill Color: 0; PSet_Revit_Type_Identity Data - Manufacturer: Manufacturer
 | First Floor | PSet_Revit_Dimensions - Length: 2.2195 m; Area: 7.09062 m2; Volume: 0.843098 m3; PSet_Revit_Phasing - Phase Created: New Construction; PSet_Revit_Other - InstallationDate: InstallationDate; SerialNumber: SerialNumber; WarrantyStartDate: WarrantyStartDate; BarCode: BarCode; AssetIdentifier: AssetIdentifier; TagNumber: TagNumber; PSet_Revit_Constraints - Location Line: 3; Base Constraint: First Floor; Base Offset: 0 m; Base is Attached: no; Base Extension Distance: 0 m; Top Constraint: Up to level: Second Floor; Unconnected Height: 4.468 m; Top Offset: -0.102 m; Top is Attached: no; Top Extension Distance: 0 m; Room Bounding: yes; Related to Mass: no; Pset_WallCommon - Reference: Basic Wall:Interior - Partition (92mm Stud); LoadBearing: no; ExtendToStructure: no; IsExternal: no; PSet_Revit_Structural - Structural Usage: 0; PSet_Revit_Type_Other - AccessibilityPerformance: AccessibilityPerformance; CodePerformance: CodePerformance; Color: Color; Constituents: Constituents; Features: Features; Finish: Finish; Grade: Grade; Material: Material; ModelReference: ModelReference; NominalHeight: NominalHeight; NominalLength: NominalLength; NominalWidth: NominalWidth; ProductionYear: ProductionYear; Reference: Reference; Shape: Shape; Size: Size; SustainabilityPerformance: SustainabilityPerformance; WarrantyDescription: WarrantyDescription; WarrantyDurationLabor: WarrantyDurationLabor; WarrantyDurationParts: WarrantyDurationParts; WarrantyGuarantorLabor: WarrantyGuarantorLabor; WarrantyGuarantorParts: WarrantyGuarantorParts; ExpectedLife: ExpectedLife; ReplacementCost: ReplacementCost; AssetAccountingType: FIXED; Classification Code: 23-25 40 11 11 11; Classification Description: Metal-Framed Gypsum Board Fixed Partitions; ModelLabel: ModelLabel; PSet_Revit_Type_Construction - Wrapping at Inserts: 0; Wrapping at Ends: 2; Width: 0.124 m; Function: 0; PSet_Revit_Type_Graphics - Coarse Scale Fill Color: 0; PSet_Revit_Type_Identity Data - Manufacturer: Manufacturer
Basic Wall:Exterior - Insul Panel on Mtl. Stud:381931:2 | Roof - Main | PSet_Revit_Dimensions - Length: 18.4025 m; Area: 31.9269 m2; Volume: 8.52447 m3; PSet_Revit_Phasing - Phase Created: New Construction; PSet_Revit_Other - InstallationDate: InstallationDate; SerialNumber: SerialNumber; WarrantyStartDate: WarrantyStartDate; BarCode: BarCode; AssetIdentifier: AssetIdentifier; TagNumber: TagNumber; PSet_Revit_Constraints - Location Line: 2; Base Constraint: Roof - Main; Base Offset: 0 m; Base is Attached: no; Base Extension Distance: 0 m; Top Constraint: Up to level: Roof - Main; Unconnected Height: 3.4 m; Top Offset: 3.4 m; Top is Attached: no; Top Extension Distance: 0 m; Room Bounding: yes; Related to Mass: no; Pset_WallCommon - Reference: Basic Wall:Exterior - Insul Panel on Mtl. Stud; LoadBearing: no; ExtendToStructure: no; IsExternal: yes; PSet_Revit_Structural - Structural Usage: 0; PSet_Revit_Type_Other - AccessibilityPerformance: AccessibilityPerformance; CodePerformance: CodePerformance; Color: Color; Constituents: Constituents; Features: Features; Finish: Finish; Grade: Grade; Material: Material; ModelReference: ModelReference; NominalHeight: NominalHeight; NominalLength: NominalLength; NominalWidth: NominalWidth; ProductionYear: ProductionYear; Reference: Reference; Shape: Shape; Size: Size; SustainabilityPerformance: SustainabilityPerformance; WarrantyDescription: WarrantyDescription; WarrantyDurationLabor: WarrantyDurationLabor; WarrantyDurationParts: WarrantyDurationParts; WarrantyGuarantorLabor: WarrantyGuarantorLabor; WarrantyGuarantorParts: WarrantyGuarantorParts; ExpectedLife: ExpectedLife; ReplacementCost: ReplacementCost; AssetAccountingType: FIXED; Classification Code: 23-25 30 24 21; Classification Description: Metal Framed Structural Walls; ModelLabel: ModelLabel; PSet_Revit_Type_Construction - Wrapping at Inserts: 0; Wrapping at Ends: 1; Width: 0.267 m; Function: 1; PSet_Revit_Type_Graphics - Coarse Scale Fill Color: 0; PSet_Revit_Type_Identity Data - Manufacturer: Manufacturer
Basic Wall:Interior - Partition (92mm Stud):235927:5 | Second Floor | PSet_Revit_Dimensions - Length: 32.32 m; Area: 127.04 m2; Volume: 15.7529 m3; PSet_Revit_Phasing - Phase Created: New Construction; PSet_Revit_Other - InstallationDate: InstallationDate; SerialNumber: SerialNumber; WarrantyStartDate: WarrantyStartDate; BarCode: BarCode; AssetIdentifier: AssetIdentifier; TagNumber: TagNumber; PSet_Revit_Constraints - Location Line: 2; Base Constraint: Second Floor; Base Offset: 0 m; Base is Attached: no; Base Extension Distance: 0 m; Top Constraint: Up to level: Roof - Main; Unconnected Height: 4.578 m; Top Offset: -0.102 m; Top is Attached: no; Top Extension Distance: 0 m; Room Bounding: yes; Related to Mass: no; Pset_WallCommon - Reference: Basic Wall:Interior - Partition (92mm Stud); LoadBearing: no; ExtendToStructure: no; IsExternal: no; PSet_Revit_Structural - Structural Usage: 0; PSet_Revit_Type_Other - AccessibilityPerformance: AccessibilityPerformance; CodePerformance: CodePerformance; Color: Color; Constituents: Constituents; Features: Features; Finish: Finish; Grade: Grade; Material: Material; ModelReference: ModelReference; NominalHeight: NominalHeight; NominalLength: NominalLength; NominalWidth: NominalWidth; ProductionYear: ProductionYear; Reference: Reference; Shape: Shape; Size: Size; SustainabilityPerformance: SustainabilityPerformance; WarrantyDescription: WarrantyDescription; WarrantyDurationLabor: WarrantyDurationLabor; WarrantyDurationParts: WarrantyDurationParts; WarrantyGuarantorLabor: WarrantyGuarantorLabor; WarrantyGuarantorParts: WarrantyGuarantorParts; ExpectedLife: ExpectedLife; ReplacementCost: ReplacementCost; AssetAccountingType: FIXED; Classification Code: 23-25 40 11 11 11; Classification Description: Metal-Framed Gypsum Board Fixed Partitions; ModelLabel: ModelLabel; PSet_Revit_Type_Construction - Wrapping at Inserts: 0; Wrapping at Ends: 2; Width: 0.124 m; Function: 0; PSet_Revit_Type_Graphics - Coarse Scale Fill Color: 0; PSet_Revit_Type_Identity Data - Manufacturer: Manufacturer
Basic Wall:Interior - Partition (92mm Stud):204720:2 | Second Floor | PSet_Revit_Dimensions - Length: 3.5 m; Area: 14.6086 m2; Volume: 1.81146 m3; PSet_Revit_Phasing - Phase Created: New Construction; PSet_Revit_Other - InstallationDate: InstallationDate; SerialNumber: SerialNumber; WarrantyStartDate: WarrantyStartDate; BarCode: BarCode; AssetIdentifier: AssetIdentifier; TagNumber: TagNumber; PSet_Revit_Constraints - Location Line: 2; Base Constraint: Second Floor; Base Offset: 0 m; Base is Attached: no; Base Extension Distance: 0 m; Top Constraint: Up to level: Roof - Main; Unconnected Height: 4.578 m; Top Offset: -0.102 m; Top is Attached: no; Top Extension Distance: 0 m; Room Bounding: yes; Related to Mass: no; Pset_WallCommon - Reference: Basic Wall:Interior - Partition (92mm Stud); LoadBearing: no; ExtendToStructure: no; IsExternal: no; PSet_Revit_Structural - Structural Usage: 0; PSet_Revit_Type_Other - AccessibilityPerformance: AccessibilityPerformance; CodePerformance: CodePerformance; Color: Color; Constituents: Constituents; Features: Features; Finish: Finish; Grade: Grade; Material: Material; ModelReference: ModelReference; NominalHeight: NominalHeight; NominalLength: NominalLength; NominalWidth: NominalWidth; ProductionYear: ProductionYear; Reference: Reference; Shape: Shape; Size: Size; SustainabilityPerformance: SustainabilityPerformance; WarrantyDescription: WarrantyDescription; WarrantyDurationLabor: WarrantyDurationLabor; WarrantyDurationParts: WarrantyDurationParts; WarrantyGuarantorLabor: WarrantyGuarantorLabor; WarrantyGuarantorParts: WarrantyGuarantorParts; ExpectedLife: ExpectedLife; ReplacementCost: ReplacementCost; AssetAccountingType: FIXED; Classification Code: 23-25 40 11 11 11; Classification Description: Metal-Framed Gypsum Board Fixed Partitions; ModelLabel: ModelLabel; PSet_Revit_Type_Construction - Wrapping at Inserts: 0; Wrapping at Ends: 2; Width: 0.124 m; Function: 0; PSet_Revit_Type_Graphics - Coarse Scale Fill Color: 0; PSet_Revit_Type_Identity Data - Manufacturer: Manufacturer
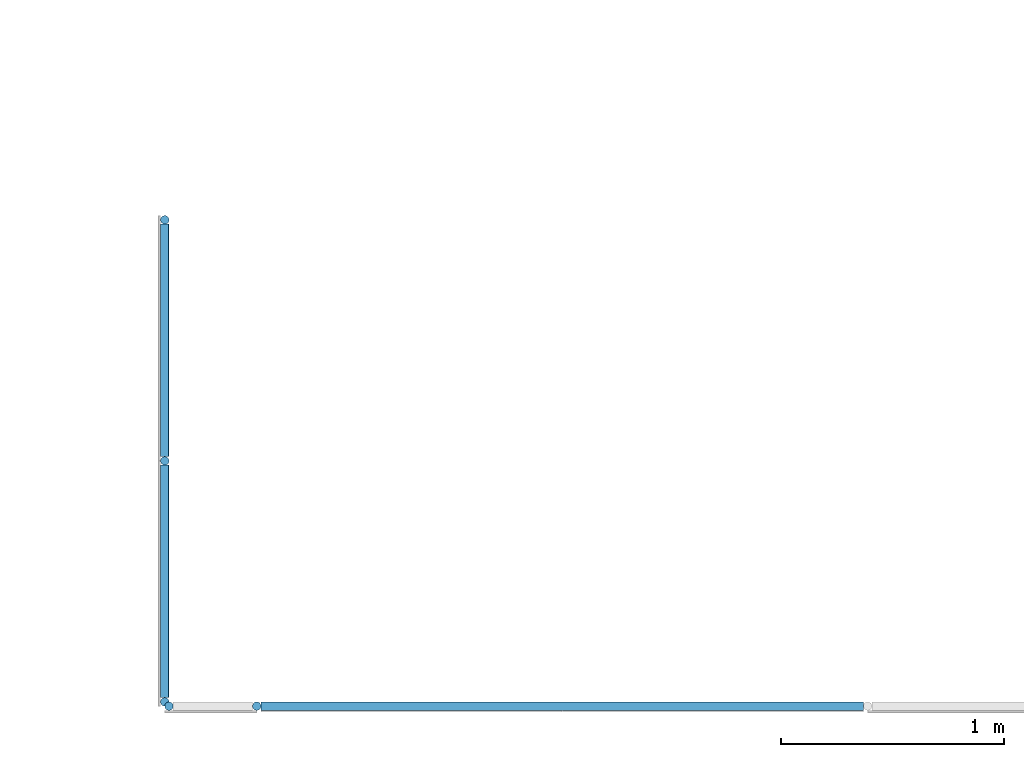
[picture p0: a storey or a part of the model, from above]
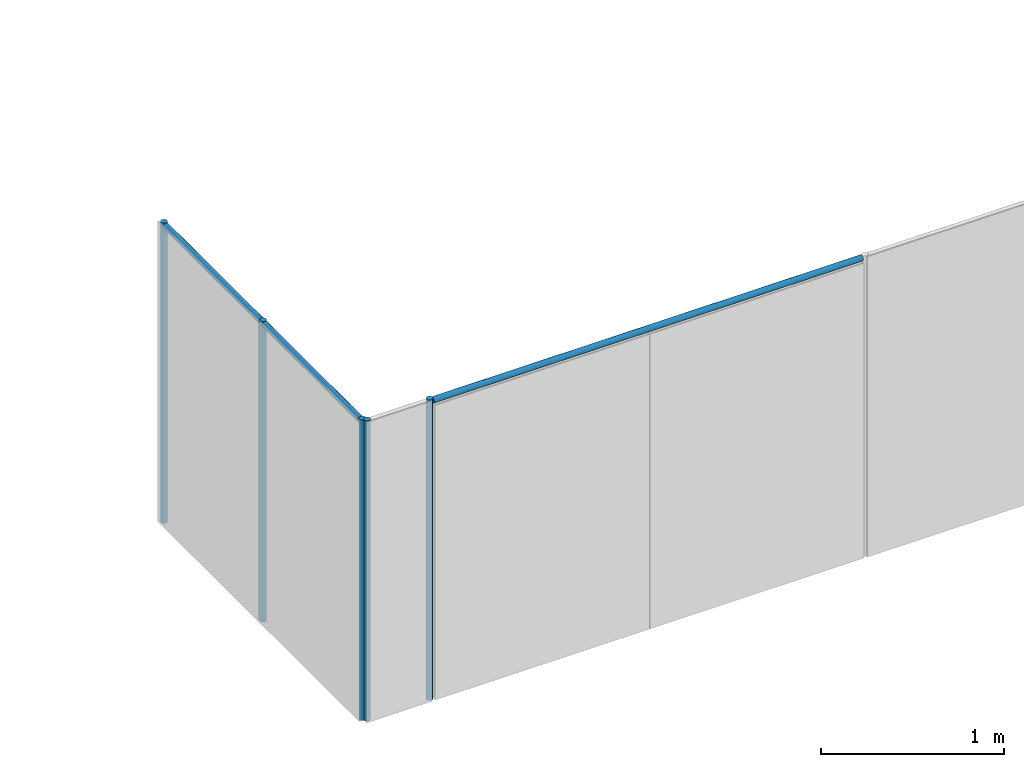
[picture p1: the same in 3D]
Properties of the parts of a building model (IFC2X3), part 7 of 11

# IfcOpeningElement: Opening (403)
Name | In
 | First Floor | PSet_Revit_Dimensions - Length: 2.736 m; Area: 11.6704 m2; Volume: 1.41099 m3; PSet_Revit_Phasing - Phase Created: New Construction; PSet_Revit_Other - InstallationDate: InstallationDate; SerialNumber: SerialNumber; WarrantyStartDate: WarrantyStartDate; BarCode: BarCode; AssetIdentifier: AssetIdentifier; TagNumber: TagNumber; PSet_Revit_Constraints - Location Line: 2; Base Constraint: First Floor; Base Offset: 0 m; Base is Attached: no; Base Extension Distance: 0 m; Top Constraint: Up to level: Second Floor; Unconnected Height: 4.468 m; Top Offset: -0.102 m; Top is Attached: no; Top Extension Distance: 0 m; Room Bounding: yes; Related to Mass: no; Pset_WallCommon - Reference: Basic Wall:Interior - Partition (92mm Stud); LoadBearing: no; ExtendToStructure: no; IsExternal: no; PSet_Revit_Structural - Structural Usage: 0; PSet_Revit_Type_Other - AccessibilityPerformance: AccessibilityPerformance; CodePerformance: CodePerformance; Color: Color; Constituents: Constituents; Features: Features; Finish: Finish; Grade: Grade; Material: Material; ModelReference: ModelReference; NominalHeight: NominalHeight; NominalLength: NominalLength; NominalWidth: NominalWidth; ProductionYear: ProductionYear; Reference: Reference; Shape: Shape; Size: Size; SustainabilityPerformance: SustainabilityPerformance; WarrantyDescription: WarrantyDescription; WarrantyDurationLabor: WarrantyDurationLabor; WarrantyDurationParts: WarrantyDurationParts; WarrantyGuarantorLabor: WarrantyGuarantorLabor; WarrantyGuarantorParts: WarrantyGuarantorParts; ExpectedLife: ExpectedLife; ReplacementCost: ReplacementCost; AssetAccountingType: FIXED; Classification Code: 23-25 40 11 11 11; Classification Description: Metal-Framed Gypsum Board Fixed Partitions; ModelLabel: ModelLabel; PSet_Revit_Type_Construction - Wrapping at Inserts: 0; Wrapping at Ends: 2; Width: 0.124 m; Function: 0; PSet_Revit_Type_Graphics - Coarse Scale Fill Color: 0; PSet_Revit_Type_Identity Data - Manufacturer: Manufacturer
M_Counter Top w Sink Hole:600mm Depth:600mm Depth:422054:1 | 1D02 | PSet_Revit_Dimensions - Length: 1.2 m; Sink Location: 0.6 m; Sink Location To Wall: 0.16973 m; Sink Opening Depth: 0.391258 m; Sink Opening Width: 0.587 m; PSet_Revit_Phasing - Phase Created: New Construction; PSet_Revit_Other - InstallationDate: InstallationDate; SerialNumber: SerialNumber; WarrantyStartDate: WarrantyStartDate; BarCode: BarCode; AssetIdentifier: AssetIdentifier; TagNumber: TagNumber; PSet_Revit_Type_Other - AccessibilityPerformance: AccessibilityPerformance; CodePerformance: CodePerformance; Color: Color; Constituents: Constituents; Features: Features; Finish: Finish; Grade: Grade; Material: Material; ModelReference: ModelReference; NominalHeight: NominalHeight; NominalLength: NominalLength; NominalWidth: NominalWidth; ProductionYear: ProductionYear; Reference: Reference; Shape: Shape; Size: Size; SustainabilityPerformance: SustainabilityPerformance; WarrantyDescription: WarrantyDescription; WarrantyDurationLabor: WarrantyDurationLabor; WarrantyDurationParts: WarrantyDurationParts; WarrantyGuarantorLabor: WarrantyGuarantorLabor; WarrantyGuarantorParts: WarrantyGuarantorParts; ExpectedLife: ExpectedLife; ReplacementCost: ReplacementCost; AssetAccountingType: FIXED; ModelLabel: ModelLabel; Area: Area; PSet_Revit_Type_Identity Data - Manufacturer: Manufacturer; OmniClass Number: 23.40.35.17.47.11; OmniClass Title: Kitchen Casework; PSet_Revit_Constraints - Level: First Floor; Host: Level : First Floor; Offset: 0 m; Moves With Nearby Elements: no; PSet_Revit_Type_Dimensions - Counter Thickness: 0.04 m; Depth: 0.625 m; Height: 0.9 m; PSet_Revit_Type_Construction - Construction Type: Construction Type; PSet_Revit_Type_Materials and Finishes - Finish: Finish
M_Counter Top w Sink Hole:600mm Depth:600mm Depth:330800:1 | 1E16 | PSet_Revit_Dimensions - Length: 1.21 m; Sink Location: 0.908082 m; Sink Location To Wall: 0.113 m; Sink Opening Depth: 0.403931 m; Sink Opening Width: 0.4826 m; PSet_Revit_Phasing - Phase Created: New Construction; PSet_Revit_Other - InstallationDate: InstallationDate; SerialNumber: SerialNumber; WarrantyStartDate: WarrantyStartDate; BarCode: BarCode; AssetIdentifier: AssetIdentifier; TagNumber: TagNumber; PSet_Revit_Type_Other - AccessibilityPerformance: AccessibilityPerformance; CodePerformance: CodePerformance; Color: Color; Constituents: Constituents; Features: Features; Finish: Finish; Grade: Grade; Material: Material; ModelReference: ModelReference; NominalHeight: NominalHeight; NominalLength: NominalLength; NominalWidth: NominalWidth; ProductionYear: ProductionYear; Reference: Reference; Shape: Shape; Size: Size; SustainabilityPerformance: SustainabilityPerformance; WarrantyDescription: WarrantyDescription; WarrantyDurationLabor: WarrantyDurationLabor; WarrantyDurationParts: WarrantyDurationParts; WarrantyGuarantorLabor: WarrantyGuarantorLabor; WarrantyGuarantorParts: WarrantyGuarantorParts; ExpectedLife: ExpectedLife; ReplacementCost: ReplacementCost; AssetAccountingType: FIXED; ModelLabel: ModelLabel; Area: Area; PSet_Revit_Type_Identity Data - Manufacturer: Manufacturer; OmniClass Number: 23.40.35.17.47.11; OmniClass Title: Kitchen Casework; PSet_Revit_Constraints - Level: First Floor; Host: Level : First Floor; Offset: 0 m; Moves With Nearby Elements: no; PSet_Revit_Type_Dimensions - Counter Thickness: 0.04 m; Depth: 0.625 m; Height: 0.9 m; PSet_Revit_Type_Construction - Construction Type: Construction Type; PSet_Revit_Type_Materials and Finishes - Finish: Finish
M_Counter Top w Sink Hole:600mm Depth:600mm Depth:330055:1 | 1E30 | PSet_Revit_Dimensions - Length: 1.27 m; Sink Location: 0.351918 m; Sink Location To Wall: 0.1 m; Sink Opening Depth: 0.378 m; Sink Opening Width: 0.4826 m; PSet_Revit_Phasing - Phase Created: New Construction; PSet_Revit_Other - InstallationDate: InstallationDate; SerialNumber: SerialNumber; WarrantyStartDate: WarrantyStartDate; BarCode: BarCode; AssetIdentifier: AssetIdentifier; TagNumber: TagNumber; PSet_Revit_Type_Other - AccessibilityPerformance: AccessibilityPerformance; CodePerformance: CodePerformance; Color: Color; Constituents: Constituents; Features: Features; Finish: Finish; Grade: Grade; Material: Material; ModelReference: ModelReference; NominalHeight: NominalHeight; NominalLength: NominalLength; NominalWidth: NominalWidth; ProductionYear: ProductionYear; Reference: Reference; Shape: Shape; Size: Size; SustainabilityPerformance: SustainabilityPerformance; WarrantyDescription: WarrantyDescription; WarrantyDurationLabor: WarrantyDurationLabor; WarrantyDurationParts: WarrantyDurationParts; WarrantyGuarantorLabor: WarrantyGuarantorLabor; WarrantyGuarantorParts: WarrantyGuarantorParts; ExpectedLife: ExpectedLife; ReplacementCost: ReplacementCost; AssetAccountingType: FIXED; ModelLabel: ModelLabel; Area: Area; PSet_Revit_Type_Identity Data - Manufacturer: Manufacturer; OmniClass Number: 23.40.35.17.47.11; OmniClass Title: Kitchen Casework; PSet_Revit_Constraints - Level: First Floor; Host: Level : First Floor; Offset: 0 m; Moves With Nearby Elements: no; PSet_Revit_Type_Dimensions - Counter Thickness: 0.04 m; Depth: 0.625 m; Height: 0.9 m; PSet_Revit_Type_Construction - Construction Type: Construction Type; PSet_Revit_Type_Materials and Finishes - Finish: Finish
M_Counter Top w Sink Hole:600mm Depth:600mm Depth:357065:1 | 1D22 | PSet_Revit_Dimensions - Length: 3.05 m; Sink Location: 2.72545 m; Sink Location To Wall: 0.122044 m; Sink Opening Depth: 0.417956 m; Sink Opening Width: 0.4826 m; PSet_Revit_Phasing - Phase Created: New Construction; PSet_Revit_Other - InstallationDate: InstallationDate; SerialNumber: SerialNumber; WarrantyStartDate: WarrantyStartDate; BarCode: BarCode; AssetIdentifier: AssetIdentifier; TagNumber: TagNumber; PSet_Revit_Type_Other - AccessibilityPerformance: AccessibilityPerformance; CodePerformance: CodePerformance; Color: Color; Constituents: Constituents; Features: Features; Finish: Finish; Grade: Grade; Material: Material; ModelReference: ModelReference; NominalHeight: NominalHeight; NominalLength: NominalLength; NominalWidth: NominalWidth; ProductionYear: ProductionYear; Reference: Reference; Shape: Shape; Size: Size; SustainabilityPerformance: SustainabilityPerformance; WarrantyDescription: WarrantyDescription; WarrantyDurationLabor: WarrantyDurationLabor; WarrantyDurationParts: WarrantyDurationParts; WarrantyGuarantorLabor: WarrantyGuarantorLabor; WarrantyGuarantorParts: WarrantyGuarantorParts; ExpectedLife: ExpectedLife; ReplacementCost: ReplacementCost; AssetAccountingType: FIXED; ModelLabel: ModelLabel; Area: Area; PSet_Revit_Type_Identity Data - Manufacturer: Manufacturer; OmniClass Number: 23.40.35.17.47.11; OmniClass Title: Kitchen Casework; PSet_Revit_Constraints - Level: First Floor; Host: Level : First Floor; Offset: 0 m; Moves With Nearby Elements: no; PSet_Revit_Type_Dimensions - Counter Thickness: 0.04 m; Depth: 0.625 m; Height: 0.9 m; PSet_Revit_Type_Construction - Construction Type: Construction Type; PSet_Revit_Type_Materials and Finishes - Finish: Finish
M_Counter Top w Sink Hole:600mm Depth:600mm Depth:422552:1 | 1D08 | PSet_Revit_Dimensions - Length: 1.2 m; Sink Location: 0.6 m; Sink Location To Wall: 0.16973 m; Sink Opening Depth: 0.391258 m; Sink Opening Width: 0.587 m; PSet_Revit_Phasing - Phase Created: New Construction; PSet_Revit_Other - InstallationDate: InstallationDate; SerialNumber: SerialNumber; WarrantyStartDate: WarrantyStartDate; BarCode: BarCode; AssetIdentifier: AssetIdentifier; TagNumber: TagNumber; PSet_Revit_Type_Other - AccessibilityPerformance: AccessibilityPerformance; CodePerformance: CodePerformance; Color: Color; Constituents: Constituents; Features: Features; Finish: Finish; Grade: Grade; Material: Material; ModelReference: ModelReference; NominalHeight: NominalHeight; NominalLength: NominalLength; NominalWidth: NominalWidth; ProductionYear: ProductionYear; Reference: Reference; Shape: Shape; Size: Size; SustainabilityPerformance: SustainabilityPerformance; WarrantyDescription: WarrantyDescription; WarrantyDurationLabor: WarrantyDurationLabor; WarrantyDurationParts: WarrantyDurationParts; WarrantyGuarantorLabor: WarrantyGuarantorLabor; WarrantyGuarantorParts: WarrantyGuarantorParts; ExpectedLife: ExpectedLife; ReplacementCost: ReplacementCost; AssetAccountingType: FIXED; ModelLabel: ModelLabel; Area: Area; PSet_Revit_Type_Identity Data - Manufacturer: Manufacturer; OmniClass Number: 23.40.35.17.47.11; OmniClass Title: Kitchen Casework; PSet_Revit_Constraints - Level: First Floor; Host: Level : First Floor; Offset: 0 m; Moves With Nearby Elements: no; PSet_Revit_Type_Dimensions - Counter Thickness: 0.04 m; Depth: 0.625 m; Height: 0.9 m; PSet_Revit_Type_Construction - Construction Type: Construction Type; PSet_Revit_Type_Materials and Finishes - Finish: Finish
M_Counter Top w Sink Hole:600mm Depth:600mm Depth:331805:1 | 1B10 | PSet_Revit_Dimensions - Length: 1.81 m; Sink Location: 0.263836 m; Sink Location To Wall: 0.1 m; Sink Opening Depth: 0.378 m; Sink Opening Width: 0.31515 m; PSet_Revit_Phasing - Phase Created: New Construction; PSet_Revit_Other - InstallationDate: InstallationDate; SerialNumber: SerialNumber; WarrantyStartDate: WarrantyStartDate; BarCode: BarCode; AssetIdentifier: AssetIdentifier; TagNumber: TagNumber; PSet_Revit_Type_Other - AccessibilityPerformance: AccessibilityPerformance; CodePerformance: CodePerformance; Color: Color; Constituents: Constituents; Features: Features; Finish: Finish; Grade: Grade; Material: Material; ModelReference: ModelReference; NominalHeight: NominalHeight; NominalLength: NominalLength; NominalWidth: NominalWidth; ProductionYear: ProductionYear; Reference: Reference; Shape: Shape; Size: Size; SustainabilityPerformance: SustainabilityPerformance; WarrantyDescription: WarrantyDescription; WarrantyDurationLabor: WarrantyDurationLabor; WarrantyDurationParts: WarrantyDurationParts; WarrantyGuarantorLabor: WarrantyGuarantorLabor; WarrantyGuarantorParts: WarrantyGuarantorParts; ExpectedLife: ExpectedLife; ReplacementCost: ReplacementCost; AssetAccountingType: FIXED; ModelLabel: ModelLabel; Area: Area; PSet_Revit_Type_Identity Data - Manufacturer: Manufacturer; OmniClass Number: 23.40.35.17.47.11; OmniClass Title: Kitchen Casework; PSet_Revit_Constraints - Level: First Floor; Host: Level : First Floor; Offset: 0 m; Moves With Nearby Elements: no; PSet_Revit_Type_Dimensions - Counter Thickness: 0.04 m; Depth: 0.625 m; Height: 0.9 m; PSet_Revit_Type_Construction - Construction Type: Construction Type; PSet_Revit_Type_Materials and Finishes - Finish: Finish
M_Counter Top w Sink Hole:600mm Depth:600mm Depth:422836:1 | 1D09 | PSet_Revit_Dimensions - Length: 1.2 m; Sink Location: 0.6 m; Sink Location To Wall: 0.16973 m; Sink Opening Depth: 0.391258 m; Sink Opening Width: 0.587 m; PSet_Revit_Phasing - Phase Created: New Construction; PSet_Revit_Other - InstallationDate: InstallationDate; SerialNumber: SerialNumber; WarrantyStartDate: WarrantyStartDate; BarCode: BarCode; AssetIdentifier: AssetIdentifier; TagNumber: TagNumber; PSet_Revit_Type_Other - AccessibilityPerformance: AccessibilityPerformance; CodePerformance: CodePerformance; Color: Color; Constituents: Constituents; Features: Features; Finish: Finish; Grade: Grade; Material: Material; ModelReference: ModelReference; NominalHeight: NominalHeight; NominalLength: NominalLength; NominalWidth: NominalWidth; ProductionYear: ProductionYear; Reference: Reference; Shape: Shape; Size: Size; SustainabilityPerformance: SustainabilityPerformance; WarrantyDescription: WarrantyDescription; WarrantyDurationLabor: WarrantyDurationLabor; WarrantyDurationParts: WarrantyDurationParts; WarrantyGuarantorLabor: WarrantyGuarantorLabor; WarrantyGuarantorParts: WarrantyGuarantorParts; ExpectedLife: ExpectedLife; ReplacementCost: ReplacementCost; AssetAccountingType: FIXED; ModelLabel: ModelLabel; Area: Area; PSet_Revit_Type_Identity Data - Manufacturer: Manufacturer; OmniClass Number: 23.40.35.17.47.11; OmniClass Title: Kitchen Casework; PSet_Revit_Constraints - Level: First Floor; Host: Level : First Floor; Offset: 0 m; Moves With Nearby Elements: no; PSet_Revit_Type_Dimensions - Counter Thickness: 0.04 m; Depth: 0.625 m; Height: 0.9 m; PSet_Revit_Type_Construction - Construction Type: Construction Type; PSet_Revit_Type_Materials and Finishes - Finish: Finish
M_Counter Top w Sink Hole:600mm Depth:600mm Depth:422834:1 | 1D07 | PSet_Revit_Dimensions - Length: 1.2 m; Sink Location: 0.6 m; Sink Location To Wall: 0.16973 m; Sink Opening Depth: 0.391258 m; Sink Opening Width: 0.587 m; PSet_Revit_Phasing - Phase Created: New Construction; PSet_Revit_Other - InstallationDate: InstallationDate; SerialNumber: SerialNumber; WarrantyStartDate: WarrantyStartDate; BarCode: BarCode; AssetIdentifier: AssetIdentifier; TagNumber: TagNumber; PSet_Revit_Type_Other - AccessibilityPerformance: AccessibilityPerformance; CodePerformance: CodePerformance; Color: Color; Constituents: Constituents; Features: Features; Finish: Finish; Grade: Grade; Material: Material; ModelReference: ModelReference; NominalHeight: NominalHeight; NominalLength: NominalLength; NominalWidth: NominalWidth; ProductionYear: ProductionYear; Reference: Reference; Shape: Shape; Size: Size; SustainabilityPerformance: SustainabilityPerformance; WarrantyDescription: WarrantyDescription; WarrantyDurationLabor: WarrantyDurationLabor; WarrantyDurationParts: WarrantyDurationParts; WarrantyGuarantorLabor: WarrantyGuarantorLabor; WarrantyGuarantorParts: WarrantyGuarantorParts; ExpectedLife: ExpectedLife; ReplacementCost: ReplacementCost; AssetAccountingType: FIXED; ModelLabel: ModelLabel; Area: Area; PSet_Revit_Type_Identity Data - Manufacturer: Manufacturer; OmniClass Number: 23.40.35.17.47.11; OmniClass Title: Kitchen Casework; PSet_Revit_Constraints - Level: First Floor; Host: Level : First Floor; Offset: 0 m; Moves With Nearby Elements: no; PSet_Revit_Type_Dimensions - Counter Thickness: 0.04 m; Depth: 0.625 m; Height: 0.9 m; PSet_Revit_Type_Construction - Construction Type: Construction Type; PSet_Revit_Type_Materials and Finishes - Finish: Finish
M_Counter Top w Sink Hole:600mm Depth:600mm Depth:342492:1 | 2C10 | PSet_Revit_Dimensions - Length: 3.036 m; Sink Location: 1.346 m; Sink Location To Wall: 0.1 m; Sink Opening Depth: 0.378 m; Sink Opening Width: 0.587 m; PSet_Revit_Phasing - Phase Created: New Construction; PSet_Revit_Other - InstallationDate: InstallationDate; SerialNumber: SerialNumber; WarrantyStartDate: WarrantyStartDate; BarCode: BarCode; AssetIdentifier: AssetIdentifier; TagNumber: TagNumber; PSet_Revit_Type_Other - AccessibilityPerformance: AccessibilityPerformance; CodePerformance: CodePerformance; Color: Color; Constituents: Constituents; Features: Features; Finish: Finish; Grade: Grade; Material: Material; ModelReference: ModelReference; NominalHeight: NominalHeight; NominalLength: NominalLength; NominalWidth: NominalWidth; ProductionYear: ProductionYear; Reference: Reference; Shape: Shape; Size: Size; SustainabilityPerformance: SustainabilityPerformance; WarrantyDescription: WarrantyDescription; WarrantyDurationLabor: WarrantyDurationLabor; WarrantyDurationParts: WarrantyDurationParts; WarrantyGuarantorLabor: WarrantyGuarantorLabor; WarrantyGuarantorParts: WarrantyGuarantorParts; ExpectedLife: ExpectedLife; ReplacementCost: ReplacementCost; AssetAccountingType: FIXED; ModelLabel: ModelLabel; Area: Area; PSet_Revit_Type_Identity Data - Manufacturer: Manufacturer; OmniClass Number: 23.40.35.17.47.11; OmniClass Title: Kitchen Casework; PSet_Revit_Constraints - Level: Second Floor; Host: Level : Second Floor; Offset: 0 m; Moves With Nearby Elements: no; PSet_Revit_Type_Dimensions - Counter Thickness: 0.04 m; Depth: 0.625 m; Height: 0.9 m; PSet_Revit_Type_Construction - Construction Type: Construction Type; PSet_Revit_Type_Materials and Finishes - Finish: Finish
M_Counter Top w Sink Hole:600mm Depth:600mm Depth:424042:1 | 1D28 | PSet_Revit_Dimensions - Length: 1.2 m; Sink Location: 0.6 m; Sink Location To Wall: 0.16973 m; Sink Opening Depth: 0.391258 m; Sink Opening Width: 0.587 m; PSet_Revit_Phasing - Phase Created: New Construction; PSet_Revit_Other - InstallationDate: InstallationDate; SerialNumber: SerialNumber; WarrantyStartDate: WarrantyStartDate; BarCode: BarCode; AssetIdentifier: AssetIdentifier; TagNumber: TagNumber; PSet_Revit_Type_Other - AccessibilityPerformance: AccessibilityPerformance; CodePerformance: CodePerformance; Color: Color; Constituents: Constituents; Features: Features; Finish: Finish; Grade: Grade; Material: Material; ModelReference: ModelReference; NominalHeight: NominalHeight; NominalLength: NominalLength; NominalWidth: NominalWidth; ProductionYear: ProductionYear; Reference: Reference; Shape: Shape; Size: Size; SustainabilityPerformance: SustainabilityPerformance; WarrantyDescription: WarrantyDescription; WarrantyDurationLabor: WarrantyDurationLabor; WarrantyDurationParts: WarrantyDurationParts; WarrantyGuarantorLabor: WarrantyGuarantorLabor; WarrantyGuarantorParts: WarrantyGuarantorParts; ExpectedLife: ExpectedLife; ReplacementCost: ReplacementCost; AssetAccountingType: FIXED; ModelLabel: ModelLabel; Area: Area; PSet_Revit_Type_Identity Data - Manufacturer: Manufacturer; OmniClass Number: 23.40.35.17.47.11; OmniClass Title: Kitchen Casework; PSet_Revit_Constraints - Level: First Floor; Host: Level : First Floor; Offset: 0 m; Moves With Nearby Elements: no; PSet_Revit_Type_Dimensions - Counter Thickness: 0.04 m; Depth: 0.625 m; Height: 0.9 m; PSet_Revit_Type_Construction - Construction Type: Construction Type; PSet_Revit_Type_Materials and Finishes - Finish: Finish
M_Counter Top w Sink Hole:600mm Depth:600mm Depth:338411:1 | 2C17 | PSet_Revit_Dimensions - Length: 2.46715 m; Sink Location: 2.14329 m; Sink Location To Wall: 0.1 m; Sink Opening Depth: 0.378 m; Sink Opening Width: 0.587 m; PSet_Revit_Phasing - Phase Created: New Construction; PSet_Revit_Other - InstallationDate: InstallationDate; SerialNumber: SerialNumber; WarrantyStartDate: WarrantyStartDate; BarCode: BarCode; AssetIdentifier: AssetIdentifier; TagNumber: TagNumber; PSet_Revit_Type_Other - AccessibilityPerformance: AccessibilityPerformance; CodePerformance: CodePerformance; Color: Color; Constituents: Constituents; Features: Features; Finish: Finish; Grade: Grade; Material: Material; ModelReference: ModelReference; NominalHeight: NominalHeight; NominalLength: NominalLength; NominalWidth: NominalWidth; ProductionYear: ProductionYear; Reference: Reference; Shape: Shape; Size: Size; SustainabilityPerformance: SustainabilityPerformance; WarrantyDescription: WarrantyDescription; WarrantyDurationLabor: WarrantyDurationLabor; WarrantyDurationParts: WarrantyDurationParts; WarrantyGuarantorLabor: WarrantyGuarantorLabor; WarrantyGuarantorParts: WarrantyGuarantorParts; ExpectedLife: ExpectedLife; ReplacementCost: ReplacementCost; AssetAccountingType: FIXED; ModelLabel: ModelLabel; Area: Area; PSet_Revit_Type_Identity Data - Manufacturer: Manufacturer; OmniClass Number: 23.40.35.17.47.11; OmniClass Title: Kitchen Casework; PSet_Revit_Constraints - Level: Second Floor; Host: Level : Second Floor; Offset: 0 m; Moves With Nearby Elements: no; PSet_Revit_Type_Dimensions - Counter Thickness: 0.04 m; Depth: 0.625 m; Height: 0.9 m; PSet_Revit_Type_Construction - Construction Type: Construction Type; PSet_Revit_Type_Materials and Finishes - Finish: Finish
M_Counter Top w Sink Hole:600mm Depth:600mm Depth:338826:1 | 2C17 | PSet_Revit_Dimensions - Length: 4.69696 m; Sink Location: 0.36704 m; Sink Location To Wall: 0.1 m; Sink Opening Depth: 0.378 m; Sink Opening Width: 0.587 m; PSet_Revit_Phasing - Phase Created: New Construction; PSet_Revit_Other - InstallationDate: InstallationDate; SerialNumber: SerialNumber; WarrantyStartDate: WarrantyStartDate; BarCode: BarCode; AssetIdentifier: AssetIdentifier; TagNumber: TagNumber; PSet_Revit_Type_Other - AccessibilityPerformance: AccessibilityPerformance; CodePerformance: CodePerformance; Color: Color; Constituents: Constituents; Features: Features; Finish: Finish; Grade: Grade; Material: Material; ModelReference: ModelReference; NominalHeight: NominalHeight; NominalLength: NominalLength; NominalWidth: NominalWidth; ProductionYear: ProductionYear; Reference: Reference; Shape: Shape; Size: Size; SustainabilityPerformance: SustainabilityPerformance; WarrantyDescription: WarrantyDescription; WarrantyDurationLabor: WarrantyDurationLabor; WarrantyDurationParts: WarrantyDurationParts; WarrantyGuarantorLabor: WarrantyGuarantorLabor; WarrantyGuarantorParts: WarrantyGuarantorParts; ExpectedLife: ExpectedLife; ReplacementCost: ReplacementCost; AssetAccountingType: FIXED; ModelLabel: ModelLabel; Area: Area; PSet_Revit_Type_Identity Data - Manufacturer: Manufacturer; OmniClass Number: 23.40.35.17.47.11; OmniClass Title: Kitchen Casework; PSet_Revit_Constraints - Level: Second Floor; Host: Level : Second Floor; Offset: 0 m; Moves With Nearby Elements: no; PSet_Revit_Type_Dimensions - Counter Thickness: 0.04 m; Depth: 0.625 m; Height: 0.9 m; PSet_Revit_Type_Construction - Construction Type: Construction Type; PSet_Revit_Type_Materials and Finishes - Finish: Finish
M_Counter Top w Sink Hole:600mm Depth:600mm Depth:422863:1 | 1D05 | PSet_Revit_Dimensions - Length: 2.41 m; Sink Location: 1.205 m; Sink Location To Wall: 0.137017 m; Sink Opening Depth: 0.4064 m; Sink Opening Width: 0.587 m; PSet_Revit_Phasing - Phase Created: New Construction; PSet_Revit_Other - InstallationDate: InstallationDate; SerialNumber: SerialNumber; WarrantyStartDate: WarrantyStartDate; BarCode: BarCode; AssetIdentifier: AssetIdentifier; TagNumber: TagNumber; PSet_Revit_Type_Other - AccessibilityPerformance: AccessibilityPerformance; CodePerformance: CodePerformance; Color: Color; Constituents: Constituents; Features: Features; Finish: Finish; Grade: Grade; Material: Material; ModelReference: ModelReference; NominalHeight: NominalHeight; NominalLength: NominalLength; NominalWidth: NominalWidth; ProductionYear: ProductionYear; Reference: Reference; Shape: Shape; Size: Size; SustainabilityPerformance: SustainabilityPerformance; WarrantyDescription: WarrantyDescription; WarrantyDurationLabor: WarrantyDurationLabor; WarrantyDurationParts: WarrantyDurationParts; WarrantyGuarantorLabor: WarrantyGuarantorLabor; WarrantyGuarantorParts: WarrantyGuarantorParts; ExpectedLife: ExpectedLife; ReplacementCost: ReplacementCost; AssetAccountingType: FIXED; ModelLabel: ModelLabel; Area: Area; PSet_Revit_Type_Identity Data - Manufacturer: Manufacturer; OmniClass Number: 23.40.35.17.47.11; OmniClass Title: Kitchen Casework; PSet_Revit_Constraints - Level: First Floor; Host: Level : First Floor; Offset: 0 m; Moves With Nearby Elements: no; PSet_Revit_Type_Dimensions - Counter Thickness: 0.04 m; Depth: 0.625 m; Height: 0.9 m; PSet_Revit_Type_Construction - Construction Type: Construction Type; PSet_Revit_Type_Materials and Finishes - Finish: Finish
M_Counter Top w Sink Hole:600mm Depth:600mm Depth:424107:1 | 1D38 | PSet_Revit_Dimensions - Length: 1.2 m; Sink Location: 0.842659 m; Sink Location To Wall: 0.16973 m; Sink Opening Depth: 0.391258 m; Sink Opening Width: 0.587 m; PSet_Revit_Phasing - Phase Created: New Construction; PSet_Revit_Other - InstallationDate: InstallationDate; SerialNumber: SerialNumber; WarrantyStartDate: WarrantyStartDate; BarCode: BarCode; AssetIdentifier: AssetIdentifier; TagNumber: TagNumber; PSet_Revit_Type_Other - AccessibilityPerformance: AccessibilityPerformance; CodePerformance: CodePerformance; Color: Color; Constituents: Constituents; Features: Features; Finish: Finish; Grade: Grade; Material: Material; ModelReference: ModelReference; NominalHeight: NominalHeight; NominalLength: NominalLength; NominalWidth: NominalWidth; ProductionYear: ProductionYear; Reference: Reference; Shape: Shape; Size: Size; SustainabilityPerformance: SustainabilityPerformance; WarrantyDescription: WarrantyDescription; WarrantyDurationLabor: WarrantyDurationLabor; WarrantyDurationParts: WarrantyDurationParts; WarrantyGuarantorLabor: WarrantyGuarantorLabor; WarrantyGuarantorParts: WarrantyGuarantorParts; ExpectedLife: ExpectedLife; ReplacementCost: ReplacementCost; AssetAccountingType: FIXED; ModelLabel: ModelLabel; Area: Area; PSet_Revit_Type_Identity Data - Manufacturer: Manufacturer; OmniClass Number: 23.40.35.17.47.11; OmniClass Title: Kitchen Casework; PSet_Revit_Constraints - Level: First Floor; Host: Level : First Floor; Offset: 0 m; Moves With Nearby Elements: no; PSet_Revit_Type_Dimensions - Counter Thickness: 0.04 m; Depth: 0.625 m; Height: 0.9 m; PSet_Revit_Type_Construction - Construction Type: Construction Type; PSet_Revit_Type_Materials and Finishes - Finish: Finish
M_Counter Top w Sink Hole:600mm Depth:600mm Depth:422741:1 | 1D11 | PSet_Revit_Dimensions - Length: 1.2 m; Sink Location: 0.6 m; Sink Location To Wall: 0.16973 m; Sink Opening Depth: 0.391258 m; Sink Opening Width: 0.587 m; PSet_Revit_Phasing - Phase Created: New Construction; PSet_Revit_Other - InstallationDate: InstallationDate; SerialNumber: SerialNumber; WarrantyStartDate: WarrantyStartDate; BarCode: BarCode; AssetIdentifier: AssetIdentifier; TagNumber: TagNumber; PSet_Revit_Type_Other - AccessibilityPerformance: AccessibilityPerformance; CodePerformance: CodePerformance; Color: Color; Constituents: Constituents; Features: Features; Finish: Finish; Grade: Grade; Material: Material; ModelReference: ModelReference; NominalHeight: NominalHeight; NominalLength: NominalLength; NominalWidth: NominalWidth; ProductionYear: ProductionYear; Reference: Reference; Shape: Shape; Size: Size; SustainabilityPerformance: SustainabilityPerformance; WarrantyDescription: WarrantyDescription; WarrantyDurationLabor: WarrantyDurationLabor; WarrantyDurationParts: WarrantyDurationParts; WarrantyGuarantorLabor: WarrantyGuarantorLabor; WarrantyGuarantorParts: WarrantyGuarantorParts; ExpectedLife: ExpectedLife; ReplacementCost: ReplacementCost; AssetAccountingType: FIXED; ModelLabel: ModelLabel; Area: Area; PSet_Revit_Type_Identity Data - Manufacturer: Manufacturer; OmniClass Number: 23.40.35.17.47.11; OmniClass Title: Kitchen Casework; PSet_Revit_Constraints - Level: First Floor; Host: Level : First Floor; Offset: 0 m; Moves With Nearby Elements: no; PSet_Revit_Type_Dimensions - Counter Thickness: 0.04 m; Depth: 0.625 m; Height: 0.9 m; PSet_Revit_Type_Construction - Construction Type: Construction Type; PSet_Revit_Type_Materials and Finishes - Finish: Finish
M_Counter Top w Sink Hole:600mm Depth:600mm Depth:341491:1 | 2C12 | PSet_Revit_Dimensions - Length: 3.872 m; Sink Location: 1.03026 m; Sink Location To Wall: 0.1 m; Sink Opening Depth: 0.378 m; Sink Opening Width: 0.587 m; PSet_Revit_Phasing - Phase Created: New Construction; PSet_Revit_Other - InstallationDate: InstallationDate; SerialNumber: SerialNumber; WarrantyStartDate: WarrantyStartDate; BarCode: BarCode; AssetIdentifier: AssetIdentifier; TagNumber: TagNumber; PSet_Revit_Type_Other - AccessibilityPerformance: AccessibilityPerformance; CodePerformance: CodePerformance; Color: Color; Constituents: Constituents; Features: Features; Finish: Finish; Grade: Grade; Material: Material; ModelReference: ModelReference; NominalHeight: NominalHeight; NominalLength: NominalLength; NominalWidth: NominalWidth; ProductionYear: ProductionYear; Reference: Reference; Shape: Shape; Size: Size; SustainabilityPerformance: SustainabilityPerformance; WarrantyDescription: WarrantyDescription; WarrantyDurationLabor: WarrantyDurationLabor; WarrantyDurationParts: WarrantyDurationParts; WarrantyGuarantorLabor: WarrantyGuarantorLabor; WarrantyGuarantorParts: WarrantyGuarantorParts; ExpectedLife: ExpectedLife; ReplacementCost: ReplacementCost; AssetAccountingType: FIXED; ModelLabel: ModelLabel; Area: Area; PSet_Revit_Type_Identity Data - Manufacturer: Manufacturer; OmniClass Number: 23.40.35.17.47.11; OmniClass Title: Kitchen Casework; PSet_Revit_Constraints - Level: Second Floor; Host: Level : Second Floor; Offset: 0 m; Moves With Nearby Elements: no; PSet_Revit_Type_Dimensions - Counter Thickness: 0.04 m; Depth: 0.625 m; Height: 0.9 m; PSet_Revit_Type_Construction - Construction Type: Construction Type; PSet_Revit_Type_Materials and Finishes - Finish: Finish
M_Counter Top w Sink Hole:600mm Depth:600mm Depth:424493:1 | 1B04 | PSet_Revit_Dimensions - Length: 2.5 m; Sink Location: 1.628 m; Sink Location To Wall: 0.1 m; Sink Opening Depth: 0.378 m; Sink Opening Width: 0.587 m; PSet_Revit_Phasing - Phase Created: New Construction; PSet_Revit_Other - InstallationDate: InstallationDate; SerialNumber: SerialNumber; WarrantyStartDate: WarrantyStartDate; BarCode: BarCode; AssetIdentifier: AssetIdentifier; TagNumber: TagNumber; PSet_Revit_Type_Other - AccessibilityPerformance: AccessibilityPerformance; CodePerformance: CodePerformance; Color: Color; Constituents: Constituents; Features: Features; Finish: Finish; Grade: Grade; Material: Material; ModelReference: ModelReference; NominalHeight: NominalHeight; NominalLength: NominalLength; NominalWidth: NominalWidth; ProductionYear: ProductionYear; Reference: Reference; Shape: Shape; Size: Size; SustainabilityPerformance: SustainabilityPerformance; WarrantyDescription: WarrantyDescription; WarrantyDurationLabor: WarrantyDurationLabor; WarrantyDurationParts: WarrantyDurationParts; WarrantyGuarantorLabor: WarrantyGuarantorLabor; WarrantyGuarantorParts: WarrantyGuarantorParts; ExpectedLife: ExpectedLife; ReplacementCost: ReplacementCost; AssetAccountingType: FIXED; ModelLabel: ModelLabel; Area: Area; PSet_Revit_Type_Identity Data - Manufacturer: Manufacturer; OmniClass Number: 23.40.35.17.47.11; OmniClass Title: Kitchen Casework; PSet_Revit_Constraints - Level: First Floor; Host: Level : First Floor; Offset: 0 m; Moves With Nearby Elements: no; PSet_Revit_Type_Dimensions - Counter Thickness: 0.04 m; Depth: 0.625 m; Height: 0.9 m; PSet_Revit_Type_Construction - Construction Type: Construction Type; PSet_Revit_Type_Materials and Finishes - Finish: Finish
M_Counter Top w Sink Hole:600mm Depth:600mm Depth:426806:1 | 2A07 | PSet_Revit_Dimensions - Length: 2.10996 m; Sink Location: 0.338951 m; Sink Location To Wall: 0.1 m; Sink Opening Depth: 0.378 m; Sink Opening Width: 0.3556 m; PSet_Revit_Phasing - Phase Created: New Construction; PSet_Revit_Other - InstallationDate: InstallationDate; SerialNumber: SerialNumber; WarrantyStartDate: WarrantyStartDate; BarCode: BarCode; AssetIdentifier: AssetIdentifier; TagNumber: TagNumber; PSet_Revit_Type_Other - AccessibilityPerformance: AccessibilityPerformance; CodePerformance: CodePerformance; Color: Color; Constituents: Constituents; Features: Features; Finish: Finish; Grade: Grade; Material: Material; ModelReference: ModelReference; NominalHeight: NominalHeight; NominalLength: NominalLength; NominalWidth: NominalWidth; ProductionYear: ProductionYear; Reference: Reference; Shape: Shape; Size: Size; SustainabilityPerformance: SustainabilityPerformance; WarrantyDescription: WarrantyDescription; WarrantyDurationLabor: WarrantyDurationLabor; WarrantyDurationParts: WarrantyDurationParts; WarrantyGuarantorLabor: WarrantyGuarantorLabor; WarrantyGuarantorParts: WarrantyGuarantorParts; ExpectedLife: ExpectedLife; ReplacementCost: ReplacementCost; AssetAccountingType: FIXED; ModelLabel: ModelLabel; Area: Area; PSet_Revit_Type_Identity Data - Manufacturer: Manufacturer; OmniClass Number: 23.40.35.17.47.11; OmniClass Title: Kitchen Casework; PSet_Revit_Constraints - Level: Second Floor; Host: Level : Second Floor; Offset: 0 m; Moves With Nearby Elements: no; PSet_Revit_Type_Dimensions - Counter Thickness: 0.04 m; Depth: 0.625 m; Height: 0.9 m; PSet_Revit_Type_Construction - Construction Type: Construction Type; PSet_Revit_Type_Materials and Finishes - Finish: Finish
M_Counter Top w Sink Hole:600mm Depth:600mm Depth:422728:1 | 1D10 | PSet_Revit_Dimensions - Length: 1.2 m; Sink Location: 0.6 m; Sink Location To Wall: 0.16973 m; Sink Opening Depth: 0.391258 m; Sink Opening Width: 0.587 m; PSet_Revit_Phasing - Phase Created: New Construction; PSet_Revit_Other - InstallationDate: InstallationDate; SerialNumber: SerialNumber; WarrantyStartDate: WarrantyStartDate; BarCode: BarCode; AssetIdentifier: AssetIdentifier; TagNumber: TagNumber; PSet_Revit_Type_Other - AccessibilityPerformance: AccessibilityPerformance; CodePerformance: CodePerformance; Color: Color; Constituents: Constituents; Features: Features; Finish: Finish; Grade: Grade; Material: Material; ModelReference: ModelReference; NominalHeight: NominalHeight; NominalLength: NominalLength; NominalWidth: NominalWidth; ProductionYear: ProductionYear; Reference: Reference; Shape: Shape; Size: Size; SustainabilityPerformance: SustainabilityPerformance; WarrantyDescription: WarrantyDescription; WarrantyDurationLabor: WarrantyDurationLabor; WarrantyDurationParts: WarrantyDurationParts; WarrantyGuarantorLabor: WarrantyGuarantorLabor; WarrantyGuarantorParts: WarrantyGuarantorParts; ExpectedLife: ExpectedLife; ReplacementCost: ReplacementCost; AssetAccountingType: FIXED; ModelLabel: ModelLabel; Area: Area; PSet_Revit_Type_Identity Data - Manufacturer: Manufacturer; OmniClass Number: 23.40.35.17.47.11; OmniClass Title: Kitchen Casework; PSet_Revit_Constraints - Level: First Floor; Host: Level : First Floor; Offset: 0 m; Moves With Nearby Elements: no; PSet_Revit_Type_Dimensions - Counter Thickness: 0.04 m; Depth: 0.625 m; Height: 0.9 m; PSet_Revit_Type_Construction - Construction Type: Construction Type; PSet_Revit_Type_Materials and Finishes - Finish: Finish
M_Counter Top w Sink Hole:600mm Depth:600mm Depth:422814:1 | 1D13 | PSet_Revit_Dimensions - Length: 1.2 m; Sink Location: 0.6 m; Sink Location To Wall: 0.16973 m; Sink Opening Depth: 0.391258 m; Sink Opening Width: 0.587 m; PSet_Revit_Phasing - Phase Created: New Construction; PSet_Revit_Other - InstallationDate: InstallationDate; SerialNumber: SerialNumber; WarrantyStartDate: WarrantyStartDate; BarCode: BarCode; AssetIdentifier: AssetIdentifier; TagNumber: TagNumber; PSet_Revit_Type_Other - AccessibilityPerformance: AccessibilityPerformance; CodePerformance: CodePerformance; Color: Color; Constituents: Constituents; Features: Features; Finish: Finish; Grade: Grade; Material: Material; ModelReference: ModelReference; NominalHeight: NominalHeight; NominalLength: NominalLength; NominalWidth: NominalWidth; ProductionYear: ProductionYear; Reference: Reference; Shape: Shape; Size: Size; SustainabilityPerformance: SustainabilityPerformance; WarrantyDescription: WarrantyDescription; WarrantyDurationLabor: WarrantyDurationLabor; WarrantyDurationParts: WarrantyDurationParts; WarrantyGuarantorLabor: WarrantyGuarantorLabor; WarrantyGuarantorParts: WarrantyGuarantorParts; ExpectedLife: ExpectedLife; ReplacementCost: ReplacementCost; AssetAccountingType: FIXED; ModelLabel: ModelLabel; Area: Area; PSet_Revit_Type_Identity Data - Manufacturer: Manufacturer; OmniClass Number: 23.40.35.17.47.11; OmniClass Title: Kitchen Casework; PSet_Revit_Constraints - Level: First Floor; Host: Level : First Floor; Offset: 0 m; Moves With Nearby Elements: no; PSet_Revit_Type_Dimensions - Counter Thickness: 0.04 m; Depth: 0.625 m; Height: 0.9 m; PSet_Revit_Type_Construction - Construction Type: Construction Type; PSet_Revit_Type_Materials and Finishes - Finish: Finish
M_Counter Top w Sink Hole:600mm Depth:600mm Depth:424045:1 | 1D32 | PSet_Revit_Dimensions - Length: 1.2 m; Sink Location: 0.6 m; Sink Location To Wall: 0.16973 m; Sink Opening Depth: 0.391258 m; Sink Opening Width: 0.587 m; PSet_Revit_Phasing - Phase Created: New Construction; PSet_Revit_Other - InstallationDate: InstallationDate; SerialNumber: SerialNumber; WarrantyStartDate: WarrantyStartDate; BarCode: BarCode; AssetIdentifier: AssetIdentifier; TagNumber: TagNumber; PSet_Revit_Type_Other - AccessibilityPerformance: AccessibilityPerformance; CodePerformance: CodePerformance; Color: Color; Constituents: Constituents; Features: Features; Finish: Finish; Grade: Grade; Material: Material; ModelReference: ModelReference; NominalHeight: NominalHeight; NominalLength: NominalLength; NominalWidth: NominalWidth; ProductionYear: ProductionYear; Reference: Reference; Shape: Shape; Size: Size; SustainabilityPerformance: SustainabilityPerformance; WarrantyDescription: WarrantyDescription; WarrantyDurationLabor: WarrantyDurationLabor; WarrantyDurationParts: WarrantyDurationParts; WarrantyGuarantorLabor: WarrantyGuarantorLabor; WarrantyGuarantorParts: WarrantyGuarantorParts; ExpectedLife: ExpectedLife; ReplacementCost: ReplacementCost; AssetAccountingType: FIXED; ModelLabel: ModelLabel; Area: Area; PSet_Revit_Type_Identity Data - Manufacturer: Manufacturer; OmniClass Number: 23.40.35.17.47.11; OmniClass Title: Kitchen Casework; PSet_Revit_Constraints - Level: First Floor; Host: Level : First Floor; Offset: 0 m; Moves With Nearby Elements: no; PSet_Revit_Type_Dimensions - Counter Thickness: 0.04 m; Depth: 0.625 m; Height: 0.9 m; PSet_Revit_Type_Construction - Construction Type: Construction Type; PSet_Revit_Type_Materials and Finishes - Finish: Finish
M_Counter Top w Sink Hole:600mm Depth:600mm Depth:426851:1 | 2A06 | PSet_Revit_Dimensions - Length: 2.10996 m; Sink Location: 0.338951 m; Sink Location To Wall: 0.1 m; Sink Opening Depth: 0.378 m; Sink Opening Width: 0.3556 m; PSet_Revit_Phasing - Phase Created: New Construction; PSet_Revit_Other - InstallationDate: InstallationDate; SerialNumber: SerialNumber; WarrantyStartDate: WarrantyStartDate; BarCode: BarCode; AssetIdentifier: AssetIdentifier; TagNumber: TagNumber; PSet_Revit_Type_Other - AccessibilityPerformance: AccessibilityPerformance; CodePerformance: CodePerformance; Color: Color; Constituents: Constituents; Features: Features; Finish: Finish; Grade: Grade; Material: Material; ModelReference: ModelReference; NominalHeight: NominalHeight; NominalLength: NominalLength; NominalWidth: NominalWidth; ProductionYear: ProductionYear; Reference: Reference; Shape: Shape; Size: Size; SustainabilityPerformance: SustainabilityPerformance; WarrantyDescription: WarrantyDescription; WarrantyDurationLabor: WarrantyDurationLabor; WarrantyDurationParts: WarrantyDurationParts; WarrantyGuarantorLabor: WarrantyGuarantorLabor; WarrantyGuarantorParts: WarrantyGuarantorParts; ExpectedLife: ExpectedLife; ReplacementCost: ReplacementCost; AssetAccountingType: FIXED; ModelLabel: ModelLabel; Area: Area; PSet_Revit_Type_Identity Data - Manufacturer: Manufacturer; OmniClass Number: 23.40.35.17.47.11; OmniClass Title: Kitchen Casework; PSet_Revit_Constraints - Level: Second Floor; Host: Level : Second Floor; Offset: 0 m; Moves With Nearby Elements: no; PSet_Revit_Type_Dimensions - Counter Thickness: 0.04 m; Depth: 0.625 m; Height: 0.9 m; PSet_Revit_Type_Construction - Construction Type: Construction Type; PSet_Revit_Type_Materials and Finishes - Finish: Finish
M_Counter Top w Sink Hole:600mm Depth:600mm Depth:425594:1 | 2C14 | PSet_Revit_Dimensions - Length: 2.10996 m; Sink Location: 0.338951 m; Sink Location To Wall: 0.1 m; Sink Opening Depth: 0.378 m; Sink Opening Width: 0.3556 m; PSet_Revit_Phasing - Phase Created: New Construction; PSet_Revit_Other - InstallationDate: InstallationDate; SerialNumber: SerialNumber; WarrantyStartDate: WarrantyStartDate; BarCode: BarCode; AssetIdentifier: AssetIdentifier; TagNumber: TagNumber; PSet_Revit_Type_Other - AccessibilityPerformance: AccessibilityPerformance; CodePerformance: CodePerformance; Color: Color; Constituents: Constituents; Features: Features; Finish: Finish; Grade: Grade; Material: Material; ModelReference: ModelReference; NominalHeight: NominalHeight; NominalLength: NominalLength; NominalWidth: NominalWidth; ProductionYear: ProductionYear; Reference: Reference; Shape: Shape; Size: Size; SustainabilityPerformance: SustainabilityPerformance; WarrantyDescription: WarrantyDescription; WarrantyDurationLabor: WarrantyDurationLabor; WarrantyDurationParts: WarrantyDurationParts; WarrantyGuarantorLabor: WarrantyGuarantorLabor; WarrantyGuarantorParts: WarrantyGuarantorParts; ExpectedLife: ExpectedLife; ReplacementCost: ReplacementCost; AssetAccountingType: FIXED; ModelLabel: ModelLabel; Area: Area; PSet_Revit_Type_Identity Data - Manufacturer: Manufacturer; OmniClass Number: 23.40.35.17.47.11; OmniClass Title: Kitchen Casework; PSet_Revit_Constraints - Level: Second Floor; Host: Level : Second Floor; Offset: 0 m; Moves With Nearby Elements: no; PSet_Revit_Type_Dimensions - Counter Thickness: 0.04 m; Depth: 0.625 m; Height: 0.9 m; PSet_Revit_Type_Construction - Construction Type: Construction Type; PSet_Revit_Type_Materials and Finishes - Finish: Finish
M_Counter Top w Sink Hole:600mm Depth:600mm Depth:424069:1 | 1D36 | PSet_Revit_Dimensions - Length: 1.2 m; Sink Location: 0.6 m; Sink Location To Wall: 0.16973 m; Sink Opening Depth: 0.391258 m; Sink Opening Width: 0.587 m; PSet_Revit_Phasing - Phase Created: New Construction; PSet_Revit_Other - InstallationDate: InstallationDate; SerialNumber: SerialNumber; WarrantyStartDate: WarrantyStartDate; BarCode: BarCode; AssetIdentifier: AssetIdentifier; TagNumber: TagNumber; PSet_Revit_Type_Other - AccessibilityPerformance: AccessibilityPerformance; CodePerformance: CodePerformance; Color: Color; Constituents: Constituents; Features: Features; Finish: Finish; Grade: Grade; Material: Material; ModelReference: ModelReference; NominalHeight: NominalHeight; NominalLength: NominalLength; NominalWidth: NominalWidth; ProductionYear: ProductionYear; Reference: Reference; Shape: Shape; Size: Size; SustainabilityPerformance: SustainabilityPerformance; WarrantyDescription: WarrantyDescription; WarrantyDurationLabor: WarrantyDurationLabor; WarrantyDurationParts: WarrantyDurationParts; WarrantyGuarantorLabor: WarrantyGuarantorLabor; WarrantyGuarantorParts: WarrantyGuarantorParts; ExpectedLife: ExpectedLife; ReplacementCost: ReplacementCost; AssetAccountingType: FIXED; ModelLabel: ModelLabel; Area: Area; PSet_Revit_Type_Identity Data - Manufacturer: Manufacturer; OmniClass Number: 23.40.35.17.47.11; OmniClass Title: Kitchen Casework; PSet_Revit_Constraints - Level: First Floor; Host: Level : First Floor; Offset: 0 m; Moves With Nearby Elements: no; PSet_Revit_Type_Dimensions - Counter Thickness: 0.04 m; Depth: 0.625 m; Height: 0.9 m; PSet_Revit_Type_Construction - Construction Type: Construction Type; PSet_Revit_Type_Materials and Finishes - Finish: Finish
M_Counter Top w Sink Hole:600mm Depth:600mm Depth:424797:1 | 1B04 | PSet_Revit_Dimensions - Length: 2.57089 m; Sink Location: 1 m; Sink Location To Wall: 0.1 m; Sink Opening Depth: 0.378 m; Sink Opening Width: 0.587 m; PSet_Revit_Phasing - Phase Created: New Construction; PSet_Revit_Other - InstallationDate: InstallationDate; SerialNumber: SerialNumber; WarrantyStartDate: WarrantyStartDate; BarCode: BarCode; AssetIdentifier: AssetIdentifier; TagNumber: TagNumber; PSet_Revit_Type_Other - AccessibilityPerformance: AccessibilityPerformance; CodePerformance: CodePerformance; Color: Color; Constituents: Constituents; Features: Features; Finish: Finish; Grade: Grade; Material: Material; ModelReference: ModelReference; NominalHeight: NominalHeight; NominalLength: NominalLength; NominalWidth: NominalWidth; ProductionYear: ProductionYear; Reference: Reference; Shape: Shape; Size: Size; SustainabilityPerformance: SustainabilityPerformance; WarrantyDescription: WarrantyDescription; WarrantyDurationLabor: WarrantyDurationLabor; WarrantyDurationParts: WarrantyDurationParts; WarrantyGuarantorLabor: WarrantyGuarantorLabor; WarrantyGuarantorParts: WarrantyGuarantorParts; ExpectedLife: ExpectedLife; ReplacementCost: ReplacementCost; AssetAccountingType: FIXED; ModelLabel: ModelLabel; Area: Area; PSet_Revit_Type_Identity Data - Manufacturer: Manufacturer; OmniClass Number: 23.40.35.17.47.11; OmniClass Title: Kitchen Casework; PSet_Revit_Constraints - Level: First Floor; Host: Level : First Floor; Offset: 0 m; Moves With Nearby Elements: no; PSet_Revit_Type_Dimensions - Counter Thickness: 0.04 m; Depth: 0.625 m; Height: 0.9 m; PSet_Revit_Type_Construction - Construction Type: Construction Type; PSet_Revit_Type_Materials and Finishes - Finish: Finish
M_Counter Top w Sink Hole:600mm Depth:600mm Depth:424226:1 | 1D35 | PSet_Revit_Dimensions - Length: 1.2 m; Sink Location: 0.6 m; Sink Location To Wall: 0.16973 m; Sink Opening Depth: 0.391258 m; Sink Opening Width: 0.587 m; PSet_Revit_Phasing - Phase Created: New Construction; PSet_Revit_Other - InstallationDate: InstallationDate; SerialNumber: SerialNumber; WarrantyStartDate: WarrantyStartDate; BarCode: BarCode; AssetIdentifier: AssetIdentifier; TagNumber: TagNumber; PSet_Revit_Type_Other - AccessibilityPerformance: AccessibilityPerformance; CodePerformance: CodePerformance; Color: Color; Constituents: Constituents; Features: Features; Finish: Finish; Grade: Grade; Material: Material; ModelReference: ModelReference; NominalHeight: NominalHeight; NominalLength: NominalLength; NominalWidth: NominalWidth; ProductionYear: ProductionYear; Reference: Reference; Shape: Shape; Size: Size; SustainabilityPerformance: SustainabilityPerformance; WarrantyDescription: WarrantyDescription; WarrantyDurationLabor: WarrantyDurationLabor; WarrantyDurationParts: WarrantyDurationParts; WarrantyGuarantorLabor: WarrantyGuarantorLabor; WarrantyGuarantorParts: WarrantyGuarantorParts; ExpectedLife: ExpectedLife; ReplacementCost: ReplacementCost; AssetAccountingType: FIXED; ModelLabel: ModelLabel; Area: Area; PSet_Revit_Type_Identity Data - Manufacturer: Manufacturer; OmniClass Number: 23.40.35.17.47.11; OmniClass Title: Kitchen Casework; PSet_Revit_Constraints - Level: First Floor; Host: Level : First Floor; Offset: 0 m; Moves With Nearby Elements: no; PSet_Revit_Type_Dimensions - Counter Thickness: 0.04 m; Depth: 0.625 m; Height: 0.9 m; PSet_Revit_Type_Construction - Construction Type: Construction Type; PSet_Revit_Type_Materials and Finishes - Finish: Finish
M_Counter Top w Sink Hole:600mm Depth:600mm Depth:424614:1 | 1B04 | PSet_Revit_Dimensions - Length: 4.35711 m; Sink Location: 0.751909 m; Sink Location To Wall: 0.1 m; Sink Opening Depth: 0.378 m; Sink Opening Width: 0.587 m; PSet_Revit_Phasing - Phase Created: New Construction; PSet_Revit_Other - InstallationDate: InstallationDate; SerialNumber: SerialNumber; WarrantyStartDate: WarrantyStartDate; BarCode: BarCode; AssetIdentifier: AssetIdentifier; TagNumber: TagNumber; PSet_Revit_Type_Other - AccessibilityPerformance: AccessibilityPerformance; CodePerformance: CodePerformance; Color: Color; Constituents: Constituents; Features: Features; Finish: Finish; Grade: Grade; Material: Material; ModelReference: ModelReference; NominalHeight: NominalHeight; NominalLength: NominalLength; NominalWidth: NominalWidth; ProductionYear: ProductionYear; Reference: Reference; Shape: Shape; Size: Size; SustainabilityPerformance: SustainabilityPerformance; WarrantyDescription: WarrantyDescription; WarrantyDurationLabor: WarrantyDurationLabor; WarrantyDurationParts: WarrantyDurationParts; WarrantyGuarantorLabor: WarrantyGuarantorLabor; WarrantyGuarantorParts: WarrantyGuarantorParts; ExpectedLife: ExpectedLife; ReplacementCost: ReplacementCost; AssetAccountingType: FIXED; ModelLabel: ModelLabel; Area: Area; PSet_Revit_Type_Identity Data - Manufacturer: Manufacturer; OmniClass Number: 23.40.35.17.47.11; OmniClass Title: Kitchen Casework; PSet_Revit_Constraints - Level: First Floor; Host: Level : First Floor; Offset: 0 m; Moves With Nearby Elements: no; PSet_Revit_Type_Dimensions - Counter Thickness: 0.04 m; Depth: 0.625 m; Height: 0.9 m; PSet_Revit_Type_Construction - Construction Type: Construction Type; PSet_Revit_Type_Materials and Finishes - Finish: Finish
M_Counter Top w Sink Hole:600mm Depth:600mm Depth:426758:1 | 2A08 | PSet_Revit_Dimensions - Length: 2.10996 m; Sink Location: 0.338951 m; Sink Location To Wall: 0.1 m; Sink Opening Depth: 0.378 m; Sink Opening Width: 0.3556 m; PSet_Revit_Phasing - Phase Created: New Construction; PSet_Revit_Other - InstallationDate: InstallationDate; SerialNumber: SerialNumber; WarrantyStartDate: WarrantyStartDate; BarCode: BarCode; AssetIdentifier: AssetIdentifier; TagNumber: TagNumber; PSet_Revit_Type_Other - AccessibilityPerformance: AccessibilityPerformance; CodePerformance: CodePerformance; Color: Color; Constituents: Constituents; Features: Features; Finish: Finish; Grade: Grade; Material: Material; ModelReference: ModelReference; NominalHeight: NominalHeight; NominalLength: NominalLength; NominalWidth: NominalWidth; ProductionYear: ProductionYear; Reference: Reference; Shape: Shape; Size: Size; SustainabilityPerformance: SustainabilityPerformance; WarrantyDescription: WarrantyDescription; WarrantyDurationLabor: WarrantyDurationLabor; WarrantyDurationParts: WarrantyDurationParts; WarrantyGuarantorLabor: WarrantyGuarantorLabor; WarrantyGuarantorParts: WarrantyGuarantorParts; ExpectedLife: ExpectedLife; ReplacementCost: ReplacementCost; AssetAccountingType: FIXED; ModelLabel: ModelLabel; Area: Area; PSet_Revit_Type_Identity Data - Manufacturer: Manufacturer; OmniClass Number: 23.40.35.17.47.11; OmniClass Title: Kitchen Casework; PSet_Revit_Constraints - Level: Second Floor; Host: Level : Second Floor; Offset: 0 m; Moves With Nearby Elements: no; PSet_Revit_Type_Dimensions - Counter Thickness: 0.04 m; Depth: 0.625 m; Height: 0.9 m; PSet_Revit_Type_Construction - Construction Type: Construction Type; PSet_Revit_Type_Materials and Finishes - Finish: Finish
M_Counter Top w Sink Hole:600mm Depth:600mm Depth:426746:1 | 2A09 | PSet_Revit_Dimensions - Length: 2.10996 m; Sink Location: 0.338951 m; Sink Location To Wall: 0.1 m; Sink Opening Depth: 0.378 m; Sink Opening Width: 0.3556 m; PSet_Revit_Phasing - Phase Created: New Construction; PSet_Revit_Other - InstallationDate: InstallationDate; SerialNumber: SerialNumber; WarrantyStartDate: WarrantyStartDate; BarCode: BarCode; AssetIdentifier: AssetIdentifier; TagNumber: TagNumber; PSet_Revit_Type_Other - AccessibilityPerformance: AccessibilityPerformance; CodePerformance: CodePerformance; Color: Color; Constituents: Constituents; Features: Features; Finish: Finish; Grade: Grade; Material: Material; ModelReference: ModelReference; NominalHeight: NominalHeight; NominalLength: NominalLength; NominalWidth: NominalWidth; ProductionYear: ProductionYear; Reference: Reference; Shape: Shape; Size: Size; SustainabilityPerformance: SustainabilityPerformance; WarrantyDescription: WarrantyDescription; WarrantyDurationLabor: WarrantyDurationLabor; WarrantyDurationParts: WarrantyDurationParts; WarrantyGuarantorLabor: WarrantyGuarantorLabor; WarrantyGuarantorParts: WarrantyGuarantorParts; ExpectedLife: ExpectedLife; ReplacementCost: ReplacementCost; AssetAccountingType: FIXED; ModelLabel: ModelLabel; Area: Area; PSet_Revit_Type_Identity Data - Manufacturer: Manufacturer; OmniClass Number: 23.40.35.17.47.11; OmniClass Title: Kitchen Casework; PSet_Revit_Constraints - Level: Second Floor; Host: Level : Second Floor; Offset: 0 m; Moves With Nearby Elements: no; PSet_Revit_Type_Dimensions - Counter Thickness: 0.04 m; Depth: 0.625 m; Height: 0.9 m; PSet_Revit_Type_Construction - Construction Type: Construction Type; PSet_Revit_Type_Materials and Finishes - Finish: Finish
M_Counter Top w Sink Hole:600mm Depth:600mm Depth:426911:1 | 2A05 | PSet_Revit_Dimensions - Length: 2.10996 m; Sink Location: 0.338951 m; Sink Location To Wall: 0.1 m; Sink Opening Depth: 0.378 m; Sink Opening Width: 0.3556 m; PSet_Revit_Phasing - Phase Created: New Construction; PSet_Revit_Other - InstallationDate: InstallationDate; SerialNumber: SerialNumber; WarrantyStartDate: WarrantyStartDate; BarCode: BarCode; AssetIdentifier: AssetIdentifier; TagNumber: TagNumber; PSet_Revit_Type_Other - AccessibilityPerformance: AccessibilityPerformance; CodePerformance: CodePerformance; Color: Color; Constituents: Constituents; Features: Features; Finish: Finish; Grade: Grade; Material: Material; ModelReference: ModelReference; NominalHeight: NominalHeight; NominalLength: NominalLength; NominalWidth: NominalWidth; ProductionYear: ProductionYear; Reference: Reference; Shape: Shape; Size: Size; SustainabilityPerformance: SustainabilityPerformance; WarrantyDescription: WarrantyDescription; WarrantyDurationLabor: WarrantyDurationLabor; WarrantyDurationParts: WarrantyDurationParts; WarrantyGuarantorLabor: WarrantyGuarantorLabor; WarrantyGuarantorParts: WarrantyGuarantorParts; ExpectedLife: ExpectedLife; ReplacementCost: ReplacementCost; AssetAccountingType: FIXED; ModelLabel: ModelLabel; Area: Area; PSet_Revit_Type_Identity Data - Manufacturer: Manufacturer; OmniClass Number: 23.40.35.17.47.11; OmniClass Title: Kitchen Casework; PSet_Revit_Constraints - Level: Second Floor; Host: Level : Second Floor; Offset: 0 m; Moves With Nearby Elements: no; PSet_Revit_Type_Dimensions - Counter Thickness: 0.04 m; Depth: 0.625 m; Height: 0.9 m; PSet_Revit_Type_Construction - Construction Type: Construction Type; PSet_Revit_Type_Materials and Finishes - Finish: Finish
M_Counter Top w Sink Hole:600mm Depth:600mm Depth:424255:1 | 1D31 | PSet_Revit_Dimensions - Length: 1.2 m; Sink Location: 0.6 m; Sink Location To Wall: 0.16973 m; Sink Opening Depth: 0.391258 m; Sink Opening Width: 0.587 m; PSet_Revit_Phasing - Phase Created: New Construction; PSet_Revit_Other - InstallationDate: InstallationDate; SerialNumber: SerialNumber; WarrantyStartDate: WarrantyStartDate; BarCode: BarCode; AssetIdentifier: AssetIdentifier; TagNumber: TagNumber; PSet_Revit_Type_Other - AccessibilityPerformance: AccessibilityPerformance; CodePerformance: CodePerformance; Color: Color; Constituents: Constituents; Features: Features; Finish: Finish; Grade: Grade; Material: Material; ModelReference: ModelReference; NominalHeight: NominalHeight; NominalLength: NominalLength; NominalWidth: NominalWidth; ProductionYear: ProductionYear; Reference: Reference; Shape: Shape; Size: Size; SustainabilityPerformance: SustainabilityPerformance; WarrantyDescription: WarrantyDescription; WarrantyDurationLabor: WarrantyDurationLabor; WarrantyDurationParts: WarrantyDurationParts; WarrantyGuarantorLabor: WarrantyGuarantorLabor; WarrantyGuarantorParts: WarrantyGuarantorParts; ExpectedLife: ExpectedLife; ReplacementCost: ReplacementCost; AssetAccountingType: FIXED; ModelLabel: ModelLabel; Area: Area; PSet_Revit_Type_Identity Data - Manufacturer: Manufacturer; OmniClass Number: 23.40.35.17.47.11; OmniClass Title: Kitchen Casework; PSet_Revit_Constraints - Level: First Floor; Host: Level : First Floor; Offset: 0 m; Moves With Nearby Elements: no; PSet_Revit_Type_Dimensions - Counter Thickness: 0.04 m; Depth: 0.625 m; Height: 0.9 m; PSet_Revit_Type_Construction - Construction Type: Construction Type; PSet_Revit_Type_Materials and Finishes - Finish: Finish
M_Counter Top w Sink Hole:600mm Depth:600mm Depth:424067:1 | 1D34 | PSet_Revit_Dimensions - Length: 1.2 m; Sink Location: 0.6 m; Sink Location To Wall: 0.16973 m; Sink Opening Depth: 0.391258 m; Sink Opening Width: 0.587 m; PSet_Revit_Phasing - Phase Created: New Construction; PSet_Revit_Other - InstallationDate: InstallationDate; SerialNumber: SerialNumber; WarrantyStartDate: WarrantyStartDate; BarCode: BarCode; AssetIdentifier: AssetIdentifier; TagNumber: TagNumber; PSet_Revit_Type_Other - AccessibilityPerformance: AccessibilityPerformance; CodePerformance: CodePerformance; Color: Color; Constituents: Constituents; Features: Features; Finish: Finish; Grade: Grade; Material: Material; ModelReference: ModelReference; NominalHeight: NominalHeight; NominalLength: NominalLength; NominalWidth: NominalWidth; ProductionYear: ProductionYear; Reference: Reference; Shape: Shape; Size: Size; SustainabilityPerformance: SustainabilityPerformance; WarrantyDescription: WarrantyDescription; WarrantyDurationLabor: WarrantyDurationLabor; WarrantyDurationParts: WarrantyDurationParts; WarrantyGuarantorLabor: WarrantyGuarantorLabor; WarrantyGuarantorParts: WarrantyGuarantorParts; ExpectedLife: ExpectedLife; ReplacementCost: ReplacementCost; AssetAccountingType: FIXED; ModelLabel: ModelLabel; Area: Area; PSet_Revit_Type_Identity Data - Manufacturer: Manufacturer; OmniClass Number: 23.40.35.17.47.11; OmniClass Title: Kitchen Casework; PSet_Revit_Constraints - Level: First Floor; Host: Level : First Floor; Offset: 0 m; Moves With Nearby Elements: no; PSet_Revit_Type_Dimensions - Counter Thickness: 0.04 m; Depth: 0.625 m; Height: 0.9 m; PSet_Revit_Type_Construction - Construction Type: Construction Type; PSet_Revit_Type_Materials and Finishes - Finish: Finish
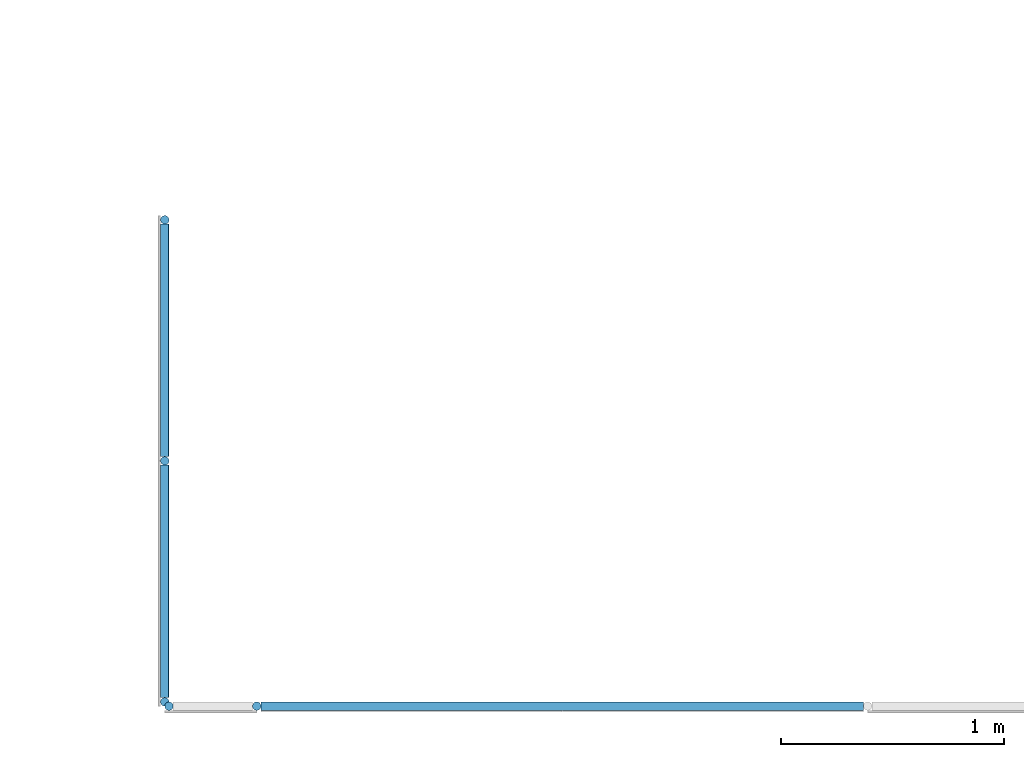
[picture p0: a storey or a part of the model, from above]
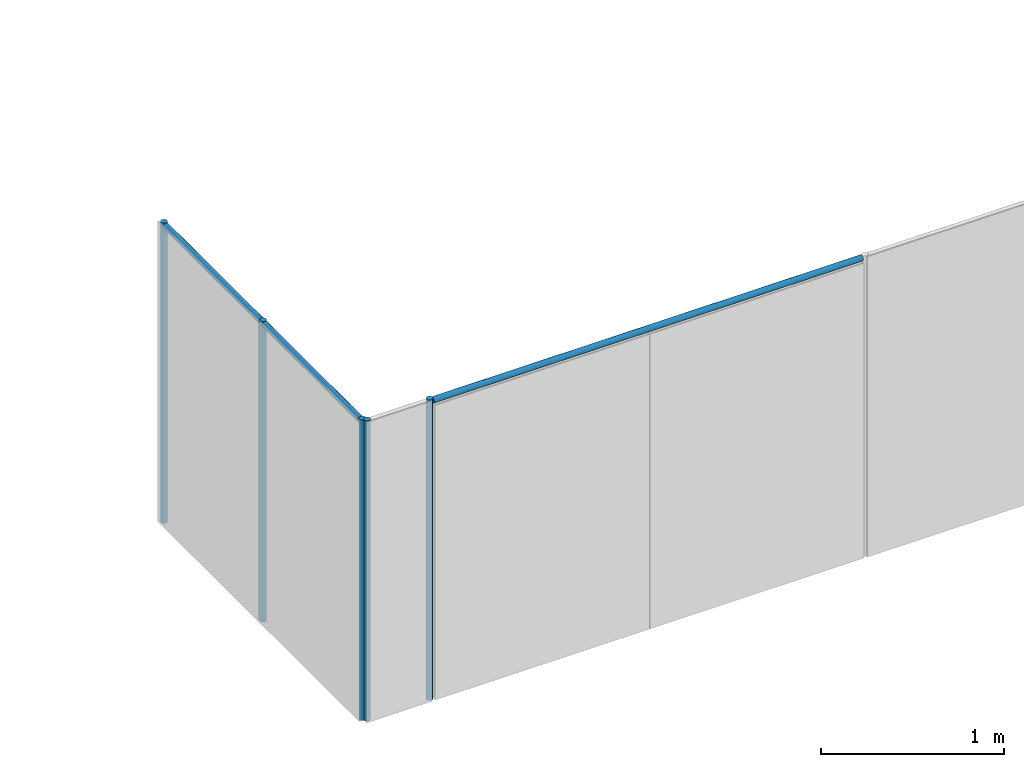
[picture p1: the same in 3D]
Properties of the parts of a building model (IFC2X3), part 8 of 11

# IfcOpeningElement: Opening (403)
Name | In
M_Counter Top w Sink Hole:600mm Depth:600mm Depth:426730:1 | 2C04 | PSet_Revit_Dimensions - Length: 2.10996 m; Sink Location: 0.338951 m; Sink Location To Wall: 0.1 m; Sink Opening Depth: 0.378 m; Sink Opening Width: 0.3556 m; PSet_Revit_Phasing - Phase Created: New Construction; PSet_Revit_Other - InstallationDate: InstallationDate; SerialNumber: SerialNumber; WarrantyStartDate: WarrantyStartDate; BarCode: BarCode; AssetIdentifier: AssetIdentifier; TagNumber: TagNumber; PSet_Revit_Type_Other - AccessibilityPerformance: AccessibilityPerformance; CodePerformance: CodePerformance; Color: Color; Constituents: Constituents; Features: Features; Finish: Finish; Grade: Grade; Material: Material; ModelReference: ModelReference; NominalHeight: NominalHeight; NominalLength: NominalLength; NominalWidth: NominalWidth; ProductionYear: ProductionYear; Reference: Reference; Shape: Shape; Size: Size; SustainabilityPerformance: SustainabilityPerformance; WarrantyDescription: WarrantyDescription; WarrantyDurationLabor: WarrantyDurationLabor; WarrantyDurationParts: WarrantyDurationParts; WarrantyGuarantorLabor: WarrantyGuarantorLabor; WarrantyGuarantorParts: WarrantyGuarantorParts; ExpectedLife: ExpectedLife; ReplacementCost: ReplacementCost; AssetAccountingType: FIXED; ModelLabel: ModelLabel; Area: Area; PSet_Revit_Type_Identity Data - Manufacturer: Manufacturer; OmniClass Number: 23.40.35.17.47.11; OmniClass Title: Kitchen Casework; PSet_Revit_Constraints - Level: Second Floor; Host: Level : Second Floor; Offset: 0 m; Moves With Nearby Elements: no; PSet_Revit_Type_Dimensions - Counter Thickness: 0.04 m; Depth: 0.625 m; Height: 0.9 m; PSet_Revit_Type_Construction - Construction Type: Construction Type; PSet_Revit_Type_Materials and Finishes - Finish: Finish
M_Counter Top w Sink Hole:600mm Depth:600mm Depth:426738:1 | 2C02 | PSet_Revit_Dimensions - Length: 2.10996 m; Sink Location: 0.338951 m; Sink Location To Wall: 0.1 m; Sink Opening Depth: 0.378 m; Sink Opening Width: 0.3556 m; PSet_Revit_Phasing - Phase Created: New Construction; PSet_Revit_Other - InstallationDate: InstallationDate; SerialNumber: SerialNumber; WarrantyStartDate: WarrantyStartDate; BarCode: BarCode; AssetIdentifier: AssetIdentifier; TagNumber: TagNumber; PSet_Revit_Type_Other - AccessibilityPerformance: AccessibilityPerformance; CodePerformance: CodePerformance; Color: Color; Constituents: Constituents; Features: Features; Finish: Finish; Grade: Grade; Material: Material; ModelReference: ModelReference; NominalHeight: NominalHeight; NominalLength: NominalLength; NominalWidth: NominalWidth; ProductionYear: ProductionYear; Reference: Reference; Shape: Shape; Size: Size; SustainabilityPerformance: SustainabilityPerformance; WarrantyDescription: WarrantyDescription; WarrantyDurationLabor: WarrantyDurationLabor; WarrantyDurationParts: WarrantyDurationParts; WarrantyGuarantorLabor: WarrantyGuarantorLabor; WarrantyGuarantorParts: WarrantyGuarantorParts; ExpectedLife: ExpectedLife; ReplacementCost: ReplacementCost; AssetAccountingType: FIXED; ModelLabel: ModelLabel; Area: Area; PSet_Revit_Type_Identity Data - Manufacturer: Manufacturer; OmniClass Number: 23.40.35.17.47.11; OmniClass Title: Kitchen Casework; PSet_Revit_Constraints - Level: Second Floor; Host: Level : Second Floor; Offset: 0 m; Moves With Nearby Elements: no; PSet_Revit_Type_Dimensions - Counter Thickness: 0.04 m; Depth: 0.625 m; Height: 0.9 m; PSet_Revit_Type_Construction - Construction Type: Construction Type; PSet_Revit_Type_Materials and Finishes - Finish: Finish
M_Counter Top w Sink Hole:600mm Depth:600mm Depth:426720:1 | 2C06 | PSet_Revit_Dimensions - Length: 2.10996 m; Sink Location: 0.338951 m; Sink Location To Wall: 0.1 m; Sink Opening Depth: 0.378 m; Sink Opening Width: 0.3556 m; PSet_Revit_Phasing - Phase Created: New Construction; PSet_Revit_Other - InstallationDate: InstallationDate; SerialNumber: SerialNumber; WarrantyStartDate: WarrantyStartDate; BarCode: BarCode; AssetIdentifier: AssetIdentifier; TagNumber: TagNumber; PSet_Revit_Type_Other - AccessibilityPerformance: AccessibilityPerformance; CodePerformance: CodePerformance; Color: Color; Constituents: Constituents; Features: Features; Finish: Finish; Grade: Grade; Material: Material; ModelReference: ModelReference; NominalHeight: NominalHeight; NominalLength: NominalLength; NominalWidth: NominalWidth; ProductionYear: ProductionYear; Reference: Reference; Shape: Shape; Size: Size; SustainabilityPerformance: SustainabilityPerformance; WarrantyDescription: WarrantyDescription; WarrantyDurationLabor: WarrantyDurationLabor; WarrantyDurationParts: WarrantyDurationParts; WarrantyGuarantorLabor: WarrantyGuarantorLabor; WarrantyGuarantorParts: WarrantyGuarantorParts; ExpectedLife: ExpectedLife; ReplacementCost: ReplacementCost; AssetAccountingType: FIXED; ModelLabel: ModelLabel; Area: Area; PSet_Revit_Type_Identity Data - Manufacturer: Manufacturer; OmniClass Number: 23.40.35.17.47.11; OmniClass Title: Kitchen Casework; PSet_Revit_Constraints - Level: Second Floor; Host: Level : Second Floor; Offset: 0 m; Moves With Nearby Elements: no; PSet_Revit_Type_Dimensions - Counter Thickness: 0.04 m; Depth: 0.625 m; Height: 0.9 m; PSet_Revit_Type_Construction - Construction Type: Construction Type; PSet_Revit_Type_Materials and Finishes - Finish: Finish
M_Counter Top w Sink Hole:600mm Depth:600mm Depth:426710:1 | 2C09 | PSet_Revit_Dimensions - Length: 2.10996 m; Sink Location: 0.338951 m; Sink Location To Wall: 0.1 m; Sink Opening Depth: 0.378 m; Sink Opening Width: 0.3556 m; PSet_Revit_Phasing - Phase Created: New Construction; PSet_Revit_Other - InstallationDate: InstallationDate; SerialNumber: SerialNumber; WarrantyStartDate: WarrantyStartDate; BarCode: BarCode; AssetIdentifier: AssetIdentifier; TagNumber: TagNumber; PSet_Revit_Type_Other - AccessibilityPerformance: AccessibilityPerformance; CodePerformance: CodePerformance; Color: Color; Constituents: Constituents; Features: Features; Finish: Finish; Grade: Grade; Material: Material; ModelReference: ModelReference; NominalHeight: NominalHeight; NominalLength: NominalLength; NominalWidth: NominalWidth; ProductionYear: ProductionYear; Reference: Reference; Shape: Shape; Size: Size; SustainabilityPerformance: SustainabilityPerformance; WarrantyDescription: WarrantyDescription; WarrantyDurationLabor: WarrantyDurationLabor; WarrantyDurationParts: WarrantyDurationParts; WarrantyGuarantorLabor: WarrantyGuarantorLabor; WarrantyGuarantorParts: WarrantyGuarantorParts; ExpectedLife: ExpectedLife; ReplacementCost: ReplacementCost; AssetAccountingType: FIXED; ModelLabel: ModelLabel; Area: Area; PSet_Revit_Type_Identity Data - Manufacturer: Manufacturer; OmniClass Number: 23.40.35.17.47.11; OmniClass Title: Kitchen Casework; PSet_Revit_Constraints - Level: Second Floor; Host: Level : Second Floor; Offset: 0 m; Moves With Nearby Elements: no; PSet_Revit_Type_Dimensions - Counter Thickness: 0.04 m; Depth: 0.625 m; Height: 0.9 m; PSet_Revit_Type_Construction - Construction Type: Construction Type; PSet_Revit_Type_Materials and Finishes - Finish: Finish
M_Single-Flush:0915 x 2134mm:0915 x 2134mm:226737:1 | First Floor
M_Single-Flush:0915 x 2134mm:0915 x 2134mm:224873:1 | First Floor
M_Single-Flush:0915 x 2134mm:0915 x 2134mm:226967:1 | First Floor
M_Single-Flush:0915 x 2134mm:0915 x 2134mm:242080:1 | Second Floor
M_Single-Flush:0915 x 2134mm:0915 x 2134mm:227199:1 | First Floor
M_Single-Flush:0915 x 2134mm:0915 x 2134mm:226489:1 | First Floor
M_Single-Flush:0915 x 2134mm:0915 x 2134mm:223773:1 | First Floor
M_Single-Flush:0915 x 2134mm:0915 x 2134mm:227455:1 | First Floor
M_Single-Flush:0915 x 2134mm Rated:0915 x 2134mm Rated:471867:1 | First Floor
M_Single-Flush:0915 x 2134mm:0915 x 2134mm:227136:1 | First Floor
M_Single-Flush:0915 x 2134mm:0915 x 2134mm:223504:1 | First Floor
M_Single-Flush:0915 x 2134mm:0915 x 2134mm:226564:1 | First Floor
M_Single-Flush:0915 x 2134mm:0915 x 2134mm:234796:1 | Second Floor
M_Single-Flush:0915 x 2134mm:0915 x 2134mm:241822:1 | Second Floor
M_Single-Flush:0915 x 2134mm:0915 x 2134mm:355218:1 | First Floor
M_Single-Flush:0915 x 2134mm:0915 x 2134mm:227926:1 | First Floor
M_Single-Flush:0915 x 2134mm:0915 x 2134mm:237365:1 | Second Floor
M_Single-Flush:0915 x 2134mm:0915 x 2134mm:236673:1 | Second Floor
M_Single-Flush:0915 x 2134mm:0915 x 2134mm:223429:1 | First Floor
M_Single-Flush:0915 x 2134mm:0915 x 2134mm:225128:1 | First Floor
M_Fixed:1735 x 1000mm:1735 x 1000mm:262059:1 | Second Floor
M_Single-Flush:0915 x 2134mm:0915 x 2134mm:223704:1 | First Floor
M_Double-Flush:1730 x 2134mm:1730 x 2134mm:367888:1 | First Floor
M_Single-Flush:0915 x 2134mm:0915 x 2134mm:223667:1 | First Floor
M_Single-Flush:0915 x 2134mm:0915 x 2134mm:242003:1 | Second Floor
M_Single-Flush:0915 x 2134mm:0915 x 2134mm:239186:1 | Second Floor
M_Single-Flush:0915 x 2134mm:0915 x 2134mm:235450:1 | Second Floor
M_Single-Flush:0915 x 2134mm:0915 x 2134mm:235326:1 | Second Floor
M_Single-Flush:0915 x 2134mm:0915 x 2134mm:225761:1 | First Floor
M_Single-Flush:0915 x 2134mm:0915 x 2134mm:241681:1 | Second Floor
M_Single-Flush:0915 x 2134mm:0915 x 2134mm:240436:1 | Second Floor
M_Single-Flush:0915 x 2134mm:0915 x 2134mm:234843:1 | Second Floor
M_Single-Flush:0915 x 2134mm:0915 x 2134mm:224653:1 | First Floor
M_Single-Flush:0915 x 2134mm:0915 x 2134mm:227830:1 | First Floor
M_Single-Flush:0915 x 2134mm:0915 x 2134mm:241789:1 | Second Floor
M_Single-Flush:0915 x 2134mm:0915 x 2134mm:226135:1 | First Floor
M_Single-Flush:0915 x 2134mm:0915 x 2134mm:223457:1 | First Floor
M_Single-Flush:0915 x 2134mm:0915 x 2134mm:227366:1 | First Floor
M_Single-Flush:0915 x 2134mm:0915 x 2134mm:240845:1 | Second Floor
M_Single-Flush:0915 x 2134mm:0915 x 2134mm:221919:1 | First Floor
M_Single-Flush:0915 x 2134mm Rated:0915 x 2134mm Rated:230209:1 | First Floor
M_Single-Flush:0915 x 2134mm:0915 x 2134mm:226850:1 | First Floor
M_Single-Flush:0915 x 2134mm:0915 x 2134mm:227615:1 | First Floor
M_Single-Flush:0915 x 2134mm:0915 x 2134mm:241191:1 | Second Floor
M_Single-Flush:0915 x 2134mm:0915 x 2134mm:241869:1 | Second Floor
M_Single-Flush:0915 x 2134mm:0915 x 2134mm:240347:1 | Second Floor
M_Single-Flush:0915 x 2134mm:0915 x 2134mm:223212:1 | First Floor
24 x :1 | First Floor
M_Double-Flush:1830 x 2134mm Exterior:1830 x 2134mm Exterior:411107:1 | Second Floor
M_Single-Flush:0915 x 2134mm:0915 x 2134mm:225828:1 | First Floor
M_Single-Flush:0915 x 2134mm:0915 x 2134mm:234926:1 | Second Floor
M_Single-Flush:0915 x 2134mm:0915 x 2134mm:225680:1 | First Floor
M_Single-Flush:0915 x 2134mm:0915 x 2134mm:242319:1 | Second Floor
M_Single-Flush:0915 x 2134mm:0915 x 2134mm:221992:1 | First Floor
M_Toilet Partition:0865 x 1500mm:0865 x 1500mm:412771:1 | First Floor
M_Single-Flush:0915 x 2134mm:0915 x 2134mm:241966:1 | Second Floor
M_Single-Flush:0915 x 2134mm:0915 x 2134mm:237452:1 | Second Floor
M_Fixed:1735 x 1000mm:1735 x 1000mm:262643:1 | Second Floor
M_Single-Flush:0915 x 2134mm:0915 x 2134mm:240928:1 | Second Floor
M_Single-Flush:0915 x 2134mm:0915 x 2134mm:226625:1 | First Floor
M_Single-Flush:0915 x 2134mm:0915 x 2134mm:225922:1 | First Floor
M_Single-Flush:0915 x 2134mm:0915 x 2134mm:241616:1 | Second Floor
M_Single-Flush:0915 x 2134mm Exterior:0915 x 2134mm Exterior:231495:1 | First Floor
M_Single-Flush:0915 x 2134mm:0915 x 2134mm:350102:1 | First Floor
M_Single-Flush:0915 x 2134mm:0915 x 2134mm:242262:1 | Second Floor
M_Single-Flush:0915 x 2134mm:0915 x 2134mm:227769:1 | First Floor
M_Single-Flush:0915 x 2134mm:0915 x 2134mm:224302:1 | First Floor
M_Single-Flush:0915 x 2134mm:0915 x 2134mm:237743:1 | Second Floor
M_Single-Flush:0915 x 2134mm:0915 x 2134mm:224980:1 | First Floor
M_Single-Flush:0915 x 2134mm:0915 x 2134mm:223301:1 | First Floor
M_Fixed:1735 x 1000mm:1735 x 1000mm:261874:1 | Second Floor
M_Single-Flush:0915 x 2134mm:0915 x 2134mm:228516:1 | First Floor
M_Fixed:1735 x 1000mm:1735 x 1000mm:261994:1 | Second Floor
M_Single-Flush:0915 x 2134mm:0915 x 2134mm:240003:1 | Second Floor
M_Single-Flush:0915 x 2134mm Exterior:0915 x 2134mm Exterior:222415:1 | First Floor
M_Fixed:1735 x 1000mm:1735 x 1000mm:253332:1 | First Floor
M_Single-Flush:0915 x 2134mm:0915 x 2134mm:364769:1 | First Floor
M_Single-Flush:0915 x 2134mm:0915 x 2134mm:228354:1 | First Floor
M_Fixed:1735 x 1000mm:1735 x 1000mm:254158:1 | First Floor
M_Single-Flush:0915 x 2134mm:0915 x 2134mm:235194:1 | Second Floor
M_Fixed:1735 x 1000mm:1735 x 1000mm:262138:1 | Second Floor
M_Single-Flush:0915 x 2134mm:0915 x 2134mm:229120:1 | First Floor
M_Single-Flush:0915 x 2134mm:0915 x 2134mm:238617:1 | Second Floor
M_Single-Flush:0915 x 2134mm:0915 x 2134mm:239326:1 | Second Floor
M_Single-Flush:0915 x 2134mm:0915 x 2134mm:227536:1 | First Floor
M_Single-Flush:0915 x 2134mm:0915 x 2134mm:240501:1 | Second Floor
M_Single-Flush:0915 x 2134mm:0915 x 2134mm:231452:1 | First Floor
M_Single-Flush:0915 x 2134mm:0915 x 2134mm:223030:1 | First Floor
M_Single-Flush:0915 x 2134mm:0915 x 2134mm:222117:1 | First Floor
M_Single-Flush:0915 x 2134mm:0915 x 2134mm:238748:1 | Second Floor
M_Fixed:1735 x 1000mm:1735 x 1000mm:261927:1 | Second Floor
M_Fixed:1735 x 1000mm:1735 x 1000mm:261637:1 | Second Floor
M_Single-Flush:0915 x 2134mm:0915 x 2134mm:240310:1 | Second Floor
M_Single-Flush:0915 x 2134mm:0915 x 2134mm:222050:1 | First Floor
M_Single-Flush:1000 x 2134mm:1000 x 2134mm:230127:1 | First Floor
M_Single-Flush:0915 x 2134mm:0915 x 2134mm:235529:1 | Second Floor
M_Single-Flush:0915 x 2134mm:0915 x 2134mm:403890:1 | First Floor
M_Single-Flush:0915 x 2134mm:0915 x 2134mm:236819:1 | Second Floor
M_Single-Flush:0915 x 2134mm:0915 x 2134mm:238096:1 | Second Floor
M_Fixed:1735 x 1000mm:1735 x 1000mm:260718:1 | Second Floor
M_Fixed:1735 x 1000mm:1735 x 1000mm:254526:1 | First Floor
M_Single-Flush:0915 x 2134mm:0915 x 2134mm:236858:1 | Second Floor
M_Single-Flush:0915 x 2134mm:0915 x 2134mm:233072:1 | First Floor
M_Fixed:1735 x 1000mm:1735 x 1000mm:260236:1 | Second Floor
M_Fixed:1735 x 1000mm:1735 x 1000mm:261827:1 | Second Floor
M_Single-Flush:0915 x 2134mm:0915 x 2134mm:235137:1 | Second Floor
M_Single-Flush:0915 x 2134mm:0915 x 2134mm:241748:1 | Second Floor
M_Toilet Partition:0865 x 1500mm:0865 x 1500mm:408825:1 | Second Floor
M_Single-Flush:0915 x 2134mm:0915 x 2134mm:226204:1 | First Floor
M_Single-Flush:0915 x 2134mm:0915 x 2134mm:235604:1 | Second Floor
M_Single-Flush:0915 x 2134mm:0915 x 2134mm:224424:1 | First Floor
M_Single-Flush:0915 x 2134mm:0915 x 2134mm:239241:1 | Second Floor
M_Fixed:1735 x 1000mm:1735 x 1000mm:261267:1 | Second Floor
M_Single-Flush:0915 x 2134mm:0915 x 2134mm:231180:1 | First Floor
M_Single-Flush:0915 x 2134mm:0915 x 2134mm:240676:1 | Second Floor
M_Single-Flush:0915 x 2134mm:0915 x 2134mm:237102:1 | Second Floor
M_Single-Flush:0915 x 2134mm:0915 x 2134mm:238886:1 | Second Floor
M_Single-Flush:0915 x 2134mm:0915 x 2134mm:239511:1 | Second Floor
M_Single-Flush:0915 x 2134mm:0915 x 2134mm:236916:1 | Second Floor
M_Single-Flush:0915 x 2134mm:0915 x 2134mm:233169:1 | First Floor
M_Fixed:1735 x 1000mm:1735 x 1000mm:253076:1 | First Floor
M_Single-Flush:0915 x 2134mm:0915 x 2134mm:231041:1 | First Floor
M_Single-Flush:0915 x 2134mm:0915 x 2134mm:236780:1 | Second Floor
M_Single-Flush:0915 x 2134mm:0915 x 2134mm:240742:1 | Second Floor
M_Toilet Partition:0865 x 1500mm:0865 x 1500mm:411832:1 | First Floor
M_Fixed:1735 x 1000mm:1735 x 1000mm:253704:1 | First Floor
M_Single-Flush:0915 x 2134mm:0915 x 2134mm:227879:1 | First Floor
M_Single-Flush:0915 x 2134mm:0915 x 2134mm:225305:1 | First Floor
M_Fixed:1735 x 1000mm:1735 x 1000mm:261370:1 | Second Floor
M_Single-Flush:0915 x 2134mm:0915 x 2134mm:225472:1 | First Floor
M_Single-Flush:0915 x 2134mm:0915 x 2134mm:222344:1 | First Floor
M_Single-Flush:0915 x 2134mm:0915 x 2134mm:231274:1 | First Floor
M_Single-Flush:0915 x 2134mm:0915 x 2134mm:224469:1 | First Floor
M_Single-Flush:0915 x 2134mm:0915 x 2134mm:228981:1 | First Floor
M_Fixed:1735 x 1000mm:1735 x 1000mm:254105:1 | First Floor
M_Single-Flush:0915 x 2134mm Rated:0915 x 2134mm Rated:242185:1 | Second Floor
M_Fixed:1735 x 1000mm:1735 x 1000mm:260595:1 | Second Floor
M_Fixed:1735 x 1000mm:1735 x 1000mm:261484:1 | Second Floor
M_Toilet Partition:0865 x 1500mm:0865 x 1500mm:413234:1 | Second Floor
M_Single-Flush:0915 x 2134mm:0915 x 2134mm:238538:1 | Second Floor
M_Fixed:1735 x 1000mm:1735 x 1000mm:254052:1 | First Floor
M_Single-Flush:0915 x 2134mm:0915 x 2134mm:224561:1 | First Floor
M_Single-Flush:0915 x 2134mm:0915 x 2134mm:241124:1 | Second Floor
M_Single-Flush:0915 x 2134mm:0915 x 2134mm:233264:1 | First Floor
M_Single-Flush:0915 x 2134mm:0915 x 2134mm:223378:1 | First Floor
M_Single-Flush:0915 x 2134mm:0915 x 2134mm:229319:1 | First Floor
M_Single-Flush:0915 x 2134mm:0915 x 2134mm:238011:1 | Second Floor
M_Single-Flush:0915 x 2134mm:0915 x 2134mm:238171:1 | Second Floor
M_Single-Flush:0915 x 2134mm:0915 x 2134mm:224343:1 | First Floor
M_Fixed:1735 x 1000mm:1735 x 1000mm:261427:1 | Second Floor
M_Single-Flush:0915 x 2134mm:0915 x 2134mm:228297:1 | First Floor
M_Single-Flush:0915 x 2134mm:0915 x 2134mm:231755:1 | First Floor
M_Fixed:1735 x 1000mm:1735 x 1000mm:253561:1 | First Floor
M_Double-Flush:1830 x 2134mm:1830 x 2134mm:250360:1 | Second Floor
M_Toilet Partition:0865 x 1500mm:0865 x 1500mm:412670:1 | First Floor
M_Toilet Partition:0865 x 1500mm:0865 x 1500mm:412955:1 | Second Floor
M_Single-Flush:0915 x 2134mm:0915 x 2134mm:228897:1 | First Floor
M_Single-Flush:0915 x 2134mm:0915 x 2134mm:223137:1 | First Floor
M_Single-Flush:0915 x 2134mm:0915 x 2134mm:231651:1 | First Floor
M_Single-Flush:0915 x 2134mm:0915 x 2134mm:250515:1 | Second Floor
M_Single-Flush:0915 x 2134mm:0915 x 2134mm:230738:1 | First Floor
M_Single-Flush:0915 x 2134mm:0915 x 2134mm:239888:1 | Second Floor
M_Single-Flush:0915 x 2134mm:0915 x 2134mm:238815:1 | Second Floor
M_Single-Flush:0915 x 2134mm:0915 x 2134mm:238921:1 | Second Floor
M_Single-Flush:0915 x 2134mm:0915 x 2134mm:225883:1 | First Floor
M_Single-Flush:0915 x 2134mm:0915 x 2134mm:224600:1 | First Floor
M_Single-Flush:0915 x 2134mm:0915 x 2134mm:223840:1 | First Floor
M_Single-Flush:0915 x 2134mm:0915 x 2134mm:225517:1 | First Floor
M_Single-Flush:0915 x 2134mm:0915 x 2134mm:241266:1 | Second Floor
M_Single-Flush:0915 x 2134mm:0915 x 2134mm:229157:1 | First Floor
M_Single-Flush:0915 x 2134mm:0915 x 2134mm:250602:1 | Second Floor
M_Single-Flush:0915 x 2134mm:0915 x 2134mm:238499:1 | Second Floor
M_Single-Flush:0915 x 2134mm:0915 x 2134mm:230556:1 | First Floor
M_Single-Flush:0915 x 2134mm:0915 x 2134mm:240588:1 | Second Floor
M_Fixed:1735 x 1000mm:1735 x 1000mm:261527:1 | Second Floor
M_Single-Flush:0915 x 2134mm Exterior:0915 x 2134mm Exterior:233711:1 | First Floor
M_Fixed:1735 x 1000mm:1735 x 1000mm:261220:1 | Second Floor
M_Single-Flush:0915 x 2134mm Rated:0915 x 2134mm Rated:222571:1 | First Floor
M_Single-Flush:1.220 x 2134mm:1.220 x 2134mm:230394:1 | First Floor
M_Single-Flush:0915 x 2134mm:0915 x 2134mm:229478:1 | First Floor
M_Single-Flush:0915 x 2134mm:0915 x 2134mm:237063:1 | Second Floor
M_Single-Flush:0915 x 2134mm:0915 x 2134mm:234428:1 | Second Floor
M_Fixed:1735 x 1000mm:1735 x 1000mm:253943:1 | First Floor
M_Single-Flush:0915 x 2134mm:0915 x 2134mm:225574:1 | First Floor
M_Single-Flush:1.220 x 2134mm Exterior:1.220 x 2134mm Exterior:233580:1 | First Floor
M_Fixed:1735 x 1000mm:1735 x 1000mm:261760:1 | Second Floor
M_Single-Flush:0915 x 2134mm:0915 x 2134mm:232576:1 | First Floor
M_Fixed:1735 x 1000mm:1735 x 1000mm:262576:1 | Second Floor
M_Fixed:1735 x 1000mm:1735 x 1000mm:260833:1 | Second Floor
M_Single-Flush:0915 x 2134mm:0915 x 2134mm:225051:1 | First Floor
M_Single-Flush:0915 x 2134mm:0915 x 2134mm:241049:1 | Second Floor
M_Single-Flush:0915 x 2134mm:0915 x 2134mm:228575:1 | First Floor
M_Single-Flush:0915 x 2134mm:0915 x 2134mm:239590:1 | Second Floor
M_Fixed:1735 x 1000mm:1735 x 1000mm:254638:1 | First Floor
M_Single-Flush:0915 x 2134mm:0915 x 2134mm:239432:1 | Second Floor
M_Fixed:1735 x 1000mm:1735 x 1000mm:260974:1 | Second Floor
M_Single-Flush:0915 x 2134mm:0915 x 2134mm:241581:1 | Second Floor
M_Single-Flush:0915 x 2134mm Exterior:0915 x 2134mm Exterior:252490:1 | First Floor
M_Single-Flush:0915 x 2134mm Exterior:0915 x 2134mm Exterior:252441:1 | First Floor
M_Single-Flush:0915 x 2134mm:0915 x 2134mm:232467:1 | First Floor
M_Single-Flush:0915 x 2134mm:0915 x 2134mm:228938:1 | First Floor
M_Double-Flush:1830 x 2134mm Exterior:1830 x 2134mm Exterior:252860:1 | First Floor
M_Single-Flush:0915 x 2134mm:0915 x 2134mm:402047:1 | First Floor
M_Fixed:1735 x 1000mm:1735 x 1000mm:260209:1 | Second Floor
M_Fixed:1735 x 1000mm:1735 x 1000mm:261025:1 | Second Floor
M_Single-Flush:0915 x 2134mm:0915 x 2134mm:228650:1 | First Floor
13 x :1 | Second Floor
M_Fixed:1735 x 1000mm:1735 x 1000mm:261584:1 | Second Floor
M_Single-Flush:0915 x 2134mm:0915 x 2134mm:222929:1 | First Floor
M_Single-Flush:0915 x 2134mm:0915 x 2134mm:237928:1 | Second Floor
M_Single-Flush:0915 x 2134mm:0915 x 2134mm:239113:1 | Second Floor
M_Fixed:1735 x 1000mm:1735 x 1000mm:254583:1 | First Floor
M_Fixed:1735 x 1000mm:1735 x 1000mm:260343:1 | Second Floor
M_Single-Flush:0915 x 2134mm:0915 x 2134mm:237881:1 | Second Floor
M_Single-Flush:0915 x 2134mm:0915 x 2134mm:239694:1 | Second Floor
M_Single-Flush:0915 x 2134mm:0915 x 2134mm:232388:1 | First Floor
M_Fixed:1735 x 1000mm:1735 x 1000mm:254752:1 | First Floor
M_Single-Flush:0915 x 2134mm:0915 x 2134mm:231213:1 | First Floor
M_Single-Flush:0915 x 2134mm:0915 x 2134mm:232239:1 | First Floor
M_Single-Flush:0915 x 2134mm:0915 x 2134mm:230994:1 | First Floor
M_Single-Flush:0915 x 2134mm:0915 x 2134mm:230949:1 | First Floor
M_Single-Flush:0915 x 2134mm:0915 x 2134mm:232087:1 | First Floor
M_Single-Flush:0915 x 2134mm:0915 x 2134mm:231377:1 | First Floor
M_Double-Flush:1830 x 2134mm Exterior:1830 x 2134mm Exterior:252102:1 | First Floor
M_Fixed:1735 x 1000mm:1735 x 1000mm:260452:1 | Second Floor
M_Single-Flush:0915 x 2134mm:0915 x 2134mm:231990:1 | First Floor
M_Single-Flush:0915 x 2134mm:0915 x 2134mm:224207:1 | First Floor
M_Single-Flush:0915 x 2134mm:0915 x 2134mm:239799:1 | Second Floor
M_Single-Flush:0915 x 2134mm:0915 x 2134mm:230814:1 | First Floor
M_Fixed:1735 x 1000mm:1735 x 1000mm:254683:1 | First Floor
M_Single-Flush:0915 x 2134mm:0915 x 2134mm:222740:1 | First Floor
M_Single-Flush:0915 x 2134mm:0915 x 2134mm:232292:1 | First Floor
M_Single-Flush:0915 x 2134mm:0915 x 2134mm:230607:1 | First Floor
M_Single-Flush:0915 x 2134mm:0915 x 2134mm:250444:1 | Second Floor
M_Single-Flush:0915 x 2134mm:0915 x 2134mm:229578:1 | First Floor
M_Toilet Partition:0865 x 1500mm:0865 x 1500mm:413317:1 | Second Floor
M_Single-Flush:0915 x 2134mm:0915 x 2134mm:229354:1 | First Floor
M_Single-Flush:0915 x 2134mm:0915 x 2134mm:223957:1 | First Floor
M_Single-Flush:0915 x 2134mm:0915 x 2134mm:229427:1 | First Floor
M_Single-Flush:0915 x 2134mm Exterior:0915 x 2134mm Exterior:231622:1 | First Floor
M_Single-Flush:0915 x 2134mm Rated:0915 x 2134mm Rated:234664:1 | Second Floor
M_Fixed:1735 x 1000mm:1735 x 1000mm:260015:1 | Second Floor
M_Single-Flush:0915 x 2134mm:0915 x 2134mm:232154:1 | First Floor
M_Single-Flush:0915 x 2134mm:0915 x 2134mm:232789:1 | First Floor
M_Fixed:1735 x 1000mm:1735 x 1000mm:259285:1 | Second Floor
M_Fixed:1735 x 1000mm:1735 x 1000mm:262496:1 | Second Floor
M_Fixed:1735 x 1000mm:1735 x 1000mm:259348:1 | Second Floor
M_Single-Flush:0915 x 2134mm:0915 x 2134mm:239639:1 | Second Floor
M_Single-Flush:0915 x 2134mm:0915 x 2134mm:239383:1 | Second Floor
M_Single-Flush:0915 x 2134mm:0915 x 2134mm:234077:1 | First Floor
M_Single-Flush:0915 x 2134mm:0915 x 2134mm:236942:1 | Second Floor
M_Double-Flush:1830 x 2134mm Exterior:1830 x 2134mm Exterior:252224:1 | First Floor
M_Fixed:1735 x 1000mm:1735 x 1000mm:261080:1 | Second Floor
M_Single-Flush:0915 x 2134mm:0915 x 2134mm:232339:1 | First Floor
M_Single-Flush:0915 x 2134mm:0915 x 2134mm:229539:1 | First Floor
M_Fixed:1735 x 1000mm:1735 x 1000mm:259922:1 | Second Floor
M_Fixed:1735 x 1000mm:1735 x 1000mm:261135:1 | Second Floor
M_Single-Flush:0915 x 2134mm:0915 x 2134mm:224018:1 | First Floor
M_Fixed:1735 x 1000mm:1735 x 1000mm:259767:1 | Second Floor
M_Single-Flush:0915 x 2134mm:0915 x 2134mm:232828:1 | First Floor
M_Single-Flush:0915 x 2134mm:0915 x 2134mm:224146:1 | First Floor
M_Single-Flush:0915 x 2134mm:0915 x 2134mm:234202:1 | First Floor
M_Single-Flush:0915 x 2134mm Exterior:0915 x 2134mm Exterior:232975:1 | First Floor
M_Single-Flush:0915 x 2134mm:0915 x 2134mm:236966:1 | Second Floor
M_Fixed:1735 x 1000mm:1735 x 1000mm:259606:1 | Second Floor
M_Single-Flush:0915 x 2134mm:0915 x 2134mm:224077:1 | First Floor
M_Fixed:1735 x 1000mm:1735 x 1000mm:259543:1 | Second Floor

# IfcPlate: Chain Link Fence Panel (5)
In: First Floor
Type - ElementType: Chain Link Fence Panel; PredefinedType: CURTAIN_PANEL
Material: Metal - Chain Link
PSet_Revit_Phasing - Phase Created: New Construction
PSet_Revit_Dimensions - Height: 2 m
PSet_Revit_Other - InstallationDate: InstallationDate; SerialNumber: SerialNumber; WarrantyStartDate: WarrantyStartDate; BarCode: BarCode; AssetIdentifier: AssetIdentifier; TagNumber: TagNumber
PSet_Revit_Type_Construction - Construction Type: Construction Type
PSet_Revit_Type_Dimensions - Thickness: 0.008 m
PSet_Revit_Type_Identity Data - Manufacturer: Manufacturer
PSet_Revit_Type_Constraints - Offset: 0.025 m
PSet_Revit_Type_Materials and Finishes - Material: Metal - Chain Link; Finish: Finish
PSet_Revit_Type_Other - AccessibilityPerformance: AccessibilityPerformance; CodePerformance: CodePerformance; Color: Color; Constituents: Constituents; Features: Features; Finish: Finish; Grade: Grade; Material: Material; ModelReference: ModelReference; NominalHeight: NominalHeight; NominalLength: NominalLength; NominalWidth: NominalWidth; ProductionYear: ProductionYear; Reference: Reference; Shape: Shape; Size: Size; SustainabilityPerformance: SustainabilityPerformance; WarrantyDescription: WarrantyDescription; WarrantyDurationLabor: WarrantyDurationLabor; WarrantyDurationParts: WarrantyDurationParts; WarrantyGuarantorLabor: WarrantyGuarantorLabor; WarrantyGuarantorParts: WarrantyGuarantorParts; ExpectedLife: ExpectedLife; ReplacementCost: ReplacementCost; AssetAccountingType: FIXED; ModelLabel: ModelLabel
Name (System Panel:Chain Link Fence Panel:Chain Link Fence Panel:...) | Area (m2) | Width (m)
346964 | 0.825153 | 0.412576
346971 | 2.12074 | 1.06037
346975 | 3.29826 | 1.64913
347581 | 2.2 | 1.1
347585 | 2.2 | 1.1

# IfcPlate: Glazed (167)
Type - ElementType: Glazed; PredefinedType: CURTAIN_PANEL
Material: Glass
PSet_Revit_Other - InstallationDate: InstallationDate; SerialNumber: SerialNumber; WarrantyStartDate: WarrantyStartDate; BarCode: BarCode; AssetIdentifier: AssetIdentifier; TagNumber: TagNumber
PSet_Revit_Phasing - Phase Created: New Construction
PSet_Revit_Type_Identity Data - Manufacturer: Manufacturer
PSet_Revit_Type_Other - AccessibilityPerformance: AccessibilityPerformance; CodePerformance: CodePerformance; Color: Color; Constituents: Constituents; Features: Features; Finish: Finish; Grade: Grade; Material: Material; ModelReference: ModelReference; NominalHeight: NominalHeight; NominalLength: NominalLength; NominalWidth: NominalWidth; ProductionYear: ProductionYear; Reference: Reference; Shape: Shape; Size: Size; SustainabilityPerformance: SustainabilityPerformance; WarrantyDescription: WarrantyDescription; WarrantyDurationLabor: WarrantyDurationLabor; WarrantyDurationParts: WarrantyDurationParts; WarrantyGuarantorLabor: WarrantyGuarantorLabor; WarrantyGuarantorParts: WarrantyGuarantorParts; ExpectedLife: ExpectedLife; ReplacementCost: ReplacementCost; AssetAccountingType: FIXED; ModelLabel: ModelLabel
PSet_Revit_Type_Construction - Construction Type: Construction Type
PSet_Revit_Type_Materials and Finishes - Material: Glass; Finish: Finish
PSet_Revit_Type_Dimensions - Thickness: 0.025 m
PSet_Revit_Type_Constraints - Offset: 0.037 m
Name (System Panel:Glazed:Glazed:...) | In | Area (m2) | Width (m) | Height (m)
356368 | First Floor | 0.7335 | 0.815 | 0.9
281035 | Second Floor | 3.04721 | 1.32488 | 2.3
281405 | Second Floor | 3.30289 | 1.43604 | 2.3
295598 | Second Floor | 1.72396
381888 | Roof - Main | 0.920172 | 1.24667 | 0.738106
381876 | Roof - Main | 1.13683 | 1.24667 | 0.911894
281031 | Second Floor | 3.10471 | 1.34988 | 2.3
281033 | Second Floor | 3.10471 | 1.34988 | 2.3
379242 | Second Floor | 2.69719 | 1.17269 | 2.3
379246 | Second Floor | 2.63969 | 1.14769 | 2.3
381878 | Roof - Main | 1.11403 | 1.22167 | 0.911894
281403 | Second Floor | 3.36039 | 1.46104 | 2.3
281401 | Second Floor | 3.36039 | 1.46104 | 2.3
285998 | Second Floor | 2.69719 | 1.17269 | 2.3
281382 | Second Floor | 3.30289 | 1.43604 | 2.3
304460 | Roof - Main | 1.82611
295591 | Second Floor | 1.72396
304459 | Roof - Main | 1.82612
281025 | Second Floor | 3.10471 | 1.34988 | 2.3
285996 | Second Floor | 2.69719 | 1.17269 | 2.3
301676 | Roof - Main | 1.13476 | 1.2444 | 0.911894
381884 | Roof - Main | 0.982418 | 1.331 | 0.738106
303254 | Roof - Main | 0.920172 | 1.24667 | 0.738106
283657 | First Floor | 2.32887 | 1.00167 | 2.325
381889 | Roof - Main | 0.901719 | 1.22167 | 0.738106
281016 | Second Floor | 3.04721 | 1.32488 | 2.3
258060 | First Floor | 1.41987 | 0.925 | 1.535
283660 | First Floor | 0.333667 | 1.02667 | 0.325
381972 | Roof - Main | 0.963966 | 1.306 | 0.738106
381868 | Roof - Main | 1.21373 | 1.331 | 0.911894
263361 | First Floor | 2.17387 | 0.935 | 2.325
303241 | Roof - Main | 1.13683 | 1.24667 | 0.911894
281023 | Second Floor | 3.10471 | 1.34988 | 2.3
303243 | Roof - Main | 1.11403 | 1.22167 | 0.911894
381960 | Roof - Main | 1.11403 | 1.22167 | 0.911894
283659 | First Floor | 0.325542 | 1.00167 | 0.325
381885 | Roof - Main | 0.982418 | 1.331 | 0.738106
298275 | Roof - Main | 1.85755
303255 | Roof - Main | 0.901719 | 1.22167 | 0.738106
379244 | Second Floor | 2.69719 | 1.17269 | 2.3
263356 | First Floor | 2.17387 | 0.935 | 2.325
283651 | First Floor | 2.32887 | 1.00167 | 2.325
285991 | Second Floor | 2.63969 | 1.14769 | 2.3
257004 | First Floor | 2.22614 | 1.45026 | 1.535
381813 | Roof - Main | 1.84672
298273 | Roof - Main | 1.84672
298271 | Roof - Main | 1.78793
301694 | Roof - Main | 1.73032 | 1.2694 | 1.36311
301695 | Roof - Main | 1.69394
301691 | Roof - Main | 1.73032 | 1.2694 | 1.36311
379206 | Second Floor | 3.04491 | 1.32388 | 2.3
301684 | Roof - Main | 1.15755 | 1.2694 | 0.911894
303248 | Roof - Main | 0.900489 | 1.22 | 0.738106
379240 | Second Floor | 2.63969 | 1.14769 | 2.3
381887 | Roof - Main | 0.963966 | 1.306 | 0.738106
381971 | Roof - Main | 1.19093 | 1.306 | 0.911894
286000 | Second Floor | 2.63969 | 1.14769 | 2.3
283073 | First Floor | 0.44525 | 1.37 | 0.325
258776 | First Floor | 2.18737 | 1.425 | 1.535
381811 | Roof - Main | 1.78793
281029 | Second Floor | 3.10471 | 1.34988 | 2.3
284082 | First Floor | 2.32887 | 1.00167 | 2.325
307711 | Roof - Main | 0.609917
379204 | Second Floor | 3.04491 | 1.32388 | 2.3
298269 | Roof - Main | 1.78843
283655 | First Floor | 2.387 | 1.02667 | 2.325
379214 | Second Floor | 3.04491 | 1.32388 | 2.3
283771 | First Floor | 0.264875 | 0.815 | 0.325
295596 | Second Floor | 1.61114
381870 | Roof - Main | 1.21373 | 1.331 | 0.911894
301682 | Roof - Main | 1.15755 | 1.2694 | 0.911894
303231 | Roof - Main | 1.21373 | 1.331 | 0.911894
381886 | Roof - Main | 0.982418 | 1.331 | 0.738106
283661 | First Floor | 0.325542 | 1.00167 | 0.325
301680 | Roof - Main | 1.15755 | 1.2694 | 0.911894
381874 | Roof - Main | 1.19093 | 1.306 | 0.911894
263363 | First Floor | 1.22485 | 0.935 | 1.31
257008 | First Floor | 1.41987 | 0.925 | 1.535
284573 | First Floor | 0.6228 | 0.692 | 0.9
303229 | Roof - Main | 1.11251 | 1.22 | 0.911894
264722 | First Floor | 0.014025 | 0.935 | 0.015
379216 | Second Floor | 2.98741 | 1.29888 | 2.3
301690 | Roof - Main | 1.69394
381961 | Roof - Main | 0.901719 | 1.22167 | 0.738106
301693 | Roof - Main | 1.73032 | 1.2694 | 1.36311
381862 | Roof - Main | 1.13531 | 1.245 | 0.911894
263364 | First Floor | 2.358 | 1.8 | 1.31
374932 | Roof - Main | 0.901719 | 1.22167 | 0.738106
379210 | Second Floor | 3.04491 | 1.32388 | 2.3
307710 | Roof - Main | 0.830402
300142 | Roof - Main | 1.86507
283887 | First Floor | 0.445103 | 1.36955 | 0.325
303250 | Roof - Main | 0.982418 | 1.331 | 0.738106
256999 | First Floor | 1.41987 | 0.925 | 1.535
303220 | Roof - Main | 1.11251 | 1.22 | 0.911894
283423 | First Floor | 1.89487 | 0.815 | 2.325
301688 | Roof - Main | 1.13476 | 1.2444 | 0.911894
258064 | First Floor | 2.22575 | 1.45 | 1.535
257006 | First Floor | 2.22614 | 1.45026 | 1.535
307712 | Roof - Main | 0.171878
298262 | Roof - Main | 1.85896
379208 | Second Floor | 3.04491 | 1.32388 | 2.3
283768 | First Floor | 1.89487 | 0.815 | 2.325
258062 | First Floor | 2.22575 | 1.45 | 1.535
375156 | Roof - Main | 0.963966 | 1.306 | 0.738106
283883 | First Floor | 0.976499 | 0.419999 | 2.325
381815 | Roof - Main | 1.85755
281027 | Second Floor | 3.10471 | 1.34988 | 2.3
284090 | First Floor | 2.32887 | 1.00167 | 2.325
379198 | Second Floor | 2.98741 | 1.29888 | 2.3
381809 | Roof - Main | 1.78843
303246 | Roof - Main | 0.918941 | 1.245 | 0.738106
258778 | First Floor | 1.45825 | 0.95 | 1.535
285039 | First Floor | 0.974174 | 0.418999 | 2.325
307709 | Roof - Main | 0.830402
301686 | Roof - Main | 1.15755 | 1.2694 | 0.911894
284568 | First Floor | 0.6228 | 0.692 | 0.9
264723 | First Floor | 0.027 | 1.8 | 0.015
284094 | First Floor | 0.325542 | 1.00167 | 0.325
381872 | Roof - Main | 1.21373 | 1.331 | 0.911894
264726 | First Floor | 1.17943
374931 | Roof - Main | 1.11403 | 1.22167 | 0.911894
307708 | Roof - Main | 0.609917
303251 | Roof - Main | 0.982418 | 1.331 | 0.738106
303247 | Roof - Main | 0.918941 | 1.245 | 0.738106
284093 | First Floor | 0.333667 | 1.02667 | 0.325
381864 | Roof - Main | 1.13531 | 1.245 | 0.911894
381805 | Roof - Main | 1.85896
381880 | Roof - Main | 0.900489 | 1.22 | 0.738106
303245 | Roof - Main | 0.900489 | 1.22 | 0.738106
375155 | Roof - Main | 1.19093 | 1.306 | 0.911894
303227 | Roof - Main | 1.13531 | 1.245 | 0.911894
284092 | First Floor | 0.325542 | 1.00167 | 0.325
303237 | Roof - Main | 1.19093 | 1.306 | 0.911894
300136 | Roof - Main | 1.91225
303233 | Roof - Main | 1.21373 | 1.331 | 0.911894
258066 | First Floor | 1.41987 | 0.925 | 1.535
263365 | First Floor | 1.22485 | 0.935 | 1.31
303235 | Roof - Main | 1.21373 | 1.331 | 0.911894
283426 | First Floor | 0.264875 | 0.815 | 0.325
296067 | Second Floor | 2.08124
300150 | Roof - Main | 1.91222
381860 | Roof - Main | 1.11251 | 1.22 | 0.911894
298267 | Roof - Main | 1.84829
264724 | First Floor | 0.014025 | 0.935 | 0.015
300148 | Roof - Main | 1.86505
303225 | Roof - Main | 1.13531 | 1.245 | 0.911894
264728 | First Floor | 1.17943
264727 | First Floor | 2.52727
303249 | Roof - Main | 0.982418 | 1.331 | 0.738106
303252 | Roof - Main | 0.963966 | 1.306 | 0.738106
301692 | Roof - Main | 1.73032 | 1.2694 | 1.36311
296063 | Second Floor | 2.01808
379212 | Second Floor | 3.04491 | 1.32388 | 2.3
258780 | First Floor | 2.18737 | 1.425 | 1.535
284088 | First Floor | 2.387 | 1.02667 | 2.325
381866 | Roof - Main | 1.11251 | 1.22 | 0.911894
381807 | Roof - Main | 1.84829
307707 | Roof - Main | 0.171878
381883 | Roof - Main | 0.900489 | 1.22 | 0.738106
314095 | Second Floor | 1.11108
296065 | Second Floor | 2.01713
314096 | Second Floor | 0.867788
296058 | Second Floor | 2.07949
381881 | Roof - Main | 0.918941 | 1.245 | 0.738106
314094 | Second Floor | 0.867787
381882 | Roof - Main | 0.918941 | 1.245 | 0.738106

# IfcRailing: Railing:1100mm Guard Rail (9)
PSet_Revit_Constraints - Base Offset: 0 m
Pset_RailingCommon - Reference: Railing:1100mm Guard Rail; IsExternal: no; Height: 1.1
PSet_Revit_Other - InstallationDate: InstallationDate; SerialNumber: SerialNumber; WarrantyStartDate: WarrantyStartDate; BarCode: BarCode; AssetIdentifier: AssetIdentifier; TagNumber: TagNumber
PSet_Revit_Phasing - Phase Created: New Construction
PSet_Revit_Type_Other - AccessibilityPerformance: AccessibilityPerformance; CodePerformance: CodePerformance; Color: Color; Constituents: Constituents; Features: Features; Finish: Finish; Grade: Grade; Material: Material; ModelReference: ModelReference; NominalHeight: NominalHeight; NominalLength: NominalLength; NominalWidth: NominalWidth; ProductionYear: ProductionYear; Reference: Reference; Shape: Shape; Size: Size; SustainabilityPerformance: SustainabilityPerformance; WarrantyDescription: WarrantyDescription; WarrantyDurationLabor: WarrantyDurationLabor; WarrantyDurationParts: WarrantyDurationParts; WarrantyGuarantorLabor: WarrantyGuarantorLabor; WarrantyGuarantorParts: WarrantyGuarantorParts; ExpectedLife: ExpectedLife; ReplacementCost: ReplacementCost; AssetAccountingType: FIXED; Classification Code: 23-30 80 11; Classification Description: Guardrails; ModelLabel: ModelLabel
PSet_Revit_Type_Identity Data - Manufacturer: Manufacturer
PSet_Revit_Type_Construction - Railing Height: 1.1 m; Baluster Offset: -0.025 m; Use Landing Height Adjustment: 0; Landing Height Adjustment: 0 m; Angled Joins: 0; Tangent Joins: 2; Rail Connections: 0
Name (Railing:1100mm Guard Rail:...) | In | Length (m)
250956 | First Floor | 9.70191
221234 | First Floor | 10.5256
419500 | First Floor | 1.624 | PSet_Revit_Constraints - Base Level: First Floor
250952 | First Floor | 13.6455
251724 | First Floor | 9.90791
251728 | First Floor | 13.6115
288074 | Second Floor | 6.70505 | PSet_Revit_Constraints - Base Level: Second Floor
221238 | First Floor | 13.9367
288269 | Second Floor | 6.63004 | PSet_Revit_Constraints - Base Level: Second Floor

# IfcSlab: Stair:Concrete Pan - 180mm Max Riser 280mm Tread (3)
In: First Floor
PredefinedType: LANDING
Name (Stair:Concrete Pan - 180mm Max Riser 280mm Tread:...)
251180:1
221039:1
250693:1

# IfcStair: Stair:Concrete Pan - 180mm Max Riser 280mm Tread (3)
In: First Floor
ShapeType: HALF_TURN_STAIR
Pset_StairCommon - Reference: Stair:Concrete Pan - 180mm Max Riser 280mm Tread; NumberOfRiser: 26; NumberOfTreads: 25; RiserHeight: 0.175769 m; TreadLength: 0.28 m; IsExternal: no
PSet_Revit_Dimensions - Width: 1 m; Desired Number of Risers: 26; Actual Number of Risers: 26; Actual Riser Height: 0.175769 m; Actual Tread Depth: 0.28 m
PSet_Revit_Constraints - Base Level: First Floor; Base Offset: 0 m; Top Level: Second Floor; Top Offset: 0 m
PSet_Revit_Other - InstallationDate: InstallationDate; SerialNumber: SerialNumber; WarrantyStartDate: WarrantyStartDate; BarCode: BarCode; AssetIdentifier: AssetIdentifier; TagNumber: TagNumber
PSet_Revit_Phasing - Phase Created: New Construction
PSet_Revit_Graphics - Up text: UP; Down text: DN; Up label: yes; Up arrow: yes; Down label: yes; Down arrow: yes; Show Up arrow in all views: no
PSet_Revit_Type_Construction - Extend Below Base: 0 m; Monolithic Stairs: no; Landing Overlap: 0.076 m; Underside of Winder: 1; Function: 0
PSet_Revit_Type_Identity Data - Manufacturer: Manufacturer
PSet_Revit_Type_Treads - Minimum Tread Depth: 0.28 m; Tread Thickness: 0.05 m; Nosing Length: 0 m; Apply Nosing Profile: 0
PSet_Revit_Type_Materials and Finishes - Tread Material: Concrete - Cast in Situ Lightweight; Riser Material: Concrete - Cast in Situ Lightweight; Stringer Material: Metal - Steel
PSet_Revit_Type_Risers - Maximum Riser Height: 0.18 m; Begin with Riser: yes; End with Riser: yes; Riser Type: 1; Riser Thickness: 0.0125 m; Riser to Tread Connection: 0
PSet_Revit_Type_Graphics - Break Symbol in Plan: yes; Text Size: 0.0082021; Text Font: Arial
PSet_Revit_Type_Stringers - Trim Stringers at Top: 2; Right Stringer: 1; Left Stringer: 1; Middle Stringers: 0; Stringer Thickness: 0.05 m; Stringer Height: 0.4 m; Open Stringer Offset: 0 m; Stringer Carriage Height: 0.152 m; Landing Carriage Height: 0.303271 m
PSet_Revit_Type_Other - AccessibilityPerformance: AccessibilityPerformance; CodePerformance: CodePerformance; Color: Color; Constituents: Constituents; Features: Features; Finish: Finish; Grade: Grade; Material: Material; ModelReference: ModelReference; NominalHeight: NominalHeight; NominalLength: NominalLength; NominalWidth: NominalWidth; ProductionYear: ProductionYear; Reference: Reference; Shape: Shape; Size: Size; SustainabilityPerformance: SustainabilityPerformance; WarrantyDescription: WarrantyDescription; WarrantyDurationLabor: WarrantyDurationLabor; WarrantyDurationParts: WarrantyDurationParts; WarrantyGuarantorLabor: WarrantyGuarantorLabor; WarrantyGuarantorParts: WarrantyGuarantorParts; ExpectedLife: ExpectedLife; ReplacementCost: ReplacementCost; AssetAccountingType: FIXED; Classification Code: 23-30 70 21; Classification Description: Stairs; ModelLabel: ModelLabel
Name (Stair:Concrete Pan - 180mm Max Riser 280mm Tread:...)
250693
251180
221039

# IfcStairFlight: Stair:Concrete Pan - 180mm Max Riser 280mm Tread (6)
In: First Floor
RiserHeight: 0.576671 m; TreadLength: 0.918635 m
Pset_StairFlightCommon - Reference: Stair:Concrete Pan - 180mm Max Riser 280mm Tread; RiserHeight: 0.175769 m; TreadLength: 0.28 m; TreadLengthAtInnerSide: 0.28 m; TreadLengthAtOffset: 0.28 m
Name (Stair:Concrete Pan - 180mm Max Riser 280mm Tread:...) | NumberOfRiser = Pset_StairFlightCommon, NumberOfRiser | NumberOfTreads = Pset_StairFlightCommon, NumberOfTreads | WalkingLineOffset (m) | WaistThickness (m)
221039:1 | 12 | 11 | 0.55 | 1.1
250693:2 | 14 | 13 | 0.55 | 1.1
221039:2 | 14 | 13 | 0.55 | 1.1
251180:2 | 14 | 13 | 0.525 | 1.05
250693:1 | 12 | 11 | 0.55 | 1.1
251180:1 | 12 | 11 | 0.525 | 1.05

# IfcWall: Basic Wall:Exterior - Insul Panel on Mtl. Stud:130954 (8)
Material: Insulation - Insulated Panel 0.042 m, Metal - Firring 0.038 m, Wood - Sheathing - plywood 0.019 m, Metal - Stud Layer 0.152 m, Plasterboard 0.016 m
Pset_WallCommon - Reference: Basic Wall:Exterior - Insul Panel on Mtl. Stud; LoadBearing: no; ExtendToStructure: no; IsExternal: yes
PSet_Revit_Constraints - Location Line: 2; Base is Attached: no; Base Extension Distance: 0 m; Top is Attached: no; Top Extension Distance: 0 m; Room Bounding: yes; Related to Mass: no
PSet_Revit_Other - InstallationDate: InstallationDate; SerialNumber: SerialNumber; WarrantyStartDate: WarrantyStartDate; BarCode: BarCode; AssetIdentifier: AssetIdentifier; TagNumber: TagNumber
PSet_Revit_Phasing - Phase Created: New Construction
PSet_Revit_Structural - Structural Usage: 0
PSet_Revit_Type_Other - AccessibilityPerformance: AccessibilityPerformance; CodePerformance: CodePerformance; Color: Color; Constituents: Constituents; Features: Features; Finish: Finish; Grade: Grade; Material: Material; ModelReference: ModelReference; NominalHeight: NominalHeight; NominalLength: NominalLength; NominalWidth: NominalWidth; ProductionYear: ProductionYear; Reference: Reference; Shape: Shape; Size: Size; SustainabilityPerformance: SustainabilityPerformance; WarrantyDescription: WarrantyDescription; WarrantyDurationLabor: WarrantyDurationLabor; WarrantyDurationParts: WarrantyDurationParts; WarrantyGuarantorLabor: WarrantyGuarantorLabor; WarrantyGuarantorParts: WarrantyGuarantorParts; ExpectedLife: ExpectedLife; ReplacementCost: ReplacementCost; AssetAccountingType: FIXED; Classification Code: 23-25 30 24 21; Classification Description: Metal Framed Structural Walls; ModelLabel: ModelLabel
PSet_Revit_Type_Construction - Wrapping at Inserts: 0; Wrapping at Ends: 1; Width: 0.267 m; Function: 1
PSet_Revit_Type_Graphics - Coarse Scale Fill Color: 0
PSet_Revit_Type_Identity Data - Manufacturer: Manufacturer
Name (Basic Wall:Exterior - Insul Panel on Mtl. Stud:...) | In | Base Constraint | Base Offset (m) | Unconnected Height (m) | Top Offset (m) | Length (m) | Area (m2) | Volume (m3)
307047 | Roof - Main | Roof - Main | 0.12 | 2.9082 | -0.102 | 10.312 | 15.3269 | 4.09231
375598 | Roof - Main | Roof - Main | 0.12 | 2.9082 | -0.102 | 1.03444 | 2.6818 | 0.716042
381984 | Roof - Main | Roof - Main | 0.12 | 2.9082 | -0.102 | 1.03444 | 2.6818 | 0.716042
307686 | Roof - Main | Roof - Main | 0.12 | 2.9082 | -0.102 | 1 | 2.17687 | 0.581223
307184 | Roof - Main | Roof - Main | 0.12 | 2.9082 | -0.102 | 1 | 2.17687 | 0.581223
381982 | Roof - Main | Roof - Main | 0.12 | 2.9082 | -0.102 | 1 | 2.9673 | 0.79227
375596 | Roof - Main | Roof - Main | 0.12 | 2.9082 | -0.102 | 1 | 2.9673 | 0.79227
290055 | Second Floor | Second Floor | 2.1915 | 1.697 | -0.7915 | 9.10423 | 16.7496 | 4.47214 | PSet_Revit_Constraints - Top Constraint: Up to level: Roof - Main

# IfcWall: Basic Wall:Interior - Furring (38 mm Stud):128404, Basic Wall:Interior - Furring (38 mm Stud):396777
In: Second Floor
Material: Metal - Stud Layer 0.038 m, Plasterboard 0.016 m
Pset_WallCommon - Reference: Basic Wall:Interior - Furring (38 mm Stud); LoadBearing: no; ExtendToStructure: no; IsExternal: no
PSet_Revit_Phasing - Phase Created: New Construction
PSet_Revit_Constraints - Location Line: 3; Base Constraint: Second Floor; Base Offset: 1.55 m; Base is Attached: no; Base Extension Distance: 0 m; Top Constraint: Up to level: Roof - Main; Unconnected Height: 1.8165 m; Top Offset: -1.3135 m; Top is Attached: no; Top Extension Distance: 0 m; Room Bounding: yes; Related to Mass: no
PSet_Revit_Other - InstallationDate: InstallationDate; SerialNumber: SerialNumber; WarrantyStartDate: WarrantyStartDate; BarCode: BarCode; AssetIdentifier: AssetIdentifier; TagNumber: TagNumber
PSet_Revit_Structural - Structural Usage: 0
PSet_Revit_Dimensions - Length: 4.005 m; Area: 7.11341 m2; Volume: 0.374752 m3
PSet_Revit_Type_Other - AccessibilityPerformance: AccessibilityPerformance; CodePerformance: CodePerformance; Color: Color; Constituents: Constituents; Features: Features; Finish: Finish; Grade: Grade; Material: Material; ModelReference: ModelReference; NominalHeight: NominalHeight; NominalLength: NominalLength; NominalWidth: NominalWidth; ProductionYear: ProductionYear; Reference: Reference; Shape: Shape; Size: Size; SustainabilityPerformance: SustainabilityPerformance; WarrantyDescription: WarrantyDescription; WarrantyDurationLabor: WarrantyDurationLabor; WarrantyDurationParts: WarrantyDurationParts; WarrantyGuarantorLabor: WarrantyGuarantorLabor; WarrantyGuarantorParts: WarrantyGuarantorParts; ExpectedLife: ExpectedLife; ReplacementCost: ReplacementCost; AssetAccountingType: FIXED; Classification Code: 23-25 40 11 11 11; Classification Description: Metal-Framed Gypsum Board Fixed Partitions; ModelLabel: ModelLabel
PSet_Revit_Type_Graphics - Coarse Scale Fill Color: 0
PSet_Revit_Type_Construction - Wrapping at Inserts: 0; Wrapping at Ends: 0; Width: 0.054 m; Function: 0
PSet_Revit_Type_Identity Data - Manufacturer: Manufacturer

# IfcWall: Basic Wall:Interior - Partition (92mm Stud):128360 (6)
Material: Plasterboard 0.016 m, Metal - Stud Layer 0.092 m, Plasterboard 0.016 m
Pset_WallCommon - Reference: Basic Wall:Interior - Partition (92mm Stud); LoadBearing: no; ExtendToStructure: no; IsExternal: no
PSet_Revit_Phasing - Phase Created: New Construction
PSet_Revit_Constraints - Location Line: 2; Base is Attached: no; Base Extension Distance: 0 m; Top is Attached: no; Top Extension Distance: 0 m; Room Bounding: yes; Related to Mass: no
PSet_Revit_Other - InstallationDate: InstallationDate; SerialNumber: SerialNumber; WarrantyStartDate: WarrantyStartDate; BarCode: BarCode; AssetIdentifier: AssetIdentifier; TagNumber: TagNumber
PSet_Revit_Structural - Structural Usage: 0
PSet_Revit_Type_Identity Data - Manufacturer: Manufacturer
PSet_Revit_Type_Graphics - Coarse Scale Fill Color: 0
PSet_Revit_Type_Other - AccessibilityPerformance: AccessibilityPerformance; CodePerformance: CodePerformance; Color: Color; Constituents: Constituents; Features: Features; Finish: Finish; Grade: Grade; Material: Material; ModelReference: ModelReference; NominalHeight: NominalHeight; NominalLength: NominalLength; NominalWidth: NominalWidth; ProductionYear: ProductionYear; Reference: Reference; Shape: Shape; Size: Size; SustainabilityPerformance: SustainabilityPerformance; WarrantyDescription: WarrantyDescription; WarrantyDurationLabor: WarrantyDurationLabor; WarrantyDurationParts: WarrantyDurationParts; WarrantyGuarantorLabor: WarrantyGuarantorLabor; WarrantyGuarantorParts: WarrantyGuarantorParts; ExpectedLife: ExpectedLife; ReplacementCost: ReplacementCost; AssetAccountingType: FIXED; Classification Code: 23-25 40 11 11 11; Classification Description: Metal-Framed Gypsum Board Fixed Partitions; ModelLabel: ModelLabel
PSet_Revit_Type_Construction - Wrapping at Inserts: 0; Wrapping at Ends: 2; Width: 0.124 m; Function: 0
Name (Basic Wall:Interior - Partition (92mm Stud):...) | In | Base Constraint | Base Offset (m) | Top Constraint | Unconnected Height (m) | Top Offset (m) | Length (m) | Area (m2) | Volume (m3)
314431 | First Floor | First Floor | 0.89 | Up to level: Second Floor | 3.578 | -0.102 | 1.135 | 2.16704 | 0.268713
379018 | First Floor | First Floor | 3.8 | Up to level: Second Floor | 3.77 | 3 | 1.0798 | 4.98443 | 0.61807
314078 | First Floor | First Floor | 3.8 | Up to level: Second Floor | 0.65 | -0.12 | 4.147 | 5.43461 | 0.673638
287660 | Second Floor | Second Floor | 0 | Up to level: Roof - Main | 4.578 | -0.102 | 3.836 | 16.0008 | 1.9841
287145 | First Floor | First Floor | 3.8 | Up to level: Second Floor | 3.77 | 3 | 1.0798 | 4.63209 | 0.574379
399407 | Roof - Main | Roof - Main | 0 | Up to level: Roof - Main | 4.22126 | 4.22126 | 8.31148 | 31.7988 | 3.94302

# IfcWallStandardCase: Basic Wall:Exterior - Insul Panel on Mtl. Stud:130954 (72)
Material: Insulation - Insulated Panel 0.042 m, Metal - Firring 0.038 m, Wood - Sheathing - plywood 0.019 m, Metal - Stud Layer 0.152 m, Plasterboard 0.016 m
PSet_Revit_Constraints - Base is Attached: no; Base Extension Distance: 0 m; Top is Attached: no; Top Extension Distance: 0 m; Room Bounding: yes; Related to Mass: no
Pset_WallCommon - Reference: Basic Wall:Exterior - Insul Panel on Mtl. Stud; LoadBearing: no; ExtendToStructure: no; IsExternal: yes
PSet_Revit_Phasing - Phase Created: New Construction
PSet_Revit_Structural - Structural Usage: 0
PSet_Revit_Other - InstallationDate: InstallationDate; SerialNumber: SerialNumber; WarrantyStartDate: WarrantyStartDate; BarCode: BarCode; AssetIdentifier: AssetIdentifier; TagNumber: TagNumber
PSet_Revit_Type_Other - AccessibilityPerformance: AccessibilityPerformance; CodePerformance: CodePerformance; Color: Color; Constituents: Constituents; Features: Features; Finish: Finish; Grade: Grade; Material: Material; ModelReference: ModelReference; NominalHeight: NominalHeight; NominalLength: NominalLength; NominalWidth: NominalWidth; ProductionYear: ProductionYear; Reference: Reference; Shape: Shape; Size: Size; SustainabilityPerformance: SustainabilityPerformance; WarrantyDescription: WarrantyDescription; WarrantyDurationLabor: WarrantyDurationLabor; WarrantyDurationParts: WarrantyDurationParts; WarrantyGuarantorLabor: WarrantyGuarantorLabor; WarrantyGuarantorParts: WarrantyGuarantorParts; ExpectedLife: ExpectedLife; ReplacementCost: ReplacementCost; AssetAccountingType: FIXED; Classification Code: 23-25 30 24 21; Classification Description: Metal Framed Structural Walls; ModelLabel: ModelLabel
PSet_Revit_Type_Construction - Wrapping at Inserts: 0; Wrapping at Ends: 1; Width: 0.267 m; Function: 1
PSet_Revit_Type_Graphics - Coarse Scale Fill Color: 0
PSet_Revit_Type_Identity Data - Manufacturer: Manufacturer
Name (Basic Wall:Exterior - Insul Panel on Mtl. Stud:...) | In | Location Line | Base Constraint | Base Offset (m) | Top Constraint | Unconnected Height (m) | Top Offset (m) | Length (m) | Area (m2) | Volume (m3)
145344 | Second Floor | 2 | Second Floor | 0 | Up to level: Roof - Main | 5.137 | 0.457 | 47.493 | 224.887 | 60.0447
145481 | Second Floor | 2 | Second Floor | 0 | Up to level: Roof - Main | 5.137 | 0.457 | 40.5774 | 195.866 | 52.2962
146031 | Second Floor | 2 | Second Floor | 0 | Up to level: Roof - Main | 5.137 | 0.457 | 35.51 | 165.428 | 44.1694
144932 | Second Floor | 2 | Second Floor | 0 | Up to level: Roof - Main | 5.137 | 0.457 | 19.9665 | 90.8333 | 24.2525
309999 | Roof - Main | 2 | Roof - Main | 0 | Up to level: Roof - Main | 3.4 | 3.4 | 18.4025 | 31.9269 | 8.52447
381931 | Roof - Main | 2 | Roof - Main | 0 | Up to level: Roof - Main | 3.4 | 3.4 | 18.4025 | 31.9269 | 8.52447
142014 | First Floor | 2 | First Floor | 0 | Up to level: Second Floor | 5.027 | 0.457 | 17.0815 | 75.7958 | 20.2375
141152 | First Floor | 2 | First Floor | 0 | Up to level: Second Floor | 5.027 | 0.457 | 32.333 | 153.657 | 41.0265
144524 | Second Floor | 2 | Second Floor | 0 | Up to level: Roof - Main | 5.137 | 0.457 | 16.7065 | 75.4877 | 20.1552
140832 | First Floor | 2 | First Floor | 0 | Up to level: Second Floor | 4.57 | 0 | 20.06 | 89.9392 | 24.0138
142601 | First Floor | 2 | First Floor | 0 | Up to level: Second Floor | 4.57 | 0 | 13.338 | 56.4301 | 15.0307
140707 | First Floor | 2 | First Floor | 0 | Up to level: Second Floor | 4.57 | 0 | 16.7065 | 70.0188 | 18.695
258588 | First Floor | 2 | First Floor | 0 | Up to level: Second Floor | 5.027 | 0.457 | 13.2565 | 62.1068 | 16.5825
263032 | First Floor | 2 | First Floor | 0 | Up to level: Second Floor | 4.57 | 0 | 19.9665 | 83.182 | 22.2096
142977 | First Floor | 2 | First Floor | 0 | Up to level: Second Floor | 5.027 | 0.457 | 11.743 | 57.1532 | 15.2599
140972 | First Floor | 2 | First Floor | 0 | Up to level: Second Floor | 5.027 | 0.457 | 10.04 | 45.2661 | 12.086
143236 | First Floor | 2 | First Floor | 0 | Up to level: Second Floor | 5.027 | 0.457 | 9.07 | 44.8628 | 11.9784
268199 | First Floor | 2 | First Floor | 0 | Up to level: Second Floor | 4.57 | 0 | 3.483 | 15.3901 | 4.10914
257918 | First Floor | 2 | First Floor | 0 | Up to level: Second Floor | 5.027 | 0.457 | 4.935 | 23.0732 | 6.16055
145577 | Second Floor | 2 | Second Floor | 0 | Up to level: Roof - Main | 5.137 | 0.457 | 8.61 | 40.7596 | 10.8828
267324 | First Floor | 2 | First Floor | 3 | Up to level: Second Floor | 2.027 | 0.457 | 1.767 | 3.348 | 0.893916
142394 | First Floor | 2 | First Floor | 0 | Up to level: Second Floor | 4.57 | 0 | 6.378 | 26.2751 | 7.01545
143132 | First Floor | 2 | First Floor | 0 | Up to level: Second Floor | 3.9495 | -0.6205 | 0.965 | 3.55775 | 0.94992
145802 | Second Floor | 2 | Second Floor | 0 | Up to level: Roof - Main | 5.137 | 0.457 | 3.483 | 17.3271 | 4.62634
142496 | First Floor | 2 | First Floor | 0 | Up to level: Second Floor | 3.9495 | -0.6205 | 1.779 | 4.01903 | 1.07308
142286 | First Floor | 2 | First Floor | 0 | Up to level: Second Floor | 5.027 | 0.457 | 6.05 | 31.7556 | 8.47873
141681 | First Floor | 2 | First Floor | 0 | Up to level: Second Floor | 3.9495 | -0.6205 | 0.964 | 3.80732 | 1.01655
141763 | First Floor | 2 | First Floor | 0 | Up to level: Second Floor | 3.9495 | -0.6205 | 1.817 | 5.22363 | 1.39471
187224 | First Floor | 2 | First Floor | 0 | Up to level: Second Floor | 4.468 | -0.102 | 6.033 | 23.0502 | 6.15441
142721 | First Floor | 2 | First Floor | 0 | Up to level: Second Floor | 3.9495 | -0.6205 | 1.792 | 4.07038 | 1.08679
142525 | First Floor | 2 | First Floor | 0 | Up to level: Second Floor | 3.9495 | -0.6205 | 0.36 | 2.47634 | 0.661182
293670 | Second Floor | 2 | Second Floor | 0 | Up to level: Second Floor | 2.64 | 2.64 | 2.7445 | 7.41764 | 1.98051
145747 | Second Floor | 2 | Second Floor | 0 | Up to level: Roof - Main | 5.137 | 0.457 | 6.01556 | 30.9019 | 8.25082
384376 | Second Floor | 2 | Second Floor | 0 | Up to level: Second Floor | 2.64 | 2.64 | 2.7445 | 7.39046 | 1.97325
256419 | First Floor | 2 | First Floor | 0 | Up to level: Second Floor | 5.027 | 0.457 | 2.5365 | 13.2782 | 3.54529
258057 | First Floor | 2 | First Floor | 0 | Up to level: First Floor | 0.905 | 0.905 | 5 | 4.525 | 1.20817
267401 | First Floor | 2 | First Floor | 3 | Up to level: Second Floor | 1.57 | 0 | 1.779 | 2.53951 | 0.67805
256262 | First Floor | 2 | First Floor | 0 | Up to level: First Floor | 0.905 | 0.905 | 5.00051 | 4.52546 | 1.2083
141634 | First Floor | 2 | First Floor | 0 | Up to level: Second Floor | 5.027 | 0.457 | 3.00599 | 14.44 | 3.85548
143026 | First Floor | 2 | First Floor | 0 | Up to level: Second Floor | 3.9495 | -0.6205 | 0.965 | 3.81127 | 1.01761
267487 | First Floor | 2 | First Floor | 3 | Up to level: Second Floor | 1.57 | 0 | 1.792 | 2.55992 | 0.6835
143081 | First Floor | 2 | First Floor | 0 | Up to level: Second Floor | 3.9495 | -0.6205 | 1.657 | 4.59171 | 1.22599
142840 | First Floor | 2 | First Floor | 0 | Up to level: Second Floor | 4.57 | 0 | 3.153 | 13.2719 | 3.54359
141807 | First Floor | 2 | First Floor | 0 | Up to level: Second Floor | 3.9495 | -0.6205 | 0.964 | 3.80732 | 1.01655
258773 | First Floor | 2 | First Floor | 0 | Up to level: First Floor | 0.905 | 0.905 | 4 | 3.62 | 0.96654
256655 | First Floor | 2 | First Floor | 2.54 | Up to level: Second Floor | 2.487 | 0.457 | 5.00051 | 12.4363 | 3.32049
267608 | First Floor | 2 | First Floor | 3 | Up to level: Second Floor | 2.027 | 0.457 | 1.817 | 3.42954 | 0.915688
258058 | First Floor | 2 | First Floor | 2.54 | Up to level: Second Floor | 2.487 | 0.457 | 5 | 12.435 | 3.32015
186606 | First Floor | 2 | First Floor | 0 | Up to level: Second Floor | 4.468 | -0.102 | 6.033 | 25.0028 | 6.67576
187053 | First Floor | 2 | First Floor | 0 | Up to level: Second Floor | 4.468 | -0.102 | 2.044 | 5.33616 | 1.42475
307687 | Roof - Main | 2 | Roof - Main | 0.12 |  | 2.9082 | -0.102 | 0.241454 | 1.09044 | 0.291147
297616 | Roof - Main | 2 | Roof - Main | 0 |  | 1.35083 | -0.102 | 6.8035 | 9.19036 | 2.09499
258774 | First Floor | 2 | First Floor | 2.54 | Up to level: Second Floor | 2.487 | 0.457 | 4 | 9.948 | 2.65612
381803 | Roof - Main | 2 | Roof - Main | 0 |  | 1.35083 | -0.102 | 6.8035 | 9.19036 | 2.09499
142426 | First Floor | 2 | First Floor | 0 | Up to level: Second Floor | 3.9495 | -0.6205 | 0.36 | 2.47634 | 0.661182
142629 | First Floor | 2 | First Floor | 0 | Up to level: Second Floor | 3.9495 | -0.6205 | 0.36 | 2.47634 | 0.661182
145867 | Second Floor | 2 | Second Floor | 0 | Up to level: Roof - Main | 5.137 | 0.457 | 6.05 | 31.0788 | 8.29805
307295 | Roof - Main | 2 | Roof - Main | 0.12 |  | 3.3 | -0.102 | 0.241454 | 1.23735 | 0.330372
376077 | Roof - Main | 2 | Roof - Main | 1.67814 |  | 1.74186 | -0.102 | 1.12108 | 1.72023 | 0.459301
142775 | First Floor | 2 | First Floor | 0 | Up to level: Second Floor | 3.9495 | -0.6205 | 0.36 | 2.47634 | 0.661182
307685 | Roof - Main | 2 | Roof - Main | 0.12 |  | 2.9082 | -0.102 | 1.83905 | 6.12479 | 1.63532
307120 | Roof - Main | 2 | Roof - Main | 0.12 |  | 2.9082 | -0.102 | 1.83905 | 5.34831 | 1.428
376708 | Second Floor | 0 | Second Floor | 3.4865 | Up to level: Roof - Main | 2.5435 | 1.35 | 1.07919 | 1.18262 | 0.31576
378843 | Second Floor | 2 | Second Floor | 2.1915 | Up to level: Roof - Main | 1.697 | -0.7915 | 9.10423 | 16.4162 | 4.38313
382036 | Second Floor | 0 | Second Floor | 3.4865 | Up to level: Roof - Main | 2.5435 | 1.35 | 1.08869 | 1.35432 | 0.361602
382926 | Roof - Main | 2 | Roof - Main | 1.67814 |  | 1.74186 | -0.102 | 1.12108 | 1.72023 | 0.459301
290066 | Second Floor | 2 | Second Floor | 3.4865 | Up to level: Roof - Main | 1.6505 | 0.457 | 15.343 | 26.423 | 7.05495
375597 | Roof - Main | 2 | Roof - Main | 0.12 |  | 2.9082 | -0.102 | 1.83905 | 5.34831 | 1.428
381802 | Second Floor | 2 | Second Floor | 3.4865 | Up to level: Roof - Main | 1.6505 | 0.457 | 15.343 | 26.423 | 7.05495
381983 | Roof - Main | 2 | Roof - Main | 0.12 |  | 2.9082 | -0.102 | 1.83905 | 5.34831 | 1.428
384186 | Second Floor | 2 | Second Floor | 2.1915 | Up to level: Second Floor | 0.8785 | 3.07 | 0.886 | 0.778351 | 0.111304
383730 | Second Floor | 2 | Second Floor | 2.1915 | Up to level: Second Floor | 0.8785 | 3.07 | 1.0195 | 0.778351 | 0.111304

# IfcWallStandardCase: Basic Wall:Interior - Furring (152 mm Stud):138413 (30)
Material: Metal - Stud Layer 0.152 m, Plasterboard 0.016 m
Pset_WallCommon - Reference: Basic Wall:Interior - Furring (152 mm Stud); LoadBearing: no; ExtendToStructure: no; IsExternal: no
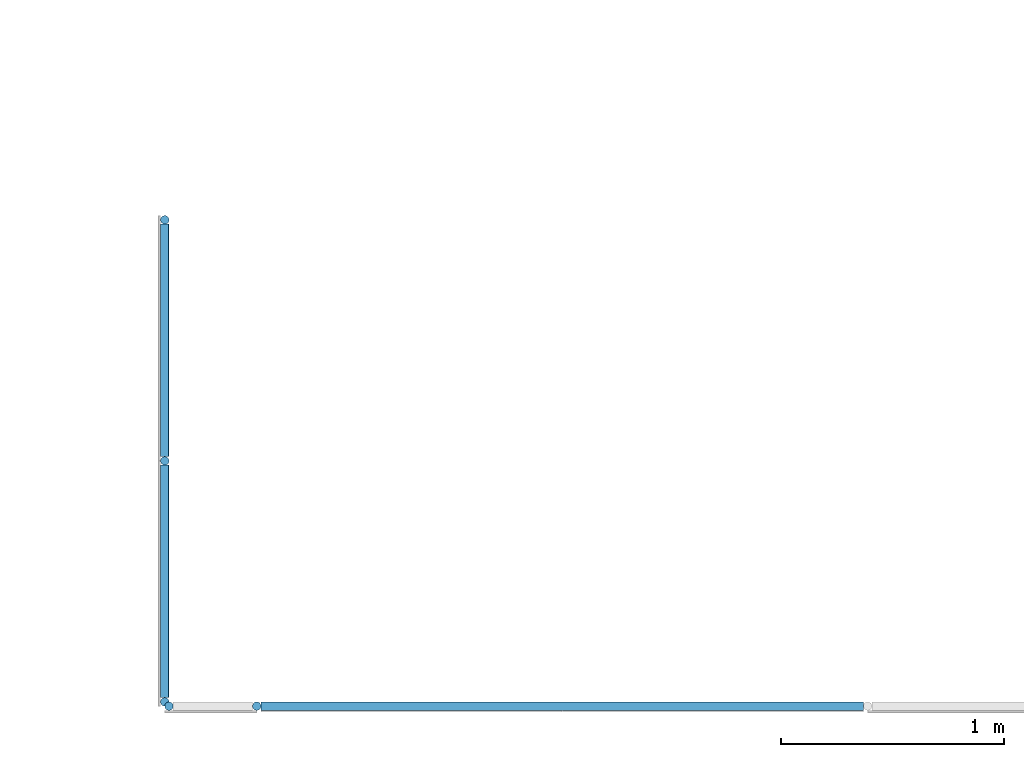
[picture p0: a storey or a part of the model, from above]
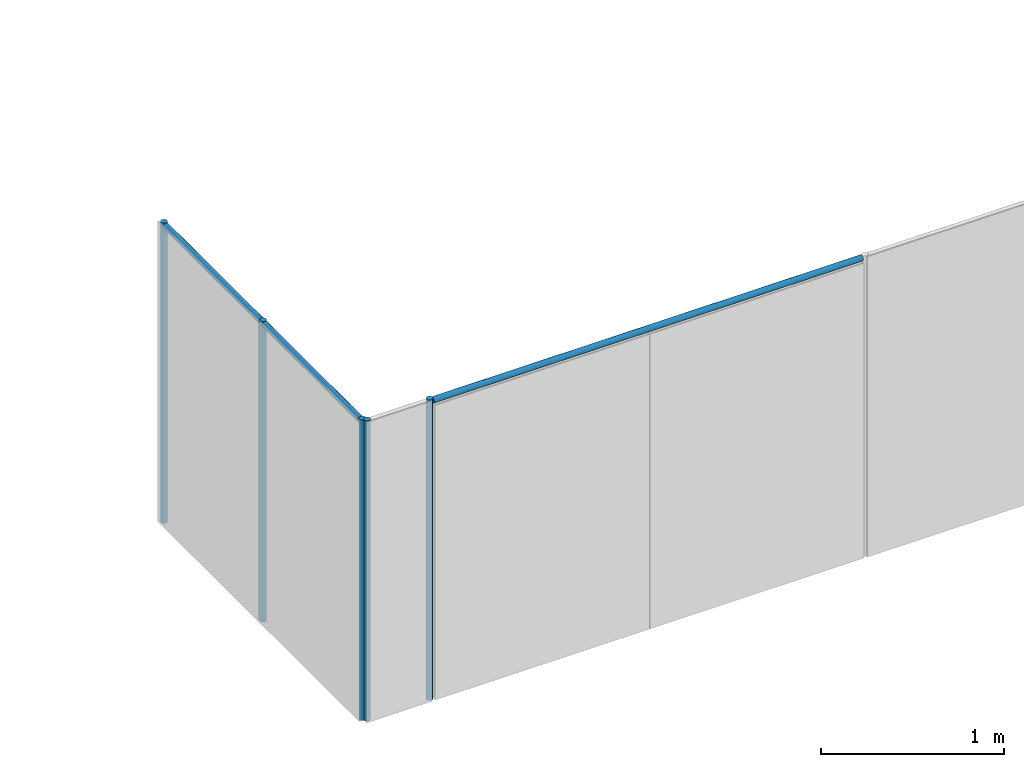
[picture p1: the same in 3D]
Properties of the parts of a building model (IFC2X3), part 11 of 11

# IfcWallStandardCase: Basic Wall:Interior - Rated 1-HR (92mm Stud):128426 (30)
PSet_Revit_Type_Graphics - Coarse Scale Fill Pattern: Solid fill; Coarse Scale Fill Color: 8421504
PSet_Revit_Type_Identity Data - Manufacturer: Manufacturer; Fire Rating: 1 HR
PSet_Revit_Type_Other - AccessibilityPerformance: AccessibilityPerformance; CodePerformance: CodePerformance; Color: Color; Constituents: Constituents; Features: Features; Finish: Finish; Grade: Grade; Material: Material; ModelReference: ModelReference; NominalHeight: NominalHeight; NominalLength: NominalLength; NominalWidth: NominalWidth; ProductionYear: ProductionYear; Reference: Reference; Shape: Shape; Size: Size; SustainabilityPerformance: SustainabilityPerformance; WarrantyDescription: WarrantyDescription; WarrantyDurationLabor: WarrantyDurationLabor; WarrantyDurationParts: WarrantyDurationParts; WarrantyGuarantorLabor: WarrantyGuarantorLabor; WarrantyGuarantorParts: WarrantyGuarantorParts; ExpectedLife: ExpectedLife; ReplacementCost: ReplacementCost; AssetAccountingType: FIXED; Classification Code: 23-25 40 11 11 11; Classification Description: Metal-Framed Gypsum Board Fixed Partitions; ModelLabel: ModelLabel
Name (Basic Wall:Interior - Rated 1-HR (92mm Stud):...) | In | Length (m) | Area (m2) | Volume (m3) | Base Constraint | Top Constraint | Unconnected Height (m) | Top Offset (m)
150741 | First Floor | 5.799 | 25.3559 | 3.14413 | First Floor | Up to level: Second Floor | 4.468 | -0.102
384656 | Second Floor | 6.156 | 28.466 | 3.52978 | Second Floor | Up to level: Roof - Main | 4.578 | -0.102
191306 | Second Floor | 1.694 | 6.37019 | 0.789904 | Second Floor | Up to level: Roof - Main | 4.578 | -0.102
182976 | First Floor | 2.3692 | 8.63426 | 1.07065 | First Floor | Up to level: Second Floor | 4.468 | -0.102
150101 | First Floor | 4.205 | 18.7879 | 2.3297 | First Floor | Up to level: Second Floor | 4.468 | -0.102
207426 | Second Floor | 2.9245 | 10.5408 | 1.30705 | Second Floor | Up to level: Roof - Main | 4.578 | -0.102
181424 | First Floor | 6.156 | 28.1329 | 3.48848 | First Floor | Up to level: Second Floor | 4.57 | 0
368590 | First Floor | 1.8385 | 7.66039 | 0.949888 | First Floor | Up to level: Second Floor | 4.468 | -0.102
182600 | First Floor | 2.3692 | 11.1396 | 1.38131 | First Floor | Up to level: Second Floor | 4.468 | -0.102
207318 | Second Floor | 2.9245 | 12.4934 | 1.54918 | Second Floor | Up to level: Roof - Main | 4.578 | -0.102
150462 | First Floor | 1.594 | 4.13647 | 0.512922 | First Floor | Up to level: Second Floor | 3.82 | -0.75
202564 | Second Floor | 2.3592 | 8.28142 | 1.0269 | Second Floor | Up to level: Roof - Main | 4.578 | -0.102
181598 | First Floor | 2.9245 | 12.4715 | 1.54647 | First Floor | Up to level: Second Floor | 4.57 | 0
181343 | First Floor | 2.9245 | 10.7946 | 1.33853 | First Floor | Up to level: Second Floor | 4.468 | -0.102
150598 | First Floor | 2.015 | 9.0432 | 1.12136 | First Floor | Up to level: Second Floor | 4.468 | -0.102
202370 | Second Floor | 2.3592 | 11.3681 | 1.40964 | Second Floor | Up to level: Roof - Main | 4.578 | -0.102
204955 | Second Floor | 1.8385 | 8.04465 | 0.997537 | Second Floor | Up to level: Roof - Main | 4.578 | -0.102
150201 | First Floor | 1.199 | 4.58018 | 0.567942 | First Floor | Up to level: Second Floor | 3.82 | -0.75
182913 | First Floor | 1.8385 | 8.21442 | 1.01859 | First Floor | Up to level: Second Floor | 4.468 | -0.102
190765 | Second Floor | 6.175 | 27.5412 | 3.41511 | Second Floor | Up to level: Roof - Main | 4.578 | -0.102
150014 | First Floor | 2.544 | 11.9206 | 1.47816 | First Floor | Up to level: Second Floor | 4.468 | -0.102
164254 | First Floor | 0.8045 | 3.27504 | 0.406105 | First Floor | Up to level: Second Floor | 4.468 | -0.102
164366 | First Floor | 0.8045 | 2.72101 | 0.337405 | First Floor | Up to level: Second Floor | 4.468 | -0.102
164331 | First Floor | 2.8458 | 12.715 | 1.57666 | First Floor | Up to level: Second Floor | 4.468 | -0.102
190934 | Second Floor | 0.360001 | 1.64808 | 0.204362 | Second Floor | Up to level: Roof - Main | 4.578 | -0.102
202408 | Second Floor | 1.8385 | 8.41665 | 1.04366 | Second Floor | Up to level: Roof - Main | 4.578 | -0.102
190897 | Second Floor | 0.983999 | 3.93707 | 0.488197 | Second Floor | Up to level: Roof - Main | 4.578 | -0.102
190644 | Second Floor | 2.544 | 11.6464 | 1.44416 | Second Floor | Up to level: Roof - Main | 4.578 | -0.102
190562 | Second Floor | 5.78 | 27.0285 | 3.35153 | Second Floor | Up to level: Roof - Main | 4.578 | -0.102
150384 | First Floor | 0.485 | 1.61586 | 0.200367 | First Floor | Up to level: Second Floor | 3.82 | -0.75

# IfcWallStandardCase: Basic Wall:Interior - Toilet Partition (25mm):128491 (10)
Material: Laminate - Ivory, Matte 0.025 m
PSet_Revit_Structural - Structural Usage: 0
PSet_Revit_Constraints - Location Line: 2; Base is Attached: no; Base Extension Distance: 0 m; Top is Attached: no; Top Extension Distance: 0 m; Room Bounding: no; Related to Mass: no
PSet_Revit_Phasing - Phase Created: New Construction
PSet_Revit_Other - InstallationDate: InstallationDate; SerialNumber: SerialNumber; WarrantyStartDate: WarrantyStartDate; BarCode: BarCode; AssetIdentifier: AssetIdentifier; TagNumber: TagNumber
Pset_WallCommon - Reference: Basic Wall:Interior - Toilet Partition (25mm); LoadBearing: no; ExtendToStructure: no; IsExternal: no; FireRating: 2 HR
PSet_Revit_Type_Construction - Wrapping at Inserts: 0; Wrapping at Ends: 0; Width: 0.025 m; Function: 0
PSet_Revit_Type_Graphics - Coarse Scale Fill Color: 0
PSet_Revit_Type_Identity Data - Manufacturer: Manufacturer; Fire Rating: 2 HR
PSet_Revit_Type_Other - AccessibilityPerformance: AccessibilityPerformance; CodePerformance: CodePerformance; Color: Color; Constituents: Constituents; Features: Features; Finish: Finish; Grade: Grade; Material: Material; ModelReference: ModelReference; NominalHeight: NominalHeight; NominalLength: NominalLength; NominalWidth: NominalWidth; ProductionYear: ProductionYear; Reference: Reference; Shape: Shape; Size: Size; SustainabilityPerformance: SustainabilityPerformance; WarrantyDescription: WarrantyDescription; WarrantyDurationLabor: WarrantyDurationLabor; WarrantyDurationParts: WarrantyDurationParts; WarrantyGuarantorLabor: WarrantyGuarantorLabor; WarrantyGuarantorParts: WarrantyGuarantorParts; ExpectedLife: ExpectedLife; ReplacementCost: ReplacementCost; AssetAccountingType: FIXED; Classification Code: 23-25 40 14 14 11 11; Classification Description: Metal Toilet Compartments and Urinal Screens; ModelLabel: ModelLabel
Name (Basic Wall:Interior - Toilet Partition (25mm):...) | In | Base Constraint | Base Offset (m) | Top Constraint | Unconnected Height (m) | Top Offset (m) | Length (m) | Area (m2) | Volume (m3)
412884 | Second Floor | Second Floor | 0.25 | Up to level: Second Floor | 1.5 | 1.75 | 0.159585 | 0.258128 | 0.0064532
413112 | Second Floor | Second Floor | 0.25 | Up to level: Second Floor | 1.5 | 1.75 | 2.95609 | 1.65313 | 0.0413282
411446 | First Floor | First Floor | 0.25 | Up to level: First Floor | 1.5 | 1.75 | 3.1945 | 1.9035 | 0.0475875
409027 | Second Floor | Second Floor | 0 | Up to level: Roof - Main | 4.578 | -0.102 | 1.544 | 5.4871 | 0.137177
412921 | Second Floor | Second Floor | 0.25 | Up to level: Second Floor | 1.5 | 1.75 | 1.5745 | 0.907498 | 0.0226875
412768 | First Floor | First Floor | 0.25 | Up to level: First Floor | 1.5 | 1.75 | 1.5655 | 0.976501 | 0.0244125
412769 | First Floor | First Floor | 0.25 | Up to level: First Floor | 1.5 | 1.75 | 1.5715 | 2.2125 | 0.0553125
411532 | First Floor | First Floor | 0.25 | Up to level: First Floor | 1.5 | 1.75 | 1.5715 | 2.2125 | 0.0553125
413182 | Second Floor | Second Floor | 0.25 | Up to level: Second Floor | 1.5 | 1.75 | 1.6295 | 2.2875 | 0.0571875
408771 | Second Floor | Second Floor | 0 | Up to level: Roof - Main | 4.578 | -0.102 | 1.79 | 6.89712 | 0.172428

# IfcWindow: 1735 x 1000mm (58)
Type - ParameterTakesPrecedence: no; Sizeable: no
OverallHeight: 1.735 m; OverallWidth: 1 m
Pset_WindowCommon - Reference: M_Fixed:1735 x 1000mm; IsExternal: yes; FireRating: FireRating
PSet_Revit_Phasing - Phase Created: New Construction
PSet_Revit_Constraints - Sill Height: 0.905 m
PSet_Revit_Other - Head Height: 2.64 m; InstallationDate: InstallationDate; SerialNumber: SerialNumber; WarrantyStartDate: WarrantyStartDate; BarCode: BarCode; AssetIdentifier: AssetIdentifier; TagNumber: TagNumber
PSet_Revit_Type_Other - AccessibilityPerformance: AccessibilityPerformance; CodePerformance: CodePerformance; ConfigurationType: ConfigurationType; FireRating: FireRating; GlazingAreaFraction: GlazingAreaFraction; OperationType: OperationType; Area: Area; Color: Color; Constituents: Constituents; Features: Features; Finish: Finish; Grade: Grade; Material: Material; ModelReference: ModelReference; NominalHeight: NominalHeight; NominalLength: NominalLength; NominalWidth: NominalWidth; ProductionYear: ProductionYear; Reference: Reference; Shape: Shape; Size: Size; SustainabilityPerformance: SustainabilityPerformance; WarrantyDescription: WarrantyDescription; WarrantyDurationLabor: WarrantyDurationLabor; WarrantyDurationParts: WarrantyDurationParts; WarrantyGuarantorLabor: WarrantyGuarantorLabor; WarrantyGuarantorParts: WarrantyGuarantorParts; ExpectedLife: ExpectedLife; ReplacementCost: ReplacementCost; AssetAccountingType: FIXED; ModelLabel: ModelLabel
PSet_Revit_Type_Materials and Finishes - Frame Exterior Material: Sash; Frame Interior Material: Sash; Glass Pane Material: Glass; Sash: Sash
PSet_Revit_Type_Identity Data - Manufacturer: Manufacturer; Type Mark: 19; OmniClass Number: 23.30.20.17.11; OmniClass Title: Fixed Windows
PSet_Revit_Type_Construction - Wall Closure: 0; Construction Type: Construction Type
PSet_Revit_Type_Dimensions - Height: 1.735 m; Default Sill Height: 0.915 m; Width: 1 m; Window Inset: 0.019 m
Name (M_Fixed:1735 x 1000mm:1735 x 1000mm:...) | In | Mark | Level
259285 | Second Floor | 32 | Second Floor
261584 | Second Floor | 56 | Second Floor
259348 | Second Floor | 33 | Second Floor
261527 | Second Floor | 55 | Second Floor
261484 | Second Floor | 54 | Second Floor
261427 | Second Floor | 53 | Second Floor
259543 | Second Floor | 34 | Second Floor
261994 | Second Floor | 62 | Second Floor
261760 | Second Floor | 58 | Second Floor
262643 | Second Floor | 67 | Second Floor
262496 | Second Floor | 65 | Second Floor
261637 | Second Floor | 57 | Second Floor
261827 | Second Floor | 59 | Second Floor
261927 | Second Floor | 61 | Second Floor
262576 | Second Floor | 66 | Second Floor
262059 | Second Floor | 63 | Second Floor
262138 | Second Floor | 64 | Second Floor
261874 | Second Floor | 60 | Second Floor
254752 | First Floor | 25 | First Floor
254940 | First Floor | 27 | First Floor
254583 | First Floor | 22 | First Floor
255048 | First Floor | 29 | First Floor
254526 | First Floor | 21 | First Floor
254683 | First Floor | 24 | First Floor
254989 | First Floor | 28 | First Floor
254638 | First Floor | 23 | First Floor
259767 | Second Floor | 36 | Second Floor
253704 | First Floor | 11 | First Floor
254221 | First Floor | 16 | First Floor
260974 | Second Floor | 46 | Second Floor
253076 | First Floor | 8 | First Floor
253332 | First Floor | 9 | First Floor
254479 | First Floor | 20 | First Floor
259606 | Second Floor | 35 | Second Floor
260595 | Second Floor | 43 | Second Floor
259922 | Second Floor | 37 | Second Floor
261220 | Second Floor | 50 | Second Floor
253561 | First Floor | 10 | First Floor
254843 | First Floor | 26 | First Floor
253943 | First Floor | 12 | First Floor
254105 | First Floor | 14 | First Floor
260236 | Second Floor | 40 | Second Floor
254294 | First Floor | 17 | First Floor
254052 | First Floor | 13 | First Floor
260833 | Second Floor | 45 | Second Floor
260209 | Second Floor | 39 | Second Floor
261370 | Second Floor | 52 | Second Floor
254424 | First Floor | 19 | First Floor
260452 | Second Floor | 42 | Second Floor
261267 | Second Floor | 51 | Second Floor
260343 | Second Floor | 41 | Second Floor
261025 | Second Floor | 47 | Second Floor
260718 | Second Floor | 44 | Second Floor
254158 | First Floor | 15 | First Floor
260015 | Second Floor | 38 | Second Floor
254345 | First Floor | 18 | First Floor
261135 | Second Floor | 49 | Second Floor
261080 | Second Floor | 48 | Second Floor
